VERSION 5.8 ;
BUSBITCHARS "[]" ;
DIVIDERCHAR "/" ;
UNITS
    DATABASE MICRONS 1000 ;
END UNITS

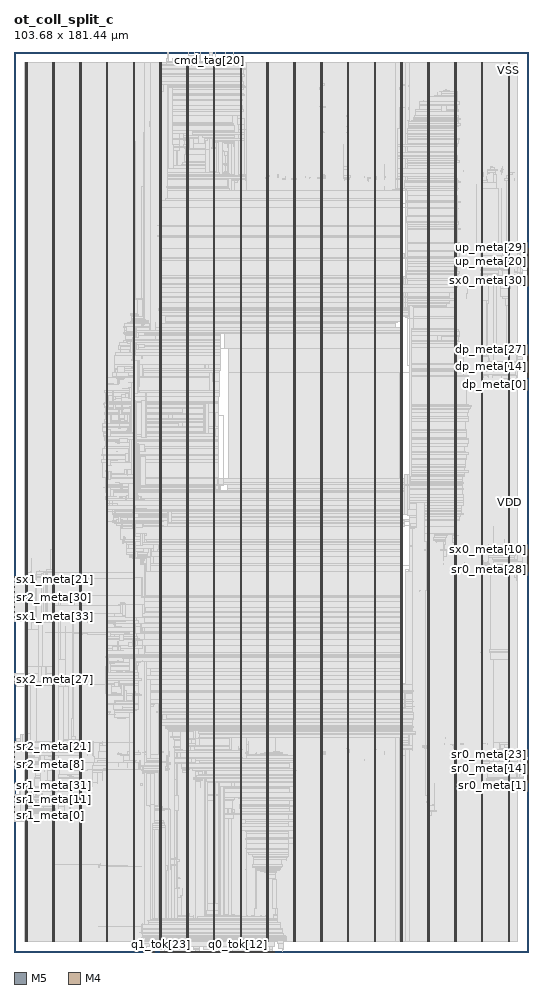
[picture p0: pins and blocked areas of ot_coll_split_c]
MACRO ot_coll_split_c
  FOREIGN ot_coll_split_c 0 0 ;
  CLASS BLOCK ;
  SIZE 103.68 BY 181.44 ;
  PIN clk
    DIRECTION INPUT ;
    USE SIGNAL ;
    PORT
      LAYER M5 ;
        RECT  36.144 181.356 36.168 181.44 ;
    END
  END clk
  PIN cmd_free
    DIRECTION OUTPUT ;
    USE SIGNAL ;
    PORT
      LAYER M5 ;
        RECT  36.288 181.356 36.312 181.44 ;
    END
  END cmd_free
  PIN cmd_mode
    DIRECTION INPUT ;
    USE SIGNAL ;
    PORT
      LAYER M5 ;
        RECT  36.432 181.356 36.456 181.44 ;
    END
  END cmd_mode
  PIN cmd_tag[0]
    DIRECTION INPUT ;
    USE SIGNAL ;
    PORT
      LAYER M5 ;
        RECT  36.576 181.356 36.6 181.44 ;
    END
  END cmd_tag[0]
  PIN cmd_tag[10]
    DIRECTION INPUT ;
    USE SIGNAL ;
    PORT
      LAYER M5 ;
        RECT  38.016 181.356 38.04 181.44 ;
    END
  END cmd_tag[10]
  PIN cmd_tag[11]
    DIRECTION INPUT ;
    USE SIGNAL ;
    PORT
      LAYER M5 ;
        RECT  38.16 181.356 38.184 181.44 ;
    END
  END cmd_tag[11]
  PIN cmd_tag[12]
    DIRECTION INPUT ;
    USE SIGNAL ;
    PORT
      LAYER M5 ;
        RECT  38.304 181.356 38.328 181.44 ;
    END
  END cmd_tag[12]
  PIN cmd_tag[13]
    DIRECTION INPUT ;
    USE SIGNAL ;
    PORT
      LAYER M5 ;
        RECT  38.448 181.356 38.472 181.44 ;
    END
  END cmd_tag[13]
  PIN cmd_tag[14]
    DIRECTION INPUT ;
    USE SIGNAL ;
    PORT
      LAYER M5 ;
        RECT  38.592 181.356 38.616 181.44 ;
    END
  END cmd_tag[14]
  PIN cmd_tag[15]
    DIRECTION INPUT ;
    USE SIGNAL ;
    PORT
      LAYER M5 ;
        RECT  38.736 181.356 38.76 181.44 ;
    END
  END cmd_tag[15]
  PIN cmd_tag[16]
    DIRECTION INPUT ;
    USE SIGNAL ;
    PORT
      LAYER M5 ;
        RECT  38.88 181.356 38.904 181.44 ;
    END
  END cmd_tag[16]
  PIN cmd_tag[17]
    DIRECTION INPUT ;
    USE SIGNAL ;
    PORT
      LAYER M5 ;
        RECT  39.024 181.356 39.048 181.44 ;
    END
  END cmd_tag[17]
  PIN cmd_tag[18]
    DIRECTION INPUT ;
    USE SIGNAL ;
    PORT
      LAYER M5 ;
        RECT  39.168 181.356 39.192 181.44 ;
    END
  END cmd_tag[18]
  PIN cmd_tag[19]
    DIRECTION INPUT ;
    USE SIGNAL ;
    PORT
      LAYER M5 ;
        RECT  39.312 181.356 39.336 181.44 ;
    END
  END cmd_tag[19]
  PIN cmd_tag[1]
    DIRECTION INPUT ;
    USE SIGNAL ;
    PORT
      LAYER M5 ;
        RECT  36.72 181.356 36.744 181.44 ;
    END
  END cmd_tag[1]
  PIN cmd_tag[20]
    DIRECTION INPUT ;
    USE SIGNAL ;
    PORT
      LAYER M5 ;
        RECT  39.456 181.356 39.48 181.44 ;
    END
  END cmd_tag[20]
  PIN cmd_tag[21]
    DIRECTION INPUT ;
    USE SIGNAL ;
    PORT
      LAYER M5 ;
        RECT  39.6 181.356 39.624 181.44 ;
    END
  END cmd_tag[21]
  PIN cmd_tag[22]
    DIRECTION INPUT ;
    USE SIGNAL ;
    PORT
      LAYER M5 ;
        RECT  39.744 181.356 39.768 181.44 ;
    END
  END cmd_tag[22]
  PIN cmd_tag[23]
    DIRECTION INPUT ;
    USE SIGNAL ;
    PORT
      LAYER M5 ;
        RECT  39.888 181.356 39.912 181.44 ;
    END
  END cmd_tag[23]
  PIN cmd_tag[24]
    DIRECTION INPUT ;
    USE SIGNAL ;
    PORT
      LAYER M5 ;
        RECT  40.032 181.356 40.056 181.44 ;
    END
  END cmd_tag[24]
  PIN cmd_tag[25]
    DIRECTION INPUT ;
    USE SIGNAL ;
    PORT
      LAYER M5 ;
        RECT  40.176 181.356 40.2 181.44 ;
    END
  END cmd_tag[25]
  PIN cmd_tag[26]
    DIRECTION INPUT ;
    USE SIGNAL ;
    PORT
      LAYER M5 ;
        RECT  40.32 181.356 40.344 181.44 ;
    END
  END cmd_tag[26]
  PIN cmd_tag[27]
    DIRECTION INPUT ;
    USE SIGNAL ;
    PORT
      LAYER M5 ;
        RECT  40.464 181.356 40.488 181.44 ;
    END
  END cmd_tag[27]
  PIN cmd_tag[28]
    DIRECTION INPUT ;
    USE SIGNAL ;
    PORT
      LAYER M5 ;
        RECT  40.608 181.356 40.632 181.44 ;
    END
  END cmd_tag[28]
  PIN cmd_tag[29]
    DIRECTION INPUT ;
    USE SIGNAL ;
    PORT
      LAYER M5 ;
        RECT  31.536 181.356 31.56 181.44 ;
    END
  END cmd_tag[29]
  PIN cmd_tag[2]
    DIRECTION INPUT ;
    USE SIGNAL ;
    PORT
      LAYER M5 ;
        RECT  36.864 181.356 36.888 181.44 ;
    END
  END cmd_tag[2]
  PIN cmd_tag[30]
    DIRECTION INPUT ;
    USE SIGNAL ;
    PORT
      LAYER M5 ;
        RECT  31.68 181.356 31.704 181.44 ;
    END
  END cmd_tag[30]
  PIN cmd_tag[31]
    DIRECTION INPUT ;
    USE SIGNAL ;
    PORT
      LAYER M5 ;
        RECT  31.824 181.356 31.848 181.44 ;
    END
  END cmd_tag[31]
  PIN cmd_tag[3]
    DIRECTION INPUT ;
    USE SIGNAL ;
    PORT
      LAYER M5 ;
        RECT  37.008 181.356 37.032 181.44 ;
    END
  END cmd_tag[3]
  PIN cmd_tag[4]
    DIRECTION INPUT ;
    USE SIGNAL ;
    PORT
      LAYER M5 ;
        RECT  37.152 181.356 37.176 181.44 ;
    END
  END cmd_tag[4]
  PIN cmd_tag[5]
    DIRECTION INPUT ;
    USE SIGNAL ;
    PORT
      LAYER M5 ;
        RECT  37.296 181.356 37.32 181.44 ;
    END
  END cmd_tag[5]
  PIN cmd_tag[6]
    DIRECTION INPUT ;
    USE SIGNAL ;
    PORT
      LAYER M5 ;
        RECT  37.44 181.356 37.464 181.44 ;
    END
  END cmd_tag[6]
  PIN cmd_tag[7]
    DIRECTION INPUT ;
    USE SIGNAL ;
    PORT
      LAYER M5 ;
        RECT  37.584 181.356 37.608 181.44 ;
    END
  END cmd_tag[7]
  PIN cmd_tag[8]
    DIRECTION INPUT ;
    USE SIGNAL ;
    PORT
      LAYER M5 ;
        RECT  37.728 181.356 37.752 181.44 ;
    END
  END cmd_tag[8]
  PIN cmd_tag[9]
    DIRECTION INPUT ;
    USE SIGNAL ;
    PORT
      LAYER M5 ;
        RECT  37.872 181.356 37.896 181.44 ;
    END
  END cmd_tag[9]
  PIN cmd_v
    DIRECTION INPUT ;
    USE SIGNAL ;
    PORT
      LAYER M5 ;
        RECT  31.968 181.356 31.992 181.44 ;
    END
  END cmd_v
  PIN cmd_words[0]
    DIRECTION INPUT ;
    USE SIGNAL ;
    PORT
      LAYER M5 ;
        RECT  32.112 181.356 32.136 181.44 ;
    END
  END cmd_words[0]
  PIN cmd_words[10]
    DIRECTION INPUT ;
    USE SIGNAL ;
    PORT
      LAYER M5 ;
        RECT  33.552 181.356 33.576 181.44 ;
    END
  END cmd_words[10]
  PIN cmd_words[11]
    DIRECTION INPUT ;
    USE SIGNAL ;
    PORT
      LAYER M5 ;
        RECT  33.696 181.356 33.72 181.44 ;
    END
  END cmd_words[11]
  PIN cmd_words[12]
    DIRECTION INPUT ;
    USE SIGNAL ;
    PORT
      LAYER M5 ;
        RECT  33.84 181.356 33.864 181.44 ;
    END
  END cmd_words[12]
  PIN cmd_words[13]
    DIRECTION INPUT ;
    USE SIGNAL ;
    PORT
      LAYER M5 ;
        RECT  33.984 181.356 34.008 181.44 ;
    END
  END cmd_words[13]
  PIN cmd_words[14]
    DIRECTION INPUT ;
    USE SIGNAL ;
    PORT
      LAYER M5 ;
        RECT  34.128 181.356 34.152 181.44 ;
    END
  END cmd_words[14]
  PIN cmd_words[15]
    DIRECTION INPUT ;
    USE SIGNAL ;
    PORT
      LAYER M5 ;
        RECT  34.272 181.356 34.296 181.44 ;
    END
  END cmd_words[15]
  PIN cmd_words[1]
    DIRECTION INPUT ;
    USE SIGNAL ;
    PORT
      LAYER M5 ;
        RECT  32.256 181.356 32.28 181.44 ;
    END
  END cmd_words[1]
  PIN cmd_words[2]
    DIRECTION INPUT ;
    USE SIGNAL ;
    PORT
      LAYER M5 ;
        RECT  32.4 181.356 32.424 181.44 ;
    END
  END cmd_words[2]
  PIN cmd_words[3]
    DIRECTION INPUT ;
    USE SIGNAL ;
    PORT
      LAYER M5 ;
        RECT  32.544 181.356 32.568 181.44 ;
    END
  END cmd_words[3]
  PIN cmd_words[4]
    DIRECTION INPUT ;
    USE SIGNAL ;
    PORT
      LAYER M5 ;
        RECT  32.688 181.356 32.712 181.44 ;
    END
  END cmd_words[4]
  PIN cmd_words[5]
    DIRECTION INPUT ;
    USE SIGNAL ;
    PORT
      LAYER M5 ;
        RECT  32.832 181.356 32.856 181.44 ;
    END
  END cmd_words[5]
  PIN cmd_words[6]
    DIRECTION INPUT ;
    USE SIGNAL ;
    PORT
      LAYER M5 ;
        RECT  32.976 181.356 33 181.44 ;
    END
  END cmd_words[6]
  PIN cmd_words[7]
    DIRECTION INPUT ;
    USE SIGNAL ;
    PORT
      LAYER M5 ;
        RECT  33.12 181.356 33.144 181.44 ;
    END
  END cmd_words[7]
  PIN cmd_words[8]
    DIRECTION INPUT ;
    USE SIGNAL ;
    PORT
      LAYER M5 ;
        RECT  33.264 181.356 33.288 181.44 ;
    END
  END cmd_words[8]
  PIN cmd_words[9]
    DIRECTION INPUT ;
    USE SIGNAL ;
    PORT
      LAYER M5 ;
        RECT  33.408 181.356 33.432 181.44 ;
    END
  END cmd_words[9]
  PIN die_ps
    DIRECTION INPUT ;
    USE SIGNAL ;
    PORT
      LAYER M5 ;
        RECT  34.416 181.356 34.44 181.44 ;
    END
  END die_ps
  PIN dp_meta[0]
    DIRECTION INPUT ;
    USE SIGNAL ;
    PORT
      LAYER M4 ;
        RECT  103.596 115.92 103.68 115.944 ;
    END
  END dp_meta[0]
  PIN dp_meta[10]
    DIRECTION INPUT ;
    USE SIGNAL ;
    PORT
      LAYER M4 ;
        RECT  103.596 117.36 103.68 117.384 ;
    END
  END dp_meta[10]
  PIN dp_meta[11]
    DIRECTION INPUT ;
    USE SIGNAL ;
    PORT
      LAYER M4 ;
        RECT  103.596 117.504 103.68 117.528 ;
    END
  END dp_meta[11]
  PIN dp_meta[12]
    DIRECTION INPUT ;
    USE SIGNAL ;
    PORT
      LAYER M4 ;
        RECT  103.596 117.648 103.68 117.672 ;
    END
  END dp_meta[12]
  PIN dp_meta[13]
    DIRECTION INPUT ;
    USE SIGNAL ;
    PORT
      LAYER M4 ;
        RECT  103.596 117.792 103.68 117.816 ;
    END
  END dp_meta[13]
  PIN dp_meta[14]
    DIRECTION INPUT ;
    USE SIGNAL ;
    PORT
      LAYER M4 ;
        RECT  103.596 117.936 103.68 117.96 ;
    END
  END dp_meta[14]
  PIN dp_meta[15]
    DIRECTION INPUT ;
    USE SIGNAL ;
    PORT
      LAYER M4 ;
        RECT  103.596 118.08 103.68 118.104 ;
    END
  END dp_meta[15]
  PIN dp_meta[16]
    DIRECTION INPUT ;
    USE SIGNAL ;
    PORT
      LAYER M4 ;
        RECT  103.596 118.224 103.68 118.248 ;
    END
  END dp_meta[16]
  PIN dp_meta[17]
    DIRECTION INPUT ;
    USE SIGNAL ;
    PORT
      LAYER M4 ;
        RECT  103.596 118.368 103.68 118.392 ;
    END
  END dp_meta[17]
  PIN dp_meta[18]
    DIRECTION INPUT ;
    USE SIGNAL ;
    PORT
      LAYER M4 ;
        RECT  103.596 118.512 103.68 118.536 ;
    END
  END dp_meta[18]
  PIN dp_meta[19]
    DIRECTION INPUT ;
    USE SIGNAL ;
    PORT
      LAYER M4 ;
        RECT  103.596 118.656 103.68 118.68 ;
    END
  END dp_meta[19]
  PIN dp_meta[1]
    DIRECTION INPUT ;
    USE SIGNAL ;
    PORT
      LAYER M4 ;
        RECT  103.596 116.064 103.68 116.088 ;
    END
  END dp_meta[1]
  PIN dp_meta[20]
    DIRECTION INPUT ;
    USE SIGNAL ;
    PORT
      LAYER M4 ;
        RECT  103.596 118.8 103.68 118.824 ;
    END
  END dp_meta[20]
  PIN dp_meta[21]
    DIRECTION INPUT ;
    USE SIGNAL ;
    PORT
      LAYER M4 ;
        RECT  103.596 118.944 103.68 118.968 ;
    END
  END dp_meta[21]
  PIN dp_meta[22]
    DIRECTION INPUT ;
    USE SIGNAL ;
    PORT
      LAYER M4 ;
        RECT  103.596 119.088 103.68 119.112 ;
    END
  END dp_meta[22]
  PIN dp_meta[23]
    DIRECTION INPUT ;
    USE SIGNAL ;
    PORT
      LAYER M4 ;
        RECT  103.596 119.232 103.68 119.256 ;
    END
  END dp_meta[23]
  PIN dp_meta[24]
    DIRECTION INPUT ;
    USE SIGNAL ;
    PORT
      LAYER M4 ;
        RECT  103.596 119.376 103.68 119.4 ;
    END
  END dp_meta[24]
  PIN dp_meta[25]
    DIRECTION INPUT ;
    USE SIGNAL ;
    PORT
      LAYER M4 ;
        RECT  103.596 119.52 103.68 119.544 ;
    END
  END dp_meta[25]
  PIN dp_meta[26]
    DIRECTION INPUT ;
    USE SIGNAL ;
    PORT
      LAYER M4 ;
        RECT  103.596 119.664 103.68 119.688 ;
    END
  END dp_meta[26]
  PIN dp_meta[27]
    DIRECTION INPUT ;
    USE SIGNAL ;
    PORT
      LAYER M4 ;
        RECT  103.596 119.808 103.68 119.832 ;
    END
  END dp_meta[27]
  PIN dp_meta[28]
    DIRECTION INPUT ;
    USE SIGNAL ;
    PORT
      LAYER M4 ;
        RECT  103.596 119.952 103.68 119.976 ;
    END
  END dp_meta[28]
  PIN dp_meta[29]
    DIRECTION INPUT ;
    USE SIGNAL ;
    PORT
      LAYER M4 ;
        RECT  103.596 120.096 103.68 120.12 ;
    END
  END dp_meta[29]
  PIN dp_meta[2]
    DIRECTION INPUT ;
    USE SIGNAL ;
    PORT
      LAYER M4 ;
        RECT  103.596 116.208 103.68 116.232 ;
    END
  END dp_meta[2]
  PIN dp_meta[30]
    DIRECTION INPUT ;
    USE SIGNAL ;
    PORT
      LAYER M4 ;
        RECT  103.596 120.24 103.68 120.264 ;
    END
  END dp_meta[30]
  PIN dp_meta[31]
    DIRECTION INPUT ;
    USE SIGNAL ;
    PORT
      LAYER M4 ;
        RECT  103.596 120.384 103.68 120.408 ;
    END
  END dp_meta[31]
  PIN dp_meta[32]
    DIRECTION INPUT ;
    USE SIGNAL ;
    PORT
      LAYER M4 ;
        RECT  103.596 34.128 103.68 34.152 ;
    END
  END dp_meta[32]
  PIN dp_meta[33]
    DIRECTION INPUT ;
    USE SIGNAL ;
    PORT
      LAYER M4 ;
        RECT  103.596 34.272 103.68 34.296 ;
    END
  END dp_meta[33]
  PIN dp_meta[3]
    DIRECTION INPUT ;
    USE SIGNAL ;
    PORT
      LAYER M4 ;
        RECT  103.596 116.352 103.68 116.376 ;
    END
  END dp_meta[3]
  PIN dp_meta[4]
    DIRECTION INPUT ;
    USE SIGNAL ;
    PORT
      LAYER M4 ;
        RECT  103.596 116.496 103.68 116.52 ;
    END
  END dp_meta[4]
  PIN dp_meta[5]
    DIRECTION INPUT ;
    USE SIGNAL ;
    PORT
      LAYER M4 ;
        RECT  103.596 116.64 103.68 116.664 ;
    END
  END dp_meta[5]
  PIN dp_meta[6]
    DIRECTION INPUT ;
    USE SIGNAL ;
    PORT
      LAYER M4 ;
        RECT  103.596 116.784 103.68 116.808 ;
    END
  END dp_meta[6]
  PIN dp_meta[7]
    DIRECTION INPUT ;
    USE SIGNAL ;
    PORT
      LAYER M4 ;
        RECT  103.596 116.928 103.68 116.952 ;
    END
  END dp_meta[7]
  PIN dp_meta[8]
    DIRECTION INPUT ;
    USE SIGNAL ;
    PORT
      LAYER M4 ;
        RECT  103.596 117.072 103.68 117.096 ;
    END
  END dp_meta[8]
  PIN dp_meta[9]
    DIRECTION INPUT ;
    USE SIGNAL ;
    PORT
      LAYER M4 ;
        RECT  103.596 117.216 103.68 117.24 ;
    END
  END dp_meta[9]
  PIN dp_valid
    DIRECTION INPUT ;
    USE SIGNAL ;
    PORT
      LAYER M4 ;
        RECT  103.596 34.416 103.68 34.44 ;
    END
  END dp_valid
  PIN dr_meta[0]
    DIRECTION INPUT ;
    USE SIGNAL ;
    PORT
      LAYER M4 ;
        RECT  103.596 34.56 103.68 34.584 ;
    END
  END dr_meta[0]
  PIN dr_meta[1]
    DIRECTION INPUT ;
    USE SIGNAL ;
    PORT
      LAYER M4 ;
        RECT  103.596 34.704 103.68 34.728 ;
    END
  END dr_meta[1]
  PIN dr_valid
    DIRECTION INPUT ;
    USE SIGNAL ;
    PORT
      LAYER M4 ;
        RECT  103.596 34.848 103.68 34.872 ;
    END
  END dr_valid
  PIN fault
    DIRECTION OUTPUT ;
    USE SIGNAL ;
    PORT
      LAYER M5 ;
        RECT  34.56 181.356 34.584 181.44 ;
    END
  END fault
  PIN fault_code[0]
    DIRECTION OUTPUT ;
    USE SIGNAL ;
    PORT
      LAYER M5 ;
        RECT  34.704 181.356 34.728 181.44 ;
    END
  END fault_code[0]
  PIN fault_code[1]
    DIRECTION OUTPUT ;
    USE SIGNAL ;
    PORT
      LAYER M5 ;
        RECT  34.848 181.356 34.872 181.44 ;
    END
  END fault_code[1]
  PIN fault_code[2]
    DIRECTION OUTPUT ;
    USE SIGNAL ;
    PORT
      LAYER M5 ;
        RECT  34.992 181.356 35.016 181.44 ;
    END
  END fault_code[2]
  PIN fault_code[3]
    DIRECTION OUTPUT ;
    USE SIGNAL ;
    PORT
      LAYER M5 ;
        RECT  35.136 181.356 35.16 181.44 ;
    END
  END fault_code[3]
  PIN fault_code[4]
    DIRECTION OUTPUT ;
    USE SIGNAL ;
    PORT
      LAYER M5 ;
        RECT  35.28 181.356 35.304 181.44 ;
    END
  END fault_code[4]
  PIN in_last
    DIRECTION INPUT ;
    USE SIGNAL ;
    PORT
      LAYER M5 ;
        RECT  35.424 181.356 35.448 181.44 ;
    END
  END in_last
  PIN in_mode
    DIRECTION INPUT ;
    USE SIGNAL ;
    PORT
      LAYER M5 ;
        RECT  35.568 181.356 35.592 181.44 ;
    END
  END in_mode
  PIN in_tag[0]
    DIRECTION INPUT ;
    USE SIGNAL ;
    PORT
      LAYER M5 ;
        RECT  35.712 181.356 35.736 181.44 ;
    END
  END in_tag[0]
  PIN in_tag[10]
    DIRECTION INPUT ;
    USE SIGNAL ;
    PORT
      LAYER M5 ;
        RECT  41.76 181.356 41.784 181.44 ;
    END
  END in_tag[10]
  PIN in_tag[11]
    DIRECTION INPUT ;
    USE SIGNAL ;
    PORT
      LAYER M5 ;
        RECT  41.904 181.356 41.928 181.44 ;
    END
  END in_tag[11]
  PIN in_tag[12]
    DIRECTION INPUT ;
    USE SIGNAL ;
    PORT
      LAYER M5 ;
        RECT  42.048 181.356 42.072 181.44 ;
    END
  END in_tag[12]
  PIN in_tag[13]
    DIRECTION INPUT ;
    USE SIGNAL ;
    PORT
      LAYER M5 ;
        RECT  42.192 181.356 42.216 181.44 ;
    END
  END in_tag[13]
  PIN in_tag[14]
    DIRECTION INPUT ;
    USE SIGNAL ;
    PORT
      LAYER M5 ;
        RECT  42.336 181.356 42.36 181.44 ;
    END
  END in_tag[14]
  PIN in_tag[15]
    DIRECTION INPUT ;
    USE SIGNAL ;
    PORT
      LAYER M5 ;
        RECT  42.48 181.356 42.504 181.44 ;
    END
  END in_tag[15]
  PIN in_tag[16]
    DIRECTION INPUT ;
    USE SIGNAL ;
    PORT
      LAYER M5 ;
        RECT  42.624 181.356 42.648 181.44 ;
    END
  END in_tag[16]
  PIN in_tag[17]
    DIRECTION INPUT ;
    USE SIGNAL ;
    PORT
      LAYER M5 ;
        RECT  42.768 181.356 42.792 181.44 ;
    END
  END in_tag[17]
  PIN in_tag[18]
    DIRECTION INPUT ;
    USE SIGNAL ;
    PORT
      LAYER M5 ;
        RECT  42.912 181.356 42.936 181.44 ;
    END
  END in_tag[18]
  PIN in_tag[19]
    DIRECTION INPUT ;
    USE SIGNAL ;
    PORT
      LAYER M5 ;
        RECT  43.056 181.356 43.08 181.44 ;
    END
  END in_tag[19]
  PIN in_tag[1]
    DIRECTION INPUT ;
    USE SIGNAL ;
    PORT
      LAYER M5 ;
        RECT  35.856 181.356 35.88 181.44 ;
    END
  END in_tag[1]
  PIN in_tag[20]
    DIRECTION INPUT ;
    USE SIGNAL ;
    PORT
      LAYER M5 ;
        RECT  43.2 181.356 43.224 181.44 ;
    END
  END in_tag[20]
  PIN in_tag[21]
    DIRECTION INPUT ;
    USE SIGNAL ;
    PORT
      LAYER M5 ;
        RECT  43.344 181.356 43.368 181.44 ;
    END
  END in_tag[21]
  PIN in_tag[22]
    DIRECTION INPUT ;
    USE SIGNAL ;
    PORT
      LAYER M5 ;
        RECT  43.488 181.356 43.512 181.44 ;
    END
  END in_tag[22]
  PIN in_tag[23]
    DIRECTION INPUT ;
    USE SIGNAL ;
    PORT
      LAYER M5 ;
        RECT  43.632 181.356 43.656 181.44 ;
    END
  END in_tag[23]
  PIN in_tag[24]
    DIRECTION INPUT ;
    USE SIGNAL ;
    PORT
      LAYER M5 ;
        RECT  43.776 181.356 43.8 181.44 ;
    END
  END in_tag[24]
  PIN in_tag[25]
    DIRECTION INPUT ;
    USE SIGNAL ;
    PORT
      LAYER M5 ;
        RECT  43.92 181.356 43.944 181.44 ;
    END
  END in_tag[25]
  PIN in_tag[26]
    DIRECTION INPUT ;
    USE SIGNAL ;
    PORT
      LAYER M5 ;
        RECT  44.064 181.356 44.088 181.44 ;
    END
  END in_tag[26]
  PIN in_tag[27]
    DIRECTION INPUT ;
    USE SIGNAL ;
    PORT
      LAYER M5 ;
        RECT  44.208 181.356 44.232 181.44 ;
    END
  END in_tag[27]
  PIN in_tag[28]
    DIRECTION INPUT ;
    USE SIGNAL ;
    PORT
      LAYER M5 ;
        RECT  44.352 181.356 44.376 181.44 ;
    END
  END in_tag[28]
  PIN in_tag[29]
    DIRECTION INPUT ;
    USE SIGNAL ;
    PORT
      LAYER M5 ;
        RECT  44.496 181.356 44.52 181.44 ;
    END
  END in_tag[29]
  PIN in_tag[2]
    DIRECTION INPUT ;
    USE SIGNAL ;
    PORT
      LAYER M5 ;
        RECT  36 181.356 36.024 181.44 ;
    END
  END in_tag[2]
  PIN in_tag[30]
    DIRECTION INPUT ;
    USE SIGNAL ;
    PORT
      LAYER M5 ;
        RECT  44.64 181.356 44.664 181.44 ;
    END
  END in_tag[30]
  PIN in_tag[31]
    DIRECTION INPUT ;
    USE SIGNAL ;
    PORT
      LAYER M5 ;
        RECT  44.784 181.356 44.808 181.44 ;
    END
  END in_tag[31]
  PIN in_tag[3]
    DIRECTION INPUT ;
    USE SIGNAL ;
    PORT
      LAYER M5 ;
        RECT  40.752 181.356 40.776 181.44 ;
    END
  END in_tag[3]
  PIN in_tag[4]
    DIRECTION INPUT ;
    USE SIGNAL ;
    PORT
      LAYER M5 ;
        RECT  40.896 181.356 40.92 181.44 ;
    END
  END in_tag[4]
  PIN in_tag[5]
    DIRECTION INPUT ;
    USE SIGNAL ;
    PORT
      LAYER M5 ;
        RECT  41.04 181.356 41.064 181.44 ;
    END
  END in_tag[5]
  PIN in_tag[6]
    DIRECTION INPUT ;
    USE SIGNAL ;
    PORT
      LAYER M5 ;
        RECT  41.184 181.356 41.208 181.44 ;
    END
  END in_tag[6]
  PIN in_tag[7]
    DIRECTION INPUT ;
    USE SIGNAL ;
    PORT
      LAYER M5 ;
        RECT  41.328 181.356 41.352 181.44 ;
    END
  END in_tag[7]
  PIN in_tag[8]
    DIRECTION INPUT ;
    USE SIGNAL ;
    PORT
      LAYER M5 ;
        RECT  41.472 181.356 41.496 181.44 ;
    END
  END in_tag[8]
  PIN in_tag[9]
    DIRECTION INPUT ;
    USE SIGNAL ;
    PORT
      LAYER M5 ;
        RECT  41.616 181.356 41.64 181.44 ;
    END
  END in_tag[9]
  PIN in_valid
    DIRECTION INPUT ;
    USE SIGNAL ;
    PORT
      LAYER M5 ;
        RECT  44.928 181.356 44.952 181.44 ;
    END
  END in_valid
  PIN out_err
    DIRECTION OUTPUT ;
    USE SIGNAL ;
    PORT
      LAYER M5 ;
        RECT  45.072 181.356 45.096 181.44 ;
    END
  END out_err
  PIN out_last
    DIRECTION OUTPUT ;
    USE SIGNAL ;
    PORT
      LAYER M5 ;
        RECT  45.216 181.356 45.24 181.44 ;
    END
  END out_last
  PIN out_rank[0]
    DIRECTION OUTPUT ;
    USE SIGNAL ;
    PORT
      LAYER M5 ;
        RECT  30.528 181.356 30.552 181.44 ;
    END
  END out_rank[0]
  PIN out_rank[1]
    DIRECTION OUTPUT ;
    USE SIGNAL ;
    PORT
      LAYER M5 ;
        RECT  30.672 181.356 30.696 181.44 ;
    END
  END out_rank[1]
  PIN out_rank[2]
    DIRECTION OUTPUT ;
    USE SIGNAL ;
    PORT
      LAYER M5 ;
        RECT  30.816 181.356 30.84 181.44 ;
    END
  END out_rank[2]
  PIN out_valid
    DIRECTION OUTPUT ;
    USE SIGNAL ;
    PORT
      LAYER M5 ;
        RECT  30.96 181.356 30.984 181.44 ;
    END
  END out_valid
  PIN pkg_s[0]
    DIRECTION INPUT ;
    USE SIGNAL ;
    PORT
      LAYER M5 ;
        RECT  31.104 181.356 31.128 181.44 ;
    END
  END pkg_s[0]
  PIN pkg_s[1]
    DIRECTION INPUT ;
    USE SIGNAL ;
    PORT
      LAYER M5 ;
        RECT  31.248 181.356 31.272 181.44 ;
    END
  END pkg_s[1]
  PIN q0_tok[0]
    DIRECTION OUTPUT ;
    USE SIGNAL ;
    PORT
      LAYER M5 ;
        RECT  43.344 0 43.368 0.084 ;
    END
  END q0_tok[0]
  PIN q0_tok[10]
    DIRECTION OUTPUT ;
    USE SIGNAL ;
    PORT
      LAYER M5 ;
        RECT  44.784 0 44.808 0.084 ;
    END
  END q0_tok[10]
  PIN q0_tok[11]
    DIRECTION OUTPUT ;
    USE SIGNAL ;
    PORT
      LAYER M5 ;
        RECT  44.928 0 44.952 0.084 ;
    END
  END q0_tok[11]
  PIN q0_tok[12]
    DIRECTION OUTPUT ;
    USE SIGNAL ;
    PORT
      LAYER M5 ;
        RECT  45.072 0 45.096 0.084 ;
    END
  END q0_tok[12]
  PIN q0_tok[13]
    DIRECTION OUTPUT ;
    USE SIGNAL ;
    PORT
      LAYER M5 ;
        RECT  45.216 0 45.24 0.084 ;
    END
  END q0_tok[13]
  PIN q0_tok[14]
    DIRECTION OUTPUT ;
    USE SIGNAL ;
    PORT
      LAYER M5 ;
        RECT  45.36 0 45.384 0.084 ;
    END
  END q0_tok[14]
  PIN q0_tok[15]
    DIRECTION OUTPUT ;
    USE SIGNAL ;
    PORT
      LAYER M5 ;
        RECT  45.504 0 45.528 0.084 ;
    END
  END q0_tok[15]
  PIN q0_tok[16]
    DIRECTION OUTPUT ;
    USE SIGNAL ;
    PORT
      LAYER M5 ;
        RECT  45.648 0 45.672 0.084 ;
    END
  END q0_tok[16]
  PIN q0_tok[17]
    DIRECTION OUTPUT ;
    USE SIGNAL ;
    PORT
      LAYER M5 ;
        RECT  45.792 0 45.816 0.084 ;
    END
  END q0_tok[17]
  PIN q0_tok[18]
    DIRECTION OUTPUT ;
    USE SIGNAL ;
    PORT
      LAYER M5 ;
        RECT  45.936 0 45.96 0.084 ;
    END
  END q0_tok[18]
  PIN q0_tok[19]
    DIRECTION OUTPUT ;
    USE SIGNAL ;
    PORT
      LAYER M5 ;
        RECT  46.08 0 46.104 0.084 ;
    END
  END q0_tok[19]
  PIN q0_tok[1]
    DIRECTION OUTPUT ;
    USE SIGNAL ;
    PORT
      LAYER M5 ;
        RECT  43.488 0 43.512 0.084 ;
    END
  END q0_tok[1]
  PIN q0_tok[20]
    DIRECTION OUTPUT ;
    USE SIGNAL ;
    PORT
      LAYER M5 ;
        RECT  46.224 0 46.248 0.084 ;
    END
  END q0_tok[20]
  PIN q0_tok[21]
    DIRECTION OUTPUT ;
    USE SIGNAL ;
    PORT
      LAYER M5 ;
        RECT  46.368 0 46.392 0.084 ;
    END
  END q0_tok[21]
  PIN q0_tok[22]
    DIRECTION OUTPUT ;
    USE SIGNAL ;
    PORT
      LAYER M5 ;
        RECT  46.512 0 46.536 0.084 ;
    END
  END q0_tok[22]
  PIN q0_tok[23]
    DIRECTION OUTPUT ;
    USE SIGNAL ;
    PORT
      LAYER M5 ;
        RECT  46.656 0 46.68 0.084 ;
    END
  END q0_tok[23]
  PIN q0_tok[24]
    DIRECTION OUTPUT ;
    USE SIGNAL ;
    PORT
      LAYER M5 ;
        RECT  46.8 0 46.824 0.084 ;
    END
  END q0_tok[24]
  PIN q0_tok[25]
    DIRECTION OUTPUT ;
    USE SIGNAL ;
    PORT
      LAYER M5 ;
        RECT  46.944 0 46.968 0.084 ;
    END
  END q0_tok[25]
  PIN q0_tok[26]
    DIRECTION OUTPUT ;
    USE SIGNAL ;
    PORT
      LAYER M5 ;
        RECT  47.088 0 47.112 0.084 ;
    END
  END q0_tok[26]
  PIN q0_tok[27]
    DIRECTION OUTPUT ;
    USE SIGNAL ;
    PORT
      LAYER M5 ;
        RECT  47.232 0 47.256 0.084 ;
    END
  END q0_tok[27]
  PIN q0_tok[28]
    DIRECTION OUTPUT ;
    USE SIGNAL ;
    PORT
      LAYER M5 ;
        RECT  47.376 0 47.4 0.084 ;
    END
  END q0_tok[28]
  PIN q0_tok[29]
    DIRECTION OUTPUT ;
    USE SIGNAL ;
    PORT
      LAYER M5 ;
        RECT  47.52 0 47.544 0.084 ;
    END
  END q0_tok[29]
  PIN q0_tok[2]
    DIRECTION OUTPUT ;
    USE SIGNAL ;
    PORT
      LAYER M5 ;
        RECT  43.632 0 43.656 0.084 ;
    END
  END q0_tok[2]
  PIN q0_tok[30]
    DIRECTION OUTPUT ;
    USE SIGNAL ;
    PORT
      LAYER M5 ;
        RECT  47.664 0 47.688 0.084 ;
    END
  END q0_tok[30]
  PIN q0_tok[31]
    DIRECTION OUTPUT ;
    USE SIGNAL ;
    PORT
      LAYER M5 ;
        RECT  47.808 0 47.832 0.084 ;
    END
  END q0_tok[31]
  PIN q0_tok[32]
    DIRECTION OUTPUT ;
    USE SIGNAL ;
    PORT
      LAYER M5 ;
        RECT  34.128 0 34.152 0.084 ;
    END
  END q0_tok[32]
  PIN q0_tok[33]
    DIRECTION OUTPUT ;
    USE SIGNAL ;
    PORT
      LAYER M5 ;
        RECT  34.272 0 34.296 0.084 ;
    END
  END q0_tok[33]
  PIN q0_tok[34]
    DIRECTION OUTPUT ;
    USE SIGNAL ;
    PORT
      LAYER M5 ;
        RECT  34.416 0 34.44 0.084 ;
    END
  END q0_tok[34]
  PIN q0_tok[35]
    DIRECTION OUTPUT ;
    USE SIGNAL ;
    PORT
      LAYER M5 ;
        RECT  34.56 0 34.584 0.084 ;
    END
  END q0_tok[35]
  PIN q0_tok[36]
    DIRECTION OUTPUT ;
    USE SIGNAL ;
    PORT
      LAYER M5 ;
        RECT  34.704 0 34.728 0.084 ;
    END
  END q0_tok[36]
  PIN q0_tok[37]
    DIRECTION OUTPUT ;
    USE SIGNAL ;
    PORT
      LAYER M5 ;
        RECT  34.848 0 34.872 0.084 ;
    END
  END q0_tok[37]
  PIN q0_tok[38]
    DIRECTION OUTPUT ;
    USE SIGNAL ;
    PORT
      LAYER M5 ;
        RECT  34.992 0 35.016 0.084 ;
    END
  END q0_tok[38]
  PIN q0_tok[39]
    DIRECTION OUTPUT ;
    USE SIGNAL ;
    PORT
      LAYER M5 ;
        RECT  35.136 0 35.16 0.084 ;
    END
  END q0_tok[39]
  PIN q0_tok[3]
    DIRECTION OUTPUT ;
    USE SIGNAL ;
    PORT
      LAYER M5 ;
        RECT  43.776 0 43.8 0.084 ;
    END
  END q0_tok[3]
  PIN q0_tok[40]
    DIRECTION OUTPUT ;
    USE SIGNAL ;
    PORT
      LAYER M5 ;
        RECT  35.28 0 35.304 0.084 ;
    END
  END q0_tok[40]
  PIN q0_tok[41]
    DIRECTION OUTPUT ;
    USE SIGNAL ;
    PORT
      LAYER M5 ;
        RECT  35.424 0 35.448 0.084 ;
    END
  END q0_tok[41]
  PIN q0_tok[4]
    DIRECTION OUTPUT ;
    USE SIGNAL ;
    PORT
      LAYER M5 ;
        RECT  43.92 0 43.944 0.084 ;
    END
  END q0_tok[4]
  PIN q0_tok[5]
    DIRECTION OUTPUT ;
    USE SIGNAL ;
    PORT
      LAYER M5 ;
        RECT  44.064 0 44.088 0.084 ;
    END
  END q0_tok[5]
  PIN q0_tok[6]
    DIRECTION OUTPUT ;
    USE SIGNAL ;
    PORT
      LAYER M5 ;
        RECT  44.208 0 44.232 0.084 ;
    END
  END q0_tok[6]
  PIN q0_tok[7]
    DIRECTION OUTPUT ;
    USE SIGNAL ;
    PORT
      LAYER M5 ;
        RECT  44.352 0 44.376 0.084 ;
    END
  END q0_tok[7]
  PIN q0_tok[8]
    DIRECTION OUTPUT ;
    USE SIGNAL ;
    PORT
      LAYER M5 ;
        RECT  44.496 0 44.52 0.084 ;
    END
  END q0_tok[8]
  PIN q0_tok[9]
    DIRECTION OUTPUT ;
    USE SIGNAL ;
    PORT
      LAYER M5 ;
        RECT  44.64 0 44.664 0.084 ;
    END
  END q0_tok[9]
  PIN q1_tok[0]
    DIRECTION OUTPUT ;
    USE SIGNAL ;
    PORT
      LAYER M5 ;
        RECT  35.568 0 35.592 0.084 ;
    END
  END q1_tok[0]
  PIN q1_tok[10]
    DIRECTION OUTPUT ;
    USE SIGNAL ;
    PORT
      LAYER M5 ;
        RECT  37.008 0 37.032 0.084 ;
    END
  END q1_tok[10]
  PIN q1_tok[11]
    DIRECTION OUTPUT ;
    USE SIGNAL ;
    PORT
      LAYER M5 ;
        RECT  37.152 0 37.176 0.084 ;
    END
  END q1_tok[11]
  PIN q1_tok[12]
    DIRECTION OUTPUT ;
    USE SIGNAL ;
    PORT
      LAYER M5 ;
        RECT  37.296 0 37.32 0.084 ;
    END
  END q1_tok[12]
  PIN q1_tok[13]
    DIRECTION OUTPUT ;
    USE SIGNAL ;
    PORT
      LAYER M5 ;
        RECT  37.44 0 37.464 0.084 ;
    END
  END q1_tok[13]
  PIN q1_tok[14]
    DIRECTION OUTPUT ;
    USE SIGNAL ;
    PORT
      LAYER M5 ;
        RECT  37.584 0 37.608 0.084 ;
    END
  END q1_tok[14]
  PIN q1_tok[15]
    DIRECTION OUTPUT ;
    USE SIGNAL ;
    PORT
      LAYER M5 ;
        RECT  37.728 0 37.752 0.084 ;
    END
  END q1_tok[15]
  PIN q1_tok[16]
    DIRECTION OUTPUT ;
    USE SIGNAL ;
    PORT
      LAYER M5 ;
        RECT  37.872 0 37.896 0.084 ;
    END
  END q1_tok[16]
  PIN q1_tok[17]
    DIRECTION OUTPUT ;
    USE SIGNAL ;
    PORT
      LAYER M5 ;
        RECT  38.016 0 38.04 0.084 ;
    END
  END q1_tok[17]
  PIN q1_tok[18]
    DIRECTION OUTPUT ;
    USE SIGNAL ;
    PORT
      LAYER M5 ;
        RECT  38.16 0 38.184 0.084 ;
    END
  END q1_tok[18]
  PIN q1_tok[19]
    DIRECTION OUTPUT ;
    USE SIGNAL ;
    PORT
      LAYER M5 ;
        RECT  38.304 0 38.328 0.084 ;
    END
  END q1_tok[19]
  PIN q1_tok[1]
    DIRECTION OUTPUT ;
    USE SIGNAL ;
    PORT
      LAYER M5 ;
        RECT  35.712 0 35.736 0.084 ;
    END
  END q1_tok[1]
  PIN q1_tok[20]
    DIRECTION OUTPUT ;
    USE SIGNAL ;
    PORT
      LAYER M5 ;
        RECT  38.448 0 38.472 0.084 ;
    END
  END q1_tok[20]
  PIN q1_tok[21]
    DIRECTION OUTPUT ;
    USE SIGNAL ;
    PORT
      LAYER M5 ;
        RECT  38.592 0 38.616 0.084 ;
    END
  END q1_tok[21]
  PIN q1_tok[22]
    DIRECTION OUTPUT ;
    USE SIGNAL ;
    PORT
      LAYER M5 ;
        RECT  29.52 0 29.544 0.084 ;
    END
  END q1_tok[22]
  PIN q1_tok[23]
    DIRECTION OUTPUT ;
    USE SIGNAL ;
    PORT
      LAYER M5 ;
        RECT  29.664 0 29.688 0.084 ;
    END
  END q1_tok[23]
  PIN q1_tok[24]
    DIRECTION OUTPUT ;
    USE SIGNAL ;
    PORT
      LAYER M5 ;
        RECT  29.808 0 29.832 0.084 ;
    END
  END q1_tok[24]
  PIN q1_tok[25]
    DIRECTION OUTPUT ;
    USE SIGNAL ;
    PORT
      LAYER M5 ;
        RECT  29.952 0 29.976 0.084 ;
    END
  END q1_tok[25]
  PIN q1_tok[26]
    DIRECTION OUTPUT ;
    USE SIGNAL ;
    PORT
      LAYER M5 ;
        RECT  30.096 0 30.12 0.084 ;
    END
  END q1_tok[26]
  PIN q1_tok[27]
    DIRECTION OUTPUT ;
    USE SIGNAL ;
    PORT
      LAYER M5 ;
        RECT  30.24 0 30.264 0.084 ;
    END
  END q1_tok[27]
  PIN q1_tok[28]
    DIRECTION OUTPUT ;
    USE SIGNAL ;
    PORT
      LAYER M5 ;
        RECT  30.384 0 30.408 0.084 ;
    END
  END q1_tok[28]
  PIN q1_tok[29]
    DIRECTION OUTPUT ;
    USE SIGNAL ;
    PORT
      LAYER M5 ;
        RECT  30.528 0 30.552 0.084 ;
    END
  END q1_tok[29]
  PIN q1_tok[2]
    DIRECTION OUTPUT ;
    USE SIGNAL ;
    PORT
      LAYER M5 ;
        RECT  35.856 0 35.88 0.084 ;
    END
  END q1_tok[2]
  PIN q1_tok[30]
    DIRECTION OUTPUT ;
    USE SIGNAL ;
    PORT
      LAYER M5 ;
        RECT  30.672 0 30.696 0.084 ;
    END
  END q1_tok[30]
  PIN q1_tok[31]
    DIRECTION OUTPUT ;
    USE SIGNAL ;
    PORT
      LAYER M5 ;
        RECT  30.816 0 30.84 0.084 ;
    END
  END q1_tok[31]
  PIN q1_tok[32]
    DIRECTION OUTPUT ;
    USE SIGNAL ;
    PORT
      LAYER M5 ;
        RECT  30.96 0 30.984 0.084 ;
    END
  END q1_tok[32]
  PIN q1_tok[33]
    DIRECTION OUTPUT ;
    USE SIGNAL ;
    PORT
      LAYER M5 ;
        RECT  31.104 0 31.128 0.084 ;
    END
  END q1_tok[33]
  PIN q1_tok[34]
    DIRECTION OUTPUT ;
    USE SIGNAL ;
    PORT
      LAYER M5 ;
        RECT  31.248 0 31.272 0.084 ;
    END
  END q1_tok[34]
  PIN q1_tok[35]
    DIRECTION OUTPUT ;
    USE SIGNAL ;
    PORT
      LAYER M5 ;
        RECT  31.392 0 31.416 0.084 ;
    END
  END q1_tok[35]
  PIN q1_tok[36]
    DIRECTION OUTPUT ;
    USE SIGNAL ;
    PORT
      LAYER M5 ;
        RECT  31.536 0 31.56 0.084 ;
    END
  END q1_tok[36]
  PIN q1_tok[37]
    DIRECTION OUTPUT ;
    USE SIGNAL ;
    PORT
      LAYER M5 ;
        RECT  31.68 0 31.704 0.084 ;
    END
  END q1_tok[37]
  PIN q1_tok[38]
    DIRECTION OUTPUT ;
    USE SIGNAL ;
    PORT
      LAYER M5 ;
        RECT  31.824 0 31.848 0.084 ;
    END
  END q1_tok[38]
  PIN q1_tok[39]
    DIRECTION OUTPUT ;
    USE SIGNAL ;
    PORT
      LAYER M5 ;
        RECT  31.968 0 31.992 0.084 ;
    END
  END q1_tok[39]
  PIN q1_tok[3]
    DIRECTION OUTPUT ;
    USE SIGNAL ;
    PORT
      LAYER M5 ;
        RECT  36 0 36.024 0.084 ;
    END
  END q1_tok[3]
  PIN q1_tok[40]
    DIRECTION OUTPUT ;
    USE SIGNAL ;
    PORT
      LAYER M5 ;
        RECT  32.112 0 32.136 0.084 ;
    END
  END q1_tok[40]
  PIN q1_tok[41]
    DIRECTION OUTPUT ;
    USE SIGNAL ;
    PORT
      LAYER M5 ;
        RECT  32.256 0 32.28 0.084 ;
    END
  END q1_tok[41]
  PIN q1_tok[4]
    DIRECTION OUTPUT ;
    USE SIGNAL ;
    PORT
      LAYER M5 ;
        RECT  36.144 0 36.168 0.084 ;
    END
  END q1_tok[4]
  PIN q1_tok[5]
    DIRECTION OUTPUT ;
    USE SIGNAL ;
    PORT
      LAYER M5 ;
        RECT  36.288 0 36.312 0.084 ;
    END
  END q1_tok[5]
  PIN q1_tok[6]
    DIRECTION OUTPUT ;
    USE SIGNAL ;
    PORT
      LAYER M5 ;
        RECT  36.432 0 36.456 0.084 ;
    END
  END q1_tok[6]
  PIN q1_tok[7]
    DIRECTION OUTPUT ;
    USE SIGNAL ;
    PORT
      LAYER M5 ;
        RECT  36.576 0 36.6 0.084 ;
    END
  END q1_tok[7]
  PIN q1_tok[8]
    DIRECTION OUTPUT ;
    USE SIGNAL ;
    PORT
      LAYER M5 ;
        RECT  36.72 0 36.744 0.084 ;
    END
  END q1_tok[8]
  PIN q1_tok[9]
    DIRECTION OUTPUT ;
    USE SIGNAL ;
    PORT
      LAYER M5 ;
        RECT  36.864 0 36.888 0.084 ;
    END
  END q1_tok[9]
  PIN q2_tok[0]
    DIRECTION OUTPUT ;
    USE SIGNAL ;
    PORT
      LAYER M5 ;
        RECT  32.4 0 32.424 0.084 ;
    END
  END q2_tok[0]
  PIN q2_tok[10]
    DIRECTION OUTPUT ;
    USE SIGNAL ;
    PORT
      LAYER M5 ;
        RECT  33.84 0 33.864 0.084 ;
    END
  END q2_tok[10]
  PIN q2_tok[11]
    DIRECTION OUTPUT ;
    USE SIGNAL ;
    PORT
      LAYER M5 ;
        RECT  33.984 0 34.008 0.084 ;
    END
  END q2_tok[11]
  PIN q2_tok[12]
    DIRECTION OUTPUT ;
    USE SIGNAL ;
    PORT
      LAYER M5 ;
        RECT  38.736 0 38.76 0.084 ;
    END
  END q2_tok[12]
  PIN q2_tok[13]
    DIRECTION OUTPUT ;
    USE SIGNAL ;
    PORT
      LAYER M5 ;
        RECT  38.88 0 38.904 0.084 ;
    END
  END q2_tok[13]
  PIN q2_tok[14]
    DIRECTION OUTPUT ;
    USE SIGNAL ;
    PORT
      LAYER M5 ;
        RECT  39.024 0 39.048 0.084 ;
    END
  END q2_tok[14]
  PIN q2_tok[15]
    DIRECTION OUTPUT ;
    USE SIGNAL ;
    PORT
      LAYER M5 ;
        RECT  39.168 0 39.192 0.084 ;
    END
  END q2_tok[15]
  PIN q2_tok[16]
    DIRECTION OUTPUT ;
    USE SIGNAL ;
    PORT
      LAYER M5 ;
        RECT  39.312 0 39.336 0.084 ;
    END
  END q2_tok[16]
  PIN q2_tok[17]
    DIRECTION OUTPUT ;
    USE SIGNAL ;
    PORT
      LAYER M5 ;
        RECT  39.456 0 39.48 0.084 ;
    END
  END q2_tok[17]
  PIN q2_tok[18]
    DIRECTION OUTPUT ;
    USE SIGNAL ;
    PORT
      LAYER M5 ;
        RECT  39.6 0 39.624 0.084 ;
    END
  END q2_tok[18]
  PIN q2_tok[19]
    DIRECTION OUTPUT ;
    USE SIGNAL ;
    PORT
      LAYER M5 ;
        RECT  39.744 0 39.768 0.084 ;
    END
  END q2_tok[19]
  PIN q2_tok[1]
    DIRECTION OUTPUT ;
    USE SIGNAL ;
    PORT
      LAYER M5 ;
        RECT  32.544 0 32.568 0.084 ;
    END
  END q2_tok[1]
  PIN q2_tok[20]
    DIRECTION OUTPUT ;
    USE SIGNAL ;
    PORT
      LAYER M5 ;
        RECT  39.888 0 39.912 0.084 ;
    END
  END q2_tok[20]
  PIN q2_tok[21]
    DIRECTION OUTPUT ;
    USE SIGNAL ;
    PORT
      LAYER M5 ;
        RECT  40.032 0 40.056 0.084 ;
    END
  END q2_tok[21]
  PIN q2_tok[22]
    DIRECTION OUTPUT ;
    USE SIGNAL ;
    PORT
      LAYER M5 ;
        RECT  40.176 0 40.2 0.084 ;
    END
  END q2_tok[22]
  PIN q2_tok[23]
    DIRECTION OUTPUT ;
    USE SIGNAL ;
    PORT
      LAYER M5 ;
        RECT  40.32 0 40.344 0.084 ;
    END
  END q2_tok[23]
  PIN q2_tok[24]
    DIRECTION OUTPUT ;
    USE SIGNAL ;
    PORT
      LAYER M5 ;
        RECT  40.464 0 40.488 0.084 ;
    END
  END q2_tok[24]
  PIN q2_tok[25]
    DIRECTION OUTPUT ;
    USE SIGNAL ;
    PORT
      LAYER M5 ;
        RECT  40.608 0 40.632 0.084 ;
    END
  END q2_tok[25]
  PIN q2_tok[26]
    DIRECTION OUTPUT ;
    USE SIGNAL ;
    PORT
      LAYER M5 ;
        RECT  40.752 0 40.776 0.084 ;
    END
  END q2_tok[26]
  PIN q2_tok[27]
    DIRECTION OUTPUT ;
    USE SIGNAL ;
    PORT
      LAYER M5 ;
        RECT  40.896 0 40.92 0.084 ;
    END
  END q2_tok[27]
  PIN q2_tok[28]
    DIRECTION OUTPUT ;
    USE SIGNAL ;
    PORT
      LAYER M5 ;
        RECT  41.04 0 41.064 0.084 ;
    END
  END q2_tok[28]
  PIN q2_tok[29]
    DIRECTION OUTPUT ;
    USE SIGNAL ;
    PORT
      LAYER M5 ;
        RECT  41.184 0 41.208 0.084 ;
    END
  END q2_tok[29]
  PIN q2_tok[2]
    DIRECTION OUTPUT ;
    USE SIGNAL ;
    PORT
      LAYER M5 ;
        RECT  32.688 0 32.712 0.084 ;
    END
  END q2_tok[2]
  PIN q2_tok[30]
    DIRECTION OUTPUT ;
    USE SIGNAL ;
    PORT
      LAYER M5 ;
        RECT  41.328 0 41.352 0.084 ;
    END
  END q2_tok[30]
  PIN q2_tok[31]
    DIRECTION OUTPUT ;
    USE SIGNAL ;
    PORT
      LAYER M5 ;
        RECT  41.472 0 41.496 0.084 ;
    END
  END q2_tok[31]
  PIN q2_tok[32]
    DIRECTION OUTPUT ;
    USE SIGNAL ;
    PORT
      LAYER M5 ;
        RECT  41.616 0 41.64 0.084 ;
    END
  END q2_tok[32]
  PIN q2_tok[33]
    DIRECTION OUTPUT ;
    USE SIGNAL ;
    PORT
      LAYER M5 ;
        RECT  41.76 0 41.784 0.084 ;
    END
  END q2_tok[33]
  PIN q2_tok[34]
    DIRECTION OUTPUT ;
    USE SIGNAL ;
    PORT
      LAYER M5 ;
        RECT  41.904 0 41.928 0.084 ;
    END
  END q2_tok[34]
  PIN q2_tok[35]
    DIRECTION OUTPUT ;
    USE SIGNAL ;
    PORT
      LAYER M5 ;
        RECT  42.048 0 42.072 0.084 ;
    END
  END q2_tok[35]
  PIN q2_tok[36]
    DIRECTION OUTPUT ;
    USE SIGNAL ;
    PORT
      LAYER M5 ;
        RECT  42.192 0 42.216 0.084 ;
    END
  END q2_tok[36]
  PIN q2_tok[37]
    DIRECTION OUTPUT ;
    USE SIGNAL ;
    PORT
      LAYER M5 ;
        RECT  42.336 0 42.36 0.084 ;
    END
  END q2_tok[37]
  PIN q2_tok[38]
    DIRECTION OUTPUT ;
    USE SIGNAL ;
    PORT
      LAYER M5 ;
        RECT  42.48 0 42.504 0.084 ;
    END
  END q2_tok[38]
  PIN q2_tok[39]
    DIRECTION OUTPUT ;
    USE SIGNAL ;
    PORT
      LAYER M5 ;
        RECT  42.624 0 42.648 0.084 ;
    END
  END q2_tok[39]
  PIN q2_tok[3]
    DIRECTION OUTPUT ;
    USE SIGNAL ;
    PORT
      LAYER M5 ;
        RECT  32.832 0 32.856 0.084 ;
    END
  END q2_tok[3]
  PIN q2_tok[40]
    DIRECTION OUTPUT ;
    USE SIGNAL ;
    PORT
      LAYER M5 ;
        RECT  42.768 0 42.792 0.084 ;
    END
  END q2_tok[40]
  PIN q2_tok[41]
    DIRECTION OUTPUT ;
    USE SIGNAL ;
    PORT
      LAYER M5 ;
        RECT  42.912 0 42.936 0.084 ;
    END
  END q2_tok[41]
  PIN q2_tok[4]
    DIRECTION OUTPUT ;
    USE SIGNAL ;
    PORT
      LAYER M5 ;
        RECT  32.976 0 33 0.084 ;
    END
  END q2_tok[4]
  PIN q2_tok[5]
    DIRECTION OUTPUT ;
    USE SIGNAL ;
    PORT
      LAYER M5 ;
        RECT  33.12 0 33.144 0.084 ;
    END
  END q2_tok[5]
  PIN q2_tok[6]
    DIRECTION OUTPUT ;
    USE SIGNAL ;
    PORT
      LAYER M5 ;
        RECT  33.264 0 33.288 0.084 ;
    END
  END q2_tok[6]
  PIN q2_tok[7]
    DIRECTION OUTPUT ;
    USE SIGNAL ;
    PORT
      LAYER M5 ;
        RECT  33.408 0 33.432 0.084 ;
    END
  END q2_tok[7]
  PIN q2_tok[8]
    DIRECTION OUTPUT ;
    USE SIGNAL ;
    PORT
      LAYER M5 ;
        RECT  33.552 0 33.576 0.084 ;
    END
  END q2_tok[8]
  PIN q2_tok[9]
    DIRECTION OUTPUT ;
    USE SIGNAL ;
    PORT
      LAYER M5 ;
        RECT  33.696 0 33.72 0.084 ;
    END
  END q2_tok[9]
  PIN q3_tok[0]
    DIRECTION OUTPUT ;
    USE SIGNAL ;
    PORT
      LAYER M5 ;
        RECT  43.056 0 43.08 0.084 ;
    END
  END q3_tok[0]
  PIN q3_tok[10]
    DIRECTION OUTPUT ;
    USE SIGNAL ;
    PORT
      LAYER M5 ;
        RECT  49.104 0 49.128 0.084 ;
    END
  END q3_tok[10]
  PIN q3_tok[11]
    DIRECTION OUTPUT ;
    USE SIGNAL ;
    PORT
      LAYER M5 ;
        RECT  49.248 0 49.272 0.084 ;
    END
  END q3_tok[11]
  PIN q3_tok[12]
    DIRECTION OUTPUT ;
    USE SIGNAL ;
    PORT
      LAYER M5 ;
        RECT  49.392 0 49.416 0.084 ;
    END
  END q3_tok[12]
  PIN q3_tok[13]
    DIRECTION OUTPUT ;
    USE SIGNAL ;
    PORT
      LAYER M5 ;
        RECT  49.536 0 49.56 0.084 ;
    END
  END q3_tok[13]
  PIN q3_tok[14]
    DIRECTION OUTPUT ;
    USE SIGNAL ;
    PORT
      LAYER M5 ;
        RECT  49.68 0 49.704 0.084 ;
    END
  END q3_tok[14]
  PIN q3_tok[15]
    DIRECTION OUTPUT ;
    USE SIGNAL ;
    PORT
      LAYER M5 ;
        RECT  49.824 0 49.848 0.084 ;
    END
  END q3_tok[15]
  PIN q3_tok[16]
    DIRECTION OUTPUT ;
    USE SIGNAL ;
    PORT
      LAYER M5 ;
        RECT  49.968 0 49.992 0.084 ;
    END
  END q3_tok[16]
  PIN q3_tok[17]
    DIRECTION OUTPUT ;
    USE SIGNAL ;
    PORT
      LAYER M5 ;
        RECT  50.112 0 50.136 0.084 ;
    END
  END q3_tok[17]
  PIN q3_tok[18]
    DIRECTION OUTPUT ;
    USE SIGNAL ;
    PORT
      LAYER M5 ;
        RECT  50.256 0 50.28 0.084 ;
    END
  END q3_tok[18]
  PIN q3_tok[19]
    DIRECTION OUTPUT ;
    USE SIGNAL ;
    PORT
      LAYER M5 ;
        RECT  50.4 0 50.424 0.084 ;
    END
  END q3_tok[19]
  PIN q3_tok[1]
    DIRECTION OUTPUT ;
    USE SIGNAL ;
    PORT
      LAYER M5 ;
        RECT  43.2 0 43.224 0.084 ;
    END
  END q3_tok[1]
  PIN q3_tok[20]
    DIRECTION OUTPUT ;
    USE SIGNAL ;
    PORT
      LAYER M5 ;
        RECT  50.544 0 50.568 0.084 ;
    END
  END q3_tok[20]
  PIN q3_tok[21]
    DIRECTION OUTPUT ;
    USE SIGNAL ;
    PORT
      LAYER M5 ;
        RECT  50.688 0 50.712 0.084 ;
    END
  END q3_tok[21]
  PIN q3_tok[22]
    DIRECTION OUTPUT ;
    USE SIGNAL ;
    PORT
      LAYER M5 ;
        RECT  50.832 0 50.856 0.084 ;
    END
  END q3_tok[22]
  PIN q3_tok[23]
    DIRECTION OUTPUT ;
    USE SIGNAL ;
    PORT
      LAYER M5 ;
        RECT  50.976 0 51 0.084 ;
    END
  END q3_tok[23]
  PIN q3_tok[24]
    DIRECTION OUTPUT ;
    USE SIGNAL ;
    PORT
      LAYER M5 ;
        RECT  51.12 0 51.144 0.084 ;
    END
  END q3_tok[24]
  PIN q3_tok[25]
    DIRECTION OUTPUT ;
    USE SIGNAL ;
    PORT
      LAYER M5 ;
        RECT  51.264 0 51.288 0.084 ;
    END
  END q3_tok[25]
  PIN q3_tok[26]
    DIRECTION OUTPUT ;
    USE SIGNAL ;
    PORT
      LAYER M5 ;
        RECT  51.408 0 51.432 0.084 ;
    END
  END q3_tok[26]
  PIN q3_tok[27]
    DIRECTION OUTPUT ;
    USE SIGNAL ;
    PORT
      LAYER M5 ;
        RECT  51.552 0 51.576 0.084 ;
    END
  END q3_tok[27]
  PIN q3_tok[28]
    DIRECTION OUTPUT ;
    USE SIGNAL ;
    PORT
      LAYER M5 ;
        RECT  51.696 0 51.72 0.084 ;
    END
  END q3_tok[28]
  PIN q3_tok[29]
    DIRECTION OUTPUT ;
    USE SIGNAL ;
    PORT
      LAYER M5 ;
        RECT  51.84 0 51.864 0.084 ;
    END
  END q3_tok[29]
  PIN q3_tok[2]
    DIRECTION OUTPUT ;
    USE SIGNAL ;
    PORT
      LAYER M5 ;
        RECT  47.952 0 47.976 0.084 ;
    END
  END q3_tok[2]
  PIN q3_tok[30]
    DIRECTION OUTPUT ;
    USE SIGNAL ;
    PORT
      LAYER M5 ;
        RECT  51.984 0 52.008 0.084 ;
    END
  END q3_tok[30]
  PIN q3_tok[31]
    DIRECTION OUTPUT ;
    USE SIGNAL ;
    PORT
      LAYER M5 ;
        RECT  52.128 0 52.152 0.084 ;
    END
  END q3_tok[31]
  PIN q3_tok[32]
    DIRECTION OUTPUT ;
    USE SIGNAL ;
    PORT
      LAYER M5 ;
        RECT  52.272 0 52.296 0.084 ;
    END
  END q3_tok[32]
  PIN q3_tok[33]
    DIRECTION OUTPUT ;
    USE SIGNAL ;
    PORT
      LAYER M5 ;
        RECT  52.416 0 52.44 0.084 ;
    END
  END q3_tok[33]
  PIN q3_tok[34]
    DIRECTION OUTPUT ;
    USE SIGNAL ;
    PORT
      LAYER M5 ;
        RECT  26.064 0 26.088 0.084 ;
    END
  END q3_tok[34]
  PIN q3_tok[35]
    DIRECTION OUTPUT ;
    USE SIGNAL ;
    PORT
      LAYER M5 ;
        RECT  26.208 0 26.232 0.084 ;
    END
  END q3_tok[35]
  PIN q3_tok[36]
    DIRECTION OUTPUT ;
    USE SIGNAL ;
    PORT
      LAYER M5 ;
        RECT  26.352 0 26.376 0.084 ;
    END
  END q3_tok[36]
  PIN q3_tok[37]
    DIRECTION OUTPUT ;
    USE SIGNAL ;
    PORT
      LAYER M5 ;
        RECT  26.496 0 26.52 0.084 ;
    END
  END q3_tok[37]
  PIN q3_tok[38]
    DIRECTION OUTPUT ;
    USE SIGNAL ;
    PORT
      LAYER M5 ;
        RECT  26.64 0 26.664 0.084 ;
    END
  END q3_tok[38]
  PIN q3_tok[39]
    DIRECTION OUTPUT ;
    USE SIGNAL ;
    PORT
      LAYER M5 ;
        RECT  26.784 0 26.808 0.084 ;
    END
  END q3_tok[39]
  PIN q3_tok[3]
    DIRECTION OUTPUT ;
    USE SIGNAL ;
    PORT
      LAYER M5 ;
        RECT  48.096 0 48.12 0.084 ;
    END
  END q3_tok[3]
  PIN q3_tok[40]
    DIRECTION OUTPUT ;
    USE SIGNAL ;
    PORT
      LAYER M5 ;
        RECT  26.928 0 26.952 0.084 ;
    END
  END q3_tok[40]
  PIN q3_tok[41]
    DIRECTION OUTPUT ;
    USE SIGNAL ;
    PORT
      LAYER M5 ;
        RECT  27.072 0 27.096 0.084 ;
    END
  END q3_tok[41]
  PIN q3_tok[4]
    DIRECTION OUTPUT ;
    USE SIGNAL ;
    PORT
      LAYER M5 ;
        RECT  48.24 0 48.264 0.084 ;
    END
  END q3_tok[4]
  PIN q3_tok[5]
    DIRECTION OUTPUT ;
    USE SIGNAL ;
    PORT
      LAYER M5 ;
        RECT  48.384 0 48.408 0.084 ;
    END
  END q3_tok[5]
  PIN q3_tok[6]
    DIRECTION OUTPUT ;
    USE SIGNAL ;
    PORT
      LAYER M5 ;
        RECT  48.528 0 48.552 0.084 ;
    END
  END q3_tok[6]
  PIN q3_tok[7]
    DIRECTION OUTPUT ;
    USE SIGNAL ;
    PORT
      LAYER M5 ;
        RECT  48.672 0 48.696 0.084 ;
    END
  END q3_tok[7]
  PIN q3_tok[8]
    DIRECTION OUTPUT ;
    USE SIGNAL ;
    PORT
      LAYER M5 ;
        RECT  48.816 0 48.84 0.084 ;
    END
  END q3_tok[8]
  PIN q3_tok[9]
    DIRECTION OUTPUT ;
    USE SIGNAL ;
    PORT
      LAYER M5 ;
        RECT  48.96 0 48.984 0.084 ;
    END
  END q3_tok[9]
  PIN q_pe[0]
    DIRECTION INPUT ;
    USE SIGNAL ;
    PORT
      LAYER M5 ;
        RECT  27.216 0 27.24 0.084 ;
    END
  END q_pe[0]
  PIN q_pe[1]
    DIRECTION INPUT ;
    USE SIGNAL ;
    PORT
      LAYER M5 ;
        RECT  27.36 0 27.384 0.084 ;
    END
  END q_pe[1]
  PIN q_pe[2]
    DIRECTION INPUT ;
    USE SIGNAL ;
    PORT
      LAYER M5 ;
        RECT  27.504 0 27.528 0.084 ;
    END
  END q_pe[2]
  PIN q_pe[3]
    DIRECTION INPUT ;
    USE SIGNAL ;
    PORT
      LAYER M5 ;
        RECT  27.648 0 27.672 0.084 ;
    END
  END q_pe[3]
  PIN q_xe[0]
    DIRECTION INPUT ;
    USE SIGNAL ;
    PORT
      LAYER M5 ;
        RECT  27.792 0 27.816 0.084 ;
    END
  END q_xe[0]
  PIN q_xe[1]
    DIRECTION INPUT ;
    USE SIGNAL ;
    PORT
      LAYER M5 ;
        RECT  27.936 0 27.96 0.084 ;
    END
  END q_xe[1]
  PIN q_xe[2]
    DIRECTION INPUT ;
    USE SIGNAL ;
    PORT
      LAYER M5 ;
        RECT  28.08 0 28.104 0.084 ;
    END
  END q_xe[2]
  PIN q_xe[3]
    DIRECTION INPUT ;
    USE SIGNAL ;
    PORT
      LAYER M5 ;
        RECT  28.224 0 28.248 0.084 ;
    END
  END q_xe[3]
  PIN rst_n
    DIRECTION INPUT ;
    USE SIGNAL ;
    PORT
      LAYER M5 ;
        RECT  31.392 181.356 31.416 181.44 ;
    END
  END rst_n
  PIN sr0_meta[0]
    DIRECTION INPUT ;
    USE SIGNAL ;
    PORT
      LAYER M4 ;
        RECT  103.596 34.992 103.68 35.016 ;
    END
  END sr0_meta[0]
  PIN sr0_meta[10]
    DIRECTION INPUT ;
    USE SIGNAL ;
    PORT
      LAYER M4 ;
        RECT  103.596 36.432 103.68 36.456 ;
    END
  END sr0_meta[10]
  PIN sr0_meta[11]
    DIRECTION INPUT ;
    USE SIGNAL ;
    PORT
      LAYER M4 ;
        RECT  103.596 36.576 103.68 36.6 ;
    END
  END sr0_meta[11]
  PIN sr0_meta[12]
    DIRECTION INPUT ;
    USE SIGNAL ;
    PORT
      LAYER M4 ;
        RECT  103.596 36.72 103.68 36.744 ;
    END
  END sr0_meta[12]
  PIN sr0_meta[13]
    DIRECTION INPUT ;
    USE SIGNAL ;
    PORT
      LAYER M4 ;
        RECT  103.596 36.864 103.68 36.888 ;
    END
  END sr0_meta[13]
  PIN sr0_meta[14]
    DIRECTION INPUT ;
    USE SIGNAL ;
    PORT
      LAYER M4 ;
        RECT  103.596 37.008 103.68 37.032 ;
    END
  END sr0_meta[14]
  PIN sr0_meta[15]
    DIRECTION INPUT ;
    USE SIGNAL ;
    PORT
      LAYER M4 ;
        RECT  103.596 37.152 103.68 37.176 ;
    END
  END sr0_meta[15]
  PIN sr0_meta[16]
    DIRECTION INPUT ;
    USE SIGNAL ;
    PORT
      LAYER M4 ;
        RECT  103.596 37.296 103.68 37.32 ;
    END
  END sr0_meta[16]
  PIN sr0_meta[17]
    DIRECTION INPUT ;
    USE SIGNAL ;
    PORT
      LAYER M4 ;
        RECT  103.596 37.44 103.68 37.464 ;
    END
  END sr0_meta[17]
  PIN sr0_meta[18]
    DIRECTION INPUT ;
    USE SIGNAL ;
    PORT
      LAYER M4 ;
        RECT  103.596 37.584 103.68 37.608 ;
    END
  END sr0_meta[18]
  PIN sr0_meta[19]
    DIRECTION INPUT ;
    USE SIGNAL ;
    PORT
      LAYER M4 ;
        RECT  103.596 37.728 103.68 37.752 ;
    END
  END sr0_meta[19]
  PIN sr0_meta[1]
    DIRECTION INPUT ;
    USE SIGNAL ;
    PORT
      LAYER M4 ;
        RECT  103.596 35.136 103.68 35.16 ;
    END
  END sr0_meta[1]
  PIN sr0_meta[20]
    DIRECTION INPUT ;
    USE SIGNAL ;
    PORT
      LAYER M4 ;
        RECT  103.596 37.872 103.68 37.896 ;
    END
  END sr0_meta[20]
  PIN sr0_meta[21]
    DIRECTION INPUT ;
    USE SIGNAL ;
    PORT
      LAYER M4 ;
        RECT  103.596 38.016 103.68 38.04 ;
    END
  END sr0_meta[21]
  PIN sr0_meta[22]
    DIRECTION INPUT ;
    USE SIGNAL ;
    PORT
      LAYER M4 ;
        RECT  103.596 38.16 103.68 38.184 ;
    END
  END sr0_meta[22]
  PIN sr0_meta[23]
    DIRECTION INPUT ;
    USE SIGNAL ;
    PORT
      LAYER M4 ;
        RECT  103.596 38.304 103.68 38.328 ;
    END
  END sr0_meta[23]
  PIN sr0_meta[24]
    DIRECTION INPUT ;
    USE SIGNAL ;
    PORT
      LAYER M4 ;
        RECT  103.596 38.448 103.68 38.472 ;
    END
  END sr0_meta[24]
  PIN sr0_meta[25]
    DIRECTION INPUT ;
    USE SIGNAL ;
    PORT
      LAYER M4 ;
        RECT  103.596 38.592 103.68 38.616 ;
    END
  END sr0_meta[25]
  PIN sr0_meta[26]
    DIRECTION INPUT ;
    USE SIGNAL ;
    PORT
      LAYER M4 ;
        RECT  103.596 76.752 103.68 76.776 ;
    END
  END sr0_meta[26]
  PIN sr0_meta[27]
    DIRECTION INPUT ;
    USE SIGNAL ;
    PORT
      LAYER M4 ;
        RECT  103.596 76.896 103.68 76.92 ;
    END
  END sr0_meta[27]
  PIN sr0_meta[28]
    DIRECTION INPUT ;
    USE SIGNAL ;
    PORT
      LAYER M4 ;
        RECT  103.596 77.04 103.68 77.064 ;
    END
  END sr0_meta[28]
  PIN sr0_meta[29]
    DIRECTION INPUT ;
    USE SIGNAL ;
    PORT
      LAYER M4 ;
        RECT  103.596 77.184 103.68 77.208 ;
    END
  END sr0_meta[29]
  PIN sr0_meta[2]
    DIRECTION INPUT ;
    USE SIGNAL ;
    PORT
      LAYER M4 ;
        RECT  103.596 35.28 103.68 35.304 ;
    END
  END sr0_meta[2]
  PIN sr0_meta[30]
    DIRECTION INPUT ;
    USE SIGNAL ;
    PORT
      LAYER M4 ;
        RECT  103.596 77.328 103.68 77.352 ;
    END
  END sr0_meta[30]
  PIN sr0_meta[31]
    DIRECTION INPUT ;
    USE SIGNAL ;
    PORT
      LAYER M4 ;
        RECT  103.596 77.472 103.68 77.496 ;
    END
  END sr0_meta[31]
  PIN sr0_meta[32]
    DIRECTION INPUT ;
    USE SIGNAL ;
    PORT
      LAYER M4 ;
        RECT  103.596 77.616 103.68 77.64 ;
    END
  END sr0_meta[32]
  PIN sr0_meta[33]
    DIRECTION INPUT ;
    USE SIGNAL ;
    PORT
      LAYER M4 ;
        RECT  103.596 77.76 103.68 77.784 ;
    END
  END sr0_meta[33]
  PIN sr0_meta[3]
    DIRECTION INPUT ;
    USE SIGNAL ;
    PORT
      LAYER M4 ;
        RECT  103.596 35.424 103.68 35.448 ;
    END
  END sr0_meta[3]
  PIN sr0_meta[4]
    DIRECTION INPUT ;
    USE SIGNAL ;
    PORT
      LAYER M4 ;
        RECT  103.596 35.568 103.68 35.592 ;
    END
  END sr0_meta[4]
  PIN sr0_meta[5]
    DIRECTION INPUT ;
    USE SIGNAL ;
    PORT
      LAYER M4 ;
        RECT  103.596 35.712 103.68 35.736 ;
    END
  END sr0_meta[5]
  PIN sr0_meta[6]
    DIRECTION INPUT ;
    USE SIGNAL ;
    PORT
      LAYER M4 ;
        RECT  103.596 35.856 103.68 35.88 ;
    END
  END sr0_meta[6]
  PIN sr0_meta[7]
    DIRECTION INPUT ;
    USE SIGNAL ;
    PORT
      LAYER M4 ;
        RECT  103.596 36 103.68 36.024 ;
    END
  END sr0_meta[7]
  PIN sr0_meta[8]
    DIRECTION INPUT ;
    USE SIGNAL ;
    PORT
      LAYER M4 ;
        RECT  103.596 36.144 103.68 36.168 ;
    END
  END sr0_meta[8]
  PIN sr0_meta[9]
    DIRECTION INPUT ;
    USE SIGNAL ;
    PORT
      LAYER M4 ;
        RECT  103.596 36.288 103.68 36.312 ;
    END
  END sr0_meta[9]
  PIN sr0_valid
    DIRECTION INPUT ;
    USE SIGNAL ;
    PORT
      LAYER M4 ;
        RECT  103.596 77.904 103.68 77.928 ;
    END
  END sr0_valid
  PIN sr1_meta[0]
    DIRECTION INPUT ;
    USE SIGNAL ;
    PORT
      LAYER M4 ;
        RECT  0 27.504 0.084 27.528 ;
    END
  END sr1_meta[0]
  PIN sr1_meta[10]
    DIRECTION INPUT ;
    USE SIGNAL ;
    PORT
      LAYER M4 ;
        RECT  0 28.944 0.084 28.968 ;
    END
  END sr1_meta[10]
  PIN sr1_meta[11]
    DIRECTION INPUT ;
    USE SIGNAL ;
    PORT
      LAYER M4 ;
        RECT  0 29.088 0.084 29.112 ;
    END
  END sr1_meta[11]
  PIN sr1_meta[12]
    DIRECTION INPUT ;
    USE SIGNAL ;
    PORT
      LAYER M4 ;
        RECT  0 29.232 0.084 29.256 ;
    END
  END sr1_meta[12]
  PIN sr1_meta[13]
    DIRECTION INPUT ;
    USE SIGNAL ;
    PORT
      LAYER M4 ;
        RECT  0 29.376 0.084 29.4 ;
    END
  END sr1_meta[13]
  PIN sr1_meta[14]
    DIRECTION INPUT ;
    USE SIGNAL ;
    PORT
      LAYER M4 ;
        RECT  0 29.52 0.084 29.544 ;
    END
  END sr1_meta[14]
  PIN sr1_meta[15]
    DIRECTION INPUT ;
    USE SIGNAL ;
    PORT
      LAYER M4 ;
        RECT  0 29.664 0.084 29.688 ;
    END
  END sr1_meta[15]
  PIN sr1_meta[16]
    DIRECTION INPUT ;
    USE SIGNAL ;
    PORT
      LAYER M4 ;
        RECT  0 29.808 0.084 29.832 ;
    END
  END sr1_meta[16]
  PIN sr1_meta[17]
    DIRECTION INPUT ;
    USE SIGNAL ;
    PORT
      LAYER M4 ;
        RECT  0 29.952 0.084 29.976 ;
    END
  END sr1_meta[17]
  PIN sr1_meta[18]
    DIRECTION INPUT ;
    USE SIGNAL ;
    PORT
      LAYER M4 ;
        RECT  0 30.096 0.084 30.12 ;
    END
  END sr1_meta[18]
  PIN sr1_meta[19]
    DIRECTION INPUT ;
    USE SIGNAL ;
    PORT
      LAYER M4 ;
        RECT  0 30.24 0.084 30.264 ;
    END
  END sr1_meta[19]
  PIN sr1_meta[1]
    DIRECTION INPUT ;
    USE SIGNAL ;
    PORT
      LAYER M4 ;
        RECT  0 27.648 0.084 27.672 ;
    END
  END sr1_meta[1]
  PIN sr1_meta[20]
    DIRECTION INPUT ;
    USE SIGNAL ;
    PORT
      LAYER M4 ;
        RECT  0 30.384 0.084 30.408 ;
    END
  END sr1_meta[20]
  PIN sr1_meta[21]
    DIRECTION INPUT ;
    USE SIGNAL ;
    PORT
      LAYER M4 ;
        RECT  0 30.528 0.084 30.552 ;
    END
  END sr1_meta[21]
  PIN sr1_meta[22]
    DIRECTION INPUT ;
    USE SIGNAL ;
    PORT
      LAYER M4 ;
        RECT  0 30.672 0.084 30.696 ;
    END
  END sr1_meta[22]
  PIN sr1_meta[23]
    DIRECTION INPUT ;
    USE SIGNAL ;
    PORT
      LAYER M4 ;
        RECT  0 30.816 0.084 30.84 ;
    END
  END sr1_meta[23]
  PIN sr1_meta[24]
    DIRECTION INPUT ;
    USE SIGNAL ;
    PORT
      LAYER M4 ;
        RECT  0 30.96 0.084 30.984 ;
    END
  END sr1_meta[24]
  PIN sr1_meta[25]
    DIRECTION INPUT ;
    USE SIGNAL ;
    PORT
      LAYER M4 ;
        RECT  0 31.104 0.084 31.128 ;
    END
  END sr1_meta[25]
  PIN sr1_meta[26]
    DIRECTION INPUT ;
    USE SIGNAL ;
    PORT
      LAYER M4 ;
        RECT  0 31.248 0.084 31.272 ;
    END
  END sr1_meta[26]
  PIN sr1_meta[27]
    DIRECTION INPUT ;
    USE SIGNAL ;
    PORT
      LAYER M4 ;
        RECT  0 31.392 0.084 31.416 ;
    END
  END sr1_meta[27]
  PIN sr1_meta[28]
    DIRECTION INPUT ;
    USE SIGNAL ;
    PORT
      LAYER M4 ;
        RECT  0 31.536 0.084 31.56 ;
    END
  END sr1_meta[28]
  PIN sr1_meta[29]
    DIRECTION INPUT ;
    USE SIGNAL ;
    PORT
      LAYER M4 ;
        RECT  0 31.68 0.084 31.704 ;
    END
  END sr1_meta[29]
  PIN sr1_meta[2]
    DIRECTION INPUT ;
    USE SIGNAL ;
    PORT
      LAYER M4 ;
        RECT  0 27.792 0.084 27.816 ;
    END
  END sr1_meta[2]
  PIN sr1_meta[30]
    DIRECTION INPUT ;
    USE SIGNAL ;
    PORT
      LAYER M4 ;
        RECT  0 31.824 0.084 31.848 ;
    END
  END sr1_meta[30]
  PIN sr1_meta[31]
    DIRECTION INPUT ;
    USE SIGNAL ;
    PORT
      LAYER M4 ;
        RECT  0 31.968 0.084 31.992 ;
    END
  END sr1_meta[31]
  PIN sr1_meta[32]
    DIRECTION INPUT ;
    USE SIGNAL ;
    PORT
      LAYER M4 ;
        RECT  0 37.872 0.084 37.896 ;
    END
  END sr1_meta[32]
  PIN sr1_meta[33]
    DIRECTION INPUT ;
    USE SIGNAL ;
    PORT
      LAYER M4 ;
        RECT  0 38.016 0.084 38.04 ;
    END
  END sr1_meta[33]
  PIN sr1_meta[3]
    DIRECTION INPUT ;
    USE SIGNAL ;
    PORT
      LAYER M4 ;
        RECT  0 27.936 0.084 27.96 ;
    END
  END sr1_meta[3]
  PIN sr1_meta[4]
    DIRECTION INPUT ;
    USE SIGNAL ;
    PORT
      LAYER M4 ;
        RECT  0 28.08 0.084 28.104 ;
    END
  END sr1_meta[4]
  PIN sr1_meta[5]
    DIRECTION INPUT ;
    USE SIGNAL ;
    PORT
      LAYER M4 ;
        RECT  0 28.224 0.084 28.248 ;
    END
  END sr1_meta[5]
  PIN sr1_meta[6]
    DIRECTION INPUT ;
    USE SIGNAL ;
    PORT
      LAYER M4 ;
        RECT  0 28.368 0.084 28.392 ;
    END
  END sr1_meta[6]
  PIN sr1_meta[7]
    DIRECTION INPUT ;
    USE SIGNAL ;
    PORT
      LAYER M4 ;
        RECT  0 28.512 0.084 28.536 ;
    END
  END sr1_meta[7]
  PIN sr1_meta[8]
    DIRECTION INPUT ;
    USE SIGNAL ;
    PORT
      LAYER M4 ;
        RECT  0 28.656 0.084 28.68 ;
    END
  END sr1_meta[8]
  PIN sr1_meta[9]
    DIRECTION INPUT ;
    USE SIGNAL ;
    PORT
      LAYER M4 ;
        RECT  0 28.8 0.084 28.824 ;
    END
  END sr1_meta[9]
  PIN sr1_valid
    DIRECTION INPUT ;
    USE SIGNAL ;
    PORT
      LAYER M4 ;
        RECT  0 38.16 0.084 38.184 ;
    END
  END sr1_valid
  PIN sr2_meta[0]
    DIRECTION INPUT ;
    USE SIGNAL ;
    PORT
      LAYER M4 ;
        RECT  0 38.304 0.084 38.328 ;
    END
  END sr2_meta[0]
  PIN sr2_meta[10]
    DIRECTION INPUT ;
    USE SIGNAL ;
    PORT
      LAYER M4 ;
        RECT  0 39.744 0.084 39.768 ;
    END
  END sr2_meta[10]
  PIN sr2_meta[11]
    DIRECTION INPUT ;
    USE SIGNAL ;
    PORT
      LAYER M4 ;
        RECT  0 39.888 0.084 39.912 ;
    END
  END sr2_meta[11]
  PIN sr2_meta[12]
    DIRECTION INPUT ;
    USE SIGNAL ;
    PORT
      LAYER M4 ;
        RECT  0 40.032 0.084 40.056 ;
    END
  END sr2_meta[12]
  PIN sr2_meta[13]
    DIRECTION INPUT ;
    USE SIGNAL ;
    PORT
      LAYER M4 ;
        RECT  0 40.176 0.084 40.2 ;
    END
  END sr2_meta[13]
  PIN sr2_meta[14]
    DIRECTION INPUT ;
    USE SIGNAL ;
    PORT
      LAYER M4 ;
        RECT  0 40.32 0.084 40.344 ;
    END
  END sr2_meta[14]
  PIN sr2_meta[15]
    DIRECTION INPUT ;
    USE SIGNAL ;
    PORT
      LAYER M4 ;
        RECT  0 40.464 0.084 40.488 ;
    END
  END sr2_meta[15]
  PIN sr2_meta[16]
    DIRECTION INPUT ;
    USE SIGNAL ;
    PORT
      LAYER M4 ;
        RECT  0 40.608 0.084 40.632 ;
    END
  END sr2_meta[16]
  PIN sr2_meta[17]
    DIRECTION INPUT ;
    USE SIGNAL ;
    PORT
      LAYER M4 ;
        RECT  0 40.752 0.084 40.776 ;
    END
  END sr2_meta[17]
  PIN sr2_meta[18]
    DIRECTION INPUT ;
    USE SIGNAL ;
    PORT
      LAYER M4 ;
        RECT  0 40.896 0.084 40.92 ;
    END
  END sr2_meta[18]
  PIN sr2_meta[19]
    DIRECTION INPUT ;
    USE SIGNAL ;
    PORT
      LAYER M4 ;
        RECT  0 41.04 0.084 41.064 ;
    END
  END sr2_meta[19]
  PIN sr2_meta[1]
    DIRECTION INPUT ;
    USE SIGNAL ;
    PORT
      LAYER M4 ;
        RECT  0 38.448 0.084 38.472 ;
    END
  END sr2_meta[1]
  PIN sr2_meta[20]
    DIRECTION INPUT ;
    USE SIGNAL ;
    PORT
      LAYER M4 ;
        RECT  0 41.184 0.084 41.208 ;
    END
  END sr2_meta[20]
  PIN sr2_meta[21]
    DIRECTION INPUT ;
    USE SIGNAL ;
    PORT
      LAYER M4 ;
        RECT  0 41.328 0.084 41.352 ;
    END
  END sr2_meta[21]
  PIN sr2_meta[22]
    DIRECTION INPUT ;
    USE SIGNAL ;
    PORT
      LAYER M4 ;
        RECT  0 41.472 0.084 41.496 ;
    END
  END sr2_meta[22]
  PIN sr2_meta[23]
    DIRECTION INPUT ;
    USE SIGNAL ;
    PORT
      LAYER M4 ;
        RECT  0 41.616 0.084 41.64 ;
    END
  END sr2_meta[23]
  PIN sr2_meta[24]
    DIRECTION INPUT ;
    USE SIGNAL ;
    PORT
      LAYER M4 ;
        RECT  0 41.76 0.084 41.784 ;
    END
  END sr2_meta[24]
  PIN sr2_meta[25]
    DIRECTION INPUT ;
    USE SIGNAL ;
    PORT
      LAYER M4 ;
        RECT  0 41.904 0.084 41.928 ;
    END
  END sr2_meta[25]
  PIN sr2_meta[26]
    DIRECTION INPUT ;
    USE SIGNAL ;
    PORT
      LAYER M4 ;
        RECT  0 42.048 0.084 42.072 ;
    END
  END sr2_meta[26]
  PIN sr2_meta[27]
    DIRECTION INPUT ;
    USE SIGNAL ;
    PORT
      LAYER M4 ;
        RECT  0 42.192 0.084 42.216 ;
    END
  END sr2_meta[27]
  PIN sr2_meta[28]
    DIRECTION INPUT ;
    USE SIGNAL ;
    PORT
      LAYER M4 ;
        RECT  0 42.336 0.084 42.36 ;
    END
  END sr2_meta[28]
  PIN sr2_meta[29]
    DIRECTION INPUT ;
    USE SIGNAL ;
    PORT
      LAYER M4 ;
        RECT  0 71.28 0.084 71.304 ;
    END
  END sr2_meta[29]
  PIN sr2_meta[2]
    DIRECTION INPUT ;
    USE SIGNAL ;
    PORT
      LAYER M4 ;
        RECT  0 38.592 0.084 38.616 ;
    END
  END sr2_meta[2]
  PIN sr2_meta[30]
    DIRECTION INPUT ;
    USE SIGNAL ;
    PORT
      LAYER M4 ;
        RECT  0 71.424 0.084 71.448 ;
    END
  END sr2_meta[30]
  PIN sr2_meta[31]
    DIRECTION INPUT ;
    USE SIGNAL ;
    PORT
      LAYER M4 ;
        RECT  0 71.568 0.084 71.592 ;
    END
  END sr2_meta[31]
  PIN sr2_meta[32]
    DIRECTION INPUT ;
    USE SIGNAL ;
    PORT
      LAYER M4 ;
        RECT  0 71.712 0.084 71.736 ;
    END
  END sr2_meta[32]
  PIN sr2_meta[33]
    DIRECTION INPUT ;
    USE SIGNAL ;
    PORT
      LAYER M4 ;
        RECT  0 71.856 0.084 71.88 ;
    END
  END sr2_meta[33]
  PIN sr2_meta[3]
    DIRECTION INPUT ;
    USE SIGNAL ;
    PORT
      LAYER M4 ;
        RECT  0 38.736 0.084 38.76 ;
    END
  END sr2_meta[3]
  PIN sr2_meta[4]
    DIRECTION INPUT ;
    USE SIGNAL ;
    PORT
      LAYER M4 ;
        RECT  0 38.88 0.084 38.904 ;
    END
  END sr2_meta[4]
  PIN sr2_meta[5]
    DIRECTION INPUT ;
    USE SIGNAL ;
    PORT
      LAYER M4 ;
        RECT  0 39.024 0.084 39.048 ;
    END
  END sr2_meta[5]
  PIN sr2_meta[6]
    DIRECTION INPUT ;
    USE SIGNAL ;
    PORT
      LAYER M4 ;
        RECT  0 39.168 0.084 39.192 ;
    END
  END sr2_meta[6]
  PIN sr2_meta[7]
    DIRECTION INPUT ;
    USE SIGNAL ;
    PORT
      LAYER M4 ;
        RECT  0 39.312 0.084 39.336 ;
    END
  END sr2_meta[7]
  PIN sr2_meta[8]
    DIRECTION INPUT ;
    USE SIGNAL ;
    PORT
      LAYER M4 ;
        RECT  0 39.456 0.084 39.48 ;
    END
  END sr2_meta[8]
  PIN sr2_meta[9]
    DIRECTION INPUT ;
    USE SIGNAL ;
    PORT
      LAYER M4 ;
        RECT  0 39.6 0.084 39.624 ;
    END
  END sr2_meta[9]
  PIN sr2_valid
    DIRECTION INPUT ;
    USE SIGNAL ;
    PORT
      LAYER M4 ;
        RECT  0 72 0.084 72.024 ;
    END
  END sr2_valid
  PIN sx0_meta[0]
    DIRECTION OUTPUT ;
    USE SIGNAL ;
    PORT
      LAYER M4 ;
        RECT  103.596 78.048 103.68 78.072 ;
    END
  END sx0_meta[0]
  PIN sx0_meta[10]
    DIRECTION OUTPUT ;
    USE SIGNAL ;
    PORT
      LAYER M4 ;
        RECT  103.596 79.488 103.68 79.512 ;
    END
  END sx0_meta[10]
  PIN sx0_meta[11]
    DIRECTION OUTPUT ;
    USE SIGNAL ;
    PORT
      LAYER M4 ;
        RECT  103.596 79.632 103.68 79.656 ;
    END
  END sx0_meta[11]
  PIN sx0_meta[12]
    DIRECTION OUTPUT ;
    USE SIGNAL ;
    PORT
      LAYER M4 ;
        RECT  103.596 79.776 103.68 79.8 ;
    END
  END sx0_meta[12]
  PIN sx0_meta[13]
    DIRECTION OUTPUT ;
    USE SIGNAL ;
    PORT
      LAYER M4 ;
        RECT  103.596 79.92 103.68 79.944 ;
    END
  END sx0_meta[13]
  PIN sx0_meta[14]
    DIRECTION OUTPUT ;
    USE SIGNAL ;
    PORT
      LAYER M4 ;
        RECT  103.596 80.064 103.68 80.088 ;
    END
  END sx0_meta[14]
  PIN sx0_meta[15]
    DIRECTION OUTPUT ;
    USE SIGNAL ;
    PORT
      LAYER M4 ;
        RECT  103.596 80.208 103.68 80.232 ;
    END
  END sx0_meta[15]
  PIN sx0_meta[16]
    DIRECTION OUTPUT ;
    USE SIGNAL ;
    PORT
      LAYER M4 ;
        RECT  103.596 80.352 103.68 80.376 ;
    END
  END sx0_meta[16]
  PIN sx0_meta[17]
    DIRECTION OUTPUT ;
    USE SIGNAL ;
    PORT
      LAYER M4 ;
        RECT  103.596 80.496 103.68 80.52 ;
    END
  END sx0_meta[17]
  PIN sx0_meta[18]
    DIRECTION OUTPUT ;
    USE SIGNAL ;
    PORT
      LAYER M4 ;
        RECT  103.596 80.64 103.68 80.664 ;
    END
  END sx0_meta[18]
  PIN sx0_meta[19]
    DIRECTION OUTPUT ;
    USE SIGNAL ;
    PORT
      LAYER M4 ;
        RECT  103.596 80.784 103.68 80.808 ;
    END
  END sx0_meta[19]
  PIN sx0_meta[1]
    DIRECTION OUTPUT ;
    USE SIGNAL ;
    PORT
      LAYER M4 ;
        RECT  103.596 78.192 103.68 78.216 ;
    END
  END sx0_meta[1]
  PIN sx0_meta[20]
    DIRECTION OUTPUT ;
    USE SIGNAL ;
    PORT
      LAYER M4 ;
        RECT  103.596 80.928 103.68 80.952 ;
    END
  END sx0_meta[20]
  PIN sx0_meta[21]
    DIRECTION OUTPUT ;
    USE SIGNAL ;
    PORT
      LAYER M4 ;
        RECT  103.596 81.072 103.68 81.096 ;
    END
  END sx0_meta[21]
  PIN sx0_meta[22]
    DIRECTION OUTPUT ;
    USE SIGNAL ;
    PORT
      LAYER M4 ;
        RECT  103.596 81.216 103.68 81.24 ;
    END
  END sx0_meta[22]
  PIN sx0_meta[23]
    DIRECTION OUTPUT ;
    USE SIGNAL ;
    PORT
      LAYER M4 ;
        RECT  103.596 134.352 103.68 134.376 ;
    END
  END sx0_meta[23]
  PIN sx0_meta[24]
    DIRECTION OUTPUT ;
    USE SIGNAL ;
    PORT
      LAYER M4 ;
        RECT  103.596 134.496 103.68 134.52 ;
    END
  END sx0_meta[24]
  PIN sx0_meta[25]
    DIRECTION OUTPUT ;
    USE SIGNAL ;
    PORT
      LAYER M4 ;
        RECT  103.596 134.64 103.68 134.664 ;
    END
  END sx0_meta[25]
  PIN sx0_meta[26]
    DIRECTION OUTPUT ;
    USE SIGNAL ;
    PORT
      LAYER M4 ;
        RECT  103.596 134.784 103.68 134.808 ;
    END
  END sx0_meta[26]
  PIN sx0_meta[27]
    DIRECTION OUTPUT ;
    USE SIGNAL ;
    PORT
      LAYER M4 ;
        RECT  103.596 134.928 103.68 134.952 ;
    END
  END sx0_meta[27]
  PIN sx0_meta[28]
    DIRECTION OUTPUT ;
    USE SIGNAL ;
    PORT
      LAYER M4 ;
        RECT  103.596 135.072 103.68 135.096 ;
    END
  END sx0_meta[28]
  PIN sx0_meta[29]
    DIRECTION OUTPUT ;
    USE SIGNAL ;
    PORT
      LAYER M4 ;
        RECT  103.596 135.216 103.68 135.24 ;
    END
  END sx0_meta[29]
  PIN sx0_meta[2]
    DIRECTION OUTPUT ;
    USE SIGNAL ;
    PORT
      LAYER M4 ;
        RECT  103.596 78.336 103.68 78.36 ;
    END
  END sx0_meta[2]
  PIN sx0_meta[30]
    DIRECTION OUTPUT ;
    USE SIGNAL ;
    PORT
      LAYER M4 ;
        RECT  103.596 135.36 103.68 135.384 ;
    END
  END sx0_meta[30]
  PIN sx0_meta[31]
    DIRECTION OUTPUT ;
    USE SIGNAL ;
    PORT
      LAYER M4 ;
        RECT  103.596 135.504 103.68 135.528 ;
    END
  END sx0_meta[31]
  PIN sx0_meta[32]
    DIRECTION OUTPUT ;
    USE SIGNAL ;
    PORT
      LAYER M4 ;
        RECT  103.596 135.648 103.68 135.672 ;
    END
  END sx0_meta[32]
  PIN sx0_meta[33]
    DIRECTION OUTPUT ;
    USE SIGNAL ;
    PORT
      LAYER M4 ;
        RECT  103.596 135.792 103.68 135.816 ;
    END
  END sx0_meta[33]
  PIN sx0_meta[3]
    DIRECTION OUTPUT ;
    USE SIGNAL ;
    PORT
      LAYER M4 ;
        RECT  103.596 78.48 103.68 78.504 ;
    END
  END sx0_meta[3]
  PIN sx0_meta[4]
    DIRECTION OUTPUT ;
    USE SIGNAL ;
    PORT
      LAYER M4 ;
        RECT  103.596 78.624 103.68 78.648 ;
    END
  END sx0_meta[4]
  PIN sx0_meta[5]
    DIRECTION OUTPUT ;
    USE SIGNAL ;
    PORT
      LAYER M4 ;
        RECT  103.596 78.768 103.68 78.792 ;
    END
  END sx0_meta[5]
  PIN sx0_meta[6]
    DIRECTION OUTPUT ;
    USE SIGNAL ;
    PORT
      LAYER M4 ;
        RECT  103.596 78.912 103.68 78.936 ;
    END
  END sx0_meta[6]
  PIN sx0_meta[7]
    DIRECTION OUTPUT ;
    USE SIGNAL ;
    PORT
      LAYER M4 ;
        RECT  103.596 79.056 103.68 79.08 ;
    END
  END sx0_meta[7]
  PIN sx0_meta[8]
    DIRECTION OUTPUT ;
    USE SIGNAL ;
    PORT
      LAYER M4 ;
        RECT  103.596 79.2 103.68 79.224 ;
    END
  END sx0_meta[8]
  PIN sx0_meta[9]
    DIRECTION OUTPUT ;
    USE SIGNAL ;
    PORT
      LAYER M4 ;
        RECT  103.596 79.344 103.68 79.368 ;
    END
  END sx0_meta[9]
  PIN sx0_peer_slot
    DIRECTION OUTPUT ;
    USE SIGNAL ;
    PORT
      LAYER M4 ;
        RECT  103.596 135.936 103.68 135.96 ;
    END
  END sx0_peer_slot
  PIN sx0_valid
    DIRECTION OUTPUT ;
    USE SIGNAL ;
    PORT
      LAYER M4 ;
        RECT  103.596 136.08 103.68 136.104 ;
    END
  END sx0_valid
  PIN sx1_meta[0]
    DIRECTION OUTPUT ;
    USE SIGNAL ;
    PORT
      LAYER M4 ;
        RECT  0 72.144 0.084 72.168 ;
    END
  END sx1_meta[0]
  PIN sx1_meta[10]
    DIRECTION OUTPUT ;
    USE SIGNAL ;
    PORT
      LAYER M4 ;
        RECT  0 73.584 0.084 73.608 ;
    END
  END sx1_meta[10]
  PIN sx1_meta[11]
    DIRECTION OUTPUT ;
    USE SIGNAL ;
    PORT
      LAYER M4 ;
        RECT  0 73.728 0.084 73.752 ;
    END
  END sx1_meta[11]
  PIN sx1_meta[12]
    DIRECTION OUTPUT ;
    USE SIGNAL ;
    PORT
      LAYER M4 ;
        RECT  0 73.872 0.084 73.896 ;
    END
  END sx1_meta[12]
  PIN sx1_meta[13]
    DIRECTION OUTPUT ;
    USE SIGNAL ;
    PORT
      LAYER M4 ;
        RECT  0 74.016 0.084 74.04 ;
    END
  END sx1_meta[13]
  PIN sx1_meta[14]
    DIRECTION OUTPUT ;
    USE SIGNAL ;
    PORT
      LAYER M4 ;
        RECT  0 74.16 0.084 74.184 ;
    END
  END sx1_meta[14]
  PIN sx1_meta[15]
    DIRECTION OUTPUT ;
    USE SIGNAL ;
    PORT
      LAYER M4 ;
        RECT  0 74.304 0.084 74.328 ;
    END
  END sx1_meta[15]
  PIN sx1_meta[16]
    DIRECTION OUTPUT ;
    USE SIGNAL ;
    PORT
      LAYER M4 ;
        RECT  0 74.448 0.084 74.472 ;
    END
  END sx1_meta[16]
  PIN sx1_meta[17]
    DIRECTION OUTPUT ;
    USE SIGNAL ;
    PORT
      LAYER M4 ;
        RECT  0 74.592 0.084 74.616 ;
    END
  END sx1_meta[17]
  PIN sx1_meta[18]
    DIRECTION OUTPUT ;
    USE SIGNAL ;
    PORT
      LAYER M4 ;
        RECT  0 74.736 0.084 74.76 ;
    END
  END sx1_meta[18]
  PIN sx1_meta[19]
    DIRECTION OUTPUT ;
    USE SIGNAL ;
    PORT
      LAYER M4 ;
        RECT  0 74.88 0.084 74.904 ;
    END
  END sx1_meta[19]
  PIN sx1_meta[1]
    DIRECTION OUTPUT ;
    USE SIGNAL ;
    PORT
      LAYER M4 ;
        RECT  0 72.288 0.084 72.312 ;
    END
  END sx1_meta[1]
  PIN sx1_meta[20]
    DIRECTION OUTPUT ;
    USE SIGNAL ;
    PORT
      LAYER M4 ;
        RECT  0 75.024 0.084 75.048 ;
    END
  END sx1_meta[20]
  PIN sx1_meta[21]
    DIRECTION OUTPUT ;
    USE SIGNAL ;
    PORT
      LAYER M4 ;
        RECT  0 75.168 0.084 75.192 ;
    END
  END sx1_meta[21]
  PIN sx1_meta[22]
    DIRECTION OUTPUT ;
    USE SIGNAL ;
    PORT
      LAYER M4 ;
        RECT  0 75.312 0.084 75.336 ;
    END
  END sx1_meta[22]
  PIN sx1_meta[23]
    DIRECTION OUTPUT ;
    USE SIGNAL ;
    PORT
      LAYER M4 ;
        RECT  0 75.456 0.084 75.48 ;
    END
  END sx1_meta[23]
  PIN sx1_meta[24]
    DIRECTION OUTPUT ;
    USE SIGNAL ;
    PORT
      LAYER M4 ;
        RECT  0 75.6 0.084 75.624 ;
    END
  END sx1_meta[24]
  PIN sx1_meta[25]
    DIRECTION OUTPUT ;
    USE SIGNAL ;
    PORT
      LAYER M4 ;
        RECT  0 75.744 0.084 75.768 ;
    END
  END sx1_meta[25]
  PIN sx1_meta[26]
    DIRECTION OUTPUT ;
    USE SIGNAL ;
    PORT
      LAYER M4 ;
        RECT  0 66.672 0.084 66.696 ;
    END
  END sx1_meta[26]
  PIN sx1_meta[27]
    DIRECTION OUTPUT ;
    USE SIGNAL ;
    PORT
      LAYER M4 ;
        RECT  0 66.816 0.084 66.84 ;
    END
  END sx1_meta[27]
  PIN sx1_meta[28]
    DIRECTION OUTPUT ;
    USE SIGNAL ;
    PORT
      LAYER M4 ;
        RECT  0 66.96 0.084 66.984 ;
    END
  END sx1_meta[28]
  PIN sx1_meta[29]
    DIRECTION OUTPUT ;
    USE SIGNAL ;
    PORT
      LAYER M4 ;
        RECT  0 67.104 0.084 67.128 ;
    END
  END sx1_meta[29]
  PIN sx1_meta[2]
    DIRECTION OUTPUT ;
    USE SIGNAL ;
    PORT
      LAYER M4 ;
        RECT  0 72.432 0.084 72.456 ;
    END
  END sx1_meta[2]
  PIN sx1_meta[30]
    DIRECTION OUTPUT ;
    USE SIGNAL ;
    PORT
      LAYER M4 ;
        RECT  0 67.248 0.084 67.272 ;
    END
  END sx1_meta[30]
  PIN sx1_meta[31]
    DIRECTION OUTPUT ;
    USE SIGNAL ;
    PORT
      LAYER M4 ;
        RECT  0 67.392 0.084 67.416 ;
    END
  END sx1_meta[31]
  PIN sx1_meta[32]
    DIRECTION OUTPUT ;
    USE SIGNAL ;
    PORT
      LAYER M4 ;
        RECT  0 67.536 0.084 67.56 ;
    END
  END sx1_meta[32]
  PIN sx1_meta[33]
    DIRECTION OUTPUT ;
    USE SIGNAL ;
    PORT
      LAYER M4 ;
        RECT  0 67.68 0.084 67.704 ;
    END
  END sx1_meta[33]
  PIN sx1_meta[3]
    DIRECTION OUTPUT ;
    USE SIGNAL ;
    PORT
      LAYER M4 ;
        RECT  0 72.576 0.084 72.6 ;
    END
  END sx1_meta[3]
  PIN sx1_meta[4]
    DIRECTION OUTPUT ;
    USE SIGNAL ;
    PORT
      LAYER M4 ;
        RECT  0 72.72 0.084 72.744 ;
    END
  END sx1_meta[4]
  PIN sx1_meta[5]
    DIRECTION OUTPUT ;
    USE SIGNAL ;
    PORT
      LAYER M4 ;
        RECT  0 72.864 0.084 72.888 ;
    END
  END sx1_meta[5]
  PIN sx1_meta[6]
    DIRECTION OUTPUT ;
    USE SIGNAL ;
    PORT
      LAYER M4 ;
        RECT  0 73.008 0.084 73.032 ;
    END
  END sx1_meta[6]
  PIN sx1_meta[7]
    DIRECTION OUTPUT ;
    USE SIGNAL ;
    PORT
      LAYER M4 ;
        RECT  0 73.152 0.084 73.176 ;
    END
  END sx1_meta[7]
  PIN sx1_meta[8]
    DIRECTION OUTPUT ;
    USE SIGNAL ;
    PORT
      LAYER M4 ;
        RECT  0 73.296 0.084 73.32 ;
    END
  END sx1_meta[8]
  PIN sx1_meta[9]
    DIRECTION OUTPUT ;
    USE SIGNAL ;
    PORT
      LAYER M4 ;
        RECT  0 73.44 0.084 73.464 ;
    END
  END sx1_meta[9]
  PIN sx1_peer_slot
    DIRECTION OUTPUT ;
    USE SIGNAL ;
    PORT
      LAYER M4 ;
        RECT  0 67.824 0.084 67.848 ;
    END
  END sx1_peer_slot
  PIN sx1_valid
    DIRECTION OUTPUT ;
    USE SIGNAL ;
    PORT
      LAYER M4 ;
        RECT  0 67.968 0.084 67.992 ;
    END
  END sx1_valid
  PIN sx2_meta[0]
    DIRECTION OUTPUT ;
    USE SIGNAL ;
    PORT
      LAYER M4 ;
        RECT  0 68.112 0.084 68.136 ;
    END
  END sx2_meta[0]
  PIN sx2_meta[10]
    DIRECTION OUTPUT ;
    USE SIGNAL ;
    PORT
      LAYER M4 ;
        RECT  0 69.552 0.084 69.576 ;
    END
  END sx2_meta[10]
  PIN sx2_meta[11]
    DIRECTION OUTPUT ;
    USE SIGNAL ;
    PORT
      LAYER M4 ;
        RECT  0 69.696 0.084 69.72 ;
    END
  END sx2_meta[11]
  PIN sx2_meta[12]
    DIRECTION OUTPUT ;
    USE SIGNAL ;
    PORT
      LAYER M4 ;
        RECT  0 69.84 0.084 69.864 ;
    END
  END sx2_meta[12]
  PIN sx2_meta[13]
    DIRECTION OUTPUT ;
    USE SIGNAL ;
    PORT
      LAYER M4 ;
        RECT  0 69.984 0.084 70.008 ;
    END
  END sx2_meta[13]
  PIN sx2_meta[14]
    DIRECTION OUTPUT ;
    USE SIGNAL ;
    PORT
      LAYER M4 ;
        RECT  0 70.128 0.084 70.152 ;
    END
  END sx2_meta[14]
  PIN sx2_meta[15]
    DIRECTION OUTPUT ;
    USE SIGNAL ;
    PORT
      LAYER M4 ;
        RECT  0 70.272 0.084 70.296 ;
    END
  END sx2_meta[15]
  PIN sx2_meta[16]
    DIRECTION OUTPUT ;
    USE SIGNAL ;
    PORT
      LAYER M4 ;
        RECT  0 70.416 0.084 70.44 ;
    END
  END sx2_meta[16]
  PIN sx2_meta[17]
    DIRECTION OUTPUT ;
    USE SIGNAL ;
    PORT
      LAYER M4 ;
        RECT  0 70.56 0.084 70.584 ;
    END
  END sx2_meta[17]
  PIN sx2_meta[18]
    DIRECTION OUTPUT ;
    USE SIGNAL ;
    PORT
      LAYER M4 ;
        RECT  0 70.704 0.084 70.728 ;
    END
  END sx2_meta[18]
  PIN sx2_meta[19]
    DIRECTION OUTPUT ;
    USE SIGNAL ;
    PORT
      LAYER M4 ;
        RECT  0 70.848 0.084 70.872 ;
    END
  END sx2_meta[19]
  PIN sx2_meta[1]
    DIRECTION OUTPUT ;
    USE SIGNAL ;
    PORT
      LAYER M4 ;
        RECT  0 68.256 0.084 68.28 ;
    END
  END sx2_meta[1]
  PIN sx2_meta[20]
    DIRECTION OUTPUT ;
    USE SIGNAL ;
    PORT
      LAYER M4 ;
        RECT  0 70.992 0.084 71.016 ;
    END
  END sx2_meta[20]
  PIN sx2_meta[21]
    DIRECTION OUTPUT ;
    USE SIGNAL ;
    PORT
      LAYER M4 ;
        RECT  0 71.136 0.084 71.16 ;
    END
  END sx2_meta[21]
  PIN sx2_meta[22]
    DIRECTION OUTPUT ;
    USE SIGNAL ;
    PORT
      LAYER M4 ;
        RECT  0 54.288 0.084 54.312 ;
    END
  END sx2_meta[22]
  PIN sx2_meta[23]
    DIRECTION OUTPUT ;
    USE SIGNAL ;
    PORT
      LAYER M4 ;
        RECT  0 54.432 0.084 54.456 ;
    END
  END sx2_meta[23]
  PIN sx2_meta[24]
    DIRECTION OUTPUT ;
    USE SIGNAL ;
    PORT
      LAYER M4 ;
        RECT  0 54.576 0.084 54.6 ;
    END
  END sx2_meta[24]
  PIN sx2_meta[25]
    DIRECTION OUTPUT ;
    USE SIGNAL ;
    PORT
      LAYER M4 ;
        RECT  0 54.72 0.084 54.744 ;
    END
  END sx2_meta[25]
  PIN sx2_meta[26]
    DIRECTION OUTPUT ;
    USE SIGNAL ;
    PORT
      LAYER M4 ;
        RECT  0 54.864 0.084 54.888 ;
    END
  END sx2_meta[26]
  PIN sx2_meta[27]
    DIRECTION OUTPUT ;
    USE SIGNAL ;
    PORT
      LAYER M4 ;
        RECT  0 55.008 0.084 55.032 ;
    END
  END sx2_meta[27]
  PIN sx2_meta[28]
    DIRECTION OUTPUT ;
    USE SIGNAL ;
    PORT
      LAYER M4 ;
        RECT  0 55.152 0.084 55.176 ;
    END
  END sx2_meta[28]
  PIN sx2_meta[29]
    DIRECTION OUTPUT ;
    USE SIGNAL ;
    PORT
      LAYER M4 ;
        RECT  0 55.296 0.084 55.32 ;
    END
  END sx2_meta[29]
  PIN sx2_meta[2]
    DIRECTION OUTPUT ;
    USE SIGNAL ;
    PORT
      LAYER M4 ;
        RECT  0 68.4 0.084 68.424 ;
    END
  END sx2_meta[2]
  PIN sx2_meta[30]
    DIRECTION OUTPUT ;
    USE SIGNAL ;
    PORT
      LAYER M4 ;
        RECT  0 55.44 0.084 55.464 ;
    END
  END sx2_meta[30]
  PIN sx2_meta[31]
    DIRECTION OUTPUT ;
    USE SIGNAL ;
    PORT
      LAYER M4 ;
        RECT  0 55.584 0.084 55.608 ;
    END
  END sx2_meta[31]
  PIN sx2_meta[32]
    DIRECTION OUTPUT ;
    USE SIGNAL ;
    PORT
      LAYER M4 ;
        RECT  0 55.728 0.084 55.752 ;
    END
  END sx2_meta[32]
  PIN sx2_meta[33]
    DIRECTION OUTPUT ;
    USE SIGNAL ;
    PORT
      LAYER M4 ;
        RECT  0 55.872 0.084 55.896 ;
    END
  END sx2_meta[33]
  PIN sx2_meta[3]
    DIRECTION OUTPUT ;
    USE SIGNAL ;
    PORT
      LAYER M4 ;
        RECT  0 68.544 0.084 68.568 ;
    END
  END sx2_meta[3]
  PIN sx2_meta[4]
    DIRECTION OUTPUT ;
    USE SIGNAL ;
    PORT
      LAYER M4 ;
        RECT  0 68.688 0.084 68.712 ;
    END
  END sx2_meta[4]
  PIN sx2_meta[5]
    DIRECTION OUTPUT ;
    USE SIGNAL ;
    PORT
      LAYER M4 ;
        RECT  0 68.832 0.084 68.856 ;
    END
  END sx2_meta[5]
  PIN sx2_meta[6]
    DIRECTION OUTPUT ;
    USE SIGNAL ;
    PORT
      LAYER M4 ;
        RECT  0 68.976 0.084 69 ;
    END
  END sx2_meta[6]
  PIN sx2_meta[7]
    DIRECTION OUTPUT ;
    USE SIGNAL ;
    PORT
      LAYER M4 ;
        RECT  0 69.12 0.084 69.144 ;
    END
  END sx2_meta[7]
  PIN sx2_meta[8]
    DIRECTION OUTPUT ;
    USE SIGNAL ;
    PORT
      LAYER M4 ;
        RECT  0 69.264 0.084 69.288 ;
    END
  END sx2_meta[8]
  PIN sx2_meta[9]
    DIRECTION OUTPUT ;
    USE SIGNAL ;
    PORT
      LAYER M4 ;
        RECT  0 69.408 0.084 69.432 ;
    END
  END sx2_meta[9]
  PIN sx2_peer_slot
    DIRECTION OUTPUT ;
    USE SIGNAL ;
    PORT
      LAYER M4 ;
        RECT  0 56.016 0.084 56.04 ;
    END
  END sx2_peer_slot
  PIN sx2_valid
    DIRECTION OUTPUT ;
    USE SIGNAL ;
    PORT
      LAYER M4 ;
        RECT  0 56.16 0.084 56.184 ;
    END
  END sx2_valid
  PIN up_meta[0]
    DIRECTION OUTPUT ;
    USE SIGNAL ;
    PORT
      LAYER M4 ;
        RECT  103.596 136.224 103.68 136.248 ;
    END
  END up_meta[0]
  PIN up_meta[10]
    DIRECTION OUTPUT ;
    USE SIGNAL ;
    PORT
      LAYER M4 ;
        RECT  103.596 137.664 103.68 137.688 ;
    END
  END up_meta[10]
  PIN up_meta[11]
    DIRECTION OUTPUT ;
    USE SIGNAL ;
    PORT
      LAYER M4 ;
        RECT  103.596 137.808 103.68 137.832 ;
    END
  END up_meta[11]
  PIN up_meta[12]
    DIRECTION OUTPUT ;
    USE SIGNAL ;
    PORT
      LAYER M4 ;
        RECT  103.596 137.952 103.68 137.976 ;
    END
  END up_meta[12]
  PIN up_meta[13]
    DIRECTION OUTPUT ;
    USE SIGNAL ;
    PORT
      LAYER M4 ;
        RECT  103.596 138.096 103.68 138.12 ;
    END
  END up_meta[13]
  PIN up_meta[14]
    DIRECTION OUTPUT ;
    USE SIGNAL ;
    PORT
      LAYER M4 ;
        RECT  103.596 138.24 103.68 138.264 ;
    END
  END up_meta[14]
  PIN up_meta[15]
    DIRECTION OUTPUT ;
    USE SIGNAL ;
    PORT
      LAYER M4 ;
        RECT  103.596 138.384 103.68 138.408 ;
    END
  END up_meta[15]
  PIN up_meta[16]
    DIRECTION OUTPUT ;
    USE SIGNAL ;
    PORT
      LAYER M4 ;
        RECT  103.596 138.528 103.68 138.552 ;
    END
  END up_meta[16]
  PIN up_meta[17]
    DIRECTION OUTPUT ;
    USE SIGNAL ;
    PORT
      LAYER M4 ;
        RECT  103.596 138.672 103.68 138.696 ;
    END
  END up_meta[17]
  PIN up_meta[18]
    DIRECTION OUTPUT ;
    USE SIGNAL ;
    PORT
      LAYER M4 ;
        RECT  103.596 138.816 103.68 138.84 ;
    END
  END up_meta[18]
  PIN up_meta[19]
    DIRECTION OUTPUT ;
    USE SIGNAL ;
    PORT
      LAYER M4 ;
        RECT  103.596 138.96 103.68 138.984 ;
    END
  END up_meta[19]
  PIN up_meta[1]
    DIRECTION OUTPUT ;
    USE SIGNAL ;
    PORT
      LAYER M4 ;
        RECT  103.596 136.368 103.68 136.392 ;
    END
  END up_meta[1]
  PIN up_meta[20]
    DIRECTION OUTPUT ;
    USE SIGNAL ;
    PORT
      LAYER M4 ;
        RECT  103.596 139.104 103.68 139.128 ;
    END
  END up_meta[20]
  PIN up_meta[21]
    DIRECTION OUTPUT ;
    USE SIGNAL ;
    PORT
      LAYER M4 ;
        RECT  103.596 139.248 103.68 139.272 ;
    END
  END up_meta[21]
  PIN up_meta[22]
    DIRECTION OUTPUT ;
    USE SIGNAL ;
    PORT
      LAYER M4 ;
        RECT  103.596 139.392 103.68 139.416 ;
    END
  END up_meta[22]
  PIN up_meta[23]
    DIRECTION OUTPUT ;
    USE SIGNAL ;
    PORT
      LAYER M4 ;
        RECT  103.596 139.536 103.68 139.56 ;
    END
  END up_meta[23]
  PIN up_meta[24]
    DIRECTION OUTPUT ;
    USE SIGNAL ;
    PORT
      LAYER M4 ;
        RECT  103.596 139.68 103.68 139.704 ;
    END
  END up_meta[24]
  PIN up_meta[25]
    DIRECTION OUTPUT ;
    USE SIGNAL ;
    PORT
      LAYER M4 ;
        RECT  103.596 139.824 103.68 139.848 ;
    END
  END up_meta[25]
  PIN up_meta[26]
    DIRECTION OUTPUT ;
    USE SIGNAL ;
    PORT
      LAYER M4 ;
        RECT  103.596 139.968 103.68 139.992 ;
    END
  END up_meta[26]
  PIN up_meta[27]
    DIRECTION OUTPUT ;
    USE SIGNAL ;
    PORT
      LAYER M4 ;
        RECT  103.596 140.112 103.68 140.136 ;
    END
  END up_meta[27]
  PIN up_meta[28]
    DIRECTION OUTPUT ;
    USE SIGNAL ;
    PORT
      LAYER M4 ;
        RECT  103.596 140.256 103.68 140.28 ;
    END
  END up_meta[28]
  PIN up_meta[29]
    DIRECTION OUTPUT ;
    USE SIGNAL ;
    PORT
      LAYER M4 ;
        RECT  103.596 140.4 103.68 140.424 ;
    END
  END up_meta[29]
  PIN up_meta[2]
    DIRECTION OUTPUT ;
    USE SIGNAL ;
    PORT
      LAYER M4 ;
        RECT  103.596 136.512 103.68 136.536 ;
    END
  END up_meta[2]
  PIN up_meta[30]
    DIRECTION OUTPUT ;
    USE SIGNAL ;
    PORT
      LAYER M4 ;
        RECT  103.596 140.544 103.68 140.568 ;
    END
  END up_meta[30]
  PIN up_meta[31]
    DIRECTION OUTPUT ;
    USE SIGNAL ;
    PORT
      LAYER M4 ;
        RECT  103.596 140.688 103.68 140.712 ;
    END
  END up_meta[31]
  PIN up_meta[32]
    DIRECTION OUTPUT ;
    USE SIGNAL ;
    PORT
      LAYER M4 ;
        RECT  103.596 140.832 103.68 140.856 ;
    END
  END up_meta[32]
  PIN up_meta[33]
    DIRECTION OUTPUT ;
    USE SIGNAL ;
    PORT
      LAYER M4 ;
        RECT  103.596 140.976 103.68 141 ;
    END
  END up_meta[33]
  PIN up_meta[3]
    DIRECTION OUTPUT ;
    USE SIGNAL ;
    PORT
      LAYER M4 ;
        RECT  103.596 136.656 103.68 136.68 ;
    END
  END up_meta[3]
  PIN up_meta[4]
    DIRECTION OUTPUT ;
    USE SIGNAL ;
    PORT
      LAYER M4 ;
        RECT  103.596 136.8 103.68 136.824 ;
    END
  END up_meta[4]
  PIN up_meta[5]
    DIRECTION OUTPUT ;
    USE SIGNAL ;
    PORT
      LAYER M4 ;
        RECT  103.596 136.944 103.68 136.968 ;
    END
  END up_meta[5]
  PIN up_meta[6]
    DIRECTION OUTPUT ;
    USE SIGNAL ;
    PORT
      LAYER M4 ;
        RECT  103.596 137.088 103.68 137.112 ;
    END
  END up_meta[6]
  PIN up_meta[7]
    DIRECTION OUTPUT ;
    USE SIGNAL ;
    PORT
      LAYER M4 ;
        RECT  103.596 137.232 103.68 137.256 ;
    END
  END up_meta[7]
  PIN up_meta[8]
    DIRECTION OUTPUT ;
    USE SIGNAL ;
    PORT
      LAYER M4 ;
        RECT  103.596 137.376 103.68 137.4 ;
    END
  END up_meta[8]
  PIN up_meta[9]
    DIRECTION OUTPUT ;
    USE SIGNAL ;
    PORT
      LAYER M4 ;
        RECT  103.596 137.52 103.68 137.544 ;
    END
  END up_meta[9]
  PIN up_slot
    DIRECTION OUTPUT ;
    USE SIGNAL ;
    PORT
      LAYER M4 ;
        RECT  103.596 141.12 103.68 141.144 ;
    END
  END up_slot
  PIN up_valid
    DIRECTION OUTPUT ;
    USE SIGNAL ;
    PORT
      LAYER M4 ;
        RECT  103.596 141.264 103.68 141.288 ;
    END
  END up_valid
  PIN ur_meta[0]
    DIRECTION OUTPUT ;
    USE SIGNAL ;
    PORT
      LAYER M4 ;
        RECT  103.596 141.408 103.68 141.432 ;
    END
  END ur_meta[0]
  PIN ur_meta[1]
    DIRECTION OUTPUT ;
    USE SIGNAL ;
    PORT
      LAYER M4 ;
        RECT  103.596 141.552 103.68 141.576 ;
    END
  END ur_meta[1]
  PIN ur_peer_slot
    DIRECTION OUTPUT ;
    USE SIGNAL ;
    PORT
      LAYER M4 ;
        RECT  103.596 141.696 103.68 141.72 ;
    END
  END ur_peer_slot
  PIN ur_valid
    DIRECTION OUTPUT ;
    USE SIGNAL ;
    PORT
      LAYER M4 ;
        RECT  103.596 141.84 103.68 141.864 ;
    END
  END ur_valid
  PIN VDD
    DIRECTION INOUT ;
    USE POWER ;
    PORT
      LAYER M5 ;
        RECT  99.792 2.151 99.912 179.289 ;
        RECT  94.392 2.151 94.512 179.289 ;
        RECT  88.992 2.151 89.112 179.289 ;
        RECT  83.592 2.151 83.712 179.289 ;
        RECT  78.192 2.151 78.312 179.289 ;
        RECT  72.792 2.151 72.912 179.289 ;
        RECT  67.392 2.151 67.512 179.289 ;
        RECT  61.992 2.151 62.112 179.289 ;
        RECT  56.592 2.151 56.712 179.289 ;
        RECT  51.192 2.151 51.312 179.289 ;
        RECT  45.792 2.151 45.912 179.289 ;
        RECT  40.392 2.151 40.512 179.289 ;
        RECT  34.992 2.151 35.112 179.289 ;
        RECT  29.592 2.151 29.712 179.289 ;
        RECT  24.192 2.151 24.312 179.289 ;
        RECT  18.792 2.151 18.912 179.289 ;
        RECT  13.392 2.151 13.512 179.289 ;
        RECT  7.992 2.151 8.112 179.289 ;
        RECT  2.592 2.151 2.712 179.289 ;
    END
  END VDD
  PIN VSS
    DIRECTION INOUT ;
    USE GROUND ;
    PORT
      LAYER M5 ;
        RECT  99.6 2.137 99.72 179.303 ;
        RECT  94.2 2.137 94.32 179.303 ;
        RECT  88.8 2.137 88.92 179.303 ;
        RECT  83.4 2.137 83.52 179.303 ;
        RECT  78 2.137 78.12 179.303 ;
        RECT  72.6 2.137 72.72 179.303 ;
        RECT  67.2 2.137 67.32 179.303 ;
        RECT  61.8 2.137 61.92 179.303 ;
        RECT  56.4 2.137 56.52 179.303 ;
        RECT  51 2.137 51.12 179.303 ;
        RECT  45.6 2.137 45.72 179.303 ;
        RECT  40.2 2.137 40.32 179.303 ;
        RECT  34.8 2.137 34.92 179.303 ;
        RECT  29.4 2.137 29.52 179.303 ;
        RECT  24 2.137 24.12 179.303 ;
        RECT  18.6 2.137 18.72 179.303 ;
        RECT  13.2 2.137 13.32 179.303 ;
        RECT  7.8 2.137 7.92 179.303 ;
        RECT  2.4 2.137 2.52 179.303 ;
    END
  END VSS
  OBS
    LAYER RVTN ;
     RECT  2.16 2.16 101.52 2.295 ;
     RECT  2.16 2.565 101.52 2.835 ;
     RECT  2.16 3.105 101.52 3.375 ;
     RECT  2.16 3.645 101.52 3.915 ;
     RECT  2.16 4.185 101.52 4.455 ;
     RECT  2.16 4.725 101.52 4.995 ;
     RECT  2.16 5.265 101.52 5.535 ;
     RECT  2.16 5.805 101.52 6.075 ;
     RECT  2.16 6.345 101.52 6.615 ;
     RECT  2.16 6.885 101.52 7.155 ;
     RECT  2.16 7.425 101.52 7.695 ;
     RECT  2.16 7.965 101.52 8.235 ;
     RECT  2.16 8.505 101.52 8.775 ;
     RECT  2.16 9.045 101.52 9.315 ;
     RECT  2.16 9.585 101.52 9.855 ;
     RECT  2.16 10.125 101.52 10.395 ;
     RECT  2.16 10.665 101.52 10.935 ;
     RECT  2.16 11.205 101.52 11.475 ;
     RECT  2.16 11.745 101.52 12.015 ;
     RECT  2.16 12.285 101.52 12.555 ;
     RECT  2.16 12.825 101.52 13.095 ;
     RECT  2.16 13.365 101.52 13.635 ;
     RECT  2.16 13.905 101.52 14.175 ;
     RECT  2.16 14.445 101.52 14.715 ;
     RECT  2.16 14.985 101.52 15.255 ;
     RECT  2.16 15.525 101.52 15.795 ;
     RECT  2.16 16.065 101.52 16.335 ;
     RECT  2.16 16.605 101.52 16.875 ;
     RECT  2.16 17.145 101.52 17.415 ;
     RECT  2.16 17.685 101.52 17.955 ;
     RECT  2.16 18.225 101.52 18.495 ;
     RECT  2.16 18.765 101.52 19.035 ;
     RECT  2.16 19.305 101.52 19.575 ;
     RECT  2.16 19.845 101.52 20.115 ;
     RECT  2.16 20.385 101.52 20.655 ;
     RECT  2.16 20.925 101.52 21.195 ;
     RECT  2.16 21.465 101.52 21.735 ;
     RECT  2.16 22.005 101.52 22.275 ;
     RECT  2.16 22.545 101.52 22.815 ;
     RECT  2.16 23.085 101.52 23.355 ;
     RECT  2.16 23.625 101.52 23.895 ;
     RECT  2.16 24.165 101.52 24.435 ;
     RECT  2.16 24.705 101.52 24.975 ;
     RECT  2.16 25.245 101.52 25.515 ;
     RECT  2.16 25.785 101.52 26.055 ;
     RECT  2.16 26.325 101.52 26.595 ;
     RECT  2.16 26.865 101.52 27.135 ;
     RECT  2.16 27.405 101.52 27.675 ;
     RECT  2.16 27.945 101.52 28.215 ;
     RECT  2.16 28.485 101.52 28.755 ;
     RECT  2.16 29.025 101.52 29.295 ;
     RECT  2.16 29.565 101.52 29.835 ;
     RECT  2.16 30.105 101.52 30.375 ;
     RECT  2.16 30.645 101.52 30.915 ;
     RECT  2.16 31.185 101.52 31.455 ;
     RECT  2.16 31.725 101.52 31.995 ;
     RECT  2.16 32.265 101.52 32.535 ;
     RECT  2.16 32.805 101.52 33.075 ;
     RECT  2.16 33.345 101.52 33.615 ;
     RECT  2.16 33.885 101.52 34.155 ;
     RECT  2.16 34.425 101.52 34.695 ;
     RECT  2.16 34.965 101.52 35.235 ;
     RECT  2.16 35.505 101.52 35.775 ;
     RECT  2.16 36.045 101.52 36.315 ;
     RECT  2.16 36.585 101.52 36.855 ;
     RECT  2.16 37.125 101.52 37.395 ;
     RECT  2.16 37.665 101.52 37.935 ;
     RECT  2.16 38.205 101.52 38.475 ;
     RECT  2.16 38.745 101.52 39.015 ;
     RECT  2.16 39.285 101.52 39.555 ;
     RECT  2.16 39.825 101.52 40.095 ;
     RECT  2.16 40.365 101.52 40.635 ;
     RECT  2.16 40.905 101.52 41.04 ;
     RECT  2.16 41.04 41.148 41.175 ;
     RECT  79.812 41.04 101.52 41.175 ;
     RECT  2.16 41.445 41.148 41.715 ;
     RECT  79.812 41.445 101.52 41.715 ;
     RECT  2.16 41.985 41.148 42.255 ;
     RECT  79.812 41.985 101.52 42.255 ;
     RECT  2.16 42.525 41.148 42.795 ;
     RECT  79.812 42.525 101.52 42.795 ;
     RECT  2.16 43.065 41.148 43.335 ;
     RECT  79.812 43.065 101.52 43.335 ;
     RECT  2.16 43.605 41.148 43.875 ;
     RECT  79.812 43.605 101.52 43.875 ;
     RECT  2.16 44.145 41.148 44.415 ;
     RECT  79.812 44.145 101.52 44.415 ;
     RECT  2.16 44.685 41.148 44.955 ;
     RECT  79.812 44.685 101.52 44.955 ;
     RECT  2.16 45.225 41.148 45.495 ;
     RECT  79.812 45.225 101.52 45.495 ;
     RECT  2.16 45.765 41.148 46.035 ;
     RECT  79.812 45.765 101.52 46.035 ;
     RECT  2.16 46.305 41.148 46.575 ;
     RECT  79.812 46.305 101.52 46.575 ;
     RECT  2.16 46.845 41.148 47.115 ;
     RECT  79.812 46.845 101.52 47.115 ;
     RECT  2.16 47.385 41.148 47.655 ;
     RECT  79.812 47.385 101.52 47.655 ;
     RECT  2.16 47.925 41.148 48.195 ;
     RECT  79.812 47.925 101.52 48.195 ;
     RECT  2.16 48.465 41.148 48.735 ;
     RECT  79.812 48.465 101.52 48.735 ;
     RECT  2.16 49.005 41.148 49.275 ;
     RECT  79.812 49.005 101.52 49.275 ;
     RECT  2.16 49.545 41.148 49.815 ;
     RECT  79.812 49.545 101.52 49.815 ;
     RECT  2.16 50.085 41.148 50.355 ;
     RECT  79.812 50.085 101.52 50.355 ;
     RECT  2.16 50.625 41.148 50.895 ;
     RECT  79.812 50.625 101.52 50.895 ;
     RECT  2.16 51.165 41.148 51.435 ;
     RECT  79.812 51.165 101.52 51.435 ;
     RECT  2.16 51.705 41.148 51.975 ;
     RECT  79.812 51.705 101.52 51.975 ;
     RECT  2.16 52.245 41.148 52.515 ;
     RECT  79.812 52.245 101.52 52.515 ;
     RECT  2.16 52.785 41.148 53.055 ;
     RECT  79.812 52.785 101.52 53.055 ;
     RECT  2.16 53.325 41.148 53.595 ;
     RECT  79.812 53.325 101.52 53.595 ;
     RECT  2.16 53.865 41.148 54.135 ;
     RECT  79.812 53.865 101.52 54.135 ;
     RECT  2.16 54.405 41.148 54.675 ;
     RECT  79.812 54.405 101.52 54.675 ;
     RECT  2.16 54.945 41.148 55.215 ;
     RECT  79.812 54.945 101.52 55.215 ;
     RECT  2.16 55.485 41.148 55.755 ;
     RECT  79.812 55.485 101.52 55.755 ;
     RECT  2.16 56.025 41.148 56.295 ;
     RECT  79.812 56.025 101.52 56.295 ;
     RECT  2.16 56.565 41.148 56.835 ;
     RECT  79.812 56.565 101.52 56.835 ;
     RECT  2.16 57.105 41.148 57.375 ;
     RECT  79.812 57.105 101.52 57.375 ;
     RECT  2.16 57.645 41.148 57.915 ;
     RECT  79.812 57.645 101.52 57.915 ;
     RECT  2.16 58.185 41.148 58.455 ;
     RECT  79.812 58.185 101.52 58.455 ;
     RECT  2.16 58.725 41.148 58.995 ;
     RECT  79.812 58.725 101.52 58.995 ;
     RECT  2.16 59.265 41.148 59.535 ;
     RECT  79.812 59.265 101.52 59.535 ;
     RECT  2.16 59.805 41.148 60.075 ;
     RECT  79.812 59.805 101.52 60.075 ;
     RECT  2.16 60.345 41.148 60.615 ;
     RECT  79.812 60.345 101.52 60.615 ;
     RECT  2.16 60.885 41.148 61.155 ;
     RECT  79.812 60.885 101.52 61.155 ;
     RECT  2.16 61.425 41.148 61.695 ;
     RECT  79.812 61.425 101.52 61.695 ;
     RECT  2.16 61.965 41.148 62.235 ;
     RECT  79.812 61.965 101.52 62.235 ;
     RECT  2.16 62.505 41.148 62.775 ;
     RECT  79.812 62.505 101.52 62.775 ;
     RECT  2.16 63.045 41.148 63.315 ;
     RECT  79.812 63.045 101.52 63.315 ;
     RECT  2.16 63.585 41.148 63.855 ;
     RECT  79.812 63.585 101.52 63.855 ;
     RECT  2.16 64.125 41.148 64.395 ;
     RECT  79.812 64.125 101.52 64.395 ;
     RECT  2.16 64.665 41.148 64.935 ;
     RECT  79.812 64.665 101.52 64.935 ;
     RECT  2.16 65.205 41.148 65.475 ;
     RECT  79.812 65.205 101.52 65.475 ;
     RECT  2.16 65.745 41.148 66.015 ;
     RECT  79.812 65.745 101.52 66.015 ;
     RECT  2.16 66.285 41.148 66.555 ;
     RECT  79.812 66.285 101.52 66.555 ;
     RECT  2.16 66.825 41.148 67.095 ;
     RECT  79.812 66.825 101.52 67.095 ;
     RECT  2.16 67.365 41.148 67.635 ;
     RECT  79.812 67.365 101.52 67.635 ;
     RECT  2.16 67.905 41.148 68.175 ;
     RECT  79.812 67.905 101.52 68.175 ;
     RECT  2.16 68.445 41.148 68.715 ;
     RECT  79.812 68.445 101.52 68.715 ;
     RECT  2.16 68.985 41.148 69.255 ;
     RECT  79.812 68.985 101.52 69.255 ;
     RECT  2.16 69.525 41.148 69.795 ;
     RECT  79.812 69.525 101.52 69.795 ;
     RECT  2.16 70.065 41.148 70.335 ;
     RECT  79.812 70.065 101.52 70.335 ;
     RECT  2.16 70.605 41.148 70.875 ;
     RECT  79.812 70.605 101.52 70.875 ;
     RECT  2.16 71.145 41.148 71.415 ;
     RECT  79.812 71.145 101.52 71.415 ;
     RECT  2.16 71.685 41.148 71.955 ;
     RECT  79.812 71.685 101.52 71.955 ;
     RECT  2.16 72.225 41.148 72.495 ;
     RECT  79.812 72.225 101.52 72.495 ;
     RECT  2.16 72.765 41.148 73.035 ;
     RECT  79.812 72.765 101.52 73.035 ;
     RECT  2.16 73.305 41.148 73.575 ;
     RECT  79.812 73.305 101.52 73.575 ;
     RECT  2.16 73.845 41.148 74.115 ;
     RECT  79.812 73.845 101.52 74.115 ;
     RECT  2.16 74.385 41.148 74.655 ;
     RECT  79.812 74.385 101.52 74.655 ;
     RECT  2.16 74.925 41.148 75.195 ;
     RECT  79.812 74.925 101.52 75.195 ;
     RECT  2.16 75.465 41.148 75.735 ;
     RECT  79.812 75.465 101.52 75.735 ;
     RECT  2.16 76.005 41.148 76.275 ;
     RECT  79.812 76.005 101.52 76.275 ;
     RECT  2.16 76.545 41.148 76.815 ;
     RECT  79.812 76.545 101.52 76.815 ;
     RECT  2.16 77.085 41.148 77.355 ;
     RECT  79.812 77.085 101.52 77.355 ;
     RECT  2.16 77.625 41.148 77.895 ;
     RECT  79.812 77.625 101.52 77.895 ;
     RECT  2.16 78.165 41.148 78.435 ;
     RECT  79.812 78.165 101.52 78.435 ;
     RECT  2.16 78.705 41.148 78.975 ;
     RECT  79.812 78.705 101.52 78.975 ;
     RECT  2.16 79.245 41.148 79.515 ;
     RECT  79.812 79.245 101.52 79.515 ;
     RECT  2.16 79.785 41.148 80.055 ;
     RECT  79.812 79.785 101.52 80.055 ;
     RECT  2.16 80.325 41.148 80.595 ;
     RECT  79.812 80.325 101.52 80.595 ;
     RECT  2.16 80.865 41.148 81.135 ;
     RECT  79.812 80.865 101.52 81.135 ;
     RECT  2.16 81.405 41.148 81.675 ;
     RECT  79.812 81.405 101.52 81.675 ;
     RECT  2.16 81.945 41.148 82.215 ;
     RECT  79.812 81.945 101.52 82.215 ;
     RECT  2.16 82.485 41.148 82.755 ;
     RECT  79.812 82.485 101.52 82.755 ;
     RECT  2.16 83.025 41.148 83.295 ;
     RECT  79.812 83.025 101.52 83.295 ;
     RECT  2.16 83.565 41.148 83.835 ;
     RECT  79.812 83.565 101.52 83.835 ;
     RECT  2.16 84.105 41.148 84.375 ;
     RECT  79.812 84.105 101.52 84.375 ;
     RECT  2.16 84.645 41.148 84.915 ;
     RECT  79.812 84.645 101.52 84.915 ;
     RECT  2.16 85.185 41.148 85.455 ;
     RECT  79.812 85.185 101.52 85.455 ;
     RECT  2.16 85.725 41.148 85.995 ;
     RECT  79.812 85.725 101.52 85.995 ;
     RECT  2.16 86.265 41.148 86.535 ;
     RECT  79.812 86.265 101.52 86.535 ;
     RECT  2.16 86.805 41.148 87.075 ;
     RECT  79.812 86.805 101.52 87.075 ;
     RECT  2.16 87.345 41.148 87.615 ;
     RECT  79.812 87.345 101.52 87.615 ;
     RECT  2.16 87.885 41.148 88.155 ;
     RECT  79.812 87.885 101.52 88.155 ;
     RECT  2.16 88.425 41.148 88.695 ;
     RECT  79.812 88.425 101.52 88.695 ;
     RECT  2.16 88.965 41.148 89.235 ;
     RECT  79.812 88.965 101.52 89.235 ;
     RECT  2.16 89.505 41.148 89.775 ;
     RECT  79.812 89.505 101.52 89.775 ;
     RECT  2.16 90.045 41.148 90.315 ;
     RECT  79.812 90.045 101.52 90.315 ;
     RECT  2.16 90.585 41.148 90.855 ;
     RECT  79.812 90.585 101.52 90.855 ;
     RECT  2.16 91.125 41.148 91.395 ;
     RECT  79.812 91.125 101.52 91.395 ;
     RECT  2.16 91.665 41.148 91.935 ;
     RECT  79.812 91.665 101.52 91.935 ;
     RECT  2.16 92.205 41.148 92.475 ;
     RECT  79.812 92.205 101.52 92.475 ;
     RECT  2.16 92.745 41.148 93.015 ;
     RECT  79.812 92.745 101.52 93.015 ;
     RECT  2.16 93.285 41.148 93.555 ;
     RECT  79.812 93.285 101.52 93.555 ;
     RECT  2.16 93.825 41.148 94.095 ;
     RECT  79.812 93.825 101.52 94.095 ;
     RECT  2.16 94.365 41.148 94.635 ;
     RECT  79.812 94.365 101.52 94.635 ;
     RECT  2.16 94.905 41.148 95.175 ;
     RECT  79.812 94.905 101.52 95.175 ;
     RECT  2.16 95.445 41.148 95.715 ;
     RECT  79.812 95.445 101.52 95.715 ;
     RECT  2.16 95.985 41.148 96.255 ;
     RECT  79.812 95.985 101.52 96.255 ;
     RECT  2.16 96.525 41.148 96.795 ;
     RECT  79.812 96.525 101.52 96.795 ;
     RECT  2.16 97.065 41.148 97.335 ;
     RECT  79.812 97.065 101.52 97.335 ;
     RECT  2.16 97.605 41.148 97.875 ;
     RECT  79.812 97.605 101.52 97.875 ;
     RECT  2.16 98.145 41.148 98.415 ;
     RECT  79.812 98.145 101.52 98.415 ;
     RECT  2.16 98.685 41.148 98.955 ;
     RECT  79.812 98.685 101.52 98.955 ;
     RECT  2.16 99.225 41.148 99.495 ;
     RECT  79.812 99.225 101.52 99.495 ;
     RECT  2.16 99.765 41.148 100.035 ;
     RECT  79.812 99.765 101.52 100.035 ;
     RECT  2.16 100.305 41.148 100.575 ;
     RECT  79.812 100.305 101.52 100.575 ;
     RECT  2.16 100.845 41.148 101.115 ;
     RECT  79.812 100.845 101.52 101.115 ;
     RECT  2.16 101.385 41.148 101.655 ;
     RECT  79.812 101.385 101.52 101.655 ;
     RECT  2.16 101.925 41.148 102.195 ;
     RECT  79.812 101.925 101.52 102.195 ;
     RECT  2.16 102.465 41.148 102.735 ;
     RECT  79.812 102.465 101.52 102.735 ;
     RECT  2.16 103.005 41.148 103.275 ;
     RECT  79.812 103.005 101.52 103.275 ;
     RECT  2.16 103.545 41.148 103.815 ;
     RECT  79.812 103.545 101.52 103.815 ;
     RECT  2.16 104.085 41.148 104.355 ;
     RECT  79.812 104.085 101.52 104.355 ;
     RECT  2.16 104.625 41.148 104.895 ;
     RECT  79.812 104.625 101.52 104.895 ;
     RECT  2.16 105.165 41.148 105.435 ;
     RECT  79.812 105.165 101.52 105.435 ;
     RECT  2.16 105.705 41.148 105.975 ;
     RECT  79.812 105.705 101.52 105.975 ;
     RECT  2.16 106.245 41.148 106.515 ;
     RECT  79.812 106.245 101.52 106.515 ;
     RECT  2.16 106.785 41.148 107.055 ;
     RECT  79.812 106.785 101.52 107.055 ;
     RECT  2.16 107.325 41.148 107.595 ;
     RECT  79.812 107.325 101.52 107.595 ;
     RECT  2.16 107.865 41.148 108.135 ;
     RECT  79.812 107.865 101.52 108.135 ;
     RECT  2.16 108.405 41.148 108.675 ;
     RECT  79.812 108.405 101.52 108.675 ;
     RECT  2.16 108.945 41.148 109.215 ;
     RECT  79.812 108.945 101.52 109.215 ;
     RECT  2.16 109.485 41.148 109.755 ;
     RECT  79.812 109.485 101.52 109.755 ;
     RECT  2.16 110.025 41.148 110.295 ;
     RECT  79.812 110.025 101.52 110.295 ;
     RECT  2.16 110.565 41.148 110.835 ;
     RECT  79.812 110.565 101.52 110.835 ;
     RECT  2.16 111.105 41.148 111.375 ;
     RECT  79.812 111.105 101.52 111.375 ;
     RECT  2.16 111.645 41.148 111.915 ;
     RECT  79.812 111.645 101.52 111.915 ;
     RECT  2.16 112.185 41.148 112.455 ;
     RECT  79.812 112.185 101.52 112.455 ;
     RECT  2.16 112.725 41.148 112.995 ;
     RECT  79.812 112.725 101.52 112.995 ;
     RECT  2.16 113.265 41.148 113.535 ;
     RECT  79.812 113.265 101.52 113.535 ;
     RECT  2.16 113.805 41.148 114.075 ;
     RECT  79.812 113.805 101.52 114.075 ;
     RECT  2.16 114.345 41.148 114.615 ;
     RECT  79.812 114.345 101.52 114.615 ;
     RECT  2.16 114.885 41.148 115.155 ;
     RECT  79.812 114.885 101.52 115.155 ;
     RECT  2.16 115.425 41.148 115.695 ;
     RECT  79.812 115.425 101.52 115.695 ;
     RECT  2.16 115.965 41.148 116.235 ;
     RECT  79.812 115.965 101.52 116.235 ;
     RECT  2.16 116.505 41.148 116.775 ;
     RECT  79.812 116.505 101.52 116.775 ;
     RECT  2.16 117.045 41.148 117.315 ;
     RECT  79.812 117.045 101.52 117.315 ;
     RECT  2.16 117.585 41.148 117.855 ;
     RECT  79.812 117.585 101.52 117.855 ;
     RECT  2.16 118.125 41.148 118.395 ;
     RECT  79.812 118.125 101.52 118.395 ;
     RECT  2.16 118.665 41.148 118.935 ;
     RECT  79.812 118.665 101.52 118.935 ;
     RECT  2.16 119.205 41.148 119.475 ;
     RECT  79.812 119.205 101.52 119.475 ;
     RECT  2.16 119.745 41.148 120.015 ;
     RECT  79.812 119.745 101.52 120.015 ;
     RECT  2.16 120.285 41.148 120.555 ;
     RECT  79.812 120.285 101.52 120.555 ;
     RECT  2.16 120.825 41.148 121.095 ;
     RECT  79.812 120.825 101.52 121.095 ;
     RECT  2.16 121.365 41.148 121.635 ;
     RECT  79.812 121.365 101.52 121.635 ;
     RECT  2.16 121.905 41.148 122.175 ;
     RECT  79.812 121.905 101.52 122.175 ;
     RECT  2.16 122.445 41.148 122.715 ;
     RECT  79.812 122.445 101.52 122.715 ;
     RECT  2.16 122.985 41.148 123.255 ;
     RECT  79.812 122.985 101.52 123.255 ;
     RECT  2.16 123.525 41.148 123.795 ;
     RECT  79.812 123.525 101.52 123.795 ;
     RECT  2.16 124.065 41.148 124.335 ;
     RECT  79.812 124.065 101.52 124.335 ;
     RECT  2.16 124.605 41.148 124.875 ;
     RECT  79.812 124.605 101.52 124.875 ;
     RECT  2.16 125.145 41.148 125.415 ;
     RECT  79.812 125.145 101.52 125.415 ;
     RECT  2.16 125.685 41.148 125.955 ;
     RECT  79.812 125.685 101.52 125.955 ;
     RECT  2.16 126.225 41.148 126.495 ;
     RECT  79.812 126.225 101.52 126.495 ;
     RECT  2.16 126.765 41.148 127.035 ;
     RECT  79.812 126.765 101.52 127.035 ;
     RECT  2.16 127.305 41.148 127.575 ;
     RECT  79.812 127.305 101.52 127.575 ;
     RECT  79.812 127.845 101.52 127.98 ;
     RECT  2.16 127.845 41.148 128.115 ;
     RECT  78.948 127.98 101.52 128.115 ;
     RECT  2.16 128.385 41.148 128.655 ;
     RECT  78.948 128.385 101.52 128.655 ;
     RECT  2.16 128.925 41.148 129.195 ;
     RECT  78.948 128.925 101.52 129.195 ;
     RECT  2.16 129.465 41.148 129.735 ;
     RECT  78.948 129.465 101.52 129.735 ;
     RECT  2.16 130.005 41.148 130.275 ;
     RECT  78.948 130.005 101.52 130.275 ;
     RECT  2.16 130.545 41.148 130.815 ;
     RECT  78.948 130.545 101.52 130.815 ;
     RECT  2.16 131.085 41.148 131.355 ;
     RECT  78.948 131.085 101.52 131.355 ;
     RECT  2.16 131.625 41.148 131.895 ;
     RECT  78.948 131.625 101.52 131.895 ;
     RECT  2.16 132.165 41.148 132.435 ;
     RECT  78.948 132.165 101.52 132.435 ;
     RECT  2.16 132.705 41.148 132.975 ;
     RECT  78.948 132.705 101.52 132.975 ;
     RECT  2.16 133.245 41.148 133.515 ;
     RECT  78.948 133.245 101.52 133.515 ;
     RECT  2.16 133.785 41.148 134.055 ;
     RECT  78.948 133.785 101.52 134.055 ;
     RECT  2.16 134.325 41.148 134.595 ;
     RECT  78.948 134.325 101.52 134.595 ;
     RECT  2.16 134.865 41.148 135.135 ;
     RECT  78.948 134.865 101.52 135.135 ;
     RECT  2.16 135.405 41.148 135.675 ;
     RECT  78.948 135.405 101.52 135.675 ;
     RECT  2.16 135.945 41.148 136.215 ;
     RECT  78.948 135.945 101.52 136.215 ;
     RECT  2.16 136.485 41.148 136.755 ;
     RECT  78.948 136.485 101.52 136.755 ;
     RECT  2.16 137.025 41.148 137.295 ;
     RECT  78.948 137.025 101.52 137.295 ;
     RECT  2.16 137.565 41.148 137.835 ;
     RECT  78.948 137.565 101.52 137.835 ;
     RECT  2.16 138.105 41.148 138.375 ;
     RECT  78.948 138.105 101.52 138.375 ;
     RECT  2.16 138.645 41.148 138.915 ;
     RECT  78.948 138.645 101.52 138.915 ;
     RECT  2.16 139.185 41.148 139.455 ;
     RECT  78.948 139.185 101.52 139.455 ;
     RECT  2.16 139.725 41.148 139.995 ;
     RECT  78.948 139.725 101.52 139.995 ;
     RECT  2.16 140.265 41.148 140.535 ;
     RECT  78.948 140.265 101.52 140.535 ;
     RECT  2.16 140.805 41.148 141.075 ;
     RECT  78.948 140.805 101.52 141.075 ;
     RECT  2.16 141.345 41.148 141.615 ;
     RECT  78.948 141.345 101.52 141.615 ;
     RECT  2.16 141.885 41.148 142.155 ;
     RECT  78.948 141.885 101.52 142.155 ;
     RECT  2.16 142.425 41.148 142.695 ;
     RECT  78.948 142.425 101.52 142.695 ;
     RECT  2.16 142.965 41.148 143.235 ;
     RECT  78.948 142.965 101.52 143.235 ;
     RECT  2.16 143.505 41.148 143.775 ;
     RECT  78.948 143.505 101.52 143.775 ;
     RECT  2.16 144.045 41.148 144.315 ;
     RECT  78.948 144.045 101.52 144.315 ;
     RECT  2.16 144.585 41.148 144.855 ;
     RECT  78.948 144.585 101.52 144.855 ;
     RECT  2.16 145.125 41.148 145.395 ;
     RECT  78.948 145.125 101.52 145.395 ;
     RECT  2.16 145.665 41.148 145.935 ;
     RECT  78.948 145.665 101.52 145.935 ;
     RECT  2.16 146.205 41.148 146.475 ;
     RECT  78.948 146.205 101.52 146.475 ;
     RECT  2.16 146.745 41.148 147.015 ;
     RECT  78.948 146.745 101.52 147.015 ;
     RECT  2.16 147.285 41.148 147.555 ;
     RECT  78.948 147.285 101.52 147.555 ;
     RECT  2.16 147.825 41.148 148.095 ;
     RECT  78.948 147.825 101.52 148.095 ;
     RECT  2.16 148.365 41.148 148.635 ;
     RECT  78.948 148.365 101.52 148.635 ;
     RECT  2.16 148.905 41.148 149.175 ;
     RECT  78.948 148.905 101.52 149.175 ;
     RECT  2.16 149.445 41.148 149.715 ;
     RECT  78.948 149.445 101.52 149.715 ;
     RECT  2.16 149.985 41.148 150.255 ;
     RECT  78.948 149.985 101.52 150.255 ;
     RECT  2.16 150.525 41.148 150.795 ;
     RECT  78.948 150.525 101.52 150.795 ;
     RECT  2.16 151.065 41.148 151.335 ;
     RECT  78.948 151.065 101.52 151.335 ;
     RECT  2.16 151.605 41.148 151.875 ;
     RECT  78.948 151.605 101.52 151.875 ;
     RECT  2.16 152.145 41.148 152.415 ;
     RECT  78.948 152.145 101.52 152.415 ;
     RECT  2.16 152.685 41.148 152.955 ;
     RECT  78.948 152.685 101.52 152.955 ;
     RECT  2.16 153.225 41.148 153.495 ;
     RECT  78.948 153.225 101.52 153.495 ;
     RECT  2.16 153.765 41.148 154.035 ;
     RECT  78.948 153.765 101.52 154.035 ;
     RECT  2.16 154.305 41.148 154.575 ;
     RECT  78.948 154.305 101.52 154.575 ;
     RECT  2.16 154.845 41.148 155.115 ;
     RECT  78.948 154.845 101.52 155.115 ;
     RECT  2.16 155.385 41.148 155.655 ;
     RECT  78.948 155.385 101.52 155.655 ;
     RECT  2.16 155.925 101.52 156.195 ;
     RECT  2.16 156.465 101.52 156.735 ;
     RECT  2.16 157.005 101.52 157.275 ;
     RECT  2.16 157.545 101.52 157.815 ;
     RECT  2.16 158.085 101.52 158.355 ;
     RECT  2.16 158.625 101.52 158.895 ;
     RECT  2.16 159.165 101.52 159.435 ;
     RECT  2.16 159.705 101.52 159.975 ;
     RECT  2.16 160.245 101.52 160.515 ;
     RECT  2.16 160.785 101.52 161.055 ;
     RECT  2.16 161.325 101.52 161.595 ;
     RECT  2.16 161.865 101.52 162.135 ;
     RECT  2.16 162.405 101.52 162.675 ;
     RECT  2.16 162.945 101.52 163.215 ;
     RECT  2.16 163.485 101.52 163.755 ;
     RECT  2.16 164.025 101.52 164.295 ;
     RECT  2.16 164.565 101.52 164.835 ;
     RECT  2.16 165.105 101.52 165.375 ;
     RECT  2.16 165.645 101.52 165.915 ;
     RECT  2.16 166.185 101.52 166.455 ;
     RECT  2.16 166.725 101.52 166.995 ;
     RECT  2.16 167.265 101.52 167.535 ;
     RECT  2.16 167.805 101.52 168.075 ;
     RECT  2.16 168.345 101.52 168.615 ;
     RECT  2.16 168.885 101.52 169.155 ;
     RECT  2.16 169.425 101.52 169.695 ;
     RECT  2.16 169.965 101.52 170.235 ;
     RECT  2.16 170.505 101.52 170.775 ;
     RECT  2.16 171.045 101.52 171.315 ;
     RECT  2.16 171.585 101.52 171.855 ;
     RECT  2.16 172.125 101.52 172.395 ;
     RECT  2.16 172.665 101.52 172.935 ;
     RECT  2.16 173.205 101.52 173.475 ;
     RECT  2.16 173.745 101.52 174.015 ;
     RECT  2.16 174.285 101.52 174.555 ;
     RECT  2.16 174.825 101.52 175.095 ;
     RECT  2.16 175.365 101.52 175.635 ;
     RECT  2.16 175.905 101.52 176.175 ;
     RECT  2.16 176.445 101.52 176.715 ;
     RECT  2.16 176.985 101.52 177.255 ;
     RECT  2.16 177.525 101.52 177.795 ;
     RECT  2.16 178.065 101.52 178.335 ;
     RECT  2.16 178.605 101.52 178.875 ;
     RECT  2.16 179.145 101.52 179.28 ;
    LAYER RVTP ;
     RECT  2.16 2.295 101.52 2.565 ;
     RECT  2.16 2.835 101.52 3.105 ;
     RECT  2.16 3.375 101.52 3.645 ;
     RECT  2.16 3.915 101.52 4.185 ;
     RECT  2.16 4.455 101.52 4.725 ;
     RECT  2.16 4.995 101.52 5.265 ;
     RECT  2.16 5.535 101.52 5.805 ;
     RECT  2.16 6.075 101.52 6.345 ;
     RECT  2.16 6.615 101.52 6.885 ;
     RECT  2.16 7.155 101.52 7.425 ;
     RECT  2.16 7.695 101.52 7.965 ;
     RECT  2.16 8.235 101.52 8.505 ;
     RECT  2.16 8.775 101.52 9.045 ;
     RECT  2.16 9.315 101.52 9.585 ;
     RECT  2.16 9.855 101.52 10.125 ;
     RECT  2.16 10.395 101.52 10.665 ;
     RECT  2.16 10.935 101.52 11.205 ;
     RECT  2.16 11.475 101.52 11.745 ;
     RECT  2.16 12.015 101.52 12.285 ;
     RECT  2.16 12.555 101.52 12.825 ;
     RECT  2.16 13.095 101.52 13.365 ;
     RECT  2.16 13.635 101.52 13.905 ;
     RECT  2.16 14.175 101.52 14.445 ;
     RECT  2.16 14.715 101.52 14.985 ;
     RECT  2.16 15.255 101.52 15.525 ;
     RECT  2.16 15.795 101.52 16.065 ;
     RECT  2.16 16.335 101.52 16.605 ;
     RECT  2.16 16.875 101.52 17.145 ;
     RECT  2.16 17.415 101.52 17.685 ;
     RECT  2.16 17.955 101.52 18.225 ;
     RECT  2.16 18.495 101.52 18.765 ;
     RECT  2.16 19.035 101.52 19.305 ;
     RECT  2.16 19.575 101.52 19.845 ;
     RECT  2.16 20.115 101.52 20.385 ;
     RECT  2.16 20.655 101.52 20.925 ;
     RECT  2.16 21.195 101.52 21.465 ;
     RECT  2.16 21.735 101.52 22.005 ;
     RECT  2.16 22.275 101.52 22.545 ;
     RECT  2.16 22.815 101.52 23.085 ;
     RECT  2.16 23.355 101.52 23.625 ;
     RECT  2.16 23.895 101.52 24.165 ;
     RECT  2.16 24.435 101.52 24.705 ;
     RECT  2.16 24.975 101.52 25.245 ;
     RECT  2.16 25.515 101.52 25.785 ;
     RECT  2.16 26.055 101.52 26.325 ;
     RECT  2.16 26.595 101.52 26.865 ;
     RECT  2.16 27.135 101.52 27.405 ;
     RECT  2.16 27.675 101.52 27.945 ;
     RECT  2.16 28.215 101.52 28.485 ;
     RECT  2.16 28.755 101.52 29.025 ;
     RECT  2.16 29.295 101.52 29.565 ;
     RECT  2.16 29.835 101.52 30.105 ;
     RECT  2.16 30.375 101.52 30.645 ;
     RECT  2.16 30.915 101.52 31.185 ;
     RECT  2.16 31.455 101.52 31.725 ;
     RECT  2.16 31.995 101.52 32.265 ;
     RECT  2.16 32.535 101.52 32.805 ;
     RECT  2.16 33.075 101.52 33.345 ;
     RECT  2.16 33.615 101.52 33.885 ;
     RECT  2.16 34.155 101.52 34.425 ;
     RECT  2.16 34.695 101.52 34.965 ;
     RECT  2.16 35.235 101.52 35.505 ;
     RECT  2.16 35.775 101.52 36.045 ;
     RECT  2.16 36.315 101.52 36.585 ;
     RECT  2.16 36.855 101.52 37.125 ;
     RECT  2.16 37.395 101.52 37.665 ;
     RECT  2.16 37.935 101.52 38.205 ;
     RECT  2.16 38.475 101.52 38.745 ;
     RECT  2.16 39.015 101.52 39.285 ;
     RECT  2.16 39.555 101.52 39.825 ;
     RECT  2.16 40.095 101.52 40.365 ;
     RECT  2.16 40.635 101.52 40.905 ;
     RECT  2.16 41.175 41.148 41.445 ;
     RECT  79.812 41.175 101.52 41.445 ;
     RECT  2.16 41.715 41.148 41.985 ;
     RECT  79.812 41.715 101.52 41.985 ;
     RECT  2.16 42.255 41.148 42.525 ;
     RECT  79.812 42.255 101.52 42.525 ;
     RECT  2.16 42.795 41.148 43.065 ;
     RECT  79.812 42.795 101.52 43.065 ;
     RECT  2.16 43.335 41.148 43.605 ;
     RECT  79.812 43.335 101.52 43.605 ;
     RECT  2.16 43.875 41.148 44.145 ;
     RECT  79.812 43.875 101.52 44.145 ;
     RECT  2.16 44.415 41.148 44.685 ;
     RECT  79.812 44.415 101.52 44.685 ;
     RECT  2.16 44.955 41.148 45.225 ;
     RECT  79.812 44.955 101.52 45.225 ;
     RECT  2.16 45.495 41.148 45.765 ;
     RECT  79.812 45.495 101.52 45.765 ;
     RECT  2.16 46.035 41.148 46.305 ;
     RECT  79.812 46.035 101.52 46.305 ;
     RECT  2.16 46.575 41.148 46.845 ;
     RECT  79.812 46.575 101.52 46.845 ;
     RECT  2.16 47.115 41.148 47.385 ;
     RECT  79.812 47.115 101.52 47.385 ;
     RECT  2.16 47.655 41.148 47.925 ;
     RECT  79.812 47.655 101.52 47.925 ;
     RECT  2.16 48.195 41.148 48.465 ;
     RECT  79.812 48.195 101.52 48.465 ;
     RECT  2.16 48.735 41.148 49.005 ;
     RECT  79.812 48.735 101.52 49.005 ;
     RECT  2.16 49.275 41.148 49.545 ;
     RECT  79.812 49.275 101.52 49.545 ;
     RECT  2.16 49.815 41.148 50.085 ;
     RECT  79.812 49.815 101.52 50.085 ;
     RECT  2.16 50.355 41.148 50.625 ;
     RECT  79.812 50.355 101.52 50.625 ;
     RECT  2.16 50.895 41.148 51.165 ;
     RECT  79.812 50.895 101.52 51.165 ;
     RECT  2.16 51.435 41.148 51.705 ;
     RECT  79.812 51.435 101.52 51.705 ;
     RECT  2.16 51.975 41.148 52.245 ;
     RECT  79.812 51.975 101.52 52.245 ;
     RECT  2.16 52.515 41.148 52.785 ;
     RECT  79.812 52.515 101.52 52.785 ;
     RECT  2.16 53.055 41.148 53.325 ;
     RECT  79.812 53.055 101.52 53.325 ;
     RECT  2.16 53.595 41.148 53.865 ;
     RECT  79.812 53.595 101.52 53.865 ;
     RECT  2.16 54.135 41.148 54.405 ;
     RECT  79.812 54.135 101.52 54.405 ;
     RECT  2.16 54.675 41.148 54.945 ;
     RECT  79.812 54.675 101.52 54.945 ;
     RECT  2.16 55.215 41.148 55.485 ;
     RECT  79.812 55.215 101.52 55.485 ;
     RECT  2.16 55.755 41.148 56.025 ;
     RECT  79.812 55.755 101.52 56.025 ;
     RECT  2.16 56.295 41.148 56.565 ;
     RECT  79.812 56.295 101.52 56.565 ;
     RECT  2.16 56.835 41.148 57.105 ;
     RECT  79.812 56.835 101.52 57.105 ;
     RECT  2.16 57.375 41.148 57.645 ;
     RECT  79.812 57.375 101.52 57.645 ;
     RECT  2.16 57.915 41.148 58.185 ;
     RECT  79.812 57.915 101.52 58.185 ;
     RECT  2.16 58.455 41.148 58.725 ;
     RECT  79.812 58.455 101.52 58.725 ;
     RECT  2.16 58.995 41.148 59.265 ;
     RECT  79.812 58.995 101.52 59.265 ;
     RECT  2.16 59.535 41.148 59.805 ;
     RECT  79.812 59.535 101.52 59.805 ;
     RECT  2.16 60.075 41.148 60.345 ;
     RECT  79.812 60.075 101.52 60.345 ;
     RECT  2.16 60.615 41.148 60.885 ;
     RECT  79.812 60.615 101.52 60.885 ;
     RECT  2.16 61.155 41.148 61.425 ;
     RECT  79.812 61.155 101.52 61.425 ;
     RECT  2.16 61.695 41.148 61.965 ;
     RECT  79.812 61.695 101.52 61.965 ;
     RECT  2.16 62.235 41.148 62.505 ;
     RECT  79.812 62.235 101.52 62.505 ;
     RECT  2.16 62.775 41.148 63.045 ;
     RECT  79.812 62.775 101.52 63.045 ;
     RECT  2.16 63.315 41.148 63.585 ;
     RECT  79.812 63.315 101.52 63.585 ;
     RECT  2.16 63.855 41.148 64.125 ;
     RECT  79.812 63.855 101.52 64.125 ;
     RECT  2.16 64.395 41.148 64.665 ;
     RECT  79.812 64.395 101.52 64.665 ;
     RECT  2.16 64.935 41.148 65.205 ;
     RECT  79.812 64.935 101.52 65.205 ;
     RECT  2.16 65.475 41.148 65.745 ;
     RECT  79.812 65.475 101.52 65.745 ;
     RECT  2.16 66.015 41.148 66.285 ;
     RECT  79.812 66.015 101.52 66.285 ;
     RECT  2.16 66.555 41.148 66.825 ;
     RECT  79.812 66.555 101.52 66.825 ;
     RECT  2.16 67.095 41.148 67.365 ;
     RECT  79.812 67.095 101.52 67.365 ;
     RECT  2.16 67.635 41.148 67.905 ;
     RECT  79.812 67.635 101.52 67.905 ;
     RECT  2.16 68.175 41.148 68.445 ;
     RECT  79.812 68.175 101.52 68.445 ;
     RECT  2.16 68.715 41.148 68.985 ;
     RECT  79.812 68.715 101.52 68.985 ;
     RECT  2.16 69.255 41.148 69.525 ;
     RECT  79.812 69.255 101.52 69.525 ;
     RECT  2.16 69.795 41.148 70.065 ;
     RECT  79.812 69.795 101.52 70.065 ;
     RECT  2.16 70.335 41.148 70.605 ;
     RECT  79.812 70.335 101.52 70.605 ;
     RECT  2.16 70.875 41.148 71.145 ;
     RECT  79.812 70.875 101.52 71.145 ;
     RECT  2.16 71.415 41.148 71.685 ;
     RECT  79.812 71.415 101.52 71.685 ;
     RECT  2.16 71.955 41.148 72.225 ;
     RECT  79.812 71.955 101.52 72.225 ;
     RECT  2.16 72.495 41.148 72.765 ;
     RECT  79.812 72.495 101.52 72.765 ;
     RECT  2.16 73.035 41.148 73.305 ;
     RECT  79.812 73.035 101.52 73.305 ;
     RECT  2.16 73.575 41.148 73.845 ;
     RECT  79.812 73.575 101.52 73.845 ;
     RECT  2.16 74.115 41.148 74.385 ;
     RECT  79.812 74.115 101.52 74.385 ;
     RECT  2.16 74.655 41.148 74.925 ;
     RECT  79.812 74.655 101.52 74.925 ;
     RECT  2.16 75.195 41.148 75.465 ;
     RECT  79.812 75.195 101.52 75.465 ;
     RECT  2.16 75.735 41.148 76.005 ;
     RECT  79.812 75.735 101.52 76.005 ;
     RECT  2.16 76.275 41.148 76.545 ;
     RECT  79.812 76.275 101.52 76.545 ;
     RECT  2.16 76.815 41.148 77.085 ;
     RECT  79.812 76.815 101.52 77.085 ;
     RECT  2.16 77.355 41.148 77.625 ;
     RECT  79.812 77.355 101.52 77.625 ;
     RECT  2.16 77.895 41.148 78.165 ;
     RECT  79.812 77.895 101.52 78.165 ;
     RECT  2.16 78.435 41.148 78.705 ;
     RECT  79.812 78.435 101.52 78.705 ;
     RECT  2.16 78.975 41.148 79.245 ;
     RECT  79.812 78.975 101.52 79.245 ;
     RECT  2.16 79.515 41.148 79.785 ;
     RECT  79.812 79.515 101.52 79.785 ;
     RECT  2.16 80.055 41.148 80.325 ;
     RECT  79.812 80.055 101.52 80.325 ;
     RECT  2.16 80.595 41.148 80.865 ;
     RECT  79.812 80.595 101.52 80.865 ;
     RECT  2.16 81.135 41.148 81.405 ;
     RECT  79.812 81.135 101.52 81.405 ;
     RECT  2.16 81.675 41.148 81.945 ;
     RECT  79.812 81.675 101.52 81.945 ;
     RECT  2.16 82.215 41.148 82.485 ;
     RECT  79.812 82.215 101.52 82.485 ;
     RECT  2.16 82.755 41.148 83.025 ;
     RECT  79.812 82.755 101.52 83.025 ;
     RECT  2.16 83.295 41.148 83.565 ;
     RECT  79.812 83.295 101.52 83.565 ;
     RECT  2.16 83.835 41.148 84.105 ;
     RECT  79.812 83.835 101.52 84.105 ;
     RECT  2.16 84.375 41.148 84.645 ;
     RECT  79.812 84.375 101.52 84.645 ;
     RECT  2.16 84.915 41.148 85.185 ;
     RECT  79.812 84.915 101.52 85.185 ;
     RECT  2.16 85.455 41.148 85.725 ;
     RECT  79.812 85.455 101.52 85.725 ;
     RECT  2.16 85.995 41.148 86.265 ;
     RECT  79.812 85.995 101.52 86.265 ;
     RECT  2.16 86.535 41.148 86.805 ;
     RECT  79.812 86.535 101.52 86.805 ;
     RECT  2.16 87.075 41.148 87.345 ;
     RECT  79.812 87.075 101.52 87.345 ;
     RECT  2.16 87.615 41.148 87.885 ;
     RECT  79.812 87.615 101.52 87.885 ;
     RECT  2.16 88.155 41.148 88.425 ;
     RECT  79.812 88.155 101.52 88.425 ;
     RECT  2.16 88.695 41.148 88.965 ;
     RECT  79.812 88.695 101.52 88.965 ;
     RECT  2.16 89.235 41.148 89.505 ;
     RECT  79.812 89.235 101.52 89.505 ;
     RECT  2.16 89.775 41.148 90.045 ;
     RECT  79.812 89.775 101.52 90.045 ;
     RECT  2.16 90.315 41.148 90.585 ;
     RECT  79.812 90.315 101.52 90.585 ;
     RECT  2.16 90.855 41.148 91.125 ;
     RECT  79.812 90.855 101.52 91.125 ;
     RECT  2.16 91.395 41.148 91.665 ;
     RECT  79.812 91.395 101.52 91.665 ;
     RECT  2.16 91.935 41.148 92.205 ;
     RECT  79.812 91.935 101.52 92.205 ;
     RECT  2.16 92.475 41.148 92.745 ;
     RECT  79.812 92.475 101.52 92.745 ;
     RECT  2.16 93.015 41.148 93.285 ;
     RECT  79.812 93.015 101.52 93.285 ;
     RECT  2.16 93.555 41.148 93.825 ;
     RECT  79.812 93.555 101.52 93.825 ;
     RECT  2.16 94.095 41.148 94.365 ;
     RECT  79.812 94.095 101.52 94.365 ;
     RECT  2.16 94.635 41.148 94.905 ;
     RECT  79.812 94.635 101.52 94.905 ;
     RECT  2.16 95.175 41.148 95.445 ;
     RECT  79.812 95.175 101.52 95.445 ;
     RECT  2.16 95.715 41.148 95.985 ;
     RECT  79.812 95.715 101.52 95.985 ;
     RECT  2.16 96.255 41.148 96.525 ;
     RECT  79.812 96.255 101.52 96.525 ;
     RECT  2.16 96.795 41.148 97.065 ;
     RECT  79.812 96.795 101.52 97.065 ;
     RECT  2.16 97.335 41.148 97.605 ;
     RECT  79.812 97.335 101.52 97.605 ;
     RECT  2.16 97.875 41.148 98.145 ;
     RECT  79.812 97.875 101.52 98.145 ;
     RECT  2.16 98.415 41.148 98.685 ;
     RECT  79.812 98.415 101.52 98.685 ;
     RECT  2.16 98.955 41.148 99.225 ;
     RECT  79.812 98.955 101.52 99.225 ;
     RECT  2.16 99.495 41.148 99.765 ;
     RECT  79.812 99.495 101.52 99.765 ;
     RECT  2.16 100.035 41.148 100.305 ;
     RECT  79.812 100.035 101.52 100.305 ;
     RECT  2.16 100.575 41.148 100.845 ;
     RECT  79.812 100.575 101.52 100.845 ;
     RECT  2.16 101.115 41.148 101.385 ;
     RECT  79.812 101.115 101.52 101.385 ;
     RECT  2.16 101.655 41.148 101.925 ;
     RECT  79.812 101.655 101.52 101.925 ;
     RECT  2.16 102.195 41.148 102.465 ;
     RECT  79.812 102.195 101.52 102.465 ;
     RECT  2.16 102.735 41.148 103.005 ;
     RECT  79.812 102.735 101.52 103.005 ;
     RECT  2.16 103.275 41.148 103.545 ;
     RECT  79.812 103.275 101.52 103.545 ;
     RECT  2.16 103.815 41.148 104.085 ;
     RECT  79.812 103.815 101.52 104.085 ;
     RECT  2.16 104.355 41.148 104.625 ;
     RECT  79.812 104.355 101.52 104.625 ;
     RECT  2.16 104.895 41.148 105.165 ;
     RECT  79.812 104.895 101.52 105.165 ;
     RECT  2.16 105.435 41.148 105.705 ;
     RECT  79.812 105.435 101.52 105.705 ;
     RECT  2.16 105.975 41.148 106.245 ;
     RECT  79.812 105.975 101.52 106.245 ;
     RECT  2.16 106.515 41.148 106.785 ;
     RECT  79.812 106.515 101.52 106.785 ;
     RECT  2.16 107.055 41.148 107.325 ;
     RECT  79.812 107.055 101.52 107.325 ;
     RECT  2.16 107.595 41.148 107.865 ;
     RECT  79.812 107.595 101.52 107.865 ;
     RECT  2.16 108.135 41.148 108.405 ;
     RECT  79.812 108.135 101.52 108.405 ;
     RECT  2.16 108.675 41.148 108.945 ;
     RECT  79.812 108.675 101.52 108.945 ;
     RECT  2.16 109.215 41.148 109.485 ;
     RECT  79.812 109.215 101.52 109.485 ;
     RECT  2.16 109.755 41.148 110.025 ;
     RECT  79.812 109.755 101.52 110.025 ;
     RECT  2.16 110.295 41.148 110.565 ;
     RECT  79.812 110.295 101.52 110.565 ;
     RECT  2.16 110.835 41.148 111.105 ;
     RECT  79.812 110.835 101.52 111.105 ;
     RECT  2.16 111.375 41.148 111.645 ;
     RECT  79.812 111.375 101.52 111.645 ;
     RECT  2.16 111.915 41.148 112.185 ;
     RECT  79.812 111.915 101.52 112.185 ;
     RECT  2.16 112.455 41.148 112.725 ;
     RECT  79.812 112.455 101.52 112.725 ;
     RECT  2.16 112.995 41.148 113.265 ;
     RECT  79.812 112.995 101.52 113.265 ;
     RECT  2.16 113.535 41.148 113.805 ;
     RECT  79.812 113.535 101.52 113.805 ;
     RECT  2.16 114.075 41.148 114.345 ;
     RECT  79.812 114.075 101.52 114.345 ;
     RECT  2.16 114.615 41.148 114.885 ;
     RECT  79.812 114.615 101.52 114.885 ;
     RECT  2.16 115.155 41.148 115.425 ;
     RECT  79.812 115.155 101.52 115.425 ;
     RECT  2.16 115.695 41.148 115.965 ;
     RECT  79.812 115.695 101.52 115.965 ;
     RECT  2.16 116.235 41.148 116.505 ;
     RECT  79.812 116.235 101.52 116.505 ;
     RECT  2.16 116.775 41.148 117.045 ;
     RECT  79.812 116.775 101.52 117.045 ;
     RECT  2.16 117.315 41.148 117.585 ;
     RECT  79.812 117.315 101.52 117.585 ;
     RECT  2.16 117.855 41.148 118.125 ;
     RECT  79.812 117.855 101.52 118.125 ;
     RECT  2.16 118.395 41.148 118.665 ;
     RECT  79.812 118.395 101.52 118.665 ;
     RECT  2.16 118.935 41.148 119.205 ;
     RECT  79.812 118.935 101.52 119.205 ;
     RECT  2.16 119.475 41.148 119.745 ;
     RECT  79.812 119.475 101.52 119.745 ;
     RECT  2.16 120.015 41.148 120.285 ;
     RECT  79.812 120.015 101.52 120.285 ;
     RECT  2.16 120.555 41.148 120.825 ;
     RECT  79.812 120.555 101.52 120.825 ;
     RECT  2.16 121.095 41.148 121.365 ;
     RECT  79.812 121.095 101.52 121.365 ;
     RECT  2.16 121.635 41.148 121.905 ;
     RECT  79.812 121.635 101.52 121.905 ;
     RECT  2.16 122.175 41.148 122.445 ;
     RECT  79.812 122.175 101.52 122.445 ;
     RECT  2.16 122.715 41.148 122.985 ;
     RECT  79.812 122.715 101.52 122.985 ;
     RECT  2.16 123.255 41.148 123.525 ;
     RECT  79.812 123.255 101.52 123.525 ;
     RECT  2.16 123.795 41.148 124.065 ;
     RECT  79.812 123.795 101.52 124.065 ;
     RECT  2.16 124.335 41.148 124.605 ;
     RECT  79.812 124.335 101.52 124.605 ;
     RECT  2.16 124.875 41.148 125.145 ;
     RECT  79.812 124.875 101.52 125.145 ;
     RECT  2.16 125.415 41.148 125.685 ;
     RECT  79.812 125.415 101.52 125.685 ;
     RECT  2.16 125.955 41.148 126.225 ;
     RECT  79.812 125.955 101.52 126.225 ;
     RECT  2.16 126.495 41.148 126.765 ;
     RECT  79.812 126.495 101.52 126.765 ;
     RECT  2.16 127.035 41.148 127.305 ;
     RECT  79.812 127.035 101.52 127.305 ;
     RECT  2.16 127.575 41.148 127.845 ;
     RECT  79.812 127.575 101.52 127.845 ;
     RECT  2.16 128.115 41.148 128.385 ;
     RECT  78.948 128.115 101.52 128.385 ;
     RECT  2.16 128.655 41.148 128.925 ;
     RECT  78.948 128.655 101.52 128.925 ;
     RECT  2.16 129.195 41.148 129.465 ;
     RECT  78.948 129.195 101.52 129.465 ;
     RECT  2.16 129.735 41.148 130.005 ;
     RECT  78.948 129.735 101.52 130.005 ;
     RECT  2.16 130.275 41.148 130.545 ;
     RECT  78.948 130.275 101.52 130.545 ;
     RECT  2.16 130.815 41.148 131.085 ;
     RECT  78.948 130.815 101.52 131.085 ;
     RECT  2.16 131.355 41.148 131.625 ;
     RECT  78.948 131.355 101.52 131.625 ;
     RECT  2.16 131.895 41.148 132.165 ;
     RECT  78.948 131.895 101.52 132.165 ;
     RECT  2.16 132.435 41.148 132.705 ;
     RECT  78.948 132.435 101.52 132.705 ;
     RECT  2.16 132.975 41.148 133.245 ;
     RECT  78.948 132.975 101.52 133.245 ;
     RECT  2.16 133.515 41.148 133.785 ;
     RECT  78.948 133.515 101.52 133.785 ;
     RECT  2.16 134.055 41.148 134.325 ;
     RECT  78.948 134.055 101.52 134.325 ;
     RECT  2.16 134.595 41.148 134.865 ;
     RECT  78.948 134.595 101.52 134.865 ;
     RECT  2.16 135.135 41.148 135.405 ;
     RECT  78.948 135.135 101.52 135.405 ;
     RECT  2.16 135.675 41.148 135.945 ;
     RECT  78.948 135.675 101.52 135.945 ;
     RECT  2.16 136.215 41.148 136.485 ;
     RECT  78.948 136.215 101.52 136.485 ;
     RECT  2.16 136.755 41.148 137.025 ;
     RECT  78.948 136.755 101.52 137.025 ;
     RECT  2.16 137.295 41.148 137.565 ;
     RECT  78.948 137.295 101.52 137.565 ;
     RECT  2.16 137.835 41.148 138.105 ;
     RECT  78.948 137.835 101.52 138.105 ;
     RECT  2.16 138.375 41.148 138.645 ;
     RECT  78.948 138.375 101.52 138.645 ;
     RECT  2.16 138.915 41.148 139.185 ;
     RECT  78.948 138.915 101.52 139.185 ;
     RECT  2.16 139.455 41.148 139.725 ;
     RECT  78.948 139.455 101.52 139.725 ;
     RECT  2.16 139.995 41.148 140.265 ;
     RECT  78.948 139.995 101.52 140.265 ;
     RECT  2.16 140.535 41.148 140.805 ;
     RECT  78.948 140.535 101.52 140.805 ;
     RECT  2.16 141.075 41.148 141.345 ;
     RECT  78.948 141.075 101.52 141.345 ;
     RECT  2.16 141.615 41.148 141.885 ;
     RECT  78.948 141.615 101.52 141.885 ;
     RECT  2.16 142.155 41.148 142.425 ;
     RECT  78.948 142.155 101.52 142.425 ;
     RECT  2.16 142.695 41.148 142.965 ;
     RECT  78.948 142.695 101.52 142.965 ;
     RECT  2.16 143.235 41.148 143.505 ;
     RECT  78.948 143.235 101.52 143.505 ;
     RECT  2.16 143.775 41.148 144.045 ;
     RECT  78.948 143.775 101.52 144.045 ;
     RECT  2.16 144.315 41.148 144.585 ;
     RECT  78.948 144.315 101.52 144.585 ;
     RECT  2.16 144.855 41.148 145.125 ;
     RECT  78.948 144.855 101.52 145.125 ;
     RECT  2.16 145.395 41.148 145.665 ;
     RECT  78.948 145.395 101.52 145.665 ;
     RECT  2.16 145.935 41.148 146.205 ;
     RECT  78.948 145.935 101.52 146.205 ;
     RECT  2.16 146.475 41.148 146.745 ;
     RECT  78.948 146.475 101.52 146.745 ;
     RECT  2.16 147.015 41.148 147.285 ;
     RECT  78.948 147.015 101.52 147.285 ;
     RECT  2.16 147.555 41.148 147.825 ;
     RECT  78.948 147.555 101.52 147.825 ;
     RECT  2.16 148.095 41.148 148.365 ;
     RECT  78.948 148.095 101.52 148.365 ;
     RECT  2.16 148.635 41.148 148.905 ;
     RECT  78.948 148.635 101.52 148.905 ;
     RECT  2.16 149.175 41.148 149.445 ;
     RECT  78.948 149.175 101.52 149.445 ;
     RECT  2.16 149.715 41.148 149.985 ;
     RECT  78.948 149.715 101.52 149.985 ;
     RECT  2.16 150.255 41.148 150.525 ;
     RECT  78.948 150.255 101.52 150.525 ;
     RECT  2.16 150.795 41.148 151.065 ;
     RECT  78.948 150.795 101.52 151.065 ;
     RECT  2.16 151.335 41.148 151.605 ;
     RECT  78.948 151.335 101.52 151.605 ;
     RECT  2.16 151.875 41.148 152.145 ;
     RECT  78.948 151.875 101.52 152.145 ;
     RECT  2.16 152.415 41.148 152.685 ;
     RECT  78.948 152.415 101.52 152.685 ;
     RECT  2.16 152.955 41.148 153.225 ;
     RECT  78.948 152.955 101.52 153.225 ;
     RECT  2.16 153.495 41.148 153.765 ;
     RECT  78.948 153.495 101.52 153.765 ;
     RECT  2.16 154.035 41.148 154.305 ;
     RECT  78.948 154.035 101.52 154.305 ;
     RECT  2.16 154.575 41.148 154.845 ;
     RECT  78.948 154.575 101.52 154.845 ;
     RECT  2.16 155.115 41.148 155.385 ;
     RECT  78.948 155.115 101.52 155.385 ;
     RECT  2.16 155.655 41.148 155.79 ;
     RECT  78.948 155.655 101.52 155.79 ;
     RECT  2.16 155.79 101.52 155.925 ;
     RECT  2.16 156.195 101.52 156.465 ;
     RECT  2.16 156.735 101.52 157.005 ;
     RECT  2.16 157.275 101.52 157.545 ;
     RECT  2.16 157.815 101.52 158.085 ;
     RECT  2.16 158.355 101.52 158.625 ;
     RECT  2.16 158.895 101.52 159.165 ;
     RECT  2.16 159.435 101.52 159.705 ;
     RECT  2.16 159.975 101.52 160.245 ;
     RECT  2.16 160.515 101.52 160.785 ;
     RECT  2.16 161.055 101.52 161.325 ;
     RECT  2.16 161.595 101.52 161.865 ;
     RECT  2.16 162.135 101.52 162.405 ;
     RECT  2.16 162.675 101.52 162.945 ;
     RECT  2.16 163.215 101.52 163.485 ;
     RECT  2.16 163.755 101.52 164.025 ;
     RECT  2.16 164.295 101.52 164.565 ;
     RECT  2.16 164.835 101.52 165.105 ;
     RECT  2.16 165.375 101.52 165.645 ;
     RECT  2.16 165.915 101.52 166.185 ;
     RECT  2.16 166.455 101.52 166.725 ;
     RECT  2.16 166.995 101.52 167.265 ;
     RECT  2.16 167.535 101.52 167.805 ;
     RECT  2.16 168.075 101.52 168.345 ;
     RECT  2.16 168.615 101.52 168.885 ;
     RECT  2.16 169.155 101.52 169.425 ;
     RECT  2.16 169.695 101.52 169.965 ;
     RECT  2.16 170.235 101.52 170.505 ;
     RECT  2.16 170.775 101.52 171.045 ;
     RECT  2.16 171.315 101.52 171.585 ;
     RECT  2.16 171.855 101.52 172.125 ;
     RECT  2.16 172.395 101.52 172.665 ;
     RECT  2.16 172.935 101.52 173.205 ;
     RECT  2.16 173.475 101.52 173.745 ;
     RECT  2.16 174.015 101.52 174.285 ;
     RECT  2.16 174.555 101.52 174.825 ;
     RECT  2.16 175.095 101.52 175.365 ;
     RECT  2.16 175.635 101.52 175.905 ;
     RECT  2.16 176.175 101.52 176.445 ;
     RECT  2.16 176.715 101.52 176.985 ;
     RECT  2.16 177.255 101.52 177.525 ;
     RECT  2.16 177.795 101.52 178.065 ;
     RECT  2.16 178.335 101.52 178.605 ;
     RECT  2.16 178.875 101.52 179.145 ;
    LAYER M1 ;
     RECT  2.16 2.151 101.52 41.049 ;
     RECT  43.2 43.2 77.784 125.928 ;
     RECT  79.812 41.049 101.52 127.971 ;
     RECT  43.2 125.928 76.92 153.528 ;
     RECT  2.16 41.049 41.148 155.781 ;
     RECT  78.948 127.971 101.52 155.781 ;
     RECT  2.16 155.781 101.52 179.289 ;
    LAYER M2 ;
     RECT  0.103 29.502 0.139 29.52 ;
     RECT  0.103 38.412 0.139 40.662 ;
     RECT  0.103 42.462 0.139 42.48 ;
     RECT  0.139 26.298 0.175 26.316 ;
     RECT  0.139 37.602 0.175 37.62 ;
     RECT  0.139 38.412 0.175 42.48 ;
     RECT  0.175 26.298 0.211 26.928 ;
     RECT  0.103 27.756 0.211 28.44 ;
     RECT  0.103 74.016 0.211 74.754 ;
     RECT  0.103 71.424 0.499 72.18 ;
     RECT  0.211 73.314 0.499 74.754 ;
     RECT  0.175 37.602 0.535 42.48 ;
     RECT  0.499 70.776 0.535 74.754 ;
     RECT  0.103 30.582 1.147 31.68 ;
     RECT  0.103 33.552 1.183 33.57 ;
     RECT  0.535 37.602 1.219 43.092 ;
     RECT  1.147 30.582 1.255 32.22 ;
     RECT  1.183 33.048 1.255 33.57 ;
     RECT  1.219 37.602 1.291 43.29 ;
     RECT  1.291 37.602 1.327 43.56 ;
     RECT  0.211 26.298 1.723 28.44 ;
     RECT  0.139 29.34 1.723 29.52 ;
     RECT  1.327 37.602 1.723 43.83 ;
     RECT  0.103 54.306 1.723 54.324 ;
     RECT  1.723 37.332 1.759 43.83 ;
     RECT  1.723 26.298 2.16 29.52 ;
     RECT  1.255 30.582 2.16 33.57 ;
     RECT  1.759 37.062 2.16 43.83 ;
     RECT  0.535 53.532 2.16 53.55 ;
     RECT  1.723 54.306 2.16 54.666 ;
     RECT  0.103 55.656 2.16 55.674 ;
     RECT  0.535 66.906 2.16 66.924 ;
     RECT  0.535 68.076 2.16 69.786 ;
     RECT  0.535 70.65 2.16 74.754 ;
     RECT  0.103 75.636 2.16 75.654 ;
     RECT  2.16 2.151 26.311 179.289 ;
     RECT  26.311 2.106 27.527 179.289 ;
     RECT  27.527 2.151 31.135 179.289 ;
     RECT  31.135 2.106 32.323 179.289 ;
     RECT  32.323 2.034 33.035 179.289 ;
     RECT  33.035 2.151 36.499 179.289 ;
     RECT  36.499 2.151 36.635 179.334 ;
     RECT  36.635 2.151 38.443 179.289 ;
     RECT  38.443 2.106 38.615 179.289 ;
     RECT  38.615 2.151 39.343 179.289 ;
     RECT  39.343 2.106 40.135 179.289 ;
     RECT  40.135 2.034 40.703 179.289 ;
     RECT  40.703 2.106 41.148 179.289 ;
     RECT  41.148 70.92 41.207 71.784 ;
     RECT  41.148 66.096 41.243 66.114 ;
     RECT  41.207 71.226 41.279 71.784 ;
     RECT  41.148 84.924 41.279 86.256 ;
     RECT  41.148 126.846 41.315 127.368 ;
     RECT  41.148 2.106 41.351 46.764 ;
     RECT  41.148 111.924 41.351 111.942 ;
     RECT  41.148 129.402 41.351 131.31 ;
     RECT  41.351 45.432 41.387 46.764 ;
     RECT  41.148 117.288 41.387 117.918 ;
     RECT  41.148 65.286 41.423 65.304 ;
     RECT  41.148 138.276 41.423 138.294 ;
     RECT  41.148 67.338 41.459 67.356 ;
     RECT  41.148 68.958 41.459 69.354 ;
     RECT  41.148 120.366 41.459 120.384 ;
     RECT  41.351 2.106 41.495 44.208 ;
     RECT  41.148 59.238 41.495 59.256 ;
     RECT  41.148 63.936 41.495 64.458 ;
     RECT  41.495 2.151 41.567 44.208 ;
     RECT  41.495 63.936 41.567 64.386 ;
     RECT  41.279 71.766 41.603 71.784 ;
     RECT  41.148 80.136 41.603 80.154 ;
     RECT  41.567 2.151 41.639 43.938 ;
     RECT  41.148 55.836 41.639 55.854 ;
     RECT  41.279 84.924 41.639 84.942 ;
     RECT  41.387 117.288 41.639 117.306 ;
     RECT  41.315 126.846 41.639 126.954 ;
     RECT  41.351 129.402 41.639 131.076 ;
     RECT  41.148 48.006 41.675 53.586 ;
     RECT  41.675 48.006 41.711 53.01 ;
     RECT  41.279 86.076 41.819 86.256 ;
     RECT  41.387 45.666 41.891 46.764 ;
     RECT  41.148 124.686 41.891 124.938 ;
     RECT  41.639 130.716 41.891 131.076 ;
     RECT  41.711 49.014 41.927 53.01 ;
     RECT  41.148 140.778 41.927 140.796 ;
     RECT  41.459 68.958 41.963 69.174 ;
     RECT  41.819 86.166 41.963 86.256 ;
     RECT  41.891 124.92 41.963 124.938 ;
     RECT  41.148 136.656 41.963 137.358 ;
     RECT  41.148 141.696 41.963 141.714 ;
     RECT  41.148 133.83 42.035 135.864 ;
     RECT  41.148 153.576 42.079 153.594 ;
     RECT  41.148 154.386 42.079 179.289 ;
     RECT  41.639 2.151 42.143 43.362 ;
     RECT  41.891 45.666 42.143 46.494 ;
     RECT  42.035 133.83 42.179 135.594 ;
     RECT  41.927 49.014 42.215 51.309 ;
     RECT  41.963 68.958 42.215 68.976 ;
     RECT  41.963 86.238 42.215 86.256 ;
     RECT  41.148 94.068 42.215 95.436 ;
     RECT  41.148 108.108 42.215 108.126 ;
     RECT  41.148 128.124 42.215 128.646 ;
     RECT  42.143 45.666 42.251 45.684 ;
     RECT  42.215 50.634 42.287 50.652 ;
     RECT  41.711 48.006 42.323 48.024 ;
     RECT  42.215 49.014 42.431 49.608 ;
     RECT  42.431 49.59 42.467 49.608 ;
     RECT  42.143 2.151 42.475 43.326 ;
     RECT  42.475 2.106 43.2 43.326 ;
     RECT  42.143 46.476 43.2 46.494 ;
     RECT  41.927 52.452 43.2 52.47 ;
     RECT  41.148 54.45 43.2 54.936 ;
     RECT  41.567 63.936 43.2 63.954 ;
     RECT  41.148 88.398 43.2 88.416 ;
     RECT  42.215 94.338 43.2 95.436 ;
     RECT  41.148 121.644 43.2 121.662 ;
     RECT  41.639 126.846 43.2 126.864 ;
     RECT  42.215 128.124 43.2 128.142 ;
     RECT  41.639 129.402 43.2 129.834 ;
     RECT  41.891 130.716 43.2 130.734 ;
     RECT  41.148 132.786 43.2 132.804 ;
     RECT  42.179 133.83 43.2 134.784 ;
     RECT  42.179 135.576 43.2 135.594 ;
     RECT  41.963 137.34 43.2 137.358 ;
     RECT  42.079 153.576 43.2 179.289 ;
     RECT  43.2 2.106 43.879 179.289 ;
     RECT  44.455 0.576 45.031 0.594 ;
     RECT  45.031 0.576 45.275 1.17 ;
     RECT  45.275 1.152 46.183 1.17 ;
     RECT  43.879 2.034 46.967 179.289 ;
     RECT  46.183 1.152 47.003 1.278 ;
     RECT  47.003 1.26 47.543 1.278 ;
     RECT  48.055 1.152 48.191 1.17 ;
     RECT  49.063 1.224 49.307 1.242 ;
     RECT  49.315 1.152 49.415 1.17 ;
     RECT  51.367 1.152 51.683 1.17 ;
     RECT  46.967 2.151 76.92 179.289 ;
     RECT  76.92 146.484 77.063 146.502 ;
     RECT  76.92 2.151 77.784 125.928 ;
     RECT  76.92 139.896 77.791 140.634 ;
     RECT  77.784 2.151 77.963 42.894 ;
     RECT  77.784 77.904 77.999 78.768 ;
     RECT  77.971 129.636 78.007 129.654 ;
     RECT  76.92 130.482 78.007 130.536 ;
     RECT  78.007 129.636 78.043 129.726 ;
     RECT  78.007 130.482 78.043 132.156 ;
     RECT  77.963 2.151 78.071 42.75 ;
     RECT  77.999 77.976 78.071 78.696 ;
     RECT  78.043 128.628 78.079 133.308 ;
     RECT  78.043 134.946 78.079 136.17 ;
     RECT  77.784 43.776 78.619 44.64 ;
     RECT  77.784 46.854 78.619 47.178 ;
     RECT  77.784 48.204 78.619 48.456 ;
     RECT  78.079 128.466 78.619 133.308 ;
     RECT  78.079 134.136 78.619 136.17 ;
     RECT  77.784 46.08 78.655 46.098 ;
     RECT  77.791 139.896 78.655 140.904 ;
     RECT  78.619 46.854 78.691 48.456 ;
     RECT  77.784 49.212 78.691 54.09 ;
     RECT  77.784 88.236 78.691 95.364 ;
     RECT  78.655 96.192 78.691 96.21 ;
     RECT  78.071 2.151 78.935 42.516 ;
     RECT  78.619 128.16 78.948 136.17 ;
     RECT  78.655 139.806 78.948 140.904 ;
     RECT  76.92 150.876 78.948 150.894 ;
     RECT  76.92 153.576 78.948 179.289 ;
     RECT  78.619 43.776 79.231 44.946 ;
     RECT  78.655 45.702 79.231 46.098 ;
     RECT  78.691 88.236 79.231 96.21 ;
     RECT  78.907 77.166 79.483 77.184 ;
     RECT  77.784 86.742 79.699 87.102 ;
     RECT  79.231 87.966 79.699 96.21 ;
     RECT  78.619 85.896 79.735 85.914 ;
     RECT  79.699 86.742 79.735 96.21 ;
     RECT  79.735 85.896 79.807 96.21 ;
     RECT  78.935 2.151 79.812 42.48 ;
     RECT  79.231 43.776 79.812 46.098 ;
     RECT  78.691 46.854 79.812 54.09 ;
     RECT  78.943 58.968 79.812 58.986 ;
     RECT  79.807 67.95 79.812 67.968 ;
     RECT  79.483 76.626 79.812 77.184 ;
     RECT  78.071 77.976 79.812 77.994 ;
     RECT  79.807 85.158 79.812 96.21 ;
     RECT  77.784 116.856 79.812 116.874 ;
     RECT  79.267 118.206 79.812 118.224 ;
     RECT  78.948 127.971 79.812 179.289 ;
     RECT  79.812 2.151 101.52 179.289 ;
     RECT  101.52 134.406 102.011 141.876 ;
     RECT  101.52 34.902 102.083 39.24 ;
     RECT  101.52 117.09 102.515 118.656 ;
     RECT  101.52 119.448 102.515 120.006 ;
     RECT  102.083 34.902 102.587 35.46 ;
     RECT  102.083 36.252 102.587 39.24 ;
     RECT  101.52 77.292 102.587 81.504 ;
     RECT  102.515 117.09 102.587 118.386 ;
     RECT  102.515 119.988 102.587 120.006 ;
     RECT  102.011 134.496 102.587 141.876 ;
     RECT  102.587 34.902 102.623 34.92 ;
     RECT  102.587 134.874 102.623 136.512 ;
     RECT  102.587 138.348 102.623 138.672 ;
     RECT  102.587 139.626 102.623 141.876 ;
     RECT  102.587 38.79 103.523 39.24 ;
     RECT  102.623 138.348 103.523 138.564 ;
     RECT  102.587 36.666 103.559 37.422 ;
     RECT  103.523 38.826 103.559 39.24 ;
     RECT  103.559 36.666 103.595 36.684 ;
     RECT  103.559 38.826 103.595 38.844 ;
     RECT  102.587 78.138 103.595 80.892 ;
     RECT  102.623 134.874 103.595 134.892 ;
     RECT  102.623 135.882 103.595 135.9 ;
     RECT  102.587 137.376 103.595 137.394 ;
     RECT  103.523 138.348 103.595 138.366 ;
     RECT  102.623 139.806 103.595 141.876 ;
    LAYER M3 ;
     RECT  32.472 0.091 34.722 0.139 ;
     RECT  37.476 0.091 37.494 0.139 ;
     RECT  44.028 0.091 46.89 0.139 ;
     RECT  47.628 0.091 49.086 0.139 ;
     RECT  50.04 0.091 50.706 0.139 ;
     RECT  52.164 0.091 52.182 0.139 ;
     RECT  26.748 0.091 26.766 0.187 ;
     RECT  26.748 0.187 26.802 0.523 ;
     RECT  30.24 0.091 30.258 0.523 ;
     RECT  31.392 0.091 31.41 0.523 ;
     RECT  32.148 0.139 34.722 0.523 ;
     RECT  39.96 0.091 39.978 0.523 ;
     RECT  51.552 0.139 52.182 0.523 ;
     RECT  26.352 0.523 26.802 0.571 ;
     RECT  29.304 0.523 29.322 0.571 ;
     RECT  30.24 0.523 34.722 0.571 ;
     RECT  36.612 0.139 37.494 0.571 ;
     RECT  38.268 0.523 38.286 0.571 ;
     RECT  39.528 0.523 39.978 0.571 ;
     RECT  41.256 0.091 41.598 0.571 ;
     RECT  42.696 0.091 43.11 0.571 ;
     RECT  44.028 0.139 50.706 0.571 ;
     RECT  54.036 0.091 54.054 0.571 ;
     RECT  36.216 0.571 37.494 0.619 ;
     RECT  54.036 0.571 54.306 0.619 ;
     RECT  26.064 0.571 26.802 1.099 ;
     RECT  36.144 0.619 37.494 1.147 ;
     RECT  43.992 0.571 50.706 1.147 ;
     RECT  51.444 0.523 52.182 1.147 ;
     RECT  35.604 1.147 37.494 1.195 ;
     RECT  38.268 0.571 39.978 1.195 ;
     RECT  40.788 0.571 43.146 1.195 ;
     RECT  43.992 1.147 52.182 1.195 ;
     RECT  26.064 1.099 27.378 1.723 ;
     RECT  29.304 0.571 34.722 1.723 ;
     RECT  53.352 0.619 54.306 1.723 ;
     RECT  26.064 1.723 27.954 1.771 ;
     RECT  35.496 1.195 39.978 2.029 ;
     RECT  40.788 1.195 52.47 2.029 ;
     RECT  29.124 1.723 34.722 2.143 ;
     RECT  35.496 2.029 52.47 2.143 ;
     RECT  26.064 1.771 28.242 2.191 ;
     RECT  29.124 2.143 52.47 2.191 ;
     RECT  26.064 2.191 52.47 2.299 ;
     RECT  53.208 1.723 54.306 2.299 ;
     RECT  26.064 2.299 54.306 2.347 ;
     RECT  2.415 2.143 2.505 2.413 ;
     RECT  7.815 2.143 7.905 2.413 ;
     RECT  13.215 2.143 13.305 2.413 ;
     RECT  18.615 2.143 18.705 2.413 ;
     RECT  24.015 2.143 24.105 2.413 ;
     RECT  56.415 2.143 56.505 2.413 ;
     RECT  61.815 2.143 61.905 2.413 ;
     RECT  67.215 2.143 67.305 2.413 ;
     RECT  72.615 2.143 72.705 2.413 ;
     RECT  78.015 2.143 78.105 2.413 ;
     RECT  83.415 2.143 83.505 2.413 ;
     RECT  88.815 2.143 88.905 2.413 ;
     RECT  94.215 2.143 94.305 2.413 ;
     RECT  99.615 2.143 99.705 2.413 ;
     RECT  26.064 2.347 54.954 2.497 ;
     RECT  25.848 2.497 54.954 2.759 ;
     RECT  25.848 2.759 54.882 2.861 ;
     RECT  25.956 2.861 54.882 3.029 ;
     RECT  25.956 3.029 54.81 3.299 ;
     RECT  25.956 3.299 54.342 3.641 ;
     RECT  25.956 3.641 54.09 3.649 ;
     RECT  25.668 3.649 54.09 3.931 ;
     RECT  25.308 3.931 54.09 3.983 ;
     RECT  25.776 3.983 54.09 4.459 ;
     RECT  25.776 4.459 54.162 4.541 ;
     RECT  25.884 4.541 54.162 4.649 ;
     RECT  25.884 4.649 54.054 4.685 ;
     RECT  25.884 4.685 53.802 5.603 ;
     RECT  25.812 5.605 25.83 5.645 ;
     RECT  27.036 5.603 53.802 5.909 ;
     RECT  27.036 5.909 53.082 6.331 ;
     RECT  26.964 6.331 53.082 6.377 ;
     RECT  27.432 6.377 53.082 6.539 ;
     RECT  27.828 6.539 53.082 6.683 ;
     RECT  27.828 6.683 29.697 6.719 ;
     RECT  32.832 6.683 53.082 6.719 ;
     RECT  31.536 6.683 31.806 6.809 ;
     RECT  32.904 6.719 53.082 6.809 ;
     RECT  27.828 6.719 28.278 6.845 ;
     RECT  36.936 6.809 51.606 6.845 ;
     RECT  30.492 6.683 30.762 6.881 ;
     RECT  32.904 6.809 36.198 7.079 ;
     RECT  36.936 6.845 51.297 7.079 ;
     RECT  38.16 7.079 46.134 7.151 ;
     RECT  46.98 7.079 48.654 7.151 ;
     RECT  49.716 7.079 51.297 7.151 ;
     RECT  38.34 7.151 46.134 7.187 ;
     RECT  46.98 7.151 48.474 7.187 ;
     RECT  38.34 7.187 45.897 7.223 ;
     RECT  38.772 7.223 45.897 7.259 ;
     RECT  49.716 7.151 49.806 7.259 ;
     RECT  32.904 7.079 35.334 7.349 ;
     RECT  38.772 7.259 44.838 7.349 ;
     RECT  46.98 7.187 46.998 7.349 ;
     RECT  47.808 7.187 48.474 7.349 ;
     RECT  50.724 7.151 51.297 7.349 ;
     RECT  49.716 7.259 49.734 7.373 ;
     RECT  52.344 6.809 53.082 7.373 ;
     RECT  34.776 7.349 35.334 7.421 ;
     RECT  36.18 7.079 36.198 7.421 ;
     RECT  50.868 7.349 51.297 7.421 ;
     RECT  52.38 7.373 53.082 7.565 ;
     RECT  38.772 7.349 41.166 7.619 ;
     RECT  42.444 7.349 43.038 7.619 ;
     RECT  44.064 7.349 44.442 7.619 ;
     RECT  42.444 7.619 42.462 7.727 ;
     RECT  34.815 7.421 35.334 7.799 ;
     RECT  38.808 7.619 41.166 8.429 ;
     RECT  52.704 7.565 53.082 8.671 ;
     RECT  52.2 8.671 53.082 8.699 ;
     RECT  48.456 7.349 48.474 8.815 ;
     RECT  48.456 8.815 48.798 8.843 ;
     RECT  38.952 8.429 41.166 9.779 ;
     RECT  32.904 7.349 33.822 11.069 ;
     RECT  33.66 11.069 33.822 11.407 ;
     RECT  33.66 11.407 33.93 11.435 ;
     RECT  33.912 11.435 33.93 12.091 ;
     RECT  33.912 12.091 33.966 12.479 ;
     RECT  33.876 12.595 33.894 12.749 ;
     RECT  32.904 11.069 32.922 12.757 ;
     RECT  32.904 12.757 33.462 12.829 ;
     RECT  32.58 12.829 33.462 12.893 ;
     RECT  32.724 12.893 33.462 13.055 ;
     RECT  52.2 8.699 53.01 14.639 ;
     RECT  51.015 7.421 51.297 14.731 ;
     RECT  52.2 14.639 52.722 14.731 ;
     RECT  32.724 13.055 32.85 14.827 ;
     RECT  32.724 14.827 33.534 14.909 ;
     RECT  32.724 14.909 33.426 15.101 ;
     RECT  51.015 14.731 52.722 15.691 ;
     RECT  50.976 15.691 52.722 15.979 ;
     RECT  50.4 15.979 52.722 16.069 ;
     RECT  50.4 16.069 52.974 16.231 ;
     RECT  49.716 16.231 52.974 16.375 ;
     RECT  48.78 8.843 48.798 16.405 ;
     RECT  49.716 16.375 53.226 16.405 ;
     RECT  48.78 16.405 53.226 16.411 ;
     RECT  30.564 6.881 30.762 16.501 ;
     RECT  31.788 6.809 31.806 16.529 ;
     RECT  48.78 16.411 53.586 16.609 ;
     RECT  46.764 16.609 46.782 16.709 ;
     RECT  48.78 16.609 53.802 16.807 ;
     RECT  48.708 16.807 53.802 17.077 ;
     RECT  48.708 17.077 53.874 17.083 ;
     RECT  48.06 17.083 53.874 17.311 ;
     RECT  30.564 16.501 30.87 17.339 ;
     RECT  22.824 17.179 22.842 17.357 ;
     RECT  17.1 17.083 17.118 17.467 ;
     RECT  31.608 16.609 31.77 17.491 ;
     RECT  32.724 15.101 32.85 17.491 ;
     RECT  30.564 17.339 30.834 17.501 ;
     RECT  17.1 17.467 17.406 17.609 ;
     RECT  48.06 17.311 54.126 17.609 ;
     RECT  31.608 17.491 32.85 17.645 ;
     RECT  48.312 17.609 54.126 17.681 ;
     RECT  17.388 17.609 17.406 17.879 ;
     RECT  32.724 17.645 32.85 18.235 ;
     RECT  32.724 18.235 33.39 18.571 ;
     RECT  48.312 17.681 53.874 18.571 ;
     RECT  54.936 18.499 54.954 18.571 ;
     RECT  31.608 17.645 31.626 18.667 ;
     RECT  32.652 18.571 33.39 18.667 ;
     RECT  31.608 18.667 33.39 18.689 ;
     RECT  31.608 18.689 32.922 18.797 ;
     RECT  32.436 18.797 32.922 18.995 ;
     RECT  48.312 18.571 54.954 19.111 ;
     RECT  48.204 19.111 55.062 19.309 ;
     RECT  48.024 19.309 55.278 19.579 ;
     RECT  47.592 19.579 55.278 19.615 ;
     RECT  47.232 19.615 55.278 20.083 ;
     RECT  46.872 20.083 55.278 20.695 ;
     RECT  46.872 20.695 55.35 20.779 ;
     RECT  46.656 20.779 55.35 20.849 ;
     RECT  41.544 21.163 41.562 21.2 ;
     RECT  46.872 20.849 55.35 21.811 ;
     RECT  56.415 2.413 56.697 21.811 ;
     RECT  46.872 21.811 56.697 21.929 ;
     RECT  46.872 21.929 55.35 22.747 ;
     RECT  46.62 22.747 55.35 22.811 ;
     RECT  46.8 22.811 55.35 22.855 ;
     RECT  56.415 21.929 56.697 22.855 ;
     RECT  46.8 22.855 56.697 23.009 ;
     RECT  46.872 23.009 55.35 23.971 ;
     RECT  46.836 23.971 55.35 24.241 ;
     RECT  46.764 24.241 55.35 24.331 ;
     RECT  45.615 7.259 45.897 24.469 ;
     RECT  46.692 24.331 55.35 24.469 ;
     RECT  45.615 24.469 55.35 24.511 ;
     RECT  56.415 23.009 56.697 24.511 ;
     RECT  27.9 6.845 28.278 24.781 ;
     RECT  29.052 6.719 29.697 24.781 ;
     RECT  27.9 24.781 29.697 25.015 ;
     RECT  30.564 17.501 30.582 25.015 ;
     RECT  45.615 24.511 56.697 25.241 ;
     RECT  27.9 25.015 30.582 25.439 ;
     RECT  27.9 25.439 30.366 25.889 ;
     RECT  45.615 25.241 55.278 25.949 ;
     RECT  28.26 25.889 30.366 26.015 ;
     RECT  28.26 26.015 30.078 26.123 ;
     RECT  2.415 2.413 2.697 26.221 ;
     RECT  2.34 26.221 2.697 26.365 ;
     RECT  2.304 26.365 2.697 26.401 ;
     RECT  46.62 25.949 55.278 26.401 ;
     RECT  56.415 25.241 56.697 26.401 ;
     RECT  28.26 26.123 30.042 26.519 ;
     RECT  2.304 26.401 2.754 26.635 ;
     RECT  45.615 25.949 45.897 26.671 ;
     RECT  46.62 26.401 56.697 26.671 ;
     RECT  2.304 26.635 2.826 26.761 ;
     RECT  45.615 26.671 56.697 26.789 ;
     RECT  43.308 26.761 43.326 26.833 ;
     RECT  42.516 26.833 42.534 26.869 ;
     RECT  43.308 26.833 43.974 26.869 ;
     RECT  0.144 26.293 0.162 26.905 ;
     RECT  42.516 26.869 43.974 26.941 ;
     RECT  0.144 26.905 0.198 27.067 ;
     RECT  0.144 27.067 0.234 27.103 ;
     RECT  83.415 2.413 83.697 27.445 ;
     RECT  0.144 27.103 0.27 27.499 ;
     RECT  2.304 26.761 3.474 27.679 ;
     RECT  2.304 27.679 3.618 27.715 ;
     RECT  42.516 26.941 44.226 27.751 ;
     RECT  45.615 26.789 55.278 27.751 ;
     RECT  56.415 26.789 56.697 27.751 ;
     RECT  42.516 27.751 56.697 27.869 ;
     RECT  6.984 27.751 7.002 27.913 ;
     RECT  7.815 2.413 8.097 27.913 ;
     RECT  42.516 27.869 44.55 27.928 ;
     RECT  2.304 27.715 3.942 27.985 ;
     RECT  2.304 27.985 4.374 28.021 ;
     RECT  5.112 27.751 5.85 28.021 ;
     RECT  6.984 27.913 8.097 28.021 ;
     RECT  2.304 28.021 5.85 28.147 ;
     RECT  43.956 27.928 44.55 28.175 ;
     RECT  2.268 28.147 5.85 28.291 ;
     RECT  6.588 28.021 8.097 28.291 ;
     RECT  0.108 27.499 0.27 28.397 ;
     RECT  31.608 18.797 31.626 28.409 ;
     RECT  45.615 27.869 56.697 28.409 ;
     RECT  83.415 27.445 84.078 28.417 ;
     RECT  0.108 28.397 0.126 28.445 ;
     RECT  83.415 28.417 85.194 28.493 ;
     RECT  2.268 28.291 8.097 28.525 ;
     RECT  28.26 26.519 29.697 28.561 ;
     RECT  32.436 18.995 32.742 28.561 ;
     RECT  31.5 28.525 31.518 28.679 ;
     RECT  43.956 28.175 44.442 28.751 ;
     RECT  2.268 28.525 8.298 28.759 ;
     RECT  28.26 28.561 30.294 28.795 ;
     RECT  42.516 27.928 43.074 28.831 ;
     RECT  43.956 28.751 43.974 28.831 ;
     RECT  45.615 28.409 55.638 28.831 ;
     RECT  28.26 28.795 31.266 28.949 ;
     RECT  2.232 28.759 8.298 28.985 ;
     RECT  30.996 28.949 31.014 28.985 ;
     RECT  2.232 28.985 8.097 28.993 ;
     RECT  11.088 28.831 11.106 29.029 ;
     RECT  1.728 28.993 8.097 29.261 ;
     RECT  28.26 28.949 29.898 29.327 ;
     RECT  0.144 29.335 0.162 29.371 ;
     RECT  9.036 28.381 9.054 29.371 ;
     RECT  10.08 28.291 10.098 29.371 ;
     RECT  45.504 28.831 55.638 29.371 ;
     RECT  56.415 28.409 56.697 29.371 ;
     RECT  27.324 29.335 27.342 29.461 ;
     RECT  26.676 29.461 27.342 29.489 ;
     RECT  28.26 29.327 29.754 29.489 ;
     RECT  83.415 28.493 84.87 29.525 ;
     RECT  11.088 29.029 11.358 29.569 ;
     RECT  45.504 29.371 56.697 29.633 ;
     RECT  28.26 29.489 28.278 29.641 ;
     RECT  45.504 29.633 55.494 29.645 ;
     RECT  84.42 29.525 84.87 29.645 ;
     RECT  2.268 29.261 8.097 30.181 ;
     RECT  9.036 29.371 10.098 30.181 ;
     RECT  83.415 29.525 83.697 30.235 ;
     RECT  83.232 30.235 83.697 30.299 ;
     RECT  0.108 29.371 0.162 30.413 ;
     RECT  2.268 30.181 8.154 30.451 ;
     RECT  8.928 30.181 10.098 30.451 ;
     RECT  42.516 28.831 43.974 30.451 ;
     RECT  1.152 29.803 1.17 30.523 ;
     RECT  38.952 9.779 40.497 30.613 ;
     RECT  45.615 29.645 55.494 30.613 ;
     RECT  56.415 29.633 56.697 30.613 ;
     RECT  2.268 30.451 10.098 30.721 ;
     RECT  11.088 29.569 11.502 30.721 ;
     RECT  42.516 30.451 44.154 30.721 ;
     RECT  45.615 30.613 56.697 30.859 ;
     RECT  1.152 30.523 1.206 30.955 ;
     RECT  42.516 30.721 44.442 31.117 ;
     RECT  45.288 30.859 56.697 31.117 ;
     RECT  2.268 30.721 11.502 31.145 ;
     RECT  34.815 7.799 35.097 31.387 ;
     RECT  2.34 31.145 11.502 31.423 ;
     RECT  34.815 31.387 35.154 31.424 ;
     RECT  38.952 30.613 40.554 31.459 ;
     RECT  32.436 28.561 33.066 31.487 ;
     RECT  38.952 31.459 40.95 31.495 ;
     RECT  38.952 31.495 41.238 31.531 ;
     RECT  83.34 30.299 83.697 31.531 ;
     RECT  2.34 31.423 12.078 31.559 ;
     RECT  1.152 30.955 1.242 31.675 ;
     RECT  38.952 31.531 41.67 31.829 ;
     RECT  41.364 31.829 41.67 31.919 ;
     RECT  1.152 31.675 1.278 32.225 ;
     RECT  42.516 31.117 56.697 32.225 ;
     RECT  2.415 31.559 12.078 32.305 ;
     RECT  2.376 32.305 12.078 32.459 ;
     RECT  2.376 32.459 3.402 32.495 ;
     RECT  2.376 32.495 3.33 32.701 ;
     RECT  2.304 32.701 3.33 32.729 ;
     RECT  4.176 32.459 12.078 32.729 ;
     RECT  1.188 32.225 1.278 32.873 ;
     RECT  99.615 2.413 99.897 32.881 ;
     RECT  100.98 32.845 101.178 32.881 ;
     RECT  2.304 32.729 3.258 32.909 ;
     RECT  94.215 2.413 94.497 32.923 ;
     RECT  96.012 32.701 96.03 32.999 ;
     RECT  42.516 32.225 55.494 33.043 ;
     RECT  1.188 32.873 1.206 33.071 ;
     RECT  4.212 32.729 12.078 33.071 ;
     RECT  42.264 33.043 55.494 33.079 ;
     RECT  94.215 32.923 94.698 33.101 ;
     RECT  8.928 33.071 12.078 33.115 ;
     RECT  2.304 32.909 2.898 33.269 ;
     RECT  42.264 33.079 55.566 33.269 ;
     RECT  8.928 33.115 12.15 33.313 ;
     RECT  13.215 2.413 13.497 33.313 ;
     RECT  44.496 33.269 55.566 33.313 ;
     RECT  56.415 32.225 56.697 33.313 ;
     RECT  99.615 32.881 101.178 33.313 ;
     RECT  41.364 31.919 41.382 33.349 ;
     RECT  42.264 33.269 43.758 33.349 ;
     RECT  4.212 33.071 8.097 33.377 ;
     RECT  99.615 33.313 101.322 33.421 ;
     RECT  25.452 33.499 25.794 33.539 ;
     RECT  0.108 30.413 0.126 33.575 ;
     RECT  84.852 29.645 84.87 33.619 ;
     RECT  84.708 33.619 84.87 33.647 ;
     RECT  2.304 33.269 2.697 33.845 ;
     RECT  84.708 33.647 84.726 33.917 ;
     RECT  25.488 33.539 25.506 33.923 ;
     RECT  99.432 33.421 101.322 33.925 ;
     RECT  99.432 33.925 101.466 33.961 ;
     RECT  41.364 33.349 43.758 34.075 ;
     RECT  44.496 33.313 56.697 34.075 ;
     RECT  15.768 33.421 15.786 34.231 ;
     RECT  16.776 33.961 16.794 34.231 ;
     RECT  38.952 31.829 40.497 34.231 ;
     RECT  41.364 34.075 56.697 34.231 ;
     RECT  95.832 33.889 95.85 34.231 ;
     RECT  98.784 33.961 101.466 34.231 ;
     RECT  38.952 34.231 56.697 34.321 ;
     RECT  95.544 34.231 95.85 34.357 ;
     RECT  36.792 34.393 36.81 34.465 ;
     RECT  37.584 33.079 37.602 34.465 ;
     RECT  6.372 33.377 8.097 34.493 ;
     RECT  95.292 34.357 96.066 34.501 ;
     RECT  6.768 34.493 8.097 34.529 ;
     RECT  36.792 34.465 37.602 34.591 ;
     RECT  92.916 34.501 92.934 34.727 ;
     RECT  36.792 34.591 37.962 34.735 ;
     RECT  95.292 34.501 96.786 34.735 ;
     RECT  34.815 31.424 35.097 34.771 ;
     RECT  95.256 34.735 96.786 34.771 ;
     RECT  98.136 34.231 101.466 34.771 ;
     RECT  36.648 34.735 37.962 34.795 ;
     RECT  32.436 31.487 32.742 34.861 ;
     RECT  36.252 34.795 37.962 34.897 ;
     RECT  38.772 34.321 56.697 34.897 ;
     RECT  102.492 34.699 102.51 34.897 ;
     RECT  8.928 33.313 13.497 34.925 ;
     RECT  95.256 34.771 101.466 34.925 ;
     RECT  34.776 34.771 35.097 34.961 ;
     RECT  95.292 34.925 101.466 34.987 ;
     RECT  102.492 34.897 102.618 34.987 ;
     RECT  4.212 33.377 5.418 35.033 ;
     RECT  8.964 34.925 13.497 35.033 ;
     RECT  95.292 34.987 102.618 35.033 ;
     RECT  4.212 35.033 5.382 35.195 ;
     RECT  9.036 35.033 13.497 35.203 ;
     RECT  36.252 34.897 56.697 35.231 ;
     RECT  95.4 35.033 102.618 35.267 ;
     RECT  17.856 34.501 17.874 35.311 ;
     RECT  36.864 35.231 56.697 35.537 ;
     RECT  4.32 35.195 5.382 35.573 ;
     RECT  92.916 35.509 92.934 35.609 ;
     RECT  37.188 35.537 56.697 35.735 ;
     RECT  101.988 35.267 102.618 35.741 ;
     RECT  101.988 35.741 102.582 35.771 ;
     RECT  9.036 35.203 13.554 35.807 ;
     RECT  38.772 35.735 56.697 35.843 ;
     RECT  26.676 29.489 26.694 35.941 ;
     RECT  95.4 35.267 101.214 35.969 ;
     RECT  26.676 35.941 26.802 35.977 ;
     RECT  27.54 29.641 28.278 35.977 ;
     RECT  34.815 34.961 35.097 36.049 ;
     RECT  94.215 33.101 94.497 36.085 ;
     RECT  4.32 35.573 5.346 36.113 ;
     RECT  90.72 36.049 90.738 36.121 ;
     RECT  90.648 36.121 90.738 36.149 ;
     RECT  15.768 34.231 16.794 36.211 ;
     RECT  17.748 35.311 17.874 36.211 ;
     RECT  4.32 36.113 4.95 36.239 ;
     RECT  26.676 35.977 28.278 36.247 ;
     RECT  29.052 29.489 29.754 36.247 ;
     RECT  26.676 36.247 29.754 36.283 ;
     RECT  34.776 36.049 35.097 36.283 ;
     RECT  103.536 35.851 103.554 36.283 ;
     RECT  37.188 35.735 38.034 36.319 ;
     RECT  90.648 36.149 90.666 36.419 ;
     RECT  95.4 35.969 101.106 36.419 ;
     RECT  94.215 36.085 94.59 36.461 ;
     RECT  26.532 36.283 29.754 36.475 ;
     RECT  37.116 36.319 38.034 36.475 ;
     RECT  25.992 36.475 29.754 36.517 ;
     RECT  38.808 35.843 56.697 36.523 ;
     RECT  4.32 36.239 4.878 36.545 ;
     RECT  102.528 35.771 102.582 36.545 ;
     RECT  36.54 36.475 38.034 36.553 ;
     RECT  6.84 34.529 8.097 36.581 ;
     RECT  25.812 36.517 29.754 36.589 ;
     RECT  34.056 36.283 35.097 36.625 ;
     RECT  38.808 36.523 57.006 36.653 ;
     RECT  15.768 36.211 17.874 36.661 ;
     RECT  18.615 2.413 18.897 36.661 ;
     RECT  31.176 36.589 31.194 36.661 ;
     RECT  36.072 36.553 38.034 36.661 ;
     RECT  38.808 36.653 56.697 36.661 ;
     RECT  24.015 2.413 24.297 36.751 ;
     RECT  14.796 36.619 14.814 36.797 ;
     RECT  23.904 36.751 24.297 36.797 ;
     RECT  4.32 36.545 4.338 36.815 ;
     RECT  30.492 36.661 31.194 36.823 ;
     RECT  61.815 2.413 62.097 36.823 ;
     RECT  33.912 36.625 35.097 36.859 ;
     RECT  96.624 36.419 101.106 36.859 ;
     RECT  2.415 33.845 2.697 36.895 ;
     RECT  3.492 36.859 3.51 36.931 ;
     RECT  33.912 36.859 35.298 36.931 ;
     RECT  36.072 36.661 56.697 36.931 ;
     RECT  30.492 36.823 31.41 36.959 ;
     RECT  96.624 36.859 101.178 37.003 ;
     RECT  25.668 36.589 29.754 37.021 ;
     RECT  33.912 36.931 56.697 37.037 ;
     RECT  56.376 37.037 56.697 37.049 ;
     RECT  2.376 36.895 2.697 37.057 ;
     RECT  1.764 37.057 2.697 37.093 ;
     RECT  33.912 37.037 55.494 37.093 ;
     RECT  95.4 36.419 95.814 37.093 ;
     RECT  1.764 37.093 2.718 37.129 ;
     RECT  3.492 36.931 3.654 37.129 ;
     RECT  9.108 35.807 13.554 37.129 ;
     RECT  33.84 37.093 55.494 37.129 ;
     RECT  9.108 37.129 13.662 37.165 ;
     RECT  9 37.165 13.662 37.319 ;
     RECT  1.764 37.129 3.654 37.327 ;
     RECT  30.492 36.959 30.87 37.355 ;
     RECT  61.815 36.823 62.154 37.355 ;
     RECT  95.292 37.093 95.814 37.355 ;
     RECT  6.048 36.391 6.066 37.363 ;
     RECT  6.84 36.581 6.858 37.363 ;
     RECT  24.015 36.797 24.297 37.429 ;
     RECT  25.308 37.021 29.754 37.429 ;
     RECT  24.015 37.429 29.754 37.435 ;
     RECT  102.564 36.545 102.582 37.435 ;
     RECT  24.015 37.435 29.79 37.469 ;
     RECT  1.728 37.327 3.654 37.561 ;
     RECT  7.815 36.581 8.097 37.561 ;
     RECT  9 37.319 13.497 37.561 ;
     RECT  96.624 37.003 101.466 37.561 ;
     RECT  15.768 36.661 18.897 37.589 ;
     RECT  95.544 37.355 95.814 37.589 ;
     RECT  15.84 37.589 18.897 37.625 ;
     RECT  25.308 37.469 29.79 37.625 ;
     RECT  22.86 37.201 22.878 37.669 ;
     RECT  1.728 37.561 4.014 37.705 ;
     RECT  5.148 37.201 5.166 37.705 ;
     RECT  22.86 37.669 22.95 37.741 ;
     RECT  92.916 37.669 92.934 37.769 ;
     RECT  30.78 37.355 30.87 37.831 ;
     RECT  0.144 37.597 0.162 37.867 ;
     RECT  1.728 37.705 5.166 37.901 ;
     RECT  33.768 37.129 55.494 37.903 ;
     RECT  33.66 37.903 55.494 37.931 ;
     RECT  6.048 37.363 6.858 37.939 ;
     RECT  32.436 34.861 32.814 37.939 ;
     RECT  33.66 37.931 36.63 37.939 ;
     RECT  6.048 37.939 6.93 37.975 ;
     RECT  7.815 37.561 13.497 37.975 ;
     RECT  1.764 37.901 5.166 38.005 ;
     RECT  1.764 38.005 5.202 38.011 ;
     RECT  6.048 37.975 13.497 38.011 ;
     RECT  1.764 38.011 13.497 38.045 ;
     RECT  30.78 37.831 31.554 38.101 ;
     RECT  94.215 36.461 94.497 38.101 ;
     RECT  95.544 37.589 95.778 38.101 ;
     RECT  21.096 37.363 21.114 38.129 ;
     RECT  30.744 38.101 31.554 38.129 ;
     RECT  32.436 37.939 36.63 38.129 ;
     RECT  0.144 37.867 0.198 38.137 ;
     RECT  22.824 37.741 22.95 38.137 ;
     RECT  103.536 36.283 103.59 38.155 ;
     RECT  26.28 37.625 29.79 38.165 ;
     RECT  37.368 37.931 55.494 38.173 ;
     RECT  56.415 37.049 56.697 38.173 ;
     RECT  1.8 38.045 13.497 38.189 ;
     RECT  22.14 38.137 22.95 38.203 ;
     RECT  24.015 37.469 24.534 38.203 ;
     RECT  26.676 38.165 29.79 38.209 ;
     RECT  30.744 38.129 31.23 38.209 ;
     RECT  15.984 37.625 18.897 38.237 ;
     RECT  0.144 38.137 0.234 38.299 ;
     RECT  25.308 37.625 25.47 38.309 ;
     RECT  94.215 38.101 95.778 38.371 ;
     RECT  96.588 37.561 101.466 38.371 ;
     RECT  2.304 38.189 13.497 38.381 ;
     RECT  26.676 38.209 31.23 38.399 ;
     RECT  94.215 38.371 101.466 38.399 ;
     RECT  26.676 38.399 29.898 38.477 ;
     RECT  22.14 38.203 24.534 38.543 ;
     RECT  92.988 38.281 93.006 38.543 ;
     RECT  24.015 38.543 24.534 38.551 ;
     RECT  6.048 38.381 13.497 38.669 ;
     RECT  22.14 38.543 23.238 38.669 ;
     RECT  25.38 38.309 25.47 38.669 ;
     RECT  94.215 38.399 95.922 38.669 ;
     RECT  36.576 38.129 36.63 38.677 ;
     RECT  37.368 38.173 56.697 38.677 ;
     RECT  23.184 38.669 23.238 38.705 ;
     RECT  24.015 38.551 24.642 38.705 ;
     RECT  26.676 38.477 29.79 38.705 ;
     RECT  30.744 38.399 31.23 38.705 ;
     RECT  95.76 38.669 95.778 38.705 ;
     RECT  102.564 37.435 102.618 38.705 ;
     RECT  6.048 38.669 8.19 38.717 ;
     RECT  70.704 38.539 70.722 38.717 ;
     RECT  24.015 38.705 24.354 38.777 ;
     RECT  103.5 38.155 103.59 38.813 ;
     RECT  103.536 38.813 103.59 38.849 ;
     RECT  36.576 38.677 56.697 38.939 ;
     RECT  94.215 38.669 94.842 38.939 ;
     RECT  98.604 38.399 101.466 38.975 ;
     RECT  98.604 38.975 101.394 39.011 ;
     RECT  32.436 38.129 35.802 39.019 ;
     RECT  36.576 38.939 46.134 39.019 ;
     RECT  16.2 38.237 18.897 39.047 ;
     RECT  26.676 38.705 29.754 39.047 ;
     RECT  102.6 38.705 102.618 39.083 ;
     RECT  98.604 39.011 98.766 39.119 ;
     RECT  2.304 38.381 5.274 39.209 ;
     RECT  32.436 39.019 46.134 39.209 ;
     RECT  33.552 39.209 46.134 39.245 ;
     RECT  103.536 38.849 103.554 39.245 ;
     RECT  2.304 39.209 4.158 39.289 ;
     RECT  16.2 39.047 16.218 39.325 ;
     RECT  5.112 39.209 5.274 39.361 ;
     RECT  16.02 39.325 16.218 39.479 ;
     RECT  1.728 39.289 4.158 39.485 ;
     RECT  30.744 38.705 30.906 39.487 ;
     RECT  2.304 39.485 4.158 39.515 ;
     RECT  30.744 39.487 31.338 39.587 ;
     RECT  46.908 38.939 56.697 39.587 ;
     RECT  5.112 39.361 5.31 39.595 ;
     RECT  6.048 38.717 8.097 39.595 ;
     RECT  16.02 39.479 16.11 39.595 ;
     RECT  5.112 39.595 8.097 39.631 ;
     RECT  8.928 38.669 13.497 39.631 ;
     RECT  22.14 38.669 22.158 39.631 ;
     RECT  23.184 38.705 23.202 39.631 ;
     RECT  78.015 2.413 78.297 39.631 ;
     RECT  0.108 38.299 0.234 39.721 ;
     RECT  14.832 39.631 14.85 39.749 ;
     RECT  15.912 39.595 16.11 39.749 ;
     RECT  21.42 39.631 23.202 39.749 ;
     RECT  46.908 39.587 55.098 39.749 ;
     RECT  21.42 39.749 21.762 39.757 ;
     RECT  27.432 39.047 29.754 39.785 ;
     RECT  48.6 39.749 54.954 39.785 ;
     RECT  22.788 39.749 23.202 39.821 ;
     RECT  27.54 39.785 27.99 39.821 ;
     RECT  28.764 39.785 29.754 39.821 ;
     RECT  98.748 39.119 98.766 39.821 ;
     RECT  48.672 39.785 54.234 39.857 ;
     RECT  24.015 38.777 24.297 39.883 ;
     RECT  25.524 39.721 25.542 39.883 ;
     RECT  61.815 37.355 62.097 39.883 ;
     RECT  49.752 39.857 54.234 39.893 ;
     RECT  26.676 39.047 26.694 39.901 ;
     RECT  20.88 39.757 21.762 39.917 ;
     RECT  56.304 39.587 56.697 39.929 ;
     RECT  61.815 39.883 62.802 39.931 ;
     RECT  49.752 39.893 54.054 40.019 ;
     RECT  99.615 39.011 101.394 40.019 ;
     RECT  67.215 2.413 67.497 40.027 ;
     RECT  74.772 39.883 74.79 40.027 ;
     RECT  21.024 39.917 21.762 40.055 ;
     RECT  48.672 39.857 48.942 40.055 ;
     RECT  74.664 40.027 74.79 40.061 ;
     RECT  49.752 40.019 49.77 40.091 ;
     RECT  99.615 40.019 101.322 40.091 ;
     RECT  46.908 39.749 47.358 40.099 ;
     RECT  67.215 40.027 67.518 40.123 ;
     RECT  24.015 39.883 25.542 40.127 ;
     RECT  26.28 39.901 26.694 40.135 ;
     RECT  61.815 39.931 62.874 40.157 ;
     RECT  99.615 40.091 100.422 40.157 ;
     RECT  24.015 40.127 25.146 40.163 ;
     RECT  50.58 40.019 54.054 40.163 ;
     RECT  29.052 39.821 29.754 40.171 ;
     RECT  48.924 40.055 48.942 40.199 ;
     RECT  2.415 39.515 4.158 40.261 ;
     RECT  5.112 39.631 13.497 40.289 ;
     RECT  21.024 40.055 21.042 40.289 ;
     RECT  25.884 40.135 26.694 40.289 ;
     RECT  46.764 40.099 47.358 40.289 ;
     RECT  51.015 40.163 54.054 40.289 ;
     RECT  101.16 40.091 101.322 40.289 ;
     RECT  32.436 39.209 32.742 40.297 ;
     RECT  33.624 39.245 45.897 40.297 ;
     RECT  81 40.261 81.018 40.301 ;
     RECT  17.028 39.047 18.897 40.325 ;
     RECT  26.244 40.289 26.694 40.325 ;
     RECT  29.052 40.171 30.114 40.325 ;
     RECT  52.272 40.289 53.55 40.325 ;
     RECT  46.8 40.289 47.358 40.349 ;
     RECT  61.815 40.157 62.73 40.349 ;
     RECT  67.215 40.123 67.626 40.349 ;
     RECT  74.664 40.061 74.682 40.349 ;
     RECT  52.704 40.325 53.514 40.361 ;
     RECT  5.112 40.289 8.154 40.397 ;
     RECT  22.824 39.821 23.202 40.397 ;
     RECT  26.316 40.325 26.694 40.397 ;
     RECT  31.32 39.587 31.338 40.397 ;
     RECT  8.928 40.289 13.497 40.405 ;
     RECT  0.108 39.721 0.558 40.433 ;
     RECT  2.415 40.261 4.374 40.441 ;
     RECT  5.112 40.397 8.097 40.441 ;
     RECT  52.704 40.361 53.334 40.469 ;
     RECT  80.712 40.411 80.73 40.469 ;
     RECT  25.128 40.163 25.146 40.559 ;
     RECT  101.16 40.289 101.25 40.559 ;
     RECT  32.436 40.297 45.897 40.595 ;
     RECT  101.16 40.559 101.178 40.595 ;
     RECT  8.928 40.405 13.698 40.631 ;
     RECT  36.468 40.595 45.897 40.631 ;
     RECT  96.66 38.399 97.866 40.699 ;
     RECT  30.78 40.603 30.798 40.703 ;
     RECT  32.436 40.595 35.622 40.703 ;
     RECT  36.468 40.631 44.406 40.703 ;
     RECT  2.415 40.441 8.097 40.711 ;
     RECT  32.436 40.703 33.966 40.739 ;
     RECT  96.66 40.699 98.586 40.739 ;
     RECT  45.288 40.631 45.897 40.795 ;
     RECT  56.415 39.929 56.697 40.795 ;
     RECT  72.615 2.413 72.897 40.795 ;
     RECT  80.316 40.555 80.334 40.801 ;
     RECT  36.468 40.703 43.938 40.829 ;
     RECT  45.288 40.795 45.99 40.835 ;
     RECT  51.015 40.289 51.39 40.835 ;
     RECT  56.415 40.795 56.79 40.835 ;
     RECT  61.815 40.349 62.19 40.835 ;
     RECT  67.215 40.349 67.59 40.835 ;
     RECT  72.615 40.795 72.99 40.835 ;
     RECT  78.015 39.631 78.966 40.891 ;
     RECT  79.992 40.801 80.334 40.891 ;
     RECT  2.34 40.711 8.097 40.973 ;
     RECT  88.815 2.413 89.097 40.981 ;
     RECT  2.34 40.973 6.93 41.009 ;
     RECT  97.812 40.739 98.586 41.021 ;
     RECT  51.015 40.835 51.105 41.057 ;
     RECT  61.815 40.835 61.905 41.057 ;
     RECT  72.615 40.835 72.705 41.057 ;
     RECT  56.415 40.835 56.61 41.071 ;
     RECT  67.215 40.835 67.41 41.071 ;
     RECT  78.015 40.891 80.334 41.071 ;
     RECT  82.908 31.531 83.697 41.071 ;
     RECT  45.288 40.835 45.81 41.117 ;
     RECT  56.304 41.071 56.61 41.117 ;
     RECT  67.104 41.071 67.41 41.117 ;
     RECT  77.904 41.071 80.334 41.117 ;
     RECT  99.615 40.157 99.897 41.179 ;
     RECT  2.34 41.009 6.858 41.215 ;
     RECT  32.436 40.739 33.642 41.251 ;
     RECT  82.692 41.071 83.697 41.251 ;
     RECT  2.304 41.215 6.858 41.279 ;
     RECT  34.815 40.703 35.622 41.341 ;
     RECT  36.468 40.829 43.47 41.341 ;
     RECT  27.54 39.821 27.594 41.369 ;
     RECT  8.928 40.631 13.497 41.405 ;
     RECT  32.22 41.251 33.642 41.405 ;
     RECT  45.288 41.117 45.306 41.405 ;
     RECT  0.108 40.433 0.162 41.467 ;
     RECT  1.152 41.323 1.17 41.467 ;
     RECT  76.968 41.377 76.986 41.477 ;
     RECT  86.652 41.377 86.67 41.477 ;
     RECT  82.368 41.251 83.697 41.521 ;
     RECT  17.208 40.325 18.897 41.549 ;
     RECT  78.156 41.117 80.334 41.597 ;
     RECT  82.26 41.521 83.697 41.597 ;
     RECT  0.108 41.467 1.17 41.611 ;
     RECT  88.632 40.981 89.097 41.611 ;
     RECT  34.815 41.341 43.47 41.675 ;
     RECT  6.552 41.279 6.858 41.755 ;
     RECT  7.74 40.973 8.097 41.755 ;
     RECT  97.812 41.021 98.046 41.755 ;
     RECT  98.856 41.179 99.897 41.755 ;
     RECT  88.416 41.611 89.097 41.791 ;
     RECT  46.908 40.349 47.358 41.819 ;
     RECT  88.092 41.791 89.097 41.837 ;
     RECT  78.156 41.597 79.506 41.851 ;
     RECT  0.108 41.611 1.206 41.899 ;
     RECT  90.108 41.881 90.126 41.917 ;
     RECT  95.436 41.881 95.454 41.933 ;
     RECT  17.208 41.549 17.838 41.945 ;
     RECT  34.815 41.675 36.63 41.981 ;
     RECT  96.66 40.739 96.678 41.989 ;
     RECT  86.688 41.917 86.706 42.017 ;
     RECT  90.108 41.917 90.702 42.017 ;
     RECT  0.108 41.899 1.242 42.043 ;
     RECT  94.215 38.939 94.497 42.061 ;
     RECT  89.928 42.061 89.946 42.125 ;
     RECT  94.215 42.061 95.13 42.125 ;
     RECT  96.624 41.989 96.678 42.151 ;
     RECT  97.812 41.755 99.897 42.151 ;
     RECT  8.928 41.405 10.89 42.179 ;
     RECT  17.64 41.945 17.838 42.179 ;
     RECT  0.108 42.043 1.278 42.187 ;
     RECT  2.304 41.279 5.742 42.187 ;
     RECT  6.552 41.755 8.097 42.187 ;
     RECT  78.084 41.851 79.506 42.223 ;
     RECT  2.304 42.187 8.097 42.323 ;
     RECT  0.108 42.187 1.314 42.331 ;
     RECT  47.34 41.819 47.358 42.359 ;
     RECT  4.428 42.323 8.097 42.449 ;
     RECT  0.108 42.331 1.35 42.485 ;
     RECT  17.82 42.179 17.838 42.485 ;
     RECT  15.912 39.749 15.93 42.521 ;
     RECT  2.304 42.323 3.402 42.557 ;
     RECT  77.904 42.223 79.506 42.565 ;
     RECT  9.972 42.179 10.89 42.601 ;
     RECT  11.628 41.405 13.497 42.601 ;
     RECT  32.436 41.405 33.642 42.691 ;
     RECT  9.972 42.601 13.497 42.755 ;
     RECT  32.292 42.691 33.642 42.763 ;
     RECT  34.815 41.981 35.802 42.763 ;
     RECT  36.612 41.981 36.63 42.763 ;
     RECT  87.264 42.961 87.282 43.037 ;
     RECT  0.54 42.485 1.35 43.097 ;
     RECT  34.815 42.763 36.63 43.099 ;
     RECT  37.44 41.675 43.47 43.099 ;
     RECT  34.815 43.099 43.47 43.139 ;
     RECT  37.224 43.139 43.47 43.2 ;
     RECT  52.704 40.469 52.722 43.2 ;
     RECT  77.832 42.565 79.506 43.2 ;
     RECT  32.22 42.763 33.642 43.291 ;
     RECT  1.224 43.097 1.35 43.295 ;
     RECT  37.224 43.2 79.506 43.325 ;
     RECT  86.976 43.141 86.994 43.325 ;
     RECT  11.628 42.755 12.366 43.439 ;
     RECT  31.644 43.291 33.642 43.529 ;
     RECT  1.296 43.295 1.35 43.565 ;
     RECT  37.44 43.325 79.506 43.771 ;
     RECT  80.316 41.597 80.334 43.771 ;
     RECT  1.332 43.565 1.35 43.835 ;
     RECT  37.44 43.771 80.334 43.843 ;
     RECT  2.304 42.557 3.33 44.105 ;
     RECT  37.44 43.843 80.874 44.149 ;
     RECT  31.932 43.529 33.642 44.443 ;
     RECT  31.284 44.443 33.642 44.455 ;
     RECT  37.26 44.149 80.874 44.477 ;
     RECT  31.284 44.455 33.678 44.485 ;
     RECT  34.815 43.139 36.234 44.485 ;
     RECT  31.284 44.485 36.234 44.731 ;
     RECT  37.26 44.477 80.334 44.731 ;
     RECT  31.284 44.731 80.334 44.761 ;
     RECT  30.96 44.761 80.334 44.995 ;
     RECT  30.852 44.995 80.334 45.031 ;
     RECT  26.676 40.397 26.694 45.157 ;
     RECT  26.676 45.157 26.766 45.301 ;
     RECT  30.492 45.031 80.334 45.301 ;
     RECT  30.492 45.301 80.55 45.533 ;
     RECT  29.052 40.325 29.754 45.571 ;
     RECT  30.492 45.533 80.334 45.571 ;
     RECT  26.676 45.301 26.802 45.725 ;
     RECT  26.676 45.725 26.766 45.731 ;
     RECT  29.052 45.571 80.334 46.309 ;
     RECT  29.052 46.309 80.406 46.913 ;
     RECT  30.672 46.913 80.406 46.921 ;
     RECT  11.628 43.439 11.97 47.039 ;
     RECT  30.672 46.921 80.442 47.039 ;
     RECT  22.068 47.011 22.086 47.119 ;
     RECT  22.068 47.119 22.194 47.131 ;
     RECT  21.636 47.131 22.194 47.155 ;
     RECT  21.636 47.155 22.446 47.191 ;
     RECT  23.184 40.397 23.202 47.191 ;
     RECT  21.636 47.191 23.202 47.317 ;
     RECT  29.052 46.913 29.862 47.695 ;
     RECT  18.615 41.549 18.897 47.851 ;
     RECT  29.052 47.695 29.898 47.857 ;
     RECT  30.708 47.039 80.442 47.857 ;
     RECT  20.34 47.317 23.202 48.235 ;
     RECT  18.615 47.851 19.35 48.271 ;
     RECT  20.268 48.235 23.202 48.271 ;
     RECT  24.015 40.163 24.297 48.271 ;
     RECT  29.052 47.857 80.442 48.271 ;
     RECT  28.872 48.271 80.442 48.317 ;
     RECT  28.872 48.317 80.334 48.361 ;
     RECT  28.728 48.361 80.334 48.413 ;
     RECT  18.615 48.271 19.494 48.461 ;
     RECT  20.268 48.271 24.297 48.775 ;
     RECT  20.268 48.775 24.606 48.811 ;
     RECT  20.268 48.811 25.038 48.973 ;
     RECT  29.052 48.413 80.334 49.085 ;
     RECT  78.912 49.085 80.334 49.432 ;
     RECT  78.912 49.432 80.658 49.469 ;
     RECT  78.912 49.469 80.37 49.577 ;
     RECT  27.54 41.369 27.558 49.585 ;
     RECT  18.615 48.461 18.897 49.819 ;
     RECT  20.016 48.973 25.038 49.819 ;
     RECT  27.54 49.585 28.17 49.981 ;
     RECT  27.54 49.981 28.242 50.017 ;
     RECT  29.052 49.085 78.102 50.017 ;
     RECT  27.54 50.017 78.102 50.107 ;
     RECT  78.912 49.577 80.334 50.107 ;
     RECT  18.615 49.819 25.038 50.125 ;
     RECT  27.54 50.107 80.334 50.153 ;
     RECT  78.912 50.153 80.334 50.431 ;
     RECT  78.912 50.431 80.586 50.525 ;
     RECT  27.54 50.153 78.102 50.899 ;
     RECT  78.912 50.525 80.334 50.899 ;
     RECT  27.54 50.899 80.334 50.999 ;
     RECT  18.615 50.125 25.074 51.745 ;
     RECT  18.615 51.745 25.65 51.899 ;
     RECT  18.615 51.899 25.326 51.943 ;
     RECT  78.912 50.999 80.334 52.051 ;
     RECT  18.612 51.943 25.326 52.177 ;
     RECT  18.54 52.177 25.326 52.205 ;
     RECT  27.54 50.999 78.102 52.285 ;
     RECT  78.912 52.051 80.37 52.285 ;
     RECT  27.54 52.285 80.37 52.591 ;
     RECT  27.54 52.591 80.442 52.637 ;
     RECT  8.928 42.179 8.946 53.563 ;
     RECT  9.972 42.755 10.89 53.563 ;
     RECT  8.928 53.563 10.89 53.591 ;
     RECT  4.5 42.449 8.097 53.671 ;
     RECT  18.54 52.205 25.11 53.671 ;
     RECT  2.415 44.105 3.33 53.761 ;
     RECT  27.54 52.637 80.334 53.933 ;
     RECT  27.54 53.933 78.102 53.941 ;
     RECT  18.504 53.671 25.11 54.095 ;
     RECT  2.415 53.761 3.402 54.211 ;
     RECT  4.176 53.671 8.097 54.211 ;
     RECT  0.54 53.527 0.558 54.283 ;
     RECT  0.108 54.283 0.558 54.329 ;
     RECT  2.415 54.211 8.097 54.571 ;
     RECT  2.304 54.571 8.097 54.643 ;
     RECT  18.54 54.095 25.11 54.715 ;
     RECT  18.54 54.715 25.29 54.751 ;
     RECT  1.728 54.643 8.097 54.893 ;
     RECT  26.676 45.731 26.694 54.949 ;
     RECT  27.468 53.941 78.102 54.949 ;
     RECT  2.304 54.893 8.097 55.021 ;
     RECT  8.928 53.591 10.422 55.021 ;
     RECT  2.304 55.021 10.422 55.049 ;
     RECT  0.54 54.329 0.558 55.181 ;
     RECT  18.54 54.751 25.722 55.211 ;
     RECT  2.415 55.049 10.422 55.553 ;
     RECT  0.144 55.291 0.162 55.579 ;
     RECT  0.108 55.579 0.162 55.679 ;
     RECT  18.54 55.211 25.146 55.679 ;
     RECT  26.676 54.949 78.102 55.715 ;
     RECT  0.144 55.679 0.162 56.093 ;
     RECT  2.415 55.553 8.097 56.155 ;
     RECT  2.304 56.155 8.097 56.219 ;
     RECT  18.54 55.679 25.038 56.327 ;
     RECT  27.54 55.715 78.102 56.605 ;
     RECT  26.676 55.715 26.694 57.109 ;
     RECT  27.504 56.605 78.102 57.109 ;
     RECT  18.54 56.327 24.966 57.569 ;
     RECT  2.415 56.219 8.097 57.581 ;
     RECT  18.576 57.569 24.966 57.685 ;
     RECT  18.576 57.685 25.11 58.351 ;
     RECT  18.576 58.351 25.434 58.531 ;
     RECT  26.676 57.109 78.102 58.531 ;
     RECT  96.624 42.151 99.897 58.963 ;
     RECT  8.928 55.553 10.422 58.991 ;
     RECT  18.576 58.531 78.102 59.467 ;
     RECT  18.54 59.467 78.102 59.531 ;
     RECT  18.576 59.531 78.102 59.801 ;
     RECT  18.615 59.801 78.102 60.071 ;
     RECT  26.244 60.071 78.102 60.305 ;
     RECT  88.815 41.837 89.097 60.421 ;
     RECT  94.215 42.125 94.497 60.421 ;
     RECT  96.012 58.963 99.897 60.427 ;
     RECT  88.704 60.421 89.097 60.461 ;
     RECT  94.104 60.421 94.497 60.461 ;
     RECT  95.76 60.427 99.897 60.539 ;
     RECT  95.796 60.539 99.897 60.995 ;
     RECT  18.615 60.071 25.11 61.159 ;
     RECT  18.615 61.159 25.83 61.867 ;
     RECT  26.604 60.305 78.102 61.867 ;
     RECT  18.615 61.867 78.102 63.005 ;
     RECT  18.615 63.005 25.254 63.275 ;
     RECT  18.615 63.275 24.858 63.509 ;
     RECT  13.215 42.755 13.497 64.021 ;
     RECT  11.88 47.039 11.97 64.12 ;
     RECT  14.832 64.027 14.85 64.157 ;
     RECT  26.208 63.005 78.102 64.165 ;
     RECT  13.215 64.021 13.734 64.349 ;
     RECT  11.88 64.12 12.186 64.355 ;
     RECT  18.615 63.509 24.714 64.471 ;
     RECT  26.1 64.165 78.102 64.471 ;
     RECT  18.615 64.471 78.102 64.625 ;
     RECT  2.415 57.581 4.914 65.003 ;
     RECT  18.615 64.625 25.398 65.515 ;
     RECT  26.208 64.625 78.102 65.515 ;
     RECT  10.404 58.991 10.422 65.543 ;
     RECT  18.615 65.515 78.102 66.209 ;
     RECT  25.74 66.209 78.102 66.245 ;
     RECT  26.316 66.245 78.102 66.389 ;
     RECT  3.564 65.003 4.914 66.451 ;
     RECT  5.724 57.581 8.097 66.451 ;
     RECT  14.832 66.361 14.85 66.587 ;
     RECT  2.415 65.003 2.697 66.619 ;
     RECT  2.415 66.619 2.79 66.721 ;
     RECT  3.564 66.451 8.097 66.721 ;
     RECT  18.615 66.209 25.002 66.893 ;
     RECT  0.54 66.901 0.558 66.989 ;
     RECT  2.415 66.721 8.097 67.099 ;
     RECT  26.388 66.389 78.102 67.339 ;
     RECT  25.776 67.339 78.102 67.441 ;
     RECT  25.668 67.441 78.102 67.559 ;
     RECT  18.615 66.893 24.714 67.595 ;
     RECT  0.144 67.243 0.162 67.661 ;
     RECT  19.764 67.595 24.714 67.703 ;
     RECT  2.304 67.099 8.097 67.711 ;
     RECT  8.928 58.991 9.414 67.711 ;
     RECT  2.304 67.711 9.414 68.009 ;
     RECT  20.16 67.703 24.714 68.369 ;
     RECT  25.776 67.559 78.102 68.405 ;
     RECT  0.54 68.071 0.558 68.539 ;
     RECT  26.28 68.405 78.102 68.675 ;
     RECT  20.448 68.369 24.714 68.881 ;
     RECT  11.88 64.355 12.042 69.223 ;
     RECT  11.88 69.223 12.114 69.259 ;
     RECT  20.448 68.881 24.858 69.331 ;
     RECT  20.232 69.331 24.858 69.403 ;
     RECT  0.144 68.539 0.558 69.437 ;
     RECT  11.88 69.259 12.258 69.449 ;
     RECT  11.88 69.449 12.186 69.493 ;
     RECT  26.46 68.675 78.102 69.493 ;
     RECT  2.415 68.009 9.414 69.521 ;
     RECT  26.1 69.493 78.102 69.533 ;
     RECT  20.088 69.403 24.858 69.601 ;
     RECT  2.415 69.521 8.154 69.691 ;
     RECT  20.088 69.601 25.074 69.719 ;
     RECT  20.088 69.719 20.106 69.791 ;
     RECT  20.988 69.719 24.858 69.863 ;
     RECT  0.54 69.437 0.558 69.869 ;
     RECT  20.988 69.863 24.498 69.989 ;
     RECT  21.492 69.989 24.498 70.025 ;
     RECT  21.492 70.025 22.626 70.061 ;
     RECT  23.544 70.025 24.498 70.061 ;
     RECT  2.304 69.691 8.154 70.169 ;
     RECT  21.492 70.061 22.518 70.259 ;
     RECT  21.492 70.259 22.266 70.367 ;
     RECT  21.492 70.367 21.51 70.403 ;
     RECT  22.248 70.367 22.266 70.403 ;
     RECT  2.415 70.169 8.154 70.565 ;
     RECT  0.144 70.315 0.162 70.645 ;
     RECT  26.316 69.533 78.102 70.681 ;
     RECT  8.928 69.521 9.414 71.069 ;
     RECT  2.415 70.565 8.097 71.185 ;
     RECT  2.34 71.185 8.097 71.221 ;
     RECT  0.144 70.645 0.558 71.275 ;
     RECT  8.928 71.069 9.054 71.339 ;
     RECT  2.304 71.221 8.097 71.383 ;
     RECT  0.108 71.275 0.558 71.453 ;
     RECT  2.304 71.383 8.154 71.491 ;
     RECT  26.28 70.681 78.102 71.491 ;
     RECT  25.812 71.491 78.102 71.645 ;
     RECT  11.844 69.493 12.186 71.761 ;
     RECT  13.215 64.349 13.497 71.761 ;
     RECT  26.244 71.645 78.102 71.879 ;
     RECT  11.844 71.761 13.497 72.149 ;
     RECT  9.036 71.339 9.054 72.157 ;
     RECT  0.108 71.453 0.126 72.184 ;
     RECT  0.108 72.184 0.162 72.185 ;
     RECT  12.384 72.149 12.402 72.185 ;
     RECT  2.304 71.491 8.19 72.301 ;
     RECT  8.928 72.157 9.054 72.301 ;
     RECT  2.304 72.301 9.054 72.329 ;
     RECT  2.304 72.329 8.946 72.455 ;
     RECT  0.144 72.185 0.162 72.571 ;
     RECT  1.152 71.851 1.17 72.571 ;
     RECT  82.908 41.597 83.697 72.797 ;
     RECT  81.72 72.769 81.738 72.841 ;
     RECT  0.144 72.571 1.17 72.893 ;
     RECT  81.72 72.841 81.954 72.959 ;
     RECT  2.304 72.455 8.298 72.995 ;
     RECT  1.152 72.893 1.17 73.265 ;
     RECT  2.415 72.995 8.298 73.301 ;
     RECT  0.144 72.893 0.234 73.337 ;
     RECT  22.824 72.715 22.842 73.661 ;
     RECT  0.144 73.337 0.162 73.757 ;
     RECT  2.415 73.301 8.154 74.155 ;
     RECT  2.415 74.155 8.406 74.309 ;
     RECT  0.108 73.867 0.126 74.768 ;
     RECT  2.415 74.309 8.154 74.965 ;
     RECT  101.232 74.965 101.25 75.001 ;
     RECT  0.144 75.019 0.342 75.197 ;
     RECT  101.232 75.001 101.358 75.199 ;
     RECT  24.015 70.061 24.297 75.355 ;
     RECT  25.668 75.355 25.686 75.395 ;
     RECT  101.232 75.199 101.394 75.505 ;
     RECT  0.144 75.197 0.162 75.533 ;
     RECT  0.108 75.595 0.126 75.659 ;
     RECT  24.015 75.355 24.39 75.659 ;
     RECT  2.376 74.965 8.154 75.739 ;
     RECT  2.304 75.739 8.154 76.199 ;
     RECT  100.908 75.505 101.394 76.307 ;
     RECT  100.908 76.307 101.322 76.351 ;
     RECT  2.415 76.199 3.582 76.469 ;
     RECT  96.012 60.995 99.897 76.477 ;
     RECT  100.728 76.351 101.322 76.477 ;
     RECT  26.46 71.879 78.102 76.613 ;
     RECT  4.608 76.199 8.097 76.649 ;
     RECT  78.912 53.933 80.334 76.649 ;
     RECT  3.42 76.469 3.582 76.739 ;
     RECT  5.112 76.649 5.67 76.739 ;
     RECT  6.444 76.649 8.097 76.739 ;
     RECT  5.112 76.739 5.13 76.811 ;
     RECT  96.012 76.477 101.322 77.125 ;
     RECT  95.616 77.125 101.322 77.153 ;
     RECT  6.624 76.739 8.097 77.189 ;
     RECT  78.912 76.649 78.93 77.189 ;
     RECT  94.215 60.461 94.497 77.275 ;
     RECT  95.616 77.153 101.178 77.275 ;
     RECT  26.46 76.613 26.694 77.827 ;
     RECT  102.564 76.891 102.582 77.899 ;
     RECT  27.54 76.613 78.102 77.999 ;
     RECT  94.215 77.275 101.178 77.999 ;
     RECT  26.208 77.827 26.694 78.043 ;
     RECT  96.552 77.999 101.178 78.043 ;
     RECT  102.024 77.899 102.582 78.043 ;
     RECT  25.488 78.043 26.694 78.089 ;
     RECT  94.215 77.999 95.814 78.089 ;
     RECT  96.552 78.043 102.582 78.089 ;
     RECT  25.56 78.089 26.694 78.241 ;
     RECT  88.815 60.461 89.097 78.331 ;
     RECT  27.54 77.999 78.066 78.359 ;
     RECT  94.215 78.089 95.778 78.359 ;
     RECT  86.616 78.187 86.634 78.365 ;
     RECT  88.704 78.331 89.097 78.368 ;
     RECT  90.72 78.331 90.738 78.461 ;
     RECT  94.215 78.359 95.742 78.461 ;
     RECT  3.456 76.739 3.582 78.629 ;
     RECT  95.472 78.461 95.742 78.665 ;
     RECT  96.696 78.089 102.582 78.665 ;
     RECT  96.696 78.665 101.502 78.797 ;
     RECT  94.215 78.461 94.662 78.935 ;
     RECT  95.616 78.665 95.742 78.971 ;
     RECT  96.696 78.797 101.322 79.003 ;
     RECT  96.624 79.003 101.322 79.051 ;
     RECT  24.015 75.659 24.297 79.141 ;
     RECT  96.516 79.051 101.322 79.169 ;
     RECT  24.015 79.141 24.354 79.177 ;
     RECT  24.015 79.177 24.39 79.285 ;
     RECT  25.56 78.241 26.802 79.285 ;
     RECT  3.456 78.629 3.474 79.349 ;
     RECT  24.015 79.285 26.802 79.411 ;
     RECT  102.528 78.665 102.582 79.439 ;
     RECT  23.94 79.411 26.802 79.531 ;
     RECT  23.364 79.531 26.802 79.555 ;
     RECT  95.652 78.971 95.742 79.591 ;
     RECT  96.516 79.169 100.89 79.591 ;
     RECT  23.364 79.555 27.45 79.681 ;
     RECT  28.188 78.359 78.066 79.681 ;
     RECT  86.508 78.907 86.526 79.681 ;
     RECT  23.364 79.681 78.066 79.709 ;
     RECT  95.652 79.591 100.89 79.853 ;
     RECT  96.624 79.853 100.89 79.915 ;
     RECT  88.815 78.368 89.097 79.951 ;
     RECT  96.624 79.915 101.106 79.979 ;
     RECT  95.652 79.853 95.886 79.997 ;
     RECT  23.364 79.709 26.982 80.023 ;
     RECT  97.884 79.979 101.106 80.095 ;
     RECT  23.22 80.023 26.982 80.221 ;
     RECT  94.215 78.935 94.497 80.221 ;
     RECT  97.884 80.095 101.322 80.285 ;
     RECT  98.028 80.285 101.322 80.347 ;
     RECT  102.564 79.439 102.582 80.347 ;
     RECT  98.028 80.347 102.582 80.357 ;
     RECT  88.704 79.951 89.097 80.395 ;
     RECT  98.064 80.357 102.582 80.519 ;
     RECT  22.608 80.221 26.982 80.555 ;
     RECT  98.064 80.519 101.178 80.555 ;
     RECT  98.064 80.555 101.106 80.591 ;
     RECT  22.644 80.555 26.982 80.599 ;
     RECT  88.56 80.395 89.097 80.635 ;
     RECT  27.792 79.709 78.066 80.699 ;
     RECT  95.652 79.997 95.85 80.761 ;
     RECT  96.624 79.979 96.966 80.761 ;
     RECT  98.064 80.591 100.566 80.789 ;
     RECT  94.215 80.221 94.59 80.813 ;
     RECT  103.572 77.179 103.59 80.897 ;
     RECT  83.124 72.797 83.697 80.923 ;
     RECT  86.508 79.681 87.21 81.031 ;
     RECT  101.988 80.519 102.582 81.059 ;
     RECT  95.652 80.761 96.966 81.095 ;
     RECT  98.064 80.789 100.422 81.095 ;
     RECT  29.016 80.699 78.066 81.131 ;
     RECT  82.656 80.923 83.697 81.149 ;
     RECT  85.896 81.031 87.21 81.149 ;
     RECT  86.508 81.149 87.21 81.203 ;
     RECT  7.272 77.189 8.097 81.239 ;
     RECT  22.644 80.599 27.018 81.337 ;
     RECT  27.792 80.699 28.206 81.337 ;
     RECT  98.784 81.095 100.422 81.365 ;
     RECT  22.644 81.337 28.206 81.389 ;
     RECT  96.696 81.095 96.966 81.481 ;
     RECT  97.776 81.211 97.902 81.481 ;
     RECT  88.56 80.635 89.154 81.499 ;
     RECT  102.564 81.059 102.582 81.509 ;
     RECT  99.615 81.365 100.422 81.599 ;
     RECT  96.696 81.481 97.902 81.779 ;
     RECT  79.812 76.649 80.334 81.832 ;
     RECT  79.812 81.832 80.406 81.869 ;
     RECT  88.236 81.499 89.154 81.869 ;
     RECT  97.488 81.779 97.902 81.869 ;
     RECT  97.488 81.869 97.794 81.905 ;
     RECT  86.508 81.203 86.742 82.111 ;
     RECT  86.508 82.111 86.85 82.147 ;
     RECT  22.752 81.389 28.206 82.171 ;
     RECT  29.052 81.131 78.066 82.171 ;
     RECT  95.652 81.095 95.67 82.175 ;
     RECT  86.508 82.147 86.922 82.219 ;
     RECT  21.96 82.417 21.978 82.561 ;
     RECT  21.96 82.561 22.014 82.651 ;
     RECT  22.752 82.171 78.066 82.651 ;
     RECT  88.815 81.869 89.154 82.651 ;
     RECT  85.14 82.651 85.158 82.759 ;
     RECT  85.14 82.759 85.518 82.795 ;
     RECT  86.508 82.219 86.958 82.795 ;
     RECT  21.96 82.651 78.066 82.831 ;
     RECT  83.124 81.149 83.697 82.831 ;
     RECT  85.14 82.795 86.958 82.831 ;
     RECT  84.888 82.831 86.958 82.939 ;
     RECT  84.564 82.939 86.958 83.029 ;
     RECT  21.816 82.831 78.066 83.065 ;
     RECT  21.672 83.065 78.066 83.101 ;
     RECT  84.564 83.029 86.994 83.101 ;
     RECT  21.6 83.101 78.066 83.227 ;
     RECT  98.784 81.365 98.802 83.255 ;
     RECT  88.452 82.651 89.154 83.299 ;
     RECT  84.564 83.101 87.066 83.489 ;
     RECT  84.708 83.489 87.066 83.533 ;
     RECT  88.308 83.299 89.154 83.875 ;
     RECT  88.308 83.875 89.19 83.911 ;
     RECT  88.308 83.911 89.658 84.029 ;
     RECT  84.708 83.533 87.282 84.037 ;
     RECT  84.708 84.037 87.354 84.109 ;
     RECT  88.308 84.029 89.19 84.109 ;
     RECT  84.708 84.109 89.19 84.271 ;
     RECT  82.692 82.831 83.697 84.331 ;
     RECT  84.492 84.271 89.19 84.331 ;
     RECT  82.692 84.331 89.19 84.335 ;
     RECT  79.812 81.869 80.334 85.339 ;
     RECT  79.812 85.339 80.802 85.469 ;
     RECT  79.848 85.469 80.802 85.627 ;
     RECT  82.692 84.335 89.154 85.693 ;
     RECT  96.696 81.779 96.714 85.793 ;
     RECT  21.456 83.227 78.066 85.829 ;
     RECT  30.996 85.829 78.066 85.867 ;
     RECT  79.848 85.627 81.162 85.867 ;
     RECT  21.456 85.829 30.222 85.891 ;
     RECT  21.276 85.891 30.222 86.027 ;
     RECT  21.276 86.027 29.754 86.035 ;
     RECT  20.772 86.035 29.754 86.071 ;
     RECT  30.996 85.867 78.678 86.333 ;
     RECT  79.848 85.867 81.234 86.341 ;
     RECT  20.592 86.071 29.754 86.467 ;
     RECT  20.196 86.467 29.754 86.539 ;
     RECT  20.124 86.539 29.754 86.611 ;
     RECT  30.996 86.333 78.642 86.611 ;
     RECT  30.924 86.611 78.642 86.639 ;
     RECT  18.615 67.595 18.897 86.731 ;
     RECT  19.944 86.611 29.754 86.731 ;
     RECT  18.615 86.731 29.754 86.771 ;
     RECT  19.944 86.771 29.754 86.845 ;
     RECT  19.944 86.845 30.186 86.909 ;
     RECT  82.692 85.693 89.19 86.971 ;
     RECT  31.68 86.639 78.642 87.005 ;
     RECT  20.088 86.909 30.186 87.079 ;
     RECT  30.924 86.639 30.942 87.079 ;
     RECT  82.692 86.971 89.802 87.115 ;
     RECT  79.74 86.341 81.234 87.511 ;
     RECT  31.68 87.005 78.066 87.539 ;
     RECT  31.788 87.539 78.066 87.581 ;
     RECT  31.788 87.581 78.03 87.677 ;
     RECT  20.088 87.079 30.942 87.691 ;
     RECT  31.788 87.677 77.994 87.773 ;
     RECT  20.088 87.691 31.014 87.781 ;
     RECT  82.692 87.115 89.874 87.853 ;
     RECT  20.052 87.781 31.014 87.917 ;
     RECT  79.704 87.511 81.234 87.961 ;
     RECT  20.052 87.917 30.942 88.231 ;
     RECT  82.692 87.853 90.054 88.231 ;
     RECT  19.908 88.231 30.942 88.321 ;
     RECT  82.692 88.231 90.522 88.349 ;
     RECT  31.788 87.773 77.886 88.501 ;
     RECT  82.692 88.349 90.126 88.735 ;
     RECT  19.8 88.321 30.942 88.897 ;
     RECT  31.788 88.501 78.066 88.897 ;
     RECT  19.8 88.897 78.066 88.925 ;
     RECT  82.656 88.735 90.126 88.925 ;
     RECT  79.236 87.961 81.234 89.117 ;
     RECT  18.615 86.771 18.897 89.269 ;
     RECT  19.8 88.925 77.886 89.269 ;
     RECT  82.692 88.925 90.126 89.473 ;
     RECT  18.615 89.269 77.886 89.969 ;
     RECT  78.66 89.131 78.678 90.005 ;
     RECT  82.692 89.473 90.234 90.085 ;
     RECT  79.704 89.117 81.234 90.391 ;
     RECT  79.668 90.391 81.234 90.661 ;
     RECT  82.692 90.085 90.594 90.661 ;
     RECT  18.615 89.969 19.17 90.931 ;
     RECT  19.908 89.969 77.886 90.931 ;
     RECT  79.668 90.661 90.594 91.021 ;
     RECT  79.668 91.021 90.63 91.037 ;
     RECT  18.615 90.931 77.886 91.471 ;
     RECT  18.615 91.471 78.066 91.517 ;
     RECT  79.704 91.037 90.63 91.613 ;
     RECT  79.74 91.613 90.63 92.273 ;
     RECT  18.615 91.517 77.886 92.677 ;
     RECT  18.36 92.677 77.886 92.731 ;
     RECT  18.36 92.731 77.922 92.821 ;
     RECT  78.66 92.137 78.678 92.821 ;
     RECT  18.36 92.821 78.678 92.957 ;
     RECT  42.48 92.957 78.678 93.053 ;
     RECT  79.74 92.273 90.414 93.149 ;
     RECT  18.36 92.957 41.598 93.209 ;
     RECT  79.776 93.149 90.414 93.325 ;
     RECT  43.092 93.053 78.678 93.437 ;
     RECT  79.776 93.325 90.666 93.479 ;
     RECT  18.36 93.209 40.698 93.589 ;
     RECT  78.66 93.437 78.678 93.622 ;
     RECT  17.964 93.589 40.698 93.629 ;
     RECT  18.36 93.629 40.698 93.749 ;
     RECT  78.66 93.622 78.714 94.027 ;
     RECT  79.776 93.479 90.342 94.027 ;
     RECT  41.436 93.209 41.598 94.063 ;
     RECT  18.396 93.749 40.698 94.075 ;
     RECT  41.436 94.063 42.21 94.075 ;
     RECT  18.396 94.075 42.21 94.205 ;
     RECT  78.66 94.027 90.342 94.301 ;
     RECT  42.192 94.205 42.21 94.333 ;
     RECT  43.092 93.437 77.886 94.333 ;
     RECT  78.66 94.301 78.678 94.333 ;
     RECT  79.776 94.301 90.342 94.405 ;
     RECT  79.776 94.405 90.702 94.559 ;
     RECT  42.192 94.333 78.678 94.589 ;
     RECT  79.776 94.559 90.342 94.781 ;
     RECT  78.66 94.589 78.678 95.251 ;
     RECT  79.92 94.781 90.342 95.279 ;
     RECT  42.192 94.589 77.886 95.369 ;
     RECT  78.66 95.251 78.786 95.369 ;
     RECT  18.396 94.205 41.022 95.413 ;
     RECT  42.192 95.369 77.784 95.453 ;
     RECT  78.66 95.369 78.714 95.675 ;
     RECT  18.396 95.413 41.238 95.755 ;
     RECT  80.028 95.279 90.342 95.909 ;
     RECT  80.064 95.909 90.342 95.917 ;
     RECT  80.064 95.917 90.594 95.953 ;
     RECT  80.064 95.953 90.774 96.061 ;
     RECT  78.66 95.675 78.678 96.215 ;
     RECT  80.064 96.061 90.81 96.295 ;
     RECT  80.064 96.295 90.882 96.601 ;
     RECT  80.064 96.601 91.566 96.989 ;
     RECT  80.064 96.989 91.062 97.025 ;
     RECT  80.064 97.025 90.774 97.771 ;
     RECT  80.064 97.771 90.99 97.915 ;
     RECT  80.064 97.915 91.098 98.339 ;
     RECT  17.784 95.755 41.238 98.635 ;
     RECT  17.604 98.635 41.238 99.197 ;
     RECT  80.064 98.339 91.062 99.301 ;
     RECT  80.064 99.301 91.206 99.563 ;
     RECT  17.964 99.197 41.238 100.171 ;
     RECT  17.712 100.171 41.238 100.229 ;
     RECT  80.064 99.563 91.17 100.381 ;
     RECT  80.064 100.381 91.602 100.643 ;
     RECT  80.064 100.643 91.17 100.769 ;
     RECT  80.064 100.769 90.954 100.85 ;
     RECT  17.856 100.229 41.238 101.453 ;
     RECT  18.108 101.453 41.238 101.579 ;
     RECT  80.064 100.85 90.918 101.929 ;
     RECT  18.288 101.579 41.238 101.993 ;
     RECT  80.064 101.929 91.386 102.505 ;
     RECT  18.432 101.993 41.238 102.901 ;
     RECT  18.36 102.901 41.238 103.081 ;
     RECT  18.252 103.081 41.238 103.279 ;
     RECT  18.216 103.279 41.238 103.351 ;
     RECT  80.064 102.505 91.53 103.351 ;
     RECT  80.064 103.351 91.71 103.469 ;
     RECT  80.064 103.469 91.278 103.757 ;
     RECT  18.18 103.351 41.238 103.891 ;
     RECT  18 103.891 41.238 104.009 ;
     RECT  18 104.009 40.497 104.585 ;
     RECT  18 104.585 38.394 104.621 ;
     RECT  80.064 103.757 91.206 104.791 ;
     RECT  18 104.621 38.322 104.819 ;
     RECT  18 104.819 38.178 104.935 ;
     RECT  80.064 104.791 91.314 105.161 ;
     RECT  80.064 105.161 91.206 105.359 ;
     RECT  80.064 105.359 91.098 105.395 ;
     RECT  39.204 104.585 40.497 105.451 ;
     RECT  41.22 104.009 41.238 105.451 ;
     RECT  39.132 105.451 41.238 105.503 ;
     RECT  17.892 104.935 38.178 105.745 ;
     RECT  17.892 105.745 38.214 105.899 ;
     RECT  39.204 105.503 41.238 105.899 ;
     RECT  17.892 105.899 38.142 106.013 ;
     RECT  17.892 106.013 33.174 106.511 ;
     RECT  18.288 106.511 33.174 106.825 ;
     RECT  33.912 106.013 38.142 106.825 ;
     RECT  80.064 105.395 90.99 106.861 ;
     RECT  18.288 106.825 38.142 106.889 ;
     RECT  80.064 106.861 91.026 106.987 ;
     RECT  18.324 106.889 38.142 107.321 ;
     RECT  18.432 107.321 38.142 107.519 ;
     RECT  80.064 106.987 91.638 107.519 ;
     RECT  80.064 107.519 91.53 107.969 ;
     RECT  42.192 95.453 42.21 108.131 ;
     RECT  18.432 107.519 31.23 108.331 ;
     RECT  18.216 108.331 31.23 108.445 ;
     RECT  31.968 107.519 38.142 108.445 ;
     RECT  18.216 108.445 38.142 108.599 ;
     RECT  18.216 108.599 34.038 108.671 ;
     RECT  80.064 107.969 91.458 108.715 ;
     RECT  80.064 108.715 91.53 108.841 ;
     RECT  39.204 105.899 40.497 108.859 ;
     RECT  41.22 105.899 41.238 108.859 ;
     RECT  80.064 108.841 91.71 109.435 ;
     RECT  80.064 109.435 91.854 109.561 ;
     RECT  18.432 108.671 34.038 109.651 ;
     RECT  34.776 108.599 38.142 109.651 ;
     RECT  18.432 109.651 38.142 109.795 ;
     RECT  18.36 109.795 38.142 109.831 ;
     RECT  80.064 109.561 92.106 110.065 ;
     RECT  80.064 110.065 92.25 110.219 ;
     RECT  18.18 109.831 38.142 110.335 ;
     RECT  80.064 110.219 91.71 110.363 ;
     RECT  17.964 110.335 38.142 110.488 ;
     RECT  17.964 110.488 38.43 110.573 ;
     RECT  18.288 110.573 38.43 110.635 ;
     RECT  39.204 108.859 41.238 110.635 ;
     RECT  18.288 110.635 41.238 110.831 ;
     RECT  18.504 110.831 41.238 111.065 ;
     RECT  18.54 111.065 41.238 111.919 ;
     RECT  18.54 111.919 41.346 112.801 ;
     RECT  18.324 112.801 41.346 112.843 ;
     RECT  18.18 112.843 41.346 113.189 ;
     RECT  18.18 113.189 39.33 113.225 ;
     RECT  101.268 114.277 101.286 114.385 ;
     RECT  101.16 114.385 101.286 114.421 ;
     RECT  100.98 114.421 101.322 114.523 ;
     RECT  40.215 113.189 41.346 115.051 ;
     RECT  99.615 81.599 99.897 115.051 ;
     RECT  100.62 114.523 101.322 115.051 ;
     RECT  99.615 115.051 101.322 115.123 ;
     RECT  99.576 115.123 101.322 115.591 ;
     RECT  99.504 115.591 101.322 115.619 ;
     RECT  99.504 115.619 101.286 115.621 ;
     RECT  98.316 115.621 98.334 115.663 ;
     RECT  99.432 115.621 101.286 115.663 ;
     RECT  94.215 80.813 94.497 115.771 ;
     RECT  18.615 113.225 39.33 115.889 ;
     RECT  80.064 110.363 91.206 115.933 ;
     RECT  19.836 115.889 39.33 115.961 ;
     RECT  95.724 115.861 95.742 115.969 ;
     RECT  80.064 115.933 91.602 116.159 ;
     RECT  98.316 115.663 101.286 116.159 ;
     RECT  96.48 115.861 96.498 116.203 ;
     RECT  97.308 116.131 97.47 116.203 ;
     RECT  94.215 115.771 94.662 116.239 ;
     RECT  95.544 115.969 95.742 116.239 ;
     RECT  96.48 116.203 97.47 116.251 ;
     RECT  98.316 116.159 101.214 116.285 ;
     RECT  80.064 116.159 91.134 116.303 ;
     RECT  96.48 116.251 97.578 116.311 ;
     RECT  98.316 116.285 101.178 116.311 ;
     RECT  94.215 116.239 95.742 116.347 ;
     RECT  96.48 116.311 101.178 116.347 ;
     RECT  19.836 115.961 19.854 116.815 ;
     RECT  20.628 115.961 39.33 116.815 ;
     RECT  19.836 116.815 39.33 116.843 ;
     RECT  20.232 116.843 39.33 116.851 ;
     RECT  40.068 115.051 41.346 116.851 ;
     RECT  43.2 95.453 77.784 116.851 ;
     RECT  94.215 116.347 101.178 116.969 ;
     RECT  102.492 116.779 102.51 117.067 ;
     RECT  80.064 116.303 90.666 117.121 ;
     RECT  95.328 116.969 101.178 117.149 ;
     RECT  80.064 117.121 90.702 117.211 ;
     RECT  102.492 117.067 102.582 117.211 ;
     RECT  20.232 116.851 41.346 117.283 ;
     RECT  80.064 117.211 90.738 117.355 ;
     RECT  80.064 117.355 91.134 117.391 ;
     RECT  95.508 117.149 101.178 117.403 ;
     RECT  95.508 117.403 101.322 117.509 ;
     RECT  102.348 117.211 102.582 117.581 ;
     RECT  20.232 117.283 41.634 117.653 ;
     RECT  80.064 117.391 91.458 117.653 ;
     RECT  94.215 116.969 94.497 118.021 ;
     RECT  95.508 117.509 101.106 118.021 ;
     RECT  95.436 118.021 101.106 118.109 ;
     RECT  95.616 118.109 101.106 118.363 ;
     RECT  102.564 117.581 102.582 118.391 ;
     RECT  20.232 117.653 38.394 118.435 ;
     RECT  39.132 117.653 41.634 118.435 ;
     RECT  80.064 117.653 91.134 118.471 ;
     RECT  80.064 118.471 91.206 118.661 ;
     RECT  94.215 118.021 94.662 118.733 ;
     RECT  95.616 118.363 101.178 118.939 ;
     RECT  95.616 118.939 101.322 119.011 ;
     RECT  95.508 119.011 101.322 119.117 ;
     RECT  95.508 119.117 95.778 119.129 ;
     RECT  102.492 118.507 102.51 119.471 ;
     RECT  95.616 119.129 95.778 119.669 ;
     RECT  103.5 119.563 103.518 119.693 ;
     RECT  102.564 119.803 102.582 120.011 ;
     RECT  94.215 118.733 94.497 120.091 ;
     RECT  95.616 119.669 95.634 120.091 ;
     RECT  94.215 120.091 95.634 120.209 ;
     RECT  20.232 118.435 41.634 120.245 ;
     RECT  96.588 119.117 101.322 120.451 ;
     RECT  20.52 120.245 41.634 120.785 ;
     RECT  96.516 120.451 101.322 120.793 ;
     RECT  21.06 120.785 41.634 120.821 ;
     RECT  95.328 120.209 95.634 120.859 ;
     RECT  96.516 120.793 101.394 120.859 ;
     RECT  95.328 120.859 101.394 121.181 ;
     RECT  94.215 120.209 94.554 121.291 ;
     RECT  95.328 121.181 97.83 121.291 ;
     RECT  94.215 121.291 97.83 121.325 ;
     RECT  98.856 121.181 101.394 121.325 ;
     RECT  96.588 121.325 97.83 121.397 ;
     RECT  21.456 120.821 41.634 121.421 ;
     RECT  94.215 121.325 95.382 121.421 ;
     RECT  99.288 121.325 101.394 121.595 ;
     RECT  43.2 116.851 78.354 121.639 ;
     RECT  99.288 121.595 101.322 121.865 ;
     RECT  80.064 118.661 90.522 121.937 ;
     RECT  100.872 121.865 101.322 122.012 ;
     RECT  100.908 122.012 101.322 122.135 ;
     RECT  21.492 121.421 41.634 122.143 ;
     RECT  21.42 122.143 41.634 122.179 ;
     RECT  100.98 122.135 101.322 122.207 ;
     RECT  21.348 122.179 41.634 122.251 ;
     RECT  21.204 122.251 41.634 122.299 ;
     RECT  21.06 122.299 41.634 122.369 ;
     RECT  90.504 121.937 90.522 122.369 ;
     RECT  101.088 122.207 101.322 122.369 ;
     RECT  101.16 122.369 101.322 122.405 ;
     RECT  101.232 122.405 101.322 122.639 ;
     RECT  101.232 122.639 101.25 122.675 ;
     RECT  80.064 121.937 89.73 122.755 ;
     RECT  21.348 122.369 41.634 122.819 ;
     RECT  22.068 122.819 41.634 122.957 ;
     RECT  80.064 122.755 89.91 123.089 ;
     RECT  22.14 122.957 41.634 123.179 ;
     RECT  80.064 123.089 89.55 123.215 ;
     RECT  22.392 123.179 41.634 123.449 ;
     RECT  29.304 123.449 41.634 123.485 ;
     RECT  86.184 123.215 89.55 124.069 ;
     RECT  86.184 124.069 89.658 124.105 ;
     RECT  98.316 124.219 98.334 124.259 ;
     RECT  22.392 123.449 28.53 124.303 ;
     RECT  29.415 123.485 41.634 124.303 ;
     RECT  80.064 123.215 85.374 124.339 ;
     RECT  86.184 124.105 89.838 124.339 ;
     RECT  22.392 124.303 41.634 124.411 ;
     RECT  22.284 124.411 41.634 124.609 ;
     RECT  22.104 124.609 41.634 124.681 ;
     RECT  42.48 121.639 78.354 124.681 ;
     RECT  22.104 124.681 78.354 124.877 ;
     RECT  80.064 124.339 89.838 125.141 ;
     RECT  22.32 124.877 78.354 125.249 ;
     RECT  80.064 125.141 89.658 125.411 ;
     RECT  80.064 125.411 89.226 125.789 ;
     RECT  28.512 125.249 78.354 125.928 ;
     RECT  28.512 125.928 76.92 125.981 ;
     RECT  22.32 125.249 27.342 125.989 ;
     RECT  22.068 125.989 27.342 126.029 ;
     RECT  22.212 126.029 27.342 126.689 ;
     RECT  29.415 125.981 76.92 126.689 ;
     RECT  22.824 126.689 27.342 126.725 ;
     RECT  22.824 126.725 27.126 126.869 ;
     RECT  30.636 126.689 76.92 126.907 ;
     RECT  28.512 125.981 28.53 126.959 ;
     RECT  23.472 126.869 27.126 127.139 ;
     RECT  30.636 126.907 77.31 127.195 ;
     RECT  78.336 125.928 78.354 127.195 ;
     RECT  23.616 127.139 27.126 127.229 ;
     RECT  23.616 127.229 26.73 127.265 ;
     RECT  23.616 127.265 26.622 127.301 ;
     RECT  23.616 127.301 26.586 127.337 ;
     RECT  23.688 127.337 26.586 127.499 ;
     RECT  23.688 127.499 26.262 127.607 ;
     RECT  79.272 118.201 79.29 127.615 ;
     RECT  80.568 125.789 89.154 127.615 ;
     RECT  23.688 127.607 26.154 127.769 ;
     RECT  79.272 127.615 89.154 127.805 ;
     RECT  23.688 127.769 26.01 128.039 ;
     RECT  79.272 127.805 79.794 128.039 ;
     RECT  80.568 127.805 89.154 128.111 ;
     RECT  30.636 127.195 78.354 128.149 ;
     RECT  79.272 128.039 79.578 128.149 ;
     RECT  30.636 128.149 79.578 128.191 ;
     RECT  23.688 128.039 25.074 128.251 ;
     RECT  29.415 126.689 29.826 128.317 ;
     RECT  30.6 128.191 79.578 128.317 ;
     RECT  23.4 128.251 25.074 128.453 ;
     RECT  23.4 128.453 24.966 128.651 ;
     RECT  29.415 128.317 79.578 128.875 ;
     RECT  29.304 128.875 79.578 129.001 ;
     RECT  29.304 129.001 79.614 129.235 ;
     RECT  29.052 129.235 79.614 129.496 ;
     RECT  29.052 129.496 79.686 129.533 ;
     RECT  29.052 129.533 79.506 129.731 ;
     RECT  29.415 129.731 79.506 129.917 ;
     RECT  80.568 128.111 89.097 129.929 ;
     RECT  80.568 129.929 88.002 129.965 ;
     RECT  80.568 129.965 87.534 130.001 ;
     RECT  80.568 130.001 87.246 130.207 ;
     RECT  99.288 121.865 99.897 130.243 ;
     RECT  79.272 129.917 79.506 130.315 ;
     RECT  80.388 130.207 87.246 130.315 ;
     RECT  95.328 121.421 95.382 130.783 ;
     RECT  79.272 130.315 87.246 130.819 ;
     RECT  29.415 129.917 78.354 130.891 ;
     RECT  79.272 130.819 87.714 130.891 ;
     RECT  29.415 130.891 87.714 130.973 ;
     RECT  79.236 130.973 87.714 131.251 ;
     RECT  88.815 129.929 89.097 131.251 ;
     RECT  94.215 121.421 94.497 131.431 ;
     RECT  95.328 130.783 95.634 131.431 ;
     RECT  24.015 128.651 24.966 131.521 ;
     RECT  25.992 128.039 26.01 131.521 ;
     RECT  24.015 131.521 26.01 131.629 ;
     RECT  24.015 131.629 26.154 131.657 ;
     RECT  79.236 131.251 89.097 131.657 ;
     RECT  99.072 130.243 99.897 131.665 ;
     RECT  29.415 130.973 78.354 131.971 ;
     RECT  79.236 131.657 87.822 131.971 ;
     RECT  29.415 131.971 87.822 132.097 ;
     RECT  29.34 132.097 87.822 132.125 ;
     RECT  98.424 131.665 99.897 132.241 ;
     RECT  91.188 131.701 91.206 132.665 ;
     RECT  79.236 132.125 87.822 132.871 ;
     RECT  88.815 131.657 89.097 132.871 ;
     RECT  29.34 132.125 78.354 132.907 ;
     RECT  79.236 132.871 89.097 132.907 ;
     RECT  29.34 132.907 89.097 133.051 ;
     RECT  98.1 132.241 99.897 133.861 ;
     RECT  29.34 133.051 89.298 134.023 ;
     RECT  96.588 121.397 97.254 134.365 ;
     RECT  98.1 133.861 100.17 134.365 ;
     RECT  102.564 134.347 102.582 134.401 ;
     RECT  91.368 132.781 91.386 134.429 ;
     RECT  101.988 134.401 102.582 134.491 ;
     RECT  96.588 134.365 100.17 134.525 ;
     RECT  29.34 134.023 89.37 134.621 ;
     RECT  98.28 134.525 100.17 134.671 ;
     RECT  101.304 134.491 102.582 134.671 ;
     RECT  29.34 134.621 78.354 134.699 ;
     RECT  29.376 134.699 78.354 134.813 ;
     RECT  103.572 134.779 103.59 134.897 ;
     RECT  98.28 134.671 102.582 135.059 ;
     RECT  94.215 131.431 95.634 135.067 ;
     RECT  100.656 135.059 102.582 135.101 ;
     RECT  101.988 135.101 102.582 135.211 ;
     RECT  101.988 135.211 102.618 135.329 ;
     RECT  102.528 135.329 102.618 135.389 ;
     RECT  79.272 134.621 89.37 135.445 ;
     RECT  94.215 135.067 95.706 135.481 ;
     RECT  94.215 135.481 95.85 135.599 ;
     RECT  96.588 134.525 97.254 135.607 ;
     RECT  98.28 135.059 99.897 135.607 ;
     RECT  29.415 134.813 78.354 135.691 ;
     RECT  79.272 135.445 89.478 135.691 ;
     RECT  100.656 135.101 100.674 135.707 ;
     RECT  102.528 135.389 102.582 135.773 ;
     RECT  103.5 135.643 103.518 135.773 ;
     RECT  29.415 135.691 89.478 135.869 ;
     RECT  94.215 135.599 95.382 135.877 ;
     RECT  103.572 135.787 103.59 135.905 ;
     RECT  29.415 135.869 78.354 135.949 ;
     RECT  29.232 135.949 78.354 136.283 ;
     RECT  96.588 135.607 99.897 136.409 ;
     RECT  79.164 135.869 89.478 136.489 ;
     RECT  102.564 135.773 102.582 136.489 ;
     RECT  102.564 136.489 102.618 136.541 ;
     RECT  94.104 135.877 95.382 136.555 ;
     RECT  96.588 136.409 97.578 136.555 ;
     RECT  100.872 136.363 100.89 136.589 ;
     RECT  79.164 136.489 89.514 136.699 ;
     RECT  94.104 136.555 97.578 136.715 ;
     RECT  79.128 136.699 89.514 136.759 ;
     RECT  102.564 136.541 102.582 136.795 ;
     RECT  101.988 136.795 102.582 136.939 ;
     RECT  100.908 136.939 102.582 136.949 ;
     RECT  100.908 136.949 101.286 137.129 ;
     RECT  79.128 136.759 89.73 137.219 ;
     RECT  79.128 137.219 89.406 137.255 ;
     RECT  103.572 137.083 103.59 137.399 ;
     RECT  98.424 136.409 99.897 137.461 ;
     RECT  94.176 136.715 97.578 137.467 ;
     RECT  79.164 137.255 89.406 137.489 ;
     RECT  100.908 137.129 100.926 137.549 ;
     RECT  94.14 137.467 97.578 137.641 ;
     RECT  98.316 137.461 99.897 137.641 ;
     RECT  94.14 137.641 99.897 137.669 ;
     RECT  102.024 136.949 102.582 137.693 ;
     RECT  94.176 137.669 99.897 137.795 ;
     RECT  94.176 137.795 97.902 137.831 ;
     RECT  102.528 137.693 102.582 137.837 ;
     RECT  102.528 137.837 102.546 138.029 ;
     RECT  101.664 137.947 101.682 138.091 ;
     RECT  101.448 138.091 101.682 138.173 ;
     RECT  79.272 137.489 89.406 138.181 ;
     RECT  103.572 138.235 103.59 138.371 ;
     RECT  101.448 138.173 101.502 138.523 ;
     RECT  94.176 137.831 97.83 138.541 ;
     RECT  103.5 138.379 103.518 138.569 ;
     RECT  94.104 138.541 97.83 138.712 ;
     RECT  94.068 138.712 97.83 138.721 ;
     RECT  98.748 137.795 99.897 138.721 ;
     RECT  94.068 138.721 99.897 138.749 ;
     RECT  79.272 138.181 89.766 138.839 ;
     RECT  101.088 138.523 101.502 138.839 ;
     RECT  102.6 138.649 102.618 138.845 ;
     RECT  94.104 138.749 99.897 138.991 ;
     RECT  101.448 138.839 101.502 139.081 ;
     RECT  102.564 138.955 102.582 139.081 ;
     RECT  79.272 138.839 89.514 139.253 ;
     RECT  101.448 139.081 102.582 139.277 ;
     RECT  94.104 138.991 100.35 139.469 ;
     RECT  29.415 136.283 78.354 139.495 ;
     RECT  99.036 139.469 100.35 139.495 ;
     RECT  101.484 139.277 102.582 139.565 ;
     RECT  101.988 139.565 102.582 139.621 ;
     RECT  101.988 139.621 102.618 139.709 ;
     RECT  29.232 139.495 78.354 139.801 ;
     RECT  79.272 139.253 89.478 139.801 ;
     RECT  29.232 139.801 89.478 139.919 ;
     RECT  101.988 139.709 102.582 139.919 ;
     RECT  99.036 139.495 100.494 140.071 ;
     RECT  79.272 139.919 89.478 140.161 ;
     RECT  99.036 140.071 100.674 140.189 ;
     RECT  102.024 139.919 102.582 140.189 ;
     RECT  102.024 140.189 102.042 140.285 ;
     RECT  94.104 139.469 98.262 140.341 ;
     RECT  99.036 140.189 100.206 140.341 ;
     RECT  94.104 140.341 100.206 140.459 ;
     RECT  103.572 139.387 103.59 140.539 ;
     RECT  103.536 140.539 103.59 140.639 ;
     RECT  101.988 140.683 102.006 140.827 ;
     RECT  101.448 140.827 102.006 140.999 ;
     RECT  94.104 140.459 98.442 141.241 ;
     RECT  99.18 140.459 99.897 141.241 ;
     RECT  101.592 140.999 102.006 141.259 ;
     RECT  79.272 140.161 89.874 141.269 ;
     RECT  101.592 141.259 102.582 141.269 ;
     RECT  79.272 141.269 89.55 141.341 ;
     RECT  102.564 141.269 102.582 141.349 ;
     RECT  94.104 141.241 99.897 141.421 ;
     RECT  102.564 141.349 102.618 141.581 ;
     RECT  101.592 141.269 101.61 141.611 ;
     RECT  93.204 141.241 93.222 141.691 ;
     RECT  94.104 141.421 99.954 141.691 ;
     RECT  102.564 141.581 102.582 141.869 ;
     RECT  103.572 140.639 103.59 141.881 ;
     RECT  29.232 139.919 78.354 141.923 ;
     RECT  94.104 141.691 100.458 141.965 ;
     RECT  94.104 141.965 97.578 142.079 ;
     RECT  98.316 141.965 100.458 142.079 ;
     RECT  98.316 142.079 99.954 142.151 ;
     RECT  99.18 142.151 99.954 142.223 ;
     RECT  99.18 142.223 99.897 142.259 ;
     RECT  79.272 141.341 89.478 142.771 ;
     RECT  79.272 142.771 89.874 143.033 ;
     RECT  29.415 141.923 78.354 143.977 ;
     RECT  29.304 143.977 78.354 144.187 ;
     RECT  28.944 144.187 78.354 144.509 ;
     RECT  79.272 143.033 89.478 145.705 ;
     RECT  79.272 145.705 89.946 145.859 ;
     RECT  29.415 144.509 78.354 146.209 ;
     RECT  79.272 145.859 89.478 146.347 ;
     RECT  29.232 146.209 78.354 146.437 ;
     RECT  29.016 146.437 78.354 146.477 ;
     RECT  79.236 146.347 89.478 146.713 ;
     RECT  79.236 146.713 89.514 147.055 ;
     RECT  79.164 147.055 89.514 147.209 ;
     RECT  79.164 147.209 89.37 148.205 ;
     RECT  79.272 148.205 89.37 148.441 ;
     RECT  79.272 148.441 89.442 149.791 ;
     RECT  79.272 149.791 89.622 149.981 ;
     RECT  29.415 146.477 78.354 149.995 ;
     RECT  79.272 149.981 89.478 149.995 ;
     RECT  29.415 149.995 89.478 150.125 ;
     RECT  79.272 150.125 89.478 151.141 ;
     RECT  79.272 151.141 89.946 151.195 ;
     RECT  79.164 151.195 89.946 151.259 ;
     RECT  79.164 151.259 89.478 151.403 ;
     RECT  79.164 151.403 89.442 151.529 ;
     RECT  29.415 150.125 78.354 151.601 ;
     RECT  30.636 151.601 78.354 151.835 ;
     RECT  79.236 151.529 89.442 152.609 ;
     RECT  79.236 152.609 89.298 153.451 ;
     RECT  30.924 151.835 78.354 153.528 ;
     RECT  79.2 153.451 89.298 153.535 ;
     RECT  79.2 153.535 89.37 153.571 ;
     RECT  76.392 153.528 78.354 153.644 ;
     RECT  76.788 153.644 78.354 153.677 ;
     RECT  79.2 153.571 89.442 153.841 ;
     RECT  76.968 153.677 78.354 153.869 ;
     RECT  94.176 142.079 97.578 153.869 ;
     RECT  77.22 153.869 78.354 153.883 ;
     RECT  79.2 153.841 89.586 153.883 ;
     RECT  30.924 153.528 43.362 153.959 ;
     RECT  77.22 153.883 89.586 153.959 ;
     RECT  98.316 142.151 98.334 154.013 ;
     RECT  30.924 153.959 43.002 154.075 ;
     RECT  30.672 154.075 43.002 154.139 ;
     RECT  74.664 153.528 74.682 154.253 ;
     RECT  78.66 153.959 89.478 154.253 ;
     RECT  30.816 154.139 43.002 154.301 ;
     RECT  25.632 131.657 26.154 154.409 ;
     RECT  93.168 141.691 93.222 154.409 ;
     RECT  93.168 154.409 93.186 154.637 ;
     RECT  44.352 153.528 44.37 155.083 ;
     RECT  78.768 154.253 89.478 155.083 ;
     RECT  78.768 155.083 89.946 155.179 ;
     RECT  94.176 153.869 97.254 155.213 ;
     RECT  94.215 155.213 97.254 155.219 ;
     RECT  78.66 155.179 89.946 155.309 ;
     RECT  44.352 155.083 45.054 155.467 ;
     RECT  94.215 155.219 95.382 155.489 ;
     RECT  78.66 155.309 89.622 155.501 ;
     RECT  78.66 155.501 89.406 155.549 ;
     RECT  71.388 155.419 71.406 155.563 ;
     RECT  44.352 155.467 45.234 155.611 ;
     RECT  99.288 142.259 99.897 155.611 ;
     RECT  77.22 153.959 77.886 155.659 ;
     RECT  30.924 154.301 43.002 155.707 ;
     RECT  46.62 155.611 46.638 155.707 ;
     RECT  44.1 155.611 45.234 155.755 ;
     RECT  46.62 155.707 46.746 155.755 ;
     RECT  66.6 155.623 66.618 155.755 ;
     RECT  95.328 155.489 95.382 155.759 ;
     RECT  56.772 155.755 56.79 155.773 ;
     RECT  54.756 155.755 54.774 155.803 ;
     RECT  56.607 155.773 56.79 155.803 ;
     RECT  71.208 155.563 71.406 155.803 ;
     RECT  55.872 155.803 56.79 155.821 ;
     RECT  100.836 155.611 100.854 155.821 ;
     RECT  54.216 155.803 54.774 155.849 ;
     RECT  55.872 155.821 57.042 155.849 ;
     RECT  98.892 155.611 99.897 155.849 ;
     RECT  100.836 155.821 100.926 155.849 ;
     RECT  76.896 155.659 78.297 155.885 ;
     RECT  100.908 155.849 100.926 155.885 ;
     RECT  30.924 155.707 43.326 155.899 ;
     RECT  44.1 155.755 46.746 155.899 ;
     RECT  61.92 155.755 62.19 155.929 ;
     RECT  54.72 155.849 54.774 155.933 ;
     RECT  51.12 155.755 51.39 155.947 ;
     RECT  52.668 155.899 52.686 155.957 ;
     RECT  56.304 155.849 57.042 155.981 ;
     RECT  79.236 155.549 89.406 155.981 ;
     RECT  61.272 155.929 62.73 156.001 ;
     RECT  66.6 155.755 67.59 156.001 ;
     RECT  71.208 155.803 71.55 156.001 ;
     RECT  59.652 156.001 59.67 156.043 ;
     RECT  72.72 155.755 72.99 156.043 ;
     RECT  59.652 156.043 59.778 156.077 ;
     RECT  50.724 155.947 51.39 156.119 ;
     RECT  50.832 156.119 51.39 156.125 ;
     RECT  53.208 156.091 53.334 156.128 ;
     RECT  71.208 156.001 71.802 156.155 ;
     RECT  59.76 156.077 59.778 156.173 ;
     RECT  61.2 156.001 62.73 156.173 ;
     RECT  66.384 156.001 67.59 156.187 ;
     RECT  72.615 156.043 72.99 156.187 ;
     RECT  74.664 155.659 74.682 156.187 ;
     RECT  71.784 156.155 71.802 156.227 ;
     RECT  72.615 156.187 73.098 156.227 ;
     RECT  30.924 155.899 46.746 156.283 ;
     RECT  61.815 156.173 62.73 156.283 ;
     RECT  77.22 155.885 78.297 156.283 ;
     RECT  79.236 155.981 89.226 156.283 ;
     RECT  94.215 155.489 94.497 156.283 ;
     RECT  95.328 155.759 95.346 156.299 ;
     RECT  54.72 155.933 54.738 156.317 ;
     RECT  56.304 155.981 56.79 156.317 ;
     RECT  58.716 156.187 58.734 156.317 ;
     RECT  70.704 156.187 70.722 156.317 ;
     RECT  72.615 156.227 72.99 156.317 ;
     RECT  30.924 156.283 46.782 156.331 ;
     RECT  50.904 156.125 51.39 156.361 ;
     RECT  74.664 156.187 74.826 156.389 ;
     RECT  74.664 156.389 74.79 156.413 ;
     RECT  90.648 156.283 90.666 156.413 ;
     RECT  61.815 156.283 62.802 156.475 ;
     RECT  50.904 156.361 51.606 156.509 ;
     RECT  66.384 156.187 67.806 156.509 ;
     RECT  99.288 155.849 99.897 156.557 ;
     RECT  56.304 156.317 56.697 156.569 ;
     RECT  66.384 156.509 67.497 156.569 ;
     RECT  30.924 156.331 46.854 156.605 ;
     RECT  61.815 156.475 62.838 156.605 ;
     RECT  30.924 156.605 44.37 156.653 ;
     RECT  45.216 156.605 46.854 156.653 ;
     RECT  30.924 156.653 43.614 156.659 ;
     RECT  50.904 156.509 51.297 156.659 ;
     RECT  53.208 156.128 53.226 156.659 ;
     RECT  61.815 156.605 62.586 156.701 ;
     RECT  64.116 156.667 64.134 156.704 ;
     RECT  96.588 155.219 97.254 156.749 ;
     RECT  99.615 156.557 99.897 156.763 ;
     RECT  30.924 156.659 43.434 156.803 ;
     RECT  74.664 156.413 74.754 156.839 ;
     RECT  42.156 156.803 43.434 157.001 ;
     RECT  77.22 156.283 89.226 157.001 ;
     RECT  95.508 156.763 95.526 157.003 ;
     RECT  98.352 156.763 98.37 157.051 ;
     RECT  94.215 156.283 94.59 157.099 ;
     RECT  42.156 157.001 43.074 157.133 ;
     RECT  99.615 156.763 100.422 157.171 ;
     RECT  95.508 157.003 95.778 157.195 ;
     RECT  96.588 156.749 97.11 157.195 ;
     RECT  30.924 156.803 41.346 157.199 ;
     RECT  42.156 157.133 43.002 157.199 ;
     RECT  99.615 157.171 100.926 157.199 ;
     RECT  94.215 157.099 94.662 157.229 ;
     RECT  100.908 157.199 100.926 157.229 ;
     RECT  39.42 157.199 40.914 157.271 ;
     RECT  42.516 157.199 43.002 157.277 ;
     RECT  39.42 157.271 39.438 157.325 ;
     RECT  98.352 157.051 98.55 157.339 ;
     RECT  98.136 157.339 98.55 157.469 ;
     RECT  90.648 157.339 90.666 157.517 ;
     RECT  74.664 156.839 74.682 157.579 ;
     RECT  95.508 157.195 97.11 157.579 ;
     RECT  56.415 156.569 56.697 157.711 ;
     RECT  66.384 156.569 66.402 157.711 ;
     RECT  67.215 156.569 67.497 157.711 ;
     RECT  98.352 157.469 98.55 157.711 ;
     RECT  95.508 157.579 97.542 157.739 ;
     RECT  98.352 157.711 98.694 157.757 ;
     RECT  95.76 157.739 96.966 157.805 ;
     RECT  77.22 157.001 89.19 157.883 ;
     RECT  30.924 157.199 38.682 158.009 ;
     RECT  98.352 157.757 98.55 158.009 ;
     RECT  30.924 158.009 31.266 158.045 ;
     RECT  96.084 157.805 96.966 158.093 ;
     RECT  96.084 158.093 96.426 158.279 ;
     RECT  74.664 157.579 74.79 158.285 ;
     RECT  56.304 157.711 56.697 158.288 ;
     RECT  66.384 157.711 67.497 158.288 ;
     RECT  98.532 158.009 98.55 158.429 ;
     RECT  32.076 158.009 38.682 158.549 ;
     RECT  42.552 157.277 43.002 158.587 ;
     RECT  79.272 157.883 89.19 158.629 ;
     RECT  33.768 158.549 38.682 158.669 ;
     RECT  74.664 158.285 74.682 158.693 ;
     RECT  42.372 158.587 43.002 158.821 ;
     RECT  42.264 158.821 43.002 158.861 ;
     RECT  79.236 158.629 89.19 158.935 ;
     RECT  79.2 158.935 89.19 159.005 ;
     RECT  79.236 159.005 89.19 159.097 ;
     RECT  33.948 158.669 38.682 159.149 ;
     RECT  79.236 159.097 89.262 159.241 ;
     RECT  34.344 159.149 38.682 159.269 ;
     RECT  79.236 159.241 89.73 159.467 ;
     RECT  77.22 157.883 78.297 160.027 ;
     RECT  79.236 159.467 89.478 160.027 ;
     RECT  77.22 160.027 89.478 160.439 ;
     RECT  77.22 160.439 89.442 160.583 ;
     RECT  42.552 158.861 43.002 160.591 ;
     RECT  34.38 159.269 38.682 160.745 ;
     RECT  77.22 160.583 89.097 161.123 ;
     RECT  79.128 161.123 89.097 161.249 ;
     RECT  42.48 160.591 43.002 161.321 ;
     RECT  79.236 161.249 89.097 161.401 ;
     RECT  42.192 161.323 42.21 161.515 ;
     RECT  41.976 161.515 42.21 161.519 ;
     RECT  41.976 161.519 41.994 161.555 ;
     RECT  32.076 158.549 32.742 161.635 ;
     RECT  34.668 160.745 38.682 161.755 ;
     RECT  34.668 161.755 39.114 161.795 ;
     RECT  34.668 161.795 38.682 161.899 ;
     RECT  40.215 157.271 40.914 161.899 ;
     RECT  44.352 156.653 44.37 161.899 ;
     RECT  34.308 161.899 38.682 162.059 ;
     RECT  43.2 161.899 43.218 162.059 ;
     RECT  39.78 161.899 40.914 162.095 ;
     RECT  32.076 161.635 33.354 162.175 ;
     RECT  34.308 162.059 35.442 162.175 ;
     RECT  79.236 161.401 89.19 162.301 ;
     RECT  44.352 161.899 44.406 162.329 ;
     RECT  44.352 162.329 44.37 162.337 ;
     RECT  32.076 162.175 35.442 162.365 ;
     RECT  77.22 161.123 78.297 162.475 ;
     RECT  79.236 162.301 89.442 162.475 ;
     RECT  77.22 162.475 89.442 162.481 ;
     RECT  32.076 162.365 33.354 162.715 ;
     RECT  66.384 158.288 66.402 162.743 ;
     RECT  77.22 162.481 89.478 162.743 ;
     RECT  29.415 151.601 29.826 162.779 ;
     RECT  43.056 162.175 43.182 162.859 ;
     RECT  34.2 162.365 35.442 162.869 ;
     RECT  79.38 162.743 89.478 162.949 ;
     RECT  43.02 162.859 43.182 162.985 ;
     RECT  42.516 162.985 43.182 163.003 ;
     RECT  44.208 162.337 44.37 163.003 ;
     RECT  36.252 162.059 38.682 163.013 ;
     RECT  40.032 162.095 40.914 163.111 ;
     RECT  42.516 163.003 44.37 163.111 ;
     RECT  41.976 163.111 44.37 163.291 ;
     RECT  24.015 131.657 24.57 163.319 ;
     RECT  40.032 163.111 41.166 163.417 ;
     RECT  41.94 163.291 44.37 163.417 ;
     RECT  38.448 163.013 38.682 163.579 ;
     RECT  40.032 163.417 44.37 163.579 ;
     RECT  45.216 156.653 46.422 163.579 ;
     RECT  34.308 162.869 35.442 163.651 ;
     RECT  31.932 162.715 33.354 163.831 ;
     RECT  34.2 163.651 35.442 163.831 ;
     RECT  79.38 162.949 89.586 163.831 ;
     RECT  40.032 163.579 46.422 163.949 ;
     RECT  31.932 163.831 35.442 163.985 ;
     RECT  34.2 163.985 35.442 164.065 ;
     RECT  36.252 163.013 37.17 164.065 ;
     RECT  38.448 163.579 39.078 164.065 ;
     RECT  40.032 163.949 44.442 164.065 ;
     RECT  79.38 163.831 89.838 164.093 ;
     RECT  38.448 164.065 44.442 164.227 ;
     RECT  34.2 164.065 37.17 164.299 ;
     RECT  79.38 164.093 89.298 164.335 ;
     RECT  34.2 164.299 37.278 164.569 ;
     RECT  38.088 164.227 44.442 164.569 ;
     RECT  34.2 164.569 44.442 164.621 ;
     RECT  36.072 164.621 44.442 164.731 ;
     RECT  45.216 163.949 46.422 164.731 ;
     RECT  79.308 164.335 89.298 164.831 ;
     RECT  79.308 164.831 89.226 164.867 ;
     RECT  79.308 164.867 89.118 164.903 ;
     RECT  31.932 163.985 33.39 164.911 ;
     RECT  34.2 164.621 35.097 164.911 ;
     RECT  79.308 164.903 89.097 164.911 ;
     RECT  79.164 164.911 89.097 164.957 ;
     RECT  61.815 156.701 62.097 165.163 ;
     RECT  67.215 158.288 67.497 165.163 ;
     RECT  67.104 165.163 67.497 165.209 ;
     RECT  26.136 154.409 26.154 165.299 ;
     RECT  36.072 164.731 46.422 165.299 ;
     RECT  61.815 165.163 62.622 165.299 ;
     RECT  61.815 165.299 62.406 165.344 ;
     RECT  36.072 165.299 44.37 165.451 ;
     RECT  79.308 164.957 89.097 165.569 ;
     RECT  31.932 164.911 35.097 165.649 ;
     RECT  35.964 165.451 44.37 165.649 ;
     RECT  45.216 165.299 46.422 165.835 ;
     RECT  45.216 165.835 46.962 165.875 ;
     RECT  79.416 165.569 89.097 166.013 ;
     RECT  77.22 162.743 78.297 166.109 ;
     RECT  79.452 166.013 89.097 166.217 ;
     RECT  56.415 158.288 56.697 166.351 ;
     RECT  67.215 165.209 67.497 166.351 ;
     RECT  26.244 165.415 26.262 166.379 ;
     RECT  56.304 166.351 56.697 166.397 ;
     RECT  67.104 166.351 67.497 166.397 ;
     RECT  79.56 166.217 89.097 166.459 ;
     RECT  31.932 165.649 44.37 166.531 ;
     RECT  79.56 166.459 89.55 166.531 ;
     RECT  31.932 166.531 44.406 166.649 ;
     RECT  45.216 165.875 46.422 166.801 ;
     RECT  31.932 166.649 44.334 166.919 ;
     RECT  79.56 166.531 89.982 166.991 ;
     RECT  31.932 166.919 44.226 167.021 ;
     RECT  31.932 167.021 44.082 167.189 ;
     RECT  27.324 166.423 27.342 167.369 ;
     RECT  79.56 166.991 89.55 167.459 ;
     RECT  80.208 167.459 89.55 167.603 ;
     RECT  79.416 167.575 79.434 167.645 ;
     RECT  80.352 167.603 89.55 167.729 ;
     RECT  80.496 167.729 89.55 167.773 ;
     RECT  45.108 166.801 46.422 167.999 ;
     RECT  80.496 167.773 89.946 167.999 ;
     RECT  45.108 167.999 46.314 168.125 ;
     RECT  80.496 167.999 89.55 168.305 ;
     RECT  56.415 166.397 56.697 168.511 ;
     RECT  67.215 166.397 67.497 168.511 ;
     RECT  80.64 168.305 89.55 168.539 ;
     RECT  56.304 168.511 56.697 168.557 ;
     RECT  67.104 168.511 67.497 168.557 ;
     RECT  80.964 168.539 89.55 168.611 ;
     RECT  80.964 168.611 89.37 168.647 ;
     RECT  45.108 168.125 45.897 168.655 ;
     RECT  31.932 167.189 44.046 168.691 ;
     RECT  45 168.655 45.897 168.691 ;
     RECT  80.964 168.647 89.262 169.385 ;
     RECT  87.12 169.385 89.262 169.393 ;
     RECT  31.932 168.691 45.897 169.501 ;
     RECT  87.12 169.393 89.334 169.501 ;
     RECT  87.12 169.501 89.658 169.655 ;
     RECT  80.964 169.385 86.202 169.763 ;
     RECT  87.156 169.655 89.658 169.763 ;
     RECT  31.932 169.501 46.278 169.853 ;
     RECT  81.468 169.763 86.202 169.853 ;
     RECT  77.796 166.109 78.297 169.867 ;
     RECT  77.724 169.867 78.297 170.159 ;
     RECT  79.452 169.867 79.47 170.159 ;
     RECT  78.015 170.159 78.297 170.239 ;
     RECT  78.015 170.239 78.678 170.285 ;
     RECT  61.815 165.344 62.097 170.299 ;
     RECT  62.82 170.251 62.838 170.299 ;
     RECT  76.968 170.299 76.986 170.339 ;
     RECT  61.815 170.299 62.838 170.429 ;
     RECT  61.815 170.429 62.622 170.477 ;
     RECT  61.815 170.477 62.097 170.491 ;
     RECT  61.632 170.491 62.097 170.537 ;
     RECT  81.72 169.853 86.202 170.581 ;
     RECT  87.264 169.763 89.442 170.581 ;
     RECT  31.932 169.853 46.134 170.699 ;
     RECT  81.72 170.581 89.442 170.735 ;
     RECT  81.756 170.735 89.442 170.851 ;
     RECT  81.756 170.851 89.766 171.391 ;
     RECT  81.756 171.391 89.838 171.509 ;
     RECT  82.584 171.509 89.478 171.545 ;
     RECT  82.584 171.545 82.602 171.581 ;
     RECT  31.932 170.699 45.897 171.595 ;
     RECT  31.932 171.595 46.134 171.779 ;
     RECT  31.932 171.779 45.954 171.821 ;
     RECT  83.415 171.545 89.478 172.463 ;
     RECT  84.816 172.463 89.406 172.625 ;
     RECT  84.816 172.625 85.374 172.685 ;
     RECT  31.932 171.821 45.897 172.699 ;
     RECT  31.932 172.699 46.206 172.747 ;
     RECT  31.932 172.747 46.494 172.859 ;
     RECT  31.932 172.859 46.386 172.895 ;
     RECT  86.148 172.625 89.406 173.039 ;
     RECT  31.932 172.895 46.206 173.129 ;
     RECT  31.932 173.129 45.99 173.171 ;
     RECT  85.356 172.685 85.374 173.309 ;
     RECT  86.148 173.039 89.37 173.399 ;
     RECT  86.148 173.399 87.93 173.467 ;
     RECT  85.788 173.467 87.93 173.507 ;
     RECT  85.788 173.507 85.878 173.543 ;
     RECT  86.616 173.507 87.93 173.543 ;
     RECT  88.815 173.399 89.37 173.543 ;
     RECT  29.415 162.779 29.697 173.551 ;
     RECT  85.86 173.543 85.878 173.552 ;
     RECT  86.616 173.543 87.786 173.669 ;
     RECT  87.084 173.669 87.462 173.741 ;
     RECT  87.084 173.741 87.102 173.849 ;
     RECT  31.932 173.171 45.918 173.911 ;
     RECT  61.815 170.537 62.097 173.947 ;
     RECT  78.015 170.285 78.297 173.947 ;
     RECT  61.524 173.947 62.097 174.181 ;
     RECT  30.924 158.045 31.158 174.187 ;
     RECT  31.932 173.911 46.17 174.187 ;
     RECT  46.944 173.851 46.962 174.209 ;
     RECT  77.724 173.947 78.297 174.209 ;
     RECT  76.968 174.181 76.986 174.221 ;
     RECT  61.524 174.181 62.19 174.245 ;
     RECT  30.924 174.187 46.17 174.289 ;
     RECT  30.924 174.289 46.602 174.479 ;
     RECT  30.924 174.479 46.494 174.515 ;
     RECT  30.924 174.515 46.458 174.749 ;
     RECT  79.452 174.427 79.47 174.749 ;
     RECT  78.015 174.209 78.297 174.757 ;
     RECT  61.815 174.245 62.19 174.763 ;
     RECT  78.015 174.757 78.678 174.797 ;
     RECT  29.415 173.551 30.078 174.865 ;
     RECT  30.924 174.749 46.35 174.865 ;
     RECT  61.815 174.763 62.55 175.019 ;
     RECT  61.815 175.019 62.37 175.085 ;
     RECT  29.415 174.865 46.35 175.559 ;
     RECT  29.415 175.559 46.026 176.485 ;
     RECT  29.415 176.485 46.422 176.909 ;
     RECT  29.415 176.909 46.35 177.179 ;
     RECT  29.415 177.179 46.242 177.979 ;
     RECT  29.415 177.979 46.962 178.025 ;
     RECT  29.415 178.025 46.566 178.799 ;
     RECT  29.415 178.799 46.206 178.907 ;
     RECT  30.42 178.907 46.206 178.973 ;
     RECT  2.415 76.469 2.697 179.027 ;
     RECT  7.815 81.239 8.097 179.027 ;
     RECT  13.215 72.149 13.497 179.027 ;
     RECT  18.615 115.889 18.897 179.027 ;
     RECT  24.015 163.319 24.297 179.027 ;
     RECT  29.415 178.907 29.697 179.027 ;
     RECT  51.015 156.659 51.297 179.027 ;
     RECT  56.415 168.557 56.697 179.027 ;
     RECT  61.815 175.085 62.097 179.027 ;
     RECT  67.215 168.557 67.497 179.027 ;
     RECT  72.615 156.317 72.897 179.027 ;
     RECT  78.015 174.797 78.297 179.027 ;
     RECT  83.415 172.463 83.697 179.027 ;
     RECT  88.815 173.543 89.097 179.027 ;
     RECT  94.215 157.229 94.497 179.027 ;
     RECT  99.615 157.199 99.897 179.027 ;
     RECT  30.744 178.973 46.206 179.261 ;
     RECT  2.415 179.027 2.505 179.297 ;
     RECT  7.815 179.027 7.905 179.297 ;
     RECT  13.215 179.027 13.305 179.297 ;
     RECT  18.615 179.027 18.705 179.297 ;
     RECT  24.015 179.027 24.105 179.297 ;
     RECT  29.415 179.027 29.505 179.297 ;
     RECT  34.776 179.261 46.206 179.297 ;
     RECT  51.015 179.027 51.105 179.297 ;
     RECT  56.415 179.027 56.505 179.297 ;
     RECT  61.815 179.027 61.905 179.297 ;
     RECT  67.215 179.027 67.305 179.297 ;
     RECT  72.615 179.027 72.705 179.297 ;
     RECT  78.015 179.027 78.105 179.297 ;
     RECT  83.415 179.027 83.505 179.297 ;
     RECT  88.815 179.027 88.905 179.297 ;
     RECT  94.215 179.027 94.305 179.297 ;
     RECT  99.615 179.027 99.705 179.297 ;
     RECT  34.776 179.297 45.09 179.453 ;
     RECT  30.744 179.261 32.886 179.549 ;
     RECT  34.776 179.453 39.942 179.549 ;
     RECT  40.68 179.453 45.09 179.549 ;
     RECT  46.188 179.297 46.206 179.549 ;
     RECT  34.776 179.549 37.782 179.597 ;
     RECT  32.004 179.549 32.022 180.125 ;
     RECT  35.172 179.597 37.602 180.125 ;
     RECT  40.68 179.549 42.714 180.125 ;
     RECT  43.92 179.549 44.262 180.125 ;
     RECT  45.072 179.549 45.09 180.125 ;
     RECT  30.744 179.549 31.05 180.173 ;
     RECT  41.544 180.125 42.714 180.173 ;
     RECT  35.172 180.125 36.342 180.701 ;
     RECT  37.44 180.125 37.602 180.701 ;
     RECT  35.172 180.701 35.226 180.749 ;
     RECT  42.12 180.173 42.714 180.749 ;
     RECT  40.68 180.125 40.698 181.277 ;
     RECT  31.032 180.173 31.05 181.325 ;
     RECT  35.208 180.749 35.226 181.325 ;
     RECT  36.324 180.701 36.342 181.325 ;
     RECT  37.584 180.701 37.602 181.325 ;
     RECT  39.42 179.549 39.942 181.325 ;
     RECT  42.696 180.749 42.714 181.325 ;
     RECT  44.244 180.125 44.262 181.325 ;
    LAYER M4 ;
     RECT  0.06 27.504 0.137 31.992 ;
     RECT  0.06 54.288 0.137 56.184 ;
     RECT  0.06 37.872 0.173 42.36 ;
     RECT  0.137 27.648 0.179 31.992 ;
     RECT  0.173 41.328 1.181 42.36 ;
     RECT  1.181 41.616 1.217 42.36 ;
     RECT  1.217 41.904 1.253 42.36 ;
     RECT  0.179 27.648 1.289 31.704 ;
     RECT  1.253 42.048 1.289 42.36 ;
     RECT  1.289 42.192 1.325 42.36 ;
     RECT  1.325 42.336 1.361 42.36 ;
     RECT  1.289 27.648 2.408 30.84 ;
     RECT  0.133 33.648 2.408 33.672 ;
     RECT  0.173 37.872 2.408 40.344 ;
     RECT  0.137 54.432 2.408 56.184 ;
     RECT  0.06 66.672 2.408 75.768 ;
     RECT  2.408 2.148 2.512 179.292 ;
     RECT  2.512 2.418 2.704 179.022 ;
     RECT  2.704 30.192 2.819 32.568 ;
     RECT  2.704 28.512 2.909 29.016 ;
     RECT  2.704 42.672 2.945 42.696 ;
     RECT  2.909 28.8 3.053 29.016 ;
     RECT  2.704 40.32 3.305 40.344 ;
     RECT  2.704 37.728 3.395 38.136 ;
     RECT  2.819 30.24 3.443 32.568 ;
     RECT  3.443 30.24 3.845 31.944 ;
     RECT  2.704 54.432 3.989 56.232 ;
     RECT  2.704 66.624 4.345 75.528 ;
     RECT  4.345 66.624 4.349 75.864 ;
     RECT  3.395 37.728 4.385 37.752 ;
     RECT  3.845 31.344 4.421 31.944 ;
     RECT  4.349 66.816 4.451 75.864 ;
     RECT  3.053 28.992 4.499 29.016 ;
     RECT  3.845 30.24 4.499 30.264 ;
     RECT  4.421 31.344 4.499 31.896 ;
     RECT  4.525 38.016 4.813 38.04 ;
     RECT  3.989 54.48 4.849 56.232 ;
     RECT  4.813 38.016 4.885 38.184 ;
     RECT  3.949 39.216 4.885 39.24 ;
     RECT  4.849 54.48 4.993 57.048 ;
     RECT  4.885 38.016 5.141 39.24 ;
     RECT  5.141 38.016 5.573 38.376 ;
     RECT  4.451 66.816 5.597 75.528 ;
     RECT  5.564 30.768 5.605 30.792 ;
     RECT  4.499 31.872 5.605 31.896 ;
     RECT  4.993 54.48 5.605 57.576 ;
     RECT  5.605 30.768 5.825 31.896 ;
     RECT  5.641 28.416 5.857 28.44 ;
     RECT  5.857 28.416 5.941 29.064 ;
     RECT  5.597 66.816 5.989 76.392 ;
     RECT  5.353 42 6.073 42.024 ;
     RECT  5.989 66.816 6.325 76.44 ;
     RECT  5.605 53.856 6.365 57.576 ;
     RECT  6.073 42 6.421 42.216 ;
     RECT  5.573 38.016 6.473 38.184 ;
     RECT  6.365 55.008 6.473 57.576 ;
     RECT  6.325 66.816 6.473 76.584 ;
     RECT  6.421 41.232 6.508 42.216 ;
     RECT  6.473 56.064 6.611 57.576 ;
     RECT  6.473 67.968 6.797 76.584 ;
     RECT  5.825 30.768 7.045 30.792 ;
     RECT  6.508 41.76 7.261 42.216 ;
     RECT  6.473 38.16 7.541 38.184 ;
     RECT  6.929 39.36 7.541 39.384 ;
     RECT  5.941 28.416 7.808 28.536 ;
     RECT  7.045 30.576 7.808 30.792 ;
     RECT  7.541 38.16 7.808 39.384 ;
     RECT  6.829 40.704 7.808 40.728 ;
     RECT  7.261 41.76 7.808 42.264 ;
     RECT  6.365 53.856 7.808 53.928 ;
     RECT  6.473 55.008 7.808 55.032 ;
     RECT  6.611 56.064 7.808 56.088 ;
     RECT  6.611 57.552 7.808 57.576 ;
     RECT  6.325 64.32 7.808 64.344 ;
     RECT  6.473 66.816 7.808 66.84 ;
     RECT  6.797 68.208 7.808 76.584 ;
     RECT  7.808 2.148 7.912 179.292 ;
     RECT  7.912 2.418 8.104 179.022 ;
     RECT  8.104 38.16 8.201 38.712 ;
     RECT  8.104 30.192 8.243 31.128 ;
     RECT  8.104 32.16 8.281 32.184 ;
     RECT  8.243 31.104 8.489 31.128 ;
     RECT  8.201 38.16 9.205 38.28 ;
     RECT  9.205 38.16 10.429 38.472 ;
     RECT  10.429 38.16 11.149 38.568 ;
     RECT  10.717 35.616 11.185 35.64 ;
     RECT  11.185 35.52 11.221 35.64 ;
     RECT  11.221 35.424 11.441 35.64 ;
     RECT  11.441 35.424 11.621 35.544 ;
     RECT  10.861 40.272 11.837 40.296 ;
     RECT  11.149 38.112 11.873 38.568 ;
     RECT  11.621 35.424 11.909 35.448 ;
     RECT  11.873 38.16 11.941 38.568 ;
     RECT  11.941 38.16 12.089 38.856 ;
     RECT  8.104 64.32 12.157 64.344 ;
     RECT  8.104 17.664 13.208 17.688 ;
     RECT  10.933 36.624 13.208 36.648 ;
     RECT  12.089 38.16 13.208 38.184 ;
     RECT  8.104 42.24 13.208 42.264 ;
     RECT  8.104 53.856 13.208 53.928 ;
     RECT  12.157 64.128 13.208 64.344 ;
     RECT  8.104 68.208 13.208 69.768 ;
     RECT  8.104 71.904 13.208 75.288 ;
     RECT  8.104 76.56 13.208 76.584 ;
     RECT  13.208 2.148 13.312 179.292 ;
     RECT  13.312 2.418 13.504 179.022 ;
     RECT  13.504 36.624 14.785 36.648 ;
     RECT  13.504 64.128 14.821 64.344 ;
     RECT  14.785 36.624 14.825 36.792 ;
     RECT  13.504 38.16 16.261 38.184 ;
     RECT  16.261 38.112 16.553 38.184 ;
     RECT  16.553 38.16 16.873 38.184 ;
     RECT  13.504 17.664 17.089 17.688 ;
     RECT  17.089 17.088 17.173 17.688 ;
     RECT  17.173 17.472 17.417 17.688 ;
     RECT  14.825 36.768 17.989 36.792 ;
     RECT  17.953 110.544 18.277 110.568 ;
     RECT  17.989 104.016 18.469 104.04 ;
     RECT  18.169 112.848 18.469 112.872 ;
     RECT  13.504 53.856 18.529 53.928 ;
     RECT  18.469 96.816 18.529 96.84 ;
     RECT  17.125 5.184 18.608 5.208 ;
     RECT  17.417 17.472 18.608 17.496 ;
     RECT  17.989 36.768 18.608 37.08 ;
     RECT  16.873 38.16 18.608 38.568 ;
     RECT  13.504 42.24 18.608 42.264 ;
     RECT  18.529 53.088 18.608 53.928 ;
     RECT  18.529 59.472 18.608 59.496 ;
     RECT  14.821 64.032 18.608 64.344 ;
     RECT  13.504 68.208 18.608 69.768 ;
     RECT  13.504 71.904 18.608 75.288 ;
     RECT  13.504 76.56 18.608 76.584 ;
     RECT  18.469 91.152 18.608 91.896 ;
     RECT  17.953 93.6 18.608 93.624 ;
     RECT  18.529 96.816 18.608 97.032 ;
     RECT  17.593 98.64 18.608 99.192 ;
     RECT  17.653 100.176 18.608 100.2 ;
     RECT  17.845 101.424 18.608 101.448 ;
     RECT  18.469 103.248 18.608 104.04 ;
     RECT  18.313 107.28 18.608 107.304 ;
     RECT  18.205 108.336 18.608 108.36 ;
     RECT  18.277 110.016 18.608 110.568 ;
     RECT  18.469 112.128 18.608 112.872 ;
     RECT  18.608 2.148 18.712 179.292 ;
     RECT  18.712 2.418 18.904 179.022 ;
     RECT  18.904 101.424 18.965 101.448 ;
     RECT  18.904 109.44 18.965 112.152 ;
     RECT  18.904 56.304 19.037 59.784 ;
     RECT  19.037 56.304 19.043 59.496 ;
     RECT  19.043 59.472 19.065 59.496 ;
     RECT  18.904 95.184 19.109 96.84 ;
     RECT  18.904 63.6 19.379 64.344 ;
     RECT  18.904 91.776 19.427 93.624 ;
     RECT  19.109 95.184 19.427 96.792 ;
     RECT  18.904 104.016 19.433 105.432 ;
     RECT  19.043 56.304 19.469 58.152 ;
     RECT  19.469 56.304 19.505 56.664 ;
     RECT  18.904 106.56 19.516 108.36 ;
     RECT  18.904 98.064 19.541 99.192 ;
     RECT  19.433 104.88 19.541 105.432 ;
     RECT  19.516 106.656 19.649 108.36 ;
     RECT  19.427 95.712 19.667 96.792 ;
     RECT  19.541 98.064 19.667 98.088 ;
     RECT  18.904 51.84 19.685 53.928 ;
     RECT  19.667 96.24 19.693 96.792 ;
     RECT  19.685 51.84 19.829 52.248 ;
     RECT  18.904 88.896 19.859 89.304 ;
     RECT  18.965 110.976 19.916 112.152 ;
     RECT  18.904 60.816 19.933 60.84 ;
     RECT  18.904 66.48 19.969 66.696 ;
     RECT  19.427 91.776 20.001 93.288 ;
     RECT  19.916 110.976 20.003 113.064 ;
     RECT  18.904 114.384 20.003 114.6 ;
     RECT  20.001 91.776 20.009 93.24 ;
     RECT  18.965 109.44 20.101 109.464 ;
     RECT  20.003 110.976 20.101 112.632 ;
     RECT  18.904 86.736 20.113 86.76 ;
     RECT  20.101 109.44 20.147 112.632 ;
     RECT  19.969 66.096 20.257 66.744 ;
     RECT  19.469 58.128 20.261 58.152 ;
     RECT  19.685 53.568 20.293 53.928 ;
     RECT  19.859 88.896 20.293 89.256 ;
     RECT  19.379 63.6 20.297 64.056 ;
     RECT  18.904 49.824 20.329 49.848 ;
     RECT  18.904 47.856 20.369 47.88 ;
     RECT  20.329 49.824 20.369 50.712 ;
     RECT  20.147 111.408 20.387 111.912 ;
     RECT  20.221 117.408 20.473 117.432 ;
     RECT  20.369 50.592 20.477 50.712 ;
     RECT  20.147 109.44 20.513 110.376 ;
     RECT  20.257 65.52 20.549 66.744 ;
     RECT  20.293 88.416 20.549 89.256 ;
     RECT  19.541 104.88 20.549 104.904 ;
     RECT  19.829 52.224 20.579 52.248 ;
     RECT  19.505 56.4 20.585 56.664 ;
     RECT  18.904 115.728 20.617 115.752 ;
     RECT  20.113 86.592 20.725 86.76 ;
     RECT  20.009 91.776 20.729 91.8 ;
     RECT  20.401 94.608 20.797 94.632 ;
     RECT  20.473 116.832 20.869 117.432 ;
     RECT  19.933 60.816 20.876 61.656 ;
     RECT  18.904 90.384 20.905 90.408 ;
     RECT  20.617 115.68 20.905 115.752 ;
     RECT  20.617 100.896 20.915 100.92 ;
     RECT  20.876 60.816 20.917 62.472 ;
     RECT  20.401 102.816 20.941 102.84 ;
     RECT  20.905 90.048 20.945 90.408 ;
     RECT  20.905 115.392 20.945 115.752 ;
     RECT  20.869 39.888 20.953 39.912 ;
     RECT  19.541 99.168 20.956 99.192 ;
     RECT  20.003 114.384 20.965 114.408 ;
     RECT  20.945 115.392 20.965 115.704 ;
     RECT  20.293 53.568 20.977 54.312 ;
     RECT  20.941 102.576 20.977 102.84 ;
     RECT  20.965 114.384 21.011 115.704 ;
     RECT  20.941 58.656 21.025 58.68 ;
     RECT  20.549 66.672 21.049 66.744 ;
     RECT  19.693 96.24 21.049 96.456 ;
     RECT  19.649 107.136 21.049 108.36 ;
     RECT  20.513 109.44 21.049 109.464 ;
     RECT  21.02 122.304 21.061 122.328 ;
     RECT  20.797 94.56 21.089 94.632 ;
     RECT  21.061 121.392 21.107 122.328 ;
     RECT  20.917 60.816 21.148 62.568 ;
     RECT  20.725 86.592 21.157 87.192 ;
     RECT  21.049 66.672 21.161 66.792 ;
     RECT  21.089 94.56 21.229 94.584 ;
     RECT  21.121 105.456 21.229 105.768 ;
     RECT  21.049 107.136 21.229 109.464 ;
     RECT  21.049 96.192 21.233 96.456 ;
     RECT  21.049 98.736 21.233 98.76 ;
     RECT  20.977 102.432 21.233 102.84 ;
     RECT  21.233 102.624 21.26 102.84 ;
     RECT  20.977 53.568 21.269 54.504 ;
     RECT  21.229 94.224 21.269 94.584 ;
     RECT  21.229 105.456 21.299 109.464 ;
     RECT  20.297 63.648 21.301 64.056 ;
     RECT  21.233 96.24 21.305 96.456 ;
     RECT  21.011 114.576 21.341 115.704 ;
     RECT  21.26 102.624 21.347 103.512 ;
     RECT  21.299 105.456 21.385 105.48 ;
     RECT  21.269 53.568 21.409 53.928 ;
     RECT  21.157 86.592 21.443 87.72 ;
     RECT  21.299 106.512 21.449 107.112 ;
     RECT  18.904 68.208 21.481 69.768 ;
     RECT  20.549 88.896 21.484 88.92 ;
     RECT  21.107 121.392 21.485 121.416 ;
     RECT  21.449 107.088 21.521 107.112 ;
     RECT  20.009 93.072 21.553 93.24 ;
     RECT  21.269 94.224 21.553 94.44 ;
     RECT  21.148 60.816 21.557 61.656 ;
     RECT  20.549 65.52 21.593 65.544 ;
     RECT  20.585 56.64 21.625 56.664 ;
     RECT  21.299 108.288 21.637 109.464 ;
     RECT  20.387 111.6 21.637 111.912 ;
     RECT  21.553 93.072 21.661 94.44 ;
     RECT  21.637 108.288 21.683 112.344 ;
     RECT  21.553 85.44 21.697 85.464 ;
     RECT  21.697 85.392 21.733 85.512 ;
     RECT  21.443 86.592 21.733 87.192 ;
     RECT  21.337 51.648 21.769 51.672 ;
     RECT  21.409 53.088 21.769 53.928 ;
     RECT  21.661 92.88 21.773 94.44 ;
     RECT  21.625 56.4 21.805 56.664 ;
     RECT  21.733 85.392 21.809 87.192 ;
     RECT  20.945 90.048 21.809 90.072 ;
     RECT  21.229 91.728 21.841 91.752 ;
     RECT  20.869 47.136 21.875 47.16 ;
     RECT  21.788 58.032 21.875 58.056 ;
     RECT  21.481 68.208 21.877 70.056 ;
     RECT  21.683 108.288 21.881 110.904 ;
     RECT  21.829 48.96 21.916 49.464 ;
     RECT  21.809 85.392 21.953 86.472 ;
     RECT  21.557 60.816 21.989 60.84 ;
     RECT  21.829 59.232 22.021 59.256 ;
     RECT  21.881 109.44 22.025 109.464 ;
     RECT  20.477 50.592 22.057 50.616 ;
     RECT  21.769 51.648 22.057 53.928 ;
     RECT  21.301 62.832 22.133 64.056 ;
     RECT  21.341 115.392 22.133 115.704 ;
     RECT  21.949 82.608 22.165 82.632 ;
     RECT  21.985 83.808 22.165 83.832 ;
     RECT  22.133 63.984 22.201 64.056 ;
     RECT  22.165 82.608 22.211 83.832 ;
     RECT  21.881 108.288 22.273 108.36 ;
     RECT  20.869 116.832 22.277 118.008 ;
     RECT  21.305 96.336 22.309 96.456 ;
     RECT  22.057 50.592 22.313 53.928 ;
     RECT  22.133 115.68 22.349 115.704 ;
     RECT  21.683 111.888 22.381 112.344 ;
     RECT  21.161 66.672 22.385 66.696 ;
     RECT  22.211 83.232 22.421 83.496 ;
     RECT  21.881 110.88 22.421 110.904 ;
     RECT  22.277 116.832 22.457 116.856 ;
     RECT  21.805 56.4 22.46 56.808 ;
     RECT  22.237 104.832 22.46 104.856 ;
     RECT  21.877 67.824 22.489 70.056 ;
     RECT  22.46 104.544 22.501 104.856 ;
     RECT  22.489 98.88 22.525 98.904 ;
     RECT  22.453 99.936 22.525 100.104 ;
     RECT  22.417 54.96 22.547 54.984 ;
     RECT  22.46 56.352 22.547 56.808 ;
     RECT  22.501 104.544 22.547 104.904 ;
     RECT  21.841 91.344 22.556 91.752 ;
     RECT  22.309 96.336 22.597 97.32 ;
     RECT  22.093 124.848 22.597 124.872 ;
     RECT  22.057 126 22.597 126.024 ;
     RECT  22.547 104.64 22.633 104.904 ;
     RECT  22.057 122.928 22.633 122.952 ;
     RECT  22.597 124.848 22.637 126.024 ;
     RECT  22.556 91.104 22.643 91.752 ;
     RECT  22.633 104.64 22.705 104.952 ;
     RECT  22.643 91.344 22.741 91.752 ;
     RECT  22.313 50.592 22.745 52.776 ;
     RECT  22.705 104.64 22.785 105.144 ;
     RECT  21.953 86.448 22.805 86.472 ;
     RECT  18.904 17.328 22.813 17.352 ;
     RECT  22.805 86.448 22.813 86.616 ;
     RECT  22.741 87.792 22.813 88.344 ;
     RECT  22.597 96.336 22.837 97.368 ;
     RECT  22.273 107.136 22.837 108.36 ;
     RECT  22.633 122.928 22.849 123.096 ;
     RECT  22.813 17.184 22.853 17.352 ;
     RECT  21.347 102.624 22.853 103.464 ;
     RECT  22.813 86.448 22.883 88.344 ;
     RECT  22.883 86.448 22.897 87.288 ;
     RECT  22.837 96 22.924 97.368 ;
     RECT  22.633 81.36 22.988 81.384 ;
     RECT  22.525 98.88 22.988 100.536 ;
     RECT  22.988 98.88 22.993 100.968 ;
     RECT  21.877 113.52 22.993 113.544 ;
     RECT  22.883 88.32 22.997 88.344 ;
     RECT  21.773 93.792 23.065 94.44 ;
     RECT  22.741 91.344 23.077 91.944 ;
     RECT  23.065 92.928 23.077 94.44 ;
     RECT  23.077 62.352 23.101 62.376 ;
     RECT  22.993 98.88 23.101 101.064 ;
     RECT  22.785 104.64 23.101 105.48 ;
     RECT  22.381 111.888 23.132 112.536 ;
     RECT  23.101 98.88 23.137 101.16 ;
     RECT  23.137 98.88 23.173 101.256 ;
     RECT  22.921 120.768 23.209 120.792 ;
     RECT  23.132 111.6 23.276 112.536 ;
     RECT  22.993 113.52 23.276 113.784 ;
     RECT  22.201 63.984 23.281 64.296 ;
     RECT  23.173 98.688 23.281 101.256 ;
     RECT  22.853 102.624 23.281 103.224 ;
     RECT  23.101 104.64 23.317 105.672 ;
     RECT  22.837 106.704 23.317 108.36 ;
     RECT  22.547 56.64 23.353 56.808 ;
     RECT  22.021 58.464 23.353 59.256 ;
     RECT  23.245 109.824 23.353 110.04 ;
     RECT  18.904 38.16 23.461 38.184 ;
     RECT  23.209 120.768 23.564 121.464 ;
     RECT  22.849 122.688 23.564 123.096 ;
     RECT  23.317 104.64 23.569 108.36 ;
     RECT  23.353 109.68 23.569 110.04 ;
     RECT  23.276 111.6 23.605 113.784 ;
     RECT  23.173 114.816 23.605 114.84 ;
     RECT  22.277 117.984 23.605 118.008 ;
     RECT  23.677 119.52 23.713 119.544 ;
     RECT  22.924 96.192 23.785 97.368 ;
     RECT  23.281 98.688 23.785 103.224 ;
     RECT  23.569 104.64 23.785 110.04 ;
     RECT  23.605 111.6 23.785 114.84 ;
     RECT  23.564 120.768 23.793 123.096 ;
     RECT  21.953 85.392 23.893 85.464 ;
     RECT  22.897 86.448 23.893 86.472 ;
     RECT  23.713 119.184 23.893 119.544 ;
     RECT  23.793 120.768 23.893 123.864 ;
     RECT  22.745 50.592 23.965 50.616 ;
     RECT  22.745 51.648 23.965 52.2 ;
     RECT  23.101 61.632 23.965 62.376 ;
     RECT  23.533 88.416 23.965 88.44 ;
     RECT  22.313 53.856 24.001 53.928 ;
     RECT  22.421 83.232 24.001 83.256 ;
     RECT  18.904 5.184 24.008 5.208 ;
     RECT  22.853 17.184 24.008 17.208 ;
     RECT  18.904 36.768 24.008 36.792 ;
     RECT  23.461 38.16 24.008 38.232 ;
     RECT  18.904 42.24 24.008 42.264 ;
     RECT  21.916 48.96 24.008 49.32 ;
     RECT  23.965 50.592 24.008 52.2 ;
     RECT  24.001 53.856 24.008 54.168 ;
     RECT  23.353 56.64 24.008 59.256 ;
     RECT  23.965 61.632 24.008 62.76 ;
     RECT  23.281 63.984 24.008 64.68 ;
     RECT  22.489 67.344 24.008 70.056 ;
     RECT  18.904 71.904 24.008 75.288 ;
     RECT  18.904 76.56 24.008 76.584 ;
     RECT  23.289 79.536 24.008 79.56 ;
     RECT  22.988 81.36 24.008 82.248 ;
     RECT  24.001 83.232 24.008 83.88 ;
     RECT  23.893 85.392 24.008 86.472 ;
     RECT  23.965 88.368 24.008 88.968 ;
     RECT  23.077 91.344 24.008 94.44 ;
     RECT  23.785 96.192 24.008 103.224 ;
     RECT  23.785 104.64 24.008 114.84 ;
     RECT  23.132 116.16 24.008 116.76 ;
     RECT  23.605 117.792 24.008 118.008 ;
     RECT  23.893 119.184 24.008 123.864 ;
     RECT  22.637 125.088 24.008 126.024 ;
     RECT  23.389 128.256 24.008 128.28 ;
     RECT  24.008 2.148 24.112 179.292 ;
     RECT  24.112 2.418 24.304 179.022 ;
     RECT  24.304 79.536 24.419 82.728 ;
     RECT  24.304 120.24 24.419 122.712 ;
     RECT  24.304 123.84 24.419 126.024 ;
     RECT  24.304 52.176 24.437 52.44 ;
     RECT  24.304 127.2 24.445 127.224 ;
     RECT  24.304 89.424 24.473 89.832 ;
     RECT  24.304 91.2 24.515 111.144 ;
     RECT  24.304 56.88 24.545 59.736 ;
     RECT  24.304 64.128 24.545 66.216 ;
     RECT  24.545 59.712 24.563 59.736 ;
     RECT  24.304 83.856 24.563 86.424 ;
     RECT  24.304 61.584 24.589 62.76 ;
     RECT  24.419 121.392 24.617 122.712 ;
     RECT  24.545 56.88 24.689 58.44 ;
     RECT  24.515 91.2 24.725 110.856 ;
     RECT  24.419 123.84 24.725 125.928 ;
     RECT  24.725 91.2 24.755 102.792 ;
     RECT  24.689 56.88 24.803 56.904 ;
     RECT  24.589 61.728 24.803 62.76 ;
     RECT  24.689 58.416 24.833 58.44 ;
     RECT  24.419 79.536 24.851 80.808 ;
     RECT  24.725 125.808 24.892 125.928 ;
     RECT  24.304 112.512 24.941 119.208 ;
     RECT  24.755 91.2 24.995 102.504 ;
     RECT  24.941 112.896 25.013 119.208 ;
     RECT  24.304 36.768 25.043 38.232 ;
     RECT  24.304 87.552 25.049 88.392 ;
     RECT  24.617 121.392 25.049 122.52 ;
     RECT  24.304 39.888 25.057 39.912 ;
     RECT  25.049 121.92 25.091 122.52 ;
     RECT  25.049 87.648 25.121 88.392 ;
     RECT  24.725 123.84 25.121 124.824 ;
     RECT  24.995 91.2 25.157 91.992 ;
     RECT  25.121 123.936 25.18 124.824 ;
     RECT  24.995 93.456 25.187 102.504 ;
     RECT  25.013 113.952 25.229 119.208 ;
     RECT  25.013 112.896 25.235 112.92 ;
     RECT  25.187 93.456 25.331 102.216 ;
     RECT  25.121 88.368 25.337 88.392 ;
     RECT  25.043 36.768 25.379 38.184 ;
     RECT  24.437 52.176 25.379 52.2 ;
     RECT  25.229 113.952 25.379 118.536 ;
     RECT  25.157 91.2 25.405 91.848 ;
     RECT  24.419 82.032 25.436 82.728 ;
     RECT  24.563 83.856 25.436 84.408 ;
     RECT  25.331 93.456 25.475 99.864 ;
     RECT  25.436 33.504 25.477 33.528 ;
     RECT  25.436 78.048 25.477 78.072 ;
     RECT  25.379 36.768 25.523 37.656 ;
     RECT  25.477 78.048 25.523 78.408 ;
     RECT  24.545 64.128 25.549 65.592 ;
     RECT  24.419 120.24 25.621 120.264 ;
     RECT  25.523 78.384 25.657 78.408 ;
     RECT  24.851 79.536 25.657 79.56 ;
     RECT  25.549 64.128 25.669 65.976 ;
     RECT  25.621 119.664 25.669 120.264 ;
     RECT  25.405 91.104 25.697 91.848 ;
     RECT  25.669 64.128 25.715 66.216 ;
     RECT  25.297 3.936 25.717 3.96 ;
     RECT  24.304 5.184 25.717 5.208 ;
     RECT  24.725 104.256 25.724 110.856 ;
     RECT  25.724 104.256 25.729 111.048 ;
     RECT  24.304 17.184 25.763 17.208 ;
     RECT  25.717 3.936 25.765 5.208 ;
     RECT  24.304 71.904 25.765 75.432 ;
     RECT  25.729 103.68 25.765 111.048 ;
     RECT  25.715 66.192 25.769 66.216 ;
     RECT  24.892 125.904 25.801 125.928 ;
     RECT  25.765 3.936 25.805 5.64 ;
     RECT  25.715 64.128 25.805 65.16 ;
     RECT  24.304 67.344 25.805 70.056 ;
     RECT  25.657 78.384 25.805 79.56 ;
     RECT  25.436 82.032 25.805 84.408 ;
     RECT  25.669 119.664 25.805 120.312 ;
     RECT  25.477 33.504 25.811 33.912 ;
     RECT  25.805 5.184 25.852 5.64 ;
     RECT  25.765 71.52 25.852 75.432 ;
     RECT  25.523 36.768 25.909 37.464 ;
     RECT  24.803 61.728 25.909 61.752 ;
     RECT  24.803 62.736 25.909 62.76 ;
     RECT  25.801 125.904 25.916 126.6 ;
     RECT  24.563 85.488 25.949 86.424 ;
     RECT  25.811 33.888 25.955 33.912 ;
     RECT  25.909 61.728 25.955 62.76 ;
     RECT  25.916 125.904 25.957 126.984 ;
     RECT  25.379 116.112 25.985 118.536 ;
     RECT  25.805 119.664 25.985 120.264 ;
     RECT  25.909 58.656 25.993 58.68 ;
     RECT  25.985 116.112 26.021 117.672 ;
     RECT  25.805 78.576 26.029 79.56 ;
     RECT  25.805 64.128 26.051 64.152 ;
     RECT  26.029 78.672 26.057 79.56 ;
     RECT  25.957 125.904 26.099 127.512 ;
     RECT  25.949 85.92 26.117 86.424 ;
     RECT  25.909 35.952 26.129 37.464 ;
     RECT  26.053 0.576 26.137 0.6 ;
     RECT  26.057 79.008 26.149 79.56 ;
     RECT  24.851 80.784 26.149 80.808 ;
     RECT  25.669 2.832 26.156 2.856 ;
     RECT  26.129 35.952 26.165 37.272 ;
     RECT  26.149 80.784 26.195 81.336 ;
     RECT  26.117 85.92 26.201 86.664 ;
     RECT  26.149 79.008 26.236 79.752 ;
     RECT  25.331 100.848 26.237 102.216 ;
     RECT  25.549 60 26.273 60.024 ;
     RECT  26.149 92.832 26.305 92.856 ;
     RECT  25.091 121.92 26.309 122.376 ;
     RECT  25.697 91.104 26.341 91.224 ;
     RECT  25.18 124.272 26.341 124.824 ;
     RECT  25.805 68.208 26.345 70.056 ;
     RECT  25.805 82.56 26.345 84.408 ;
     RECT  26.3 0.528 26.387 0.552 ;
     RECT  26.099 126.576 26.389 127.512 ;
     RECT  25.475 93.984 26.453 99.864 ;
     RECT  26.156 2.256 26.485 2.856 ;
     RECT  26.453 96.336 26.521 99.864 ;
     RECT  26.237 100.848 26.521 101.448 ;
     RECT  26.305 92.784 26.525 92.856 ;
     RECT  25.765 103.68 26.581 111.144 ;
     RECT  26.557 112.752 26.581 112.776 ;
     RECT  26.581 103.68 26.629 112.776 ;
     RECT  26.345 82.56 26.633 83.064 ;
     RECT  26.345 84.048 26.633 84.408 ;
     RECT  24.473 89.424 26.633 89.448 ;
     RECT  26.521 96.336 26.633 101.448 ;
     RECT  26.341 90.72 26.665 91.224 ;
     RECT  26.201 85.92 26.669 86.184 ;
     RECT  26.633 96.336 26.675 99.624 ;
     RECT  26.453 93.984 26.705 95.208 ;
     RECT  26.629 102.624 26.705 112.776 ;
     RECT  25.333 45.696 26.737 45.72 ;
     RECT  26.675 96.336 26.741 99.48 ;
     RECT  26.705 102.624 26.741 109.512 ;
     RECT  26.629 119.424 26.741 119.448 ;
     RECT  26.629 0.096 26.777 0.216 ;
     RECT  26.737 45.168 26.777 45.72 ;
     RECT  26.665 90.72 26.809 91.992 ;
     RECT  26.165 35.952 26.813 37.128 ;
     RECT  26.236 79.008 26.813 79.176 ;
     RECT  26.669 86.16 26.813 86.184 ;
     RECT  26.705 93.984 26.813 94.872 ;
     RECT  26.341 124.176 26.813 124.824 ;
     RECT  26.195 81.312 26.849 81.336 ;
     RECT  26.777 0.192 26.857 0.216 ;
     RECT  26.809 90.576 26.885 91.992 ;
     RECT  25.955 61.728 26.917 62.568 ;
     RECT  25.379 113.952 26.917 114.936 ;
     RECT  26.021 116.112 26.917 116.136 ;
     RECT  26.917 6.288 26.953 6.312 ;
     RECT  26.876 64.032 26.963 64.056 ;
     RECT  26.813 36.48 27.029 37.128 ;
     RECT  24.304 53.856 27.097 54.6 ;
     RECT  26.845 57.312 27.097 57.336 ;
     RECT  27.068 87.792 27.109 87.816 ;
     RECT  26.917 113.952 27.133 116.136 ;
     RECT  26.741 102.624 27.137 107.256 ;
     RECT  26.917 61.728 27.209 63 ;
     RECT  26.485 1.728 27.245 2.856 ;
     RECT  25.852 5.184 27.249 5.208 ;
     RECT  26.953 6.288 27.251 6.36 ;
     RECT  26.521 59.04 27.277 59.064 ;
     RECT  27.133 113.952 27.277 116.52 ;
     RECT  26.021 117.504 27.277 117.672 ;
     RECT  26.633 82.944 27.281 83.064 ;
     RECT  26.633 100.752 27.299 101.448 ;
     RECT  27.209 62.976 27.313 63 ;
     RECT  26.633 84.048 27.313 84.072 ;
     RECT  26.705 110.832 27.313 112.776 ;
     RECT  27.277 113.952 27.313 118.584 ;
     RECT  27.299 100.848 27.317 101.448 ;
     RECT  27.245 1.728 27.349 1.752 ;
     RECT  27.277 59.04 27.353 59.88 ;
     RECT  27.109 87.168 27.353 87.816 ;
     RECT  26.813 124.8 27.385 124.824 ;
     RECT  27.301 3.936 27.388 3.96 ;
     RECT  27.313 110.832 27.395 118.584 ;
     RECT  27.245 2.832 27.421 2.856 ;
     RECT  26.005 66.768 27.421 66.792 ;
     RECT  26.345 68.208 27.421 69.768 ;
     RECT  27.395 110.832 27.425 117.528 ;
     RECT  27.385 124.8 27.425 124.92 ;
     RECT  27.317 100.896 27.445 101.448 ;
     RECT  27.137 102.624 27.445 106.008 ;
     RECT  27.251 6.288 27.461 6.312 ;
     RECT  27.137 107.136 27.461 107.256 ;
     RECT  27.249 5.088 27.493 5.208 ;
     RECT  27.313 83.184 27.497 84.072 ;
     RECT  27.445 100.896 27.533 106.008 ;
     RECT  27.349 1.104 27.539 1.752 ;
     RECT  27.313 62.976 27.565 63.048 ;
     RECT  25.805 65.136 27.565 65.16 ;
     RECT  27.565 62.976 27.605 63.24 ;
     RECT  27.425 110.832 27.605 116.52 ;
     RECT  27.497 83.856 27.644 84.072 ;
     RECT  27.565 65.088 27.673 65.16 ;
     RECT  26.309 122.352 27.673 122.376 ;
     RECT  27.605 113.424 27.683 116.52 ;
     RECT  27.353 87.792 27.685 87.816 ;
     RECT  27.685 87.792 27.731 88.68 ;
     RECT  27.731 88.176 27.772 88.68 ;
     RECT  25.852 71.76 27.781 75.432 ;
     RECT  26.885 90.576 27.817 91.176 ;
     RECT  27.395 118.56 27.817 118.584 ;
     RECT  27.637 119.664 27.817 119.688 ;
     RECT  27.673 122.352 27.817 123.096 ;
     RECT  27.421 2.832 27.827 3 ;
     RECT  26.953 93.312 27.877 93.48 ;
     RECT  26.813 94.512 27.877 94.872 ;
     RECT  26.741 96.336 27.877 99.192 ;
     RECT  27.673 64.608 27.925 65.16 ;
     RECT  27.925 50.16 27.961 50.184 ;
     RECT  27.533 102.624 27.965 106.008 ;
     RECT  27.461 107.136 27.965 107.16 ;
     RECT  27.683 113.424 27.965 114.936 ;
     RECT  27.817 121.392 27.971 123.096 ;
     RECT  27.817 118.56 28.037 119.688 ;
     RECT  27.421 66.768 28.069 69.768 ;
     RECT  27.029 36.48 28.117 36.792 ;
     RECT  27.817 90.24 28.117 91.176 ;
     RECT  28.037 118.608 28.145 119.688 ;
     RECT  27.781 70.896 28.172 75.432 ;
     RECT  24.304 76.56 28.172 76.584 ;
     RECT  28.172 70.896 28.177 76.584 ;
     RECT  27.605 110.832 28.181 112.392 ;
     RECT  27.965 113.712 28.181 114.936 ;
     RECT  27.971 121.92 28.181 123.096 ;
     RECT  28.177 70.848 28.204 76.584 ;
     RECT  27.539 1.728 28.213 1.752 ;
     RECT  28.204 71.904 28.213 76.584 ;
     RECT  27.644 83.856 28.22 84.408 ;
     RECT  27.925 64.56 28.253 65.688 ;
     RECT  27.601 86.496 28.253 86.52 ;
     RECT  27.605 63.024 28.285 63.24 ;
     RECT  27.877 92.928 28.285 99.192 ;
     RECT  26.741 108.384 28.285 109.512 ;
     RECT  28.181 110.832 28.285 112.344 ;
     RECT  28.145 118.752 28.289 119.688 ;
     RECT  28.213 1.728 28.297 1.8 ;
     RECT  28.22 83.856 28.307 84.84 ;
     RECT  27.961 50.16 28.321 51.096 ;
     RECT  27.353 59.136 28.321 59.88 ;
     RECT  28.069 66.672 28.321 69.768 ;
     RECT  28.204 70.848 28.321 70.92 ;
     RECT  26.813 79.008 28.321 79.032 ;
     RECT  28.117 36.48 28.357 37.368 ;
     RECT  28.141 38.448 28.357 38.472 ;
     RECT  28.285 92.928 28.357 99.672 ;
     RECT  28.357 92.928 28.361 99.72 ;
     RECT  28.361 92.928 28.429 94.728 ;
     RECT  27.493 5.088 28.501 6.024 ;
     RECT  28.501 5.088 28.537 6.648 ;
     RECT  27.965 105.984 28.537 106.008 ;
     RECT  27.425 124.896 28.652 124.92 ;
     RECT  28.321 79.008 28.861 79.224 ;
     RECT  28.393 77.952 28.897 77.976 ;
     RECT  28.861 79.008 28.897 80.136 ;
     RECT  27.097 53.856 28.933 55.416 ;
     RECT  28.289 119.088 28.969 119.688 ;
     RECT  28.897 77.952 28.981 80.136 ;
     RECT  28.789 82.176 28.981 82.2 ;
     RECT  27.209 61.728 28.988 61.752 ;
     RECT  28.321 66.672 29.005 70.92 ;
     RECT  28.307 83.856 29.005 84.072 ;
     RECT  27.533 100.896 29.005 101.4 ;
     RECT  28.652 124.896 29.005 125.592 ;
     RECT  28.988 61.728 29.029 61.848 ;
     RECT  29.005 100.896 29.029 101.496 ;
     RECT  27.965 102.624 29.029 104.952 ;
     RECT  27.772 88.176 29.077 88.2 ;
     RECT  28.181 114.192 29.077 114.936 ;
     RECT  27.683 116.304 29.077 116.52 ;
     RECT  27.425 117.504 29.077 117.528 ;
     RECT  28.537 105.984 29.132 106.68 ;
     RECT  29.132 105.984 29.141 107.016 ;
     RECT  29.029 100.896 29.149 104.952 ;
     RECT  28.297 1.728 29.153 1.752 ;
     RECT  26.777 45.168 29.185 45.192 ;
     RECT  29.141 105.984 29.221 107.4 ;
     RECT  28.285 108.384 29.221 112.344 ;
     RECT  25.477 30.048 29.269 30.072 ;
     RECT  29.149 100.896 29.269 105 ;
     RECT  29.221 105.984 29.269 112.344 ;
     RECT  28.429 92.304 29.293 94.728 ;
     RECT  28.933 144.192 29.293 144.216 ;
     RECT  28.693 134.016 29.365 134.04 ;
     RECT  29.005 66.576 29.401 70.92 ;
     RECT  28.213 71.904 29.401 76.92 ;
     RECT  27.827 2.832 29.408 2.856 ;
     RECT  28.537 4.512 29.408 6.648 ;
     RECT  29.049 25.008 29.408 25.032 ;
     RECT  28.753 26.592 29.408 26.616 ;
     RECT  29.269 28.752 29.408 28.776 ;
     RECT  29.269 29.856 29.408 30.072 ;
     RECT  28.357 36.48 29.408 38.472 ;
     RECT  24.304 42.24 29.408 42.264 ;
     RECT  29.185 45.168 29.408 46.104 ;
     RECT  28.717 48.384 29.408 48.408 ;
     RECT  28.321 50.16 29.408 52.056 ;
     RECT  28.933 53.856 29.408 55.8 ;
     RECT  27.097 57.312 29.408 57.576 ;
     RECT  28.321 58.656 29.408 59.88 ;
     RECT  29.029 61.152 29.408 61.848 ;
     RECT  28.285 63.024 29.408 63.288 ;
     RECT  28.253 64.56 29.408 65.16 ;
     RECT  29.401 66.576 29.408 76.92 ;
     RECT  28.981 77.952 29.408 82.2 ;
     RECT  29.005 83.568 29.408 84.072 ;
     RECT  29.077 87.12 29.408 88.2 ;
     RECT  28.117 89.472 29.408 91.176 ;
     RECT  29.293 92.208 29.408 94.728 ;
     RECT  28.361 95.76 29.408 99.72 ;
     RECT  29.269 100.896 29.408 112.344 ;
     RECT  29.077 114.192 29.408 117.528 ;
     RECT  28.969 119.088 29.408 119.736 ;
     RECT  28.645 120.864 29.408 120.888 ;
     RECT  28.181 122.208 29.408 123.096 ;
     RECT  29.005 124.896 29.408 125.976 ;
     RECT  26.389 127.488 29.408 127.512 ;
     RECT  29.293 128.88 29.408 128.904 ;
     RECT  29.365 134.016 29.408 134.808 ;
     RECT  29.221 141.888 29.408 141.912 ;
     RECT  29.293 144 29.408 144.216 ;
     RECT  29.005 146.448 29.408 146.472 ;
     RECT  29.408 2.148 29.512 179.292 ;
     RECT  29.293 0.528 29.653 0.552 ;
     RECT  29.512 2.418 29.704 179.022 ;
     RECT  29.704 28.752 29.765 28.776 ;
     RECT  29.704 92.208 29.765 92.904 ;
     RECT  29.704 109.776 29.765 110.856 ;
     RECT  29.704 120.864 29.765 121.608 ;
     RECT  29.704 150.48 29.765 151.032 ;
     RECT  29.653 0.528 29.789 0.6 ;
     RECT  29.704 37.44 29.801 37.464 ;
     RECT  29.704 47.856 29.801 50.424 ;
     RECT  29.704 94.368 29.801 99.72 ;
     RECT  29.704 104.88 29.801 106.008 ;
     RECT  29.765 150.48 29.801 150.504 ;
     RECT  29.801 47.856 29.843 48.216 ;
     RECT  29.704 87.456 29.843 89.832 ;
     RECT  29.704 125.952 29.843 127.512 ;
     RECT  29.704 128.88 29.843 129.432 ;
     RECT  29.704 143.952 29.843 146.856 ;
     RECT  29.704 147.84 29.843 147.864 ;
     RECT  29.704 81.36 29.873 81.624 ;
     RECT  29.704 141.312 29.891 142.776 ;
     RECT  29.704 38.448 29.909 38.52 ;
     RECT  29.704 76.464 29.932 79.128 ;
     RECT  29.704 102.096 29.945 103.896 ;
     RECT  29.801 94.368 29.987 99.576 ;
     RECT  29.945 103.776 29.987 103.896 ;
     RECT  29.801 105.36 29.987 106.008 ;
     RECT  29.704 130.512 29.987 130.536 ;
     RECT  29.873 81.456 30.025 81.624 ;
     RECT  29.945 102.096 30.025 102.648 ;
     RECT  29.987 105.36 30.028 105.384 ;
     RECT  29.704 113.76 30.125 115.752 ;
     RECT  30.025 81.6 30.131 81.624 ;
     RECT  29.843 87.456 30.131 88.92 ;
     RECT  29.704 80.112 30.197 80.28 ;
     RECT  29.789 0.528 30.229 1.176 ;
     RECT  29.704 107.136 30.269 108.792 ;
     RECT  29.704 53.136 30.275 57.336 ;
     RECT  29.704 6.624 30.305 6.648 ;
     RECT  30.131 88.368 30.305 88.92 ;
     RECT  30.275 53.136 30.316 56.568 ;
     RECT  29.704 85.392 30.371 85.416 ;
     RECT  29.987 103.776 30.377 103.8 ;
     RECT  29.987 96.96 30.413 99.576 ;
     RECT  29.765 121.584 30.467 121.608 ;
     RECT  29.704 119.664 30.493 119.688 ;
     RECT  29.704 2.418 30.517 5.208 ;
     RECT  29.801 49.2 30.563 50.424 ;
     RECT  29.704 58.656 30.629 61.464 ;
     RECT  30.517 2.304 30.665 5.208 ;
     RECT  30.269 107.136 30.665 107.448 ;
     RECT  29.704 138.48 30.665 138.504 ;
     RECT  29.704 62.688 30.733 63 ;
     RECT  29.704 175.584 30.733 175.608 ;
     RECT  29.843 125.952 30.737 126.504 ;
     RECT  29.704 134.016 30.737 135.096 ;
     RECT  29.704 116.976 30.757 117.528 ;
     RECT  30.733 118.704 30.757 119.16 ;
     RECT  30.737 125.952 30.769 126.12 ;
     RECT  29.704 176.688 30.769 176.76 ;
     RECT  30.737 134.112 30.773 135.096 ;
     RECT  29.704 45.168 30.803 46.2 ;
     RECT  30.229 0.096 30.805 1.176 ;
     RECT  30.629 58.992 30.805 61.464 ;
     RECT  30.697 122.736 30.805 122.76 ;
     RECT  29.843 129.408 30.805 129.432 ;
     RECT  29.765 92.88 30.809 92.904 ;
     RECT  29.843 143.952 30.809 145.656 ;
     RECT  30.805 122.64 30.841 122.76 ;
     RECT  29.704 123.744 30.841 124.056 ;
     RECT  30.733 180.144 30.851 180.168 ;
     RECT  30.757 116.976 30.853 119.16 ;
     RECT  30.769 125.088 30.853 126.12 ;
     RECT  30.733 62.688 30.877 63.144 ;
     RECT  30.316 53.568 30.881 56.568 ;
     RECT  29.987 94.368 30.881 95.784 ;
     RECT  29.932 76.464 30.901 77.976 ;
     RECT  29.932 79.008 30.901 79.128 ;
     RECT  30.197 80.256 30.901 80.28 ;
     RECT  30.805 58.992 30.913 61.656 ;
     RECT  30.877 62.64 30.913 63.144 ;
     RECT  29.704 82.944 30.913 84.36 ;
     RECT  30.413 96.96 30.94 98.616 ;
     RECT  30.853 116.448 30.94 119.16 ;
     RECT  29.843 47.856 30.949 47.88 ;
     RECT  30.769 176.688 30.985 176.808 ;
     RECT  29.704 178.368 30.985 178.968 ;
     RECT  30.881 94.368 30.989 95.64 ;
     RECT  30.665 107.136 31.021 107.256 ;
     RECT  30.805 0.096 31.025 1.752 ;
     RECT  30.985 176.688 31.025 176.856 ;
     RECT  29.704 64.32 31.057 75.48 ;
     RECT  30.901 76.464 31.057 79.128 ;
     RECT  29.704 136.272 31.057 136.824 ;
     RECT  29.891 141.312 31.057 141.336 ;
     RECT  30.949 181.296 31.061 181.32 ;
     RECT  30.805 129.312 31.093 129.432 ;
     RECT  30.733 175.008 31.093 175.608 ;
     RECT  29.909 38.496 31.097 38.52 ;
     RECT  29.765 109.968 31.097 110.856 ;
     RECT  31.057 136.272 31.097 137.352 ;
     RECT  31.093 128.928 31.165 129.432 ;
     RECT  29.704 139.68 31.165 140.184 ;
     RECT  30.877 150.576 31.165 150.6 ;
     RECT  30.125 113.76 31.205 115.128 ;
     RECT  31.205 113.76 31.235 114.696 ;
     RECT  31.165 128.928 31.237 129.528 ;
     RECT  31.201 130.512 31.237 130.536 ;
     RECT  30.803 45.168 31.273 46.104 ;
     RECT  30.949 47.472 31.277 47.88 ;
     RECT  30.269 108.768 31.309 108.792 ;
     RECT  31.237 128.928 31.309 130.536 ;
     RECT  30.809 145.632 31.309 145.656 ;
     RECT  30.94 97.68 31.313 98.616 ;
     RECT  31.057 64.32 31.333 79.128 ;
     RECT  30.901 80.256 31.333 80.424 ;
     RECT  30.913 82.752 31.333 84.36 ;
     RECT  30.841 122.64 31.333 124.056 ;
     RECT  31.165 150.576 31.333 151.08 ;
     RECT  30.563 50.4 31.345 50.424 ;
     RECT  31.021 51.504 31.345 51.528 ;
     RECT  31.309 128.736 31.345 130.536 ;
     RECT  30.949 156.192 31.345 156.216 ;
     RECT  30.769 100.704 31.379 100.728 ;
     RECT  31.021 106.704 31.379 107.256 ;
     RECT  31.309 108.768 31.379 109.848 ;
     RECT  31.333 64.32 31.381 80.424 ;
     RECT  30.305 88.896 31.381 88.92 ;
     RECT  31.345 120.144 31.381 120.168 ;
     RECT  31.057 141.312 31.381 141.912 ;
     RECT  31.345 155.712 31.385 156.216 ;
     RECT  31.379 109.392 31.393 109.848 ;
     RECT  31.333 82.272 31.421 84.36 ;
     RECT  31.333 105.408 31.421 105.432 ;
     RECT  31.379 107.232 31.421 107.256 ;
     RECT  31.345 128.64 31.453 130.536 ;
     RECT  31.381 64.32 31.457 80.952 ;
     RECT  31.333 122.496 31.475 124.056 ;
     RECT  31.309 145.632 31.477 145.848 ;
     RECT  29.843 146.832 31.477 146.856 ;
     RECT  30.94 117.36 31.489 119.16 ;
     RECT  31.381 120.144 31.489 120.264 ;
     RECT  31.313 98.592 31.493 98.616 ;
     RECT  31.333 99.696 31.493 99.72 ;
     RECT  30.853 126 31.493 126.12 ;
     RECT  31.025 176.784 31.493 176.856 ;
     RECT  31.477 145.632 31.523 146.856 ;
     RECT  30.985 178.368 31.561 179.592 ;
     RECT  31.477 148.032 31.564 148.056 ;
     RECT  31.457 64.368 31.565 80.952 ;
     RECT  31.453 128.496 31.565 130.536 ;
     RECT  31.484 133.056 31.571 133.08 ;
     RECT  31.381 88.896 31.573 89.544 ;
     RECT  29.843 127.488 31.573 127.512 ;
     RECT  29.704 131.712 31.573 131.976 ;
     RECT  31.273 44.448 31.619 46.104 ;
     RECT  30.989 94.56 31.619 95.64 ;
     RECT  31.475 123.072 31.619 124.056 ;
     RECT  30.913 58.992 31.621 63.144 ;
     RECT  31.333 150.432 31.628 151.08 ;
     RECT  31.565 64.368 31.637 79.8 ;
     RECT  31.565 80.928 31.637 80.952 ;
     RECT  31.637 79.536 31.66 79.8 ;
     RECT  31.621 58.8 31.669 63.144 ;
     RECT  31.345 85.824 31.669 85.848 ;
     RECT  31.165 138.528 31.669 140.184 ;
     RECT  31.093 174.672 31.669 175.608 ;
     RECT  30.025 102.096 31.705 102.408 ;
     RECT  31.573 127.488 31.705 127.944 ;
     RECT  29.704 149.136 31.705 149.208 ;
     RECT  31.628 150.432 31.705 151.896 ;
     RECT  30.773 134.112 31.709 134.808 ;
     RECT  31.489 117.36 31.715 120.264 ;
     RECT  31.669 138.384 31.715 140.184 ;
     RECT  31.705 149.136 31.715 151.896 ;
     RECT  29.704 154.08 31.717 154.104 ;
     RECT  31.385 155.712 31.717 155.736 ;
     RECT  31.705 102 31.745 102.408 ;
     RECT  31.709 134.112 31.763 134.136 ;
     RECT  31.717 153.312 31.763 155.736 ;
     RECT  31.669 85.776 31.765 85.848 ;
     RECT  31.763 153.312 31.777 153.336 ;
     RECT  30.881 56.496 31.781 56.568 ;
     RECT  31.235 113.76 31.781 114.6 ;
     RECT  31.715 149.136 31.789 151.08 ;
     RECT  31.561 178.128 31.813 179.592 ;
     RECT  31.637 64.368 31.817 78.408 ;
     RECT  31.097 137.328 31.817 137.352 ;
     RECT  31.777 152.592 31.817 153.336 ;
     RECT  31.345 50.4 31.849 51.528 ;
     RECT  31.765 85.776 31.852 86.232 ;
     RECT  31.781 113.76 31.853 114.552 ;
     RECT  31.849 121.392 31.861 121.416 ;
     RECT  31.715 138.384 31.889 138.408 ;
     RECT  31.715 117.36 31.907 120.168 ;
     RECT  31.669 58.704 31.921 63.144 ;
     RECT  31.921 58.656 31.925 63.144 ;
     RECT  29.704 111.936 31.925 111.96 ;
     RECT  31.813 178.128 31.957 180.12 ;
     RECT  31.277 47.472 31.961 47.64 ;
     RECT  31.849 50.4 31.961 51.576 ;
     RECT  31.852 85.776 31.961 85.8 ;
     RECT  30.881 53.568 31.993 55.272 ;
     RECT  31.925 58.656 31.997 61.032 ;
     RECT  30.805 17.472 32.021 17.496 ;
     RECT  31.993 173.136 32.029 173.16 ;
     RECT  31.619 124.032 32.033 124.056 ;
     RECT  31.957 177.84 32.033 180.12 ;
     RECT  31.777 87.264 32.053 87.288 ;
     RECT  30.809 143.952 32.06 144.648 ;
     RECT  31.523 145.632 32.06 146.184 ;
     RECT  31.907 117.36 32.101 120.12 ;
     RECT  31.789 149.136 32.101 149.4 ;
     RECT  31.025 0.096 32.105 1.224 ;
     RECT  32.021 17.472 32.105 17.64 ;
     RECT  31.993 53.568 32.105 55.848 ;
     RECT  31.861 121.296 32.137 121.416 ;
     RECT  31.573 131.712 32.137 132.216 ;
     RECT  31.961 47.472 32.141 47.496 ;
     RECT  29.704 25.008 32.147 25.032 ;
     RECT  32.053 87.216 32.177 87.288 ;
     RECT  32.101 18.672 32.185 18.792 ;
     RECT  32.105 17.472 32.195 17.496 ;
     RECT  32.185 18.672 32.195 18.696 ;
     RECT  31.715 139.44 32.197 140.184 ;
     RECT  31.381 141.312 32.197 142.104 ;
     RECT  32.029 172.8 32.197 173.16 ;
     RECT  31.669 174.192 32.197 175.608 ;
     RECT  32.105 53.568 32.209 54.792 ;
     RECT  31.817 76.272 32.213 78.408 ;
     RECT  32.197 139.44 32.243 142.344 ;
     RECT  30.665 2.784 32.245 5.208 ;
     RECT  32.243 140.016 32.245 142.344 ;
     RECT  31.817 64.368 32.249 75.288 ;
     RECT  31.789 150.528 32.249 151.08 ;
     RECT  31.961 50.736 32.281 51.576 ;
     RECT  31.813 57.072 32.281 57.096 ;
     RECT  31.997 58.656 32.281 59.16 ;
     RECT  31.565 129.312 32.281 130.536 ;
     RECT  32.137 131.616 32.281 132.216 ;
     RECT  29.704 42.24 32.317 42.264 ;
     RECT  31.633 43.296 32.317 43.32 ;
     RECT  32.245 140.016 32.329 142.488 ;
     RECT  32.101 181.248 32.339 181.272 ;
     RECT  31.573 88.896 32.341 89.736 ;
     RECT  31.097 110.832 32.341 110.856 ;
     RECT  32.317 42.24 32.357 43.32 ;
     RECT  31.619 95.088 32.357 95.64 ;
     RECT  32.341 88.896 32.387 90.072 ;
     RECT  32.101 112.464 32.387 112.488 ;
     RECT  32.245 2.736 32.389 5.208 ;
     RECT  32.387 89.712 32.429 90.072 ;
     RECT  32.281 50.736 32.461 51.96 ;
     RECT  31.421 83.232 32.461 84.36 ;
     RECT  32.029 99.312 32.465 99.336 ;
     RECT  32.033 177.84 32.476 179.544 ;
     RECT  32.461 50.736 32.485 52.008 ;
     RECT  32.209 52.992 32.485 54.792 ;
     RECT  31.925 62.16 32.497 63.144 ;
     RECT  32.281 57.072 32.501 59.16 ;
     RECT  31.745 102 32.501 102.024 ;
     RECT  31.493 176.832 32.501 176.856 ;
     RECT  32.213 76.272 32.524 78.168 ;
     RECT  32.425 49.584 32.531 49.608 ;
     RECT  32.485 50.736 32.531 54.792 ;
     RECT  32.497 62.16 32.537 63.24 ;
     RECT  32.177 87.264 32.537 87.288 ;
     RECT  32.531 51.936 32.573 54.792 ;
     RECT  31.763 154.848 32.573 155.736 ;
     RECT  32.357 95.088 32.579 95.112 ;
     RECT  32.492 169.872 32.579 169.896 ;
     RECT  32.149 12.864 32.609 12.888 ;
     RECT  32.531 50.736 32.627 50.76 ;
     RECT  31.237 157.92 32.636 157.944 ;
     RECT  31.885 81.552 32.641 81.576 ;
     RECT  32.197 172.8 32.641 175.608 ;
     RECT  32.533 91.728 32.675 91.752 ;
     RECT  32.389 2.304 32.677 5.208 ;
     RECT  31.813 6.336 32.677 6.36 ;
     RECT  32.641 81.552 32.677 82.104 ;
     RECT  32.461 83.232 32.677 84.6 ;
     RECT  31.393 109.824 32.677 109.848 ;
     RECT  31.705 126.576 32.677 127.944 ;
     RECT  32.101 148.752 32.677 149.4 ;
     RECT  32.641 172.8 32.677 175.656 ;
     RECT  32.636 157.92 32.681 158.424 ;
     RECT  32.495 93.504 32.717 93.528 ;
     RECT  32.281 129.312 32.717 132.216 ;
     RECT  32.533 168.672 32.717 168.696 ;
     RECT  32.636 94.56 32.723 94.584 ;
     RECT  32.329 140.016 32.723 142.344 ;
     RECT  32.681 158.4 32.723 158.424 ;
     RECT  31.66 79.536 32.753 79.56 ;
     RECT  32.677 109.44 32.761 109.848 ;
     RECT  32.761 109.824 32.771 109.848 ;
     RECT  32.677 126.432 32.773 127.944 ;
     RECT  32.677 171.888 32.773 175.656 ;
     RECT  32.06 143.952 32.78 146.184 ;
     RECT  32.677 165.888 32.78 165.912 ;
     RECT  32.573 155.712 32.785 155.736 ;
     RECT  32.677 2.304 32.821 6.36 ;
     RECT  31.817 152.592 32.821 153.24 ;
     RECT  32.785 155.712 32.825 156.168 ;
     RECT  32.78 165.888 32.825 166.776 ;
     RECT  32.137 121.296 32.857 121.992 ;
     RECT  32.773 126.432 32.857 128.232 ;
     RECT  32.773 171.552 32.86 175.656 ;
     RECT  32.677 148.32 32.867 149.4 ;
     RECT  32.821 152.592 32.867 153.48 ;
     RECT  32.825 165.936 32.867 166.776 ;
     RECT  32.105 55.824 32.893 55.848 ;
     RECT  31.619 44.448 32.897 45.192 ;
     RECT  32.476 178.128 32.897 179.544 ;
     RECT  32.867 152.784 32.917 153.48 ;
     RECT  32.857 121.296 32.929 122.76 ;
     RECT  32.785 87.744 32.963 87.768 ;
     RECT  32.821 2.304 32.965 6.888 ;
     RECT  32.78 143.952 32.965 146.472 ;
     RECT  32.537 62.256 33.005 63.24 ;
     RECT  32.929 121.296 33.005 123.048 ;
     RECT  32.717 129.312 33.013 131.16 ;
     RECT  33.005 62.448 33.037 63.24 ;
     RECT  32.723 140.16 33.059 142.344 ;
     RECT  32.533 38.208 33.061 38.232 ;
     RECT  33.005 122.4 33.073 123.048 ;
     RECT  32.357 42.24 33.107 42.984 ;
     RECT  33.037 62.448 33.109 63.384 ;
     RECT  32.524 76.272 33.113 78.12 ;
     RECT  32.785 124.272 33.113 124.296 ;
     RECT  32.857 126.288 33.113 128.232 ;
     RECT  32.893 55.824 33.145 56.04 ;
     RECT  32.86 171.888 33.145 175.656 ;
     RECT  33.061 40.32 33.148 40.344 ;
     RECT  33.113 76.368 33.149 78.12 ;
     RECT  32.677 81.552 33.157 84.6 ;
     RECT  32.825 156.144 33.181 156.168 ;
     RECT  32.501 57.072 33.185 58.68 ;
     RECT  33.061 79.824 33.217 79.848 ;
     RECT  33.157 81.36 33.217 84.6 ;
     RECT  31.853 113.76 33.217 114.024 ;
     RECT  31.309 135.936 33.217 136.248 ;
     RECT  32.917 152.784 33.221 154.488 ;
     RECT  33.217 79.824 33.244 84.6 ;
     RECT  32.105 0.096 33.253 0.6 ;
     RECT  32.965 1.728 33.253 6.888 ;
     RECT  33.145 55.824 33.253 56.088 ;
     RECT  33.185 57.072 33.253 57.624 ;
     RECT  33.109 62.448 33.253 63.48 ;
     RECT  32.249 64.8 33.253 75.288 ;
     RECT  32.965 143.328 33.253 146.472 ;
     RECT  32.677 163.92 33.257 163.944 ;
     RECT  33.113 126.288 33.325 127.512 ;
     RECT  33.325 126 33.349 127.512 ;
     RECT  33.349 14.832 33.356 14.856 ;
     RECT  33.253 55.824 33.365 57.624 ;
     RECT  33.244 79.824 33.365 80.424 ;
     RECT  33.013 129.216 33.365 131.16 ;
     RECT  33.308 11.04 33.395 11.064 ;
     RECT  32.341 110.832 33.397 111.144 ;
     RECT  33.365 129.216 33.397 130.056 ;
     RECT  32.249 150.576 33.401 151.08 ;
     RECT  31.777 133.344 33.433 133.464 ;
     RECT  32.497 100.08 33.437 100.104 ;
     RECT  33.217 113.232 33.437 114.024 ;
     RECT  33.356 14.832 33.443 15.096 ;
     RECT  33.361 18.24 33.445 18.264 ;
     RECT  33.217 135.888 33.473 136.248 ;
     RECT  32.867 149.376 33.473 149.4 ;
     RECT  33.217 115.728 33.493 115.752 ;
     RECT  32.101 116.928 33.493 120.12 ;
     RECT  32.897 178.128 33.5 179.256 ;
     RECT  32.677 138.768 33.505 139.032 ;
     RECT  33.145 171.888 33.505 175.944 ;
     RECT  33.5 177.84 33.505 179.256 ;
     RECT  33.349 125.952 33.509 127.512 ;
     RECT  31.997 60.384 33.541 61.032 ;
     RECT  33.469 86.688 33.541 86.712 ;
     RECT  33.443 14.832 33.545 14.856 ;
     RECT  32.573 51.936 33.577 54.744 ;
     RECT  33.365 55.824 33.577 56.088 ;
     RECT  33.149 76.56 33.577 78.12 ;
     RECT  33.244 81.696 33.577 84.6 ;
     RECT  33.541 86.304 33.577 86.712 ;
     RECT  32.429 89.712 33.577 89.736 ;
     RECT  33.221 153.216 33.577 154.488 ;
     RECT  33.505 171.888 33.587 179.256 ;
     RECT  33.505 138.768 33.589 139.128 ;
     RECT  32.717 132.192 33.613 132.216 ;
     RECT  33.433 133.344 33.613 133.848 ;
     RECT  33.577 51.936 33.635 56.088 ;
     RECT  33.541 47.904 33.649 47.928 ;
     RECT  33.541 60.192 33.649 61.032 ;
     RECT  33.325 105.456 33.649 105.48 ;
     RECT  33.253 0.096 33.653 6.888 ;
     RECT  33.649 47.808 33.653 47.928 ;
     RECT  33.253 143.328 33.653 146.52 ;
     RECT  33.577 81.696 33.661 86.712 ;
     RECT  33.649 105.456 33.689 106.008 ;
     RECT  33.577 153.216 33.689 154.584 ;
     RECT  33.577 89.712 33.721 90.072 ;
     RECT  33.059 141.792 33.721 142.344 ;
     RECT  33.587 178.128 33.731 179.256 ;
     RECT  33.649 60.192 33.757 61.224 ;
     RECT  33.653 47.808 33.761 47.88 ;
     RECT  33.653 143.952 33.827 146.52 ;
     RECT  33.073 122.4 33.829 123.288 ;
     RECT  33.757 158.64 33.937 158.664 ;
     RECT  33.397 110.832 33.973 111.72 ;
     RECT  33.613 169.104 33.973 169.128 ;
     RECT  33.973 103.296 34.001 103.32 ;
     RECT  33.005 121.296 34.045 121.32 ;
     RECT  33.829 122.4 34.045 124.008 ;
     RECT  33.937 95.136 34.081 95.16 ;
     RECT  33.059 140.16 34.153 140.808 ;
     RECT  33.721 141.792 34.153 142.488 ;
     RECT  33.827 144.624 34.153 146.52 ;
     RECT  33.901 50.736 34.165 50.76 ;
     RECT  33.661 86.304 34.165 86.712 ;
     RECT  33.365 131.088 34.213 131.16 ;
     RECT  33.613 132.192 34.213 133.848 ;
     RECT  34.165 50.304 34.225 50.76 ;
     RECT  33.635 51.936 34.225 56.04 ;
     RECT  33.493 115.728 34.261 120.12 ;
     RECT  33.689 153.216 34.261 154.536 ;
     RECT  33.731 178.272 34.261 179.256 ;
     RECT  33.061 38.208 34.297 39.144 ;
     RECT  33.365 80.4 34.297 80.424 ;
     RECT  34.213 160.176 34.309 160.2 ;
     RECT  33.181 156.144 34.333 156.456 ;
     RECT  32.867 165.936 34.333 166.296 ;
     RECT  33.973 170.208 34.357 170.232 ;
     RECT  34.297 38.208 34.369 39.24 ;
     RECT  33.937 158.64 34.369 159.144 ;
     RECT  34.309 160.176 34.369 160.728 ;
     RECT  33.757 59.856 34.405 61.224 ;
     RECT  32.867 148.32 34.405 148.392 ;
     RECT  33.541 151.728 34.405 151.752 ;
     RECT  34.261 152.784 34.405 154.536 ;
     RECT  33.793 101.616 34.412 101.64 ;
     RECT  33.253 62.448 34.441 75.288 ;
     RECT  33.577 76.56 34.441 78.168 ;
     RECT  34.045 121.296 34.441 124.008 ;
     RECT  33.973 110.592 34.453 111.72 ;
     RECT  34.333 165.936 34.513 166.536 ;
     RECT  33.587 171.888 34.513 176.904 ;
     RECT  34.297 161.904 34.549 161.928 ;
     RECT  34.508 163.248 34.549 163.272 ;
     RECT  34.369 158.64 34.585 160.728 ;
     RECT  34.513 165.936 34.585 166.68 ;
     RECT  33.509 126 34.621 127.512 ;
     RECT  33.397 128.592 34.621 130.056 ;
     RECT  34.213 131.088 34.621 133.848 ;
     RECT  33.613 137.904 34.621 138.648 ;
     RECT  34.153 144.624 34.621 147.096 ;
     RECT  34.405 148.128 34.621 148.68 ;
     RECT  33.649 96.912 34.645 96.936 ;
     RECT  34.621 131.088 34.645 134.568 ;
     RECT  34.333 155.616 34.645 156.456 ;
     RECT  34.081 94.56 34.657 95.16 ;
     RECT  33.973 168.864 34.657 169.128 ;
     RECT  33.653 0.096 34.685 2.568 ;
     RECT  33.653 3.696 34.685 5.976 ;
     RECT  34.369 37.584 34.693 39.24 ;
     RECT  34.453 110.352 34.693 112.248 ;
     RECT  33.473 135.888 34.693 136.2 ;
     RECT  34.621 137.232 34.693 138.648 ;
     RECT  34.153 140.16 34.693 142.488 ;
     RECT  34.405 151.728 34.693 154.536 ;
     RECT  34.685 0.096 34.733 5.976 ;
     RECT  32.897 44.496 34.765 45.192 ;
     RECT  33.037 92.64 34.765 92.664 ;
     RECT  33.689 105.984 34.765 106.008 ;
     RECT  34.693 135.888 34.765 138.648 ;
     RECT  34.733 0.576 34.808 5.976 ;
     RECT  34.405 7.44 34.808 7.464 ;
     RECT  34.693 37.584 34.808 39.576 ;
     RECT  33.107 42.24 34.808 42.264 ;
     RECT  34.765 44.496 34.808 45.24 ;
     RECT  33.761 47.856 34.808 47.88 ;
     RECT  33.733 49.008 34.808 49.032 ;
     RECT  34.225 50.304 34.808 56.04 ;
     RECT  33.365 57.408 34.808 57.624 ;
     RECT  33.185 58.656 34.808 58.68 ;
     RECT  34.405 59.856 34.808 61.368 ;
     RECT  34.441 62.448 34.808 78.168 ;
     RECT  33.932 79.2 34.808 79.224 ;
     RECT  34.297 80.4 34.808 80.568 ;
     RECT  33.661 81.696 34.808 84.792 ;
     RECT  34.165 86.304 34.808 87.336 ;
     RECT  33.721 88.944 34.808 90.072 ;
     RECT  34.765 92.64 34.808 93 ;
     RECT  34.657 94.032 34.808 95.16 ;
     RECT  34.645 96.384 34.808 96.936 ;
     RECT  32.749 98.544 34.808 98.568 ;
     RECT  34.453 99.696 34.808 99.72 ;
     RECT  34.412 101.28 34.808 101.64 ;
     RECT  34.001 103.2 34.808 103.32 ;
     RECT  34.765 105.984 34.808 106.2 ;
     RECT  34.645 107.184 34.808 107.208 ;
     RECT  34.765 108.864 34.808 108.888 ;
     RECT  34.693 109.968 34.808 112.248 ;
     RECT  33.437 113.232 34.808 113.784 ;
     RECT  34.261 115.104 34.808 120.12 ;
     RECT  34.441 121.296 34.808 124.872 ;
     RECT  34.621 126 34.808 130.056 ;
     RECT  34.645 131.04 34.808 134.568 ;
     RECT  34.765 135.888 34.808 138.696 ;
     RECT  34.693 139.92 34.808 142.488 ;
     RECT  34.621 144.624 34.808 148.68 ;
     RECT  33.505 150.528 34.808 150.552 ;
     RECT  34.693 151.632 34.808 154.536 ;
     RECT  34.645 155.616 34.808 156.504 ;
     RECT  34.585 158.496 34.808 160.728 ;
     RECT  34.549 161.904 34.808 163.272 ;
     RECT  34.585 165.36 34.808 166.68 ;
     RECT  34.657 168.768 34.808 169.128 ;
     RECT  34.357 170.208 34.808 170.664 ;
     RECT  34.513 171.792 34.808 176.904 ;
     RECT  34.261 178.272 34.808 179.592 ;
     RECT  33.829 181.248 34.837 181.272 ;
     RECT  34.837 180.672 34.981 181.272 ;
     RECT  34.808 0.576 35.104 179.592 ;
     RECT  35.104 178.944 35.125 179.592 ;
     RECT  34.981 180.672 35.125 181.32 ;
     RECT  35.104 55.2 35.129 55.992 ;
     RECT  35.104 36.768 35.219 41.064 ;
     RECT  35.104 81.696 35.219 84.408 ;
     RECT  35.104 103.2 35.219 103.32 ;
     RECT  35.104 177.216 35.219 177.864 ;
     RECT  35.104 109.92 35.237 113.784 ;
     RECT  35.125 178.944 35.237 181.32 ;
     RECT  35.104 98.592 35.267 102.024 ;
     RECT  35.104 86.304 35.273 91.752 ;
     RECT  35.104 107.088 35.273 107.832 ;
     RECT  35.104 0.576 35.309 5.544 ;
     RECT  35.273 86.304 35.309 91.128 ;
     RECT  35.104 94.032 35.309 96.792 ;
     RECT  35.104 57.024 35.315 64.392 ;
     RECT  35.267 100.224 35.315 102.024 ;
     RECT  35.315 101.376 35.317 102.024 ;
     RECT  35.309 86.304 35.345 90.6 ;
     RECT  35.104 128.448 35.345 134.616 ;
     RECT  35.104 168.72 35.345 170.184 ;
     RECT  35.315 59.52 35.356 64.392 ;
     RECT  35.219 36.768 35.363 39.576 ;
     RECT  35.104 117.888 35.381 125.208 ;
     RECT  35.104 151.536 35.381 152.808 ;
     RECT  35.104 115.152 35.404 116.856 ;
     RECT  35.104 135.696 35.404 143.256 ;
     RECT  35.309 0.576 35.417 5.208 ;
     RECT  35.356 59.568 35.417 64.392 ;
     RECT  35.104 79.824 35.417 80.568 ;
     RECT  35.381 125.184 35.417 125.208 ;
     RECT  35.404 135.696 35.417 136.248 ;
     RECT  35.345 168.912 35.417 170.184 ;
     RECT  35.404 115.152 35.425 115.176 ;
     RECT  35.417 59.856 35.489 64.392 ;
     RECT  35.309 94.032 35.525 94.056 ;
     RECT  35.104 167.712 35.555 167.736 ;
     RECT  35.104 126.432 35.561 127.32 ;
     RECT  35.129 55.872 35.597 55.992 ;
     RECT  35.345 128.448 35.603 131.592 ;
     RECT  35.219 41.04 35.633 41.064 ;
     RECT  35.104 154.032 35.641 159.672 ;
     RECT  35.641 158.496 35.651 159.672 ;
     RECT  35.219 177.504 35.677 177.864 ;
     RECT  35.104 147.504 35.705 148.68 ;
     RECT  35.677 177.84 35.705 177.864 ;
     RECT  35.381 117.888 35.747 123.576 ;
     RECT  35.489 59.856 35.777 63.816 ;
     RECT  35.404 137.232 35.777 143.256 ;
     RECT  35.777 60.192 35.795 63.816 ;
     RECT  35.777 140.208 35.813 143.256 ;
     RECT  35.104 171.312 35.813 176.088 ;
     RECT  35.747 117.888 35.843 122.136 ;
     RECT  35.417 79.824 35.849 80.424 ;
     RECT  35.747 123.12 35.849 123.576 ;
     RECT  35.777 137.232 35.849 138.84 ;
     RECT  35.795 60.288 35.885 63.816 ;
     RECT  35.849 138 35.885 138.84 ;
     RECT  35.417 169.2 35.885 170.184 ;
     RECT  35.219 82.08 35.891 84.408 ;
     RECT  35.345 86.304 35.891 87.768 ;
     RECT  35.237 178.944 35.891 180.744 ;
     RECT  35.315 57.024 35.921 58.536 ;
     RECT  35.885 60.288 35.921 61.896 ;
     RECT  35.219 103.248 35.921 103.32 ;
     RECT  35.104 65.568 35.957 66.744 ;
     RECT  35.104 67.776 35.957 76.584 ;
     RECT  35.104 77.664 35.993 78.504 ;
     RECT  35.843 117.888 35.993 120.888 ;
     RECT  35.417 135.696 36.029 136.2 ;
     RECT  35.957 71.712 36.035 76.584 ;
     RECT  35.813 171.312 36.035 175.32 ;
     RECT  35.104 6.864 36.065 6.888 ;
     RECT  35.885 63.264 36.065 63.816 ;
     RECT  35.104 52.608 36.085 53.928 ;
     RECT  35.309 95.136 36.085 96.792 ;
     RECT  35.104 104.544 36.092 105.432 ;
     RECT  35.104 144.24 36.097 145.896 ;
     RECT  35.104 108.864 36.101 108.888 ;
     RECT  35.104 166.032 36.109 166.488 ;
     RECT  35.404 116.304 36.125 116.856 ;
     RECT  35.237 109.92 36.131 110.616 ;
     RECT  36.092 104.544 36.133 105.768 ;
     RECT  35.813 140.688 36.133 143.256 ;
     RECT  36.097 144.24 36.133 145.944 ;
     RECT  35.705 147.696 36.133 148.68 ;
     RECT  35.104 149.904 36.133 149.928 ;
     RECT  35.381 151.536 36.133 151.896 ;
     RECT  35.104 92.88 36.137 93 ;
     RECT  36.133 147.696 36.141 149.928 ;
     RECT  36.133 151.2 36.141 151.896 ;
     RECT  35.641 154.032 36.143 157.32 ;
     RECT  35.363 36.768 36.169 36.792 ;
     RECT  35.921 58.032 36.179 58.536 ;
     RECT  36.133 104.544 36.179 106.008 ;
     RECT  36.125 116.304 36.179 117.432 ;
     RECT  35.104 42.24 36.205 42.744 ;
     RECT  36.065 63.792 36.209 63.816 ;
     RECT  35.957 65.568 36.209 66.696 ;
     RECT  35.993 78.096 36.209 78.504 ;
     RECT  36.179 117.408 36.209 117.432 ;
     RECT  35.345 132.768 36.209 134.616 ;
     RECT  36.133 140.688 36.209 145.944 ;
     RECT  35.345 88.8 36.227 90.6 ;
     RECT  36.085 95.136 36.227 96.888 ;
     RECT  36.085 52.608 36.229 54.696 ;
     RECT  36.179 58.464 36.245 58.536 ;
     RECT  35.273 107.088 36.245 107.112 ;
     RECT  35.603 128.448 36.245 131.208 ;
     RECT  36.143 153.888 36.268 157.32 ;
     RECT  35.104 44.976 36.275 45.24 ;
     RECT  36.188 49.152 36.275 49.176 ;
     RECT  35.417 0.576 36.277 1.752 ;
     RECT  36.179 104.544 36.281 104.856 ;
     RECT  36.268 155.664 36.281 157.32 ;
     RECT  36.035 171.792 36.281 175.32 ;
     RECT  35.651 158.496 36.317 158.904 ;
     RECT  36.209 134.496 36.349 134.616 ;
     RECT  35.267 98.592 36.353 98.664 ;
     RECT  36.269 181.248 36.353 181.32 ;
     RECT  36.275 44.976 36.373 45.192 ;
     RECT  35.417 3.12 36.38 5.208 ;
     RECT  35.104 164.496 36.389 164.616 ;
     RECT  35.993 118.512 36.419 120.888 ;
     RECT  36.353 98.64 36.421 98.664 ;
     RECT  36.268 153.888 36.421 154.632 ;
     RECT  35.237 111.648 36.461 113.784 ;
     RECT  36.419 119.184 36.461 120.888 ;
     RECT  36.141 147.696 36.461 151.896 ;
     RECT  36.209 143.04 36.467 145.944 ;
     RECT  35.363 37.872 36.469 39.576 ;
     RECT  36.461 113.184 36.493 113.784 ;
     RECT  36.209 132.768 36.493 133.512 ;
     RECT  36.281 173.136 36.497 175.32 ;
     RECT  36.421 97.44 36.505 97.464 ;
     RECT  36.461 147.696 36.508 151.464 ;
     RECT  36.169 36.624 36.517 36.792 ;
     RECT  36.389 164.592 36.517 164.616 ;
     RECT  36.133 165.6 36.517 165.624 ;
     RECT  36.317 158.496 36.533 158.52 ;
     RECT  36.469 37.872 36.563 39.912 ;
     RECT  36.563 38.64 36.569 39.912 ;
     RECT  35.921 57.024 36.569 57.048 ;
     RECT  35.921 60.288 36.569 61.704 ;
     RECT  36.517 36.48 36.604 36.792 ;
     RECT  36.517 164.592 36.604 165.624 ;
     RECT  36.205 41.52 36.605 42.744 ;
     RECT  36.245 128.448 36.605 129.96 ;
     RECT  36.229 52.128 36.637 54.696 ;
     RECT  36.605 42.24 36.661 42.744 ;
     RECT  35.315 100.224 36.668 100.248 ;
     RECT  36.179 116.304 36.677 116.328 ;
     RECT  36.373 44.592 36.707 45.192 ;
     RECT  36.245 131.184 36.713 131.208 ;
     RECT  35.849 123.456 36.716 123.576 ;
     RECT  36.637 51.888 36.745 54.696 ;
     RECT  35.891 82.416 36.745 84.408 ;
     RECT  35.957 67.776 36.749 70.152 ;
     RECT  36.749 67.776 36.755 69.96 ;
     RECT  36.137 92.928 36.755 93 ;
     RECT  36.668 100.128 36.755 100.248 ;
     RECT  36.245 58.464 36.785 58.488 ;
     RECT  36.227 95.136 36.785 95.976 ;
     RECT  36.493 132.432 36.785 133.512 ;
     RECT  36.716 123.456 36.803 124.056 ;
     RECT  36.467 145.296 36.812 145.944 ;
     RECT  36.508 147.696 36.815 151.224 ;
     RECT  35.891 86.592 36.817 87.768 ;
     RECT  35.317 101.376 36.817 101.4 ;
     RECT  35.104 50.304 36.821 50.328 ;
     RECT  36.493 113.184 36.821 114.024 ;
     RECT  36.815 147.6 36.821 151.224 ;
     RECT  36.817 86.592 36.851 88.344 ;
     RECT  36.764 177.216 36.853 177.24 ;
     RECT  36.785 95.136 36.857 95.928 ;
     RECT  36.745 82.416 36.899 84.984 ;
     RECT  36.812 145.296 36.899 146.136 ;
     RECT  36.569 61.008 36.925 61.704 ;
     RECT  36.035 76.464 36.929 76.584 ;
     RECT  36.179 105.984 36.929 106.008 ;
     RECT  36.277 0.096 36.997 1.752 ;
     RECT  36.38 2.832 36.997 5.208 ;
     RECT  36.131 109.968 36.997 110.616 ;
     RECT  36.461 111.648 36.997 111.672 ;
     RECT  35.561 126.96 36.997 127.32 ;
     RECT  35.885 170.16 36.997 170.184 ;
     RECT  36.281 171.792 36.997 172.152 ;
     RECT  36.461 119.184 37.001 120.216 ;
     RECT  36.821 147.6 37.001 150.6 ;
     RECT  36.035 71.712 37.033 75.288 ;
     RECT  35.597 55.872 37.037 55.896 ;
     RECT  36.997 109.968 37.037 111.672 ;
     RECT  36.853 177.216 37.037 177.336 ;
     RECT  36.899 84.96 37.045 84.984 ;
     RECT  36.569 38.64 37.073 39.24 ;
     RECT  37.045 84.96 37.091 86.232 ;
     RECT  35.891 178.944 37.109 180.12 ;
     RECT  36.604 165.6 37.139 165.624 ;
     RECT  36.353 181.248 37.141 181.272 ;
     RECT  36.209 66 37.145 66.696 ;
     RECT  36.997 0.096 37.177 5.208 ;
     RECT  36.803 123.456 37.177 123.576 ;
     RECT  36.997 126.96 37.177 127.368 ;
     RECT  36.899 145.296 37.181 145.944 ;
     RECT  37.177 126.192 37.196 127.368 ;
     RECT  36.605 128.448 37.196 129.816 ;
     RECT  36.821 113.76 37.217 114.024 ;
     RECT  36.421 98.64 37.253 99.048 ;
     RECT  36.709 103.728 37.253 103.752 ;
     RECT  37.177 122.496 37.261 123.576 ;
     RECT  36.637 125.088 37.283 125.112 ;
     RECT  37.196 126.192 37.283 129.816 ;
     RECT  36.901 40.896 37.285 40.92 ;
     RECT  36.785 132.432 37.285 133.08 ;
     RECT  36.997 170.16 37.321 172.152 ;
     RECT  36.497 173.136 37.321 174.744 ;
     RECT  37.283 127.296 37.325 127.368 ;
     RECT  37.261 123.12 37.331 123.576 ;
     RECT  37.34 58.56 37.381 58.584 ;
     RECT  36.857 95.136 37.381 95.736 ;
     RECT  37.381 58.56 37.427 59.496 ;
     RECT  37.141 180.672 37.429 181.272 ;
     RECT  37.091 85.632 37.433 86.232 ;
     RECT  36.851 87.216 37.433 88.344 ;
     RECT  37.429 180.672 37.469 181.32 ;
     RECT  37.357 93.12 37.477 93.144 ;
     RECT  37.381 94.32 37.477 95.736 ;
     RECT  37.177 0.096 37.505 5.256 ;
     RECT  36.349 134.496 37.537 135.432 ;
     RECT  37.213 136.752 37.537 136.776 ;
     RECT  36.421 153.84 37.537 154.632 ;
     RECT  37.037 109.968 37.573 111.576 ;
     RECT  37.073 38.64 37.577 38.808 ;
     RECT  37.217 114 37.577 114.024 ;
     RECT  37.001 149.328 37.577 150.6 ;
     RECT  36.421 161.328 37.577 161.352 ;
     RECT  37.469 181.296 37.613 181.32 ;
     RECT  36.281 156.48 37.621 157.32 ;
     RECT  36.899 82.416 37.628 83.88 ;
     RECT  37.145 66.24 37.649 66.696 ;
     RECT  36.817 100.848 37.649 101.4 ;
     RECT  35.849 79.824 37.669 79.848 ;
     RECT  37.621 117.36 37.669 117.384 ;
     RECT  37.621 156.48 37.669 158.28 ;
     RECT  36.925 61.008 37.681 61.752 ;
     RECT  37.321 170.16 37.681 174.744 ;
     RECT  37.669 79.824 37.715 80.376 ;
     RECT  37.429 6.864 37.717 6.888 ;
     RECT  36.745 51.312 37.717 54.696 ;
     RECT  36.227 89.52 37.717 90.6 ;
     RECT  36.467 143.04 37.717 144.264 ;
     RECT  37.181 145.296 37.717 145.896 ;
     RECT  36.604 36.624 37.721 36.792 ;
     RECT  37.001 147.6 37.757 148.344 ;
     RECT  37.577 150.288 37.757 150.6 ;
     RECT  37.285 132.24 37.763 133.08 ;
     RECT  37.537 153.744 37.765 154.632 ;
     RECT  36.707 44.592 37.789 45 ;
     RECT  37.717 51.168 37.789 54.696 ;
     RECT  37.763 132.24 37.793 132.456 ;
     RECT  37.717 143.04 37.793 145.896 ;
     RECT  37.109 178.944 37.793 179.592 ;
     RECT  37.717 89.52 37.804 90.936 ;
     RECT  37.717 92.016 37.804 92.04 ;
     RECT  37.033 71.712 37.825 75.432 ;
     RECT  37.793 178.944 37.861 179.544 ;
     RECT  36.281 104.832 37.865 104.856 ;
     RECT  37.285 40.32 37.897 40.92 ;
     RECT  37.477 93.12 37.897 95.736 ;
     RECT  36.241 34.8 37.901 34.824 ;
     RECT  37.649 101.376 37.901 101.4 ;
     RECT  37.331 123.12 37.901 123.144 ;
     RECT  37.283 128.832 37.909 129.816 ;
     RECT  36.755 67.776 37.955 69.816 ;
     RECT  37.757 150.432 37.964 150.6 ;
     RECT  37.715 80.352 37.969 80.376 ;
     RECT  37.628 81.6 37.969 83.88 ;
     RECT  36.209 140.688 37.969 141.816 ;
     RECT  37.765 153.744 37.969 154.824 ;
     RECT  37.681 170.16 37.969 174.984 ;
     RECT  37.717 6.864 38.005 7.464 ;
     RECT  36.661 42.24 38.005 43.32 ;
     RECT  36.604 164.592 38.005 164.616 ;
     RECT  38.005 6.288 38.009 7.464 ;
     RECT  37.897 40.32 38.012 41.208 ;
     RECT  37.721 36.768 38.041 36.792 ;
     RECT  38.012 40.32 38.041 41.256 ;
     RECT  38.005 42.24 38.041 43.416 ;
     RECT  37.789 50.736 38.041 54.696 ;
     RECT  37.897 93.024 38.041 95.736 ;
     RECT  37.253 98.64 38.041 98.664 ;
     RECT  37.789 44.448 38.051 45 ;
     RECT  37.325 127.296 38.051 127.32 ;
     RECT  38.041 40.32 38.053 43.416 ;
     RECT  37.577 38.784 38.077 38.808 ;
     RECT  38.053 39.888 38.077 43.416 ;
     RECT  37.969 169.776 38.077 174.984 ;
     RECT  37.969 139.92 38.081 141.816 ;
     RECT  38.077 38.784 38.092 43.416 ;
     RECT  38.092 38.784 38.125 43.32 ;
     RECT  36.997 159.6 38.147 159.624 ;
     RECT  37.321 49.584 38.149 49.608 ;
     RECT  38.041 50.736 38.149 54.744 ;
     RECT  36.457 102.576 38.149 102.6 ;
     RECT  37.537 134.496 38.149 136.776 ;
     RECT  37.427 59.328 38.185 59.496 ;
     RECT  37.969 153.744 38.185 155.016 ;
     RECT  38.149 49.584 38.195 54.744 ;
     RECT  38.149 133.584 38.197 136.776 ;
     RECT  37.933 138.432 38.197 138.456 ;
     RECT  37.609 176.496 38.197 176.712 ;
     RECT  38.009 6.288 38.225 6.312 ;
     RECT  38.005 164.592 38.225 165.336 ;
     RECT  37.793 143.04 38.243 145.656 ;
     RECT  38.197 176.496 38.252 177.288 ;
     RECT  37.861 178.368 38.252 179.544 ;
     RECT  38.077 114.288 38.261 114.312 ;
     RECT  37.753 64.944 38.293 64.968 ;
     RECT  37.681 60.768 38.297 61.752 ;
     RECT  38.081 140.208 38.333 141.816 ;
     RECT  38.243 145.296 38.333 145.656 ;
     RECT  38.252 176.496 38.339 179.544 ;
     RECT  37.825 71.616 38.341 75.432 ;
     RECT  36.929 76.56 38.341 76.584 ;
     RECT  37.433 88.32 38.365 88.344 ;
     RECT  37.804 89.52 38.365 90.6 ;
     RECT  37.964 150.432 38.365 151.032 ;
     RECT  38.185 153.648 38.365 155.016 ;
     RECT  37.969 80.352 38.435 83.88 ;
     RECT  38.195 50.544 38.437 54.744 ;
     RECT  37.069 63.024 38.437 63.048 ;
     RECT  38.341 76.56 38.437 77.16 ;
     RECT  36.373 78.576 38.437 78.6 ;
     RECT  37.897 96.864 38.437 96.888 ;
     RECT  37.573 109.44 38.437 111.576 ;
     RECT  38.365 153.552 38.437 155.016 ;
     RECT  37.669 156.48 38.437 158.568 ;
     RECT  38.437 50.544 38.441 54.84 ;
     RECT  38.197 133.584 38.441 138.456 ;
     RECT  37.505 0.528 38.483 5.256 ;
     RECT  38.293 64.944 38.483 65.256 ;
     RECT  37.001 119.952 38.485 120.216 ;
     RECT  38.389 121.344 38.485 121.368 ;
     RECT  38.437 76.56 38.509 78.6 ;
     RECT  38.225 164.592 38.509 164.616 ;
     RECT  38.437 62.64 38.524 63.048 ;
     RECT  37.433 86.208 38.533 86.232 ;
     RECT  37.861 125.616 38.533 125.688 ;
     RECT  38.509 164.496 38.549 164.616 ;
     RECT  38.185 59.328 38.581 59.736 ;
     RECT  38.297 60.768 38.581 61.032 ;
     RECT  38.041 36.768 38.617 37.608 ;
     RECT  38.125 38.784 38.617 43.176 ;
     RECT  38.473 46.128 38.617 46.152 ;
     RECT  38.329 47.184 38.617 47.208 ;
     RECT  38.041 98.016 38.617 98.664 ;
     RECT  38.437 109.44 38.617 112.296 ;
     RECT  38.581 59.328 38.621 61.032 ;
     RECT  38.617 36.768 38.627 43.176 ;
     RECT  38.333 141.168 38.629 141.816 ;
     RECT  38.243 143.04 38.629 143.88 ;
     RECT  38.617 98.016 38.657 99.192 ;
     RECT  38.333 145.344 38.657 145.656 ;
     RECT  38.485 119.952 38.677 121.368 ;
     RECT  38.339 176.496 38.693 177.288 ;
     RECT  38.617 109.44 38.7 112.872 ;
     RECT  38.435 80.352 38.716 83.736 ;
     RECT  38.437 152.784 38.723 158.568 ;
     RECT  37.213 56.88 38.725 56.904 ;
     RECT  38.509 76.56 38.725 78.648 ;
     RECT  38.533 85.584 38.725 86.232 ;
     RECT  37.433 87.216 38.725 87.24 ;
     RECT  38.149 102.144 38.761 102.6 ;
     RECT  38.725 56.544 38.765 56.904 ;
     RECT  38.629 141.168 38.765 143.88 ;
     RECT  38.524 62.64 38.771 63 ;
     RECT  38.7 109.44 38.771 112.92 ;
     RECT  38.765 141.168 38.771 142.536 ;
     RECT  38.725 76.56 38.797 79.08 ;
     RECT  38.716 80.352 38.797 83.64 ;
     RECT  38.437 96.816 38.797 96.888 ;
     RECT  38.657 98.016 38.797 98.136 ;
     RECT  38.657 145.632 38.797 145.656 ;
     RECT  36.997 167.52 38.797 167.544 ;
     RECT  38.009 7.44 38.801 7.464 ;
     RECT  38.041 92.736 38.801 95.736 ;
     RECT  38.771 109.44 38.801 111.576 ;
     RECT  38.483 65.232 38.821 65.256 ;
     RECT  37.649 66.24 38.821 66.648 ;
     RECT  38.797 138.48 38.821 138.504 ;
     RECT  38.761 104.304 38.845 104.328 ;
     RECT  38.821 65.232 38.867 66.648 ;
     RECT  38.657 99.168 38.869 99.192 ;
     RECT  38.365 150.432 38.869 151.608 ;
     RECT  38.483 0.576 38.873 5.256 ;
     RECT  38.761 102.144 38.873 102.648 ;
     RECT  38.693 176.496 38.873 177.192 ;
     RECT  38.365 88.32 38.876 90.6 ;
     RECT  38.869 150.432 38.905 152.376 ;
     RECT  38.821 138.48 38.909 138.648 ;
     RECT  37.669 117.36 38.917 117.816 ;
     RECT  38.677 119.04 38.917 121.368 ;
     RECT  38.441 133.584 38.917 137.256 ;
     RECT  37.757 147.888 38.917 148.344 ;
     RECT  38.077 169.776 38.941 175.32 ;
     RECT  38.801 95.712 38.953 95.736 ;
     RECT  38.876 88.32 38.963 91.032 ;
     RECT  38.797 145.632 38.981 145.944 ;
     RECT  38.869 99.168 39.011 99.288 ;
     RECT  38.581 124.56 39.013 124.584 ;
     RECT  38.533 125.616 39.013 126.456 ;
     RECT  37.909 128.832 39.013 130.248 ;
     RECT  38.627 36.768 39.049 42.888 ;
     RECT  38.341 70.704 39.049 75.432 ;
     RECT  38.797 76.56 39.049 83.64 ;
     RECT  38.549 164.496 39.049 164.52 ;
     RECT  38.771 141.168 39.059 142.344 ;
     RECT  38.101 161.904 39.085 161.928 ;
     RECT  39.049 36.624 39.089 42.888 ;
     RECT  39.059 141.168 39.089 142.248 ;
     RECT  39.049 163.584 39.133 164.52 ;
     RECT  38.917 133.488 39.155 137.256 ;
     RECT  39.089 36.624 39.157 37.224 ;
     RECT  39.013 124.56 39.157 126.456 ;
     RECT  38.773 105.456 39.161 105.48 ;
     RECT  38.917 117.36 39.197 121.368 ;
     RECT  38.909 138.528 39.203 138.648 ;
     RECT  38.801 92.736 39.229 94.68 ;
     RECT  38.941 169.68 39.253 175.32 ;
     RECT  38.797 96.816 39.265 98.136 ;
     RECT  38.963 88.32 39.301 90.84 ;
     RECT  38.725 85.584 39.329 87.24 ;
     RECT  39.301 88.224 39.329 90.84 ;
     RECT  39.155 133.488 39.337 136.008 ;
     RECT  39.049 70.704 39.349 83.64 ;
     RECT  38.765 143.664 39.349 143.88 ;
     RECT  39.253 169.344 39.373 175.32 ;
     RECT  38.797 167.52 39.409 167.784 ;
     RECT  39.157 6.864 39.445 6.888 ;
     RECT  38.051 44.448 39.445 44.904 ;
     RECT  38.867 65.52 39.445 66.648 ;
     RECT  37.955 67.776 39.445 69.288 ;
     RECT  39.329 85.584 39.445 90.84 ;
     RECT  38.873 102.144 39.445 102.168 ;
     RECT  38.821 115.104 39.445 115.128 ;
     RECT  39.089 141.168 39.445 141.912 ;
     RECT  38.873 0.576 39.517 1.272 ;
     RECT  35.104 31.392 39.541 31.416 ;
     RECT  39.445 108.288 39.541 108.312 ;
     RECT  38.981 145.92 39.548 145.944 ;
     RECT  38.917 147.888 39.553 148.44 ;
     RECT  39.517 100.896 39.589 100.92 ;
     RECT  39.445 102 39.589 102.168 ;
     RECT  38.617 46.128 39.596 47.208 ;
     RECT  39.013 128.832 39.625 130.584 ;
     RECT  38.339 178.992 39.637 179.544 ;
     RECT  39.373 169.344 39.661 175.608 ;
     RECT  38.905 150.384 39.685 152.376 ;
     RECT  38.873 177.168 39.685 177.192 ;
     RECT  39.637 58.656 39.692 58.68 ;
     RECT  39.685 177.168 39.692 177.288 ;
     RECT  39.637 178.992 39.692 179.448 ;
     RECT  38.441 50.736 39.697 54.84 ;
     RECT  38.765 56.544 39.697 56.76 ;
     RECT  39.229 91.968 39.829 94.68 ;
     RECT  39.157 124.272 39.829 126.456 ;
     RECT  39.409 167.52 39.829 168.072 ;
     RECT  39.517 0.528 39.877 1.272 ;
     RECT  39.265 96 39.877 98.136 ;
     RECT  39.589 100.896 39.877 102.168 ;
     RECT  39.445 103.728 39.877 103.752 ;
     RECT  39.829 124.08 39.877 126.456 ;
     RECT  39.085 161.76 39.877 161.928 ;
     RECT  39.692 177.168 39.877 179.448 ;
     RECT  39.301 181.296 39.877 181.32 ;
     RECT  38.873 2.4 39.884 5.256 ;
     RECT  39.445 6.24 39.884 6.888 ;
     RECT  39.877 123.504 39.925 126.456 ;
     RECT  39.625 127.872 39.925 130.584 ;
     RECT  39.877 180.72 39.964 181.32 ;
     RECT  39.877 160.752 39.973 160.776 ;
     RECT  39.133 164.064 39.985 164.52 ;
     RECT  39.877 0.096 39.989 1.272 ;
     RECT  39.989 0.576 40.021 1.272 ;
     RECT  39.884 2.4 40.021 6.888 ;
     RECT  38.771 62.784 40.021 63 ;
     RECT  39.829 64.176 40.021 64.2 ;
     RECT  39.661 169.2 40.021 175.608 ;
     RECT  39.964 180.72 40.067 181.272 ;
     RECT  39.829 91.968 40.129 94.968 ;
     RECT  39.877 96 40.129 98.616 ;
     RECT  40.021 0.576 40.208 6.888 ;
     RECT  39.985 21.12 40.208 21.144 ;
     RECT  39.541 31.392 40.208 31.8 ;
     RECT  40.069 34.368 40.208 35.256 ;
     RECT  39.157 36.528 40.208 37.224 ;
     RECT  39.089 38.256 40.208 42.888 ;
     RECT  39.445 44.16 40.208 44.904 ;
     RECT  39.596 46.128 40.208 47.88 ;
     RECT  39.697 50.736 40.208 55.512 ;
     RECT  39.697 56.496 40.208 56.76 ;
     RECT  39.692 58.368 40.208 58.68 ;
     RECT  38.621 59.712 40.208 60.552 ;
     RECT  40.021 62.784 40.208 64.2 ;
     RECT  39.445 65.52 40.208 69.288 ;
     RECT  39.349 70.416 40.208 83.64 ;
     RECT  39.445 85.2 40.208 90.84 ;
     RECT  40.129 91.968 40.208 98.616 ;
     RECT  39.877 100.896 40.208 103.752 ;
     RECT  39.913 104.88 40.208 104.904 ;
     RECT  39.877 105.936 40.208 105.96 ;
     RECT  39.541 108.192 40.208 108.312 ;
     RECT  38.801 109.44 40.208 111.432 ;
     RECT  38.771 112.896 40.208 112.92 ;
     RECT  39.445 114.528 40.208 115.128 ;
     RECT  39.197 117.36 40.208 119.112 ;
     RECT  39.197 120.816 40.208 121.368 ;
     RECT  39.925 123.504 40.208 130.584 ;
     RECT  37.793 132.24 40.208 132.264 ;
     RECT  39.337 133.392 40.208 136.008 ;
     RECT  39.155 137.232 40.208 137.256 ;
     RECT  39.337 139.152 40.208 139.176 ;
     RECT  39.445 140.208 40.208 141.912 ;
     RECT  39.349 143.664 40.208 144.552 ;
     RECT  39.548 145.92 40.208 146.664 ;
     RECT  39.553 147.744 40.208 148.44 ;
     RECT  39.685 149.856 40.208 152.376 ;
     RECT  38.723 153.456 40.208 158.568 ;
     RECT  39.973 160.704 40.208 160.776 ;
     RECT  39.877 161.76 40.208 162.504 ;
     RECT  39.985 164.064 40.208 165.384 ;
     RECT  39.877 166.416 40.208 166.44 ;
     RECT  39.829 167.52 40.208 168.12 ;
     RECT  40.021 169.2 40.208 175.848 ;
     RECT  39.877 177.024 40.208 179.448 ;
     RECT  40.208 0.576 40.504 179.448 ;
     RECT  40.504 81.072 40.529 81.624 ;
     RECT  40.504 140.016 40.565 141.912 ;
     RECT  40.504 36.624 40.601 36.648 ;
     RECT  40.529 81.6 40.637 81.624 ;
     RECT  40.504 63.264 40.643 64.2 ;
     RECT  40.504 108.864 40.643 112.872 ;
     RECT  40.504 166.464 40.673 179.448 ;
     RECT  40.504 102.624 40.691 103.992 ;
     RECT  40.504 114 40.691 114.12 ;
     RECT  40.504 50.736 40.709 54.168 ;
     RECT  40.504 116.736 40.709 119.112 ;
     RECT  40.067 181.248 40.709 181.272 ;
     RECT  40.504 98.496 40.739 98.616 ;
     RECT  40.643 111.024 40.739 112.872 ;
     RECT  40.504 133.392 40.739 133.416 ;
     RECT  40.504 149.904 40.745 150.456 ;
     RECT  40.504 58.704 40.753 59.304 ;
     RECT  40.709 50.832 40.787 54.168 ;
     RECT  40.504 105.456 40.787 105.96 ;
     RECT  40.643 108.864 40.787 110.04 ;
     RECT  40.504 70.56 40.817 70.728 ;
     RECT  40.504 121.152 40.817 121.992 ;
     RECT  40.504 123.504 40.817 125.688 ;
     RECT  40.504 78.096 40.825 78.648 ;
     RECT  40.504 127.056 40.828 131.64 ;
     RECT  40.739 98.592 40.883 98.616 ;
     RECT  40.504 66.24 40.889 66.744 ;
     RECT  40.504 84.384 40.889 90.024 ;
     RECT  40.673 168.192 40.889 179.448 ;
     RECT  40.889 66.672 40.925 66.744 ;
     RECT  40.504 68.208 40.925 69.576 ;
     RECT  40.889 85.2 40.925 90.024 ;
     RECT  40.504 55.296 40.931 55.848 ;
     RECT  40.817 121.392 40.933 121.992 ;
     RECT  40.889 177.792 40.933 179.448 ;
     RECT  40.933 177.84 40.957 179.448 ;
     RECT  40.931 55.488 40.961 55.848 ;
     RECT  40.753 58.704 40.961 58.728 ;
     RECT  40.709 118.512 40.979 119.112 ;
     RECT  40.565 140.016 40.979 141.384 ;
     RECT  40.745 149.904 40.997 149.928 ;
     RECT  40.957 177.84 41.027 180.12 ;
     RECT  40.925 66.72 41.033 66.744 ;
     RECT  40.825 78.624 41.033 78.648 ;
     RECT  40.925 85.344 41.033 90.024 ;
     RECT  40.787 110.016 41.033 110.04 ;
     RECT  40.817 123.504 41.033 124.824 ;
     RECT  40.504 148.416 41.033 148.44 ;
     RECT  41.027 177.84 41.033 177.864 ;
     RECT  40.504 0.576 41.069 7.464 ;
     RECT  40.961 55.488 41.069 55.56 ;
     RECT  40.504 164.208 41.069 165.432 ;
     RECT  40.979 141.312 41.075 141.384 ;
     RECT  41.069 55.488 41.123 55.512 ;
     RECT  41.069 0.576 41.173 6.888 ;
     RECT  41.075 141.312 41.219 141.336 ;
     RECT  40.691 114 41.315 114.024 ;
     RECT  40.979 119.088 41.315 119.112 ;
     RECT  40.787 105.456 41.363 105.48 ;
     RECT  40.739 111.408 41.363 112.872 ;
     RECT  40.691 102.624 41.411 102.648 ;
     RECT  41.069 165.36 41.429 165.432 ;
     RECT  40.504 72 41.459 75.912 ;
     RECT  41.363 111.408 41.459 111.72 ;
     RECT  41.033 123.504 41.459 124.248 ;
     RECT  41.173 0.096 41.465 6.888 ;
     RECT  41.459 72 41.507 75.816 ;
     RECT  40.504 134.496 41.509 136.008 ;
     RECT  40.504 160.704 41.509 161.352 ;
     RECT  40.504 162.384 41.509 162.408 ;
     RECT  40.504 21.12 41.533 21.144 ;
     RECT  40.673 166.464 41.533 167.208 ;
     RECT  41.027 179.52 41.533 180.12 ;
     RECT  41.509 160.704 41.557 162.408 ;
     RECT  40.504 39.984 41.569 47.88 ;
     RECT  40.828 127.056 41.603 131.448 ;
     RECT  41.603 127.056 41.605 130.872 ;
     RECT  41.465 0.096 41.609 6.264 ;
     RECT  40.504 61.584 41.651 61.608 ;
     RECT  40.504 100.896 41.651 100.92 ;
     RECT  41.533 179.52 41.651 180.168 ;
     RECT  41.569 39.984 41.677 48.12 ;
     RECT  41.609 0.576 41.681 6.264 ;
     RECT  40.504 137.232 41.795 137.256 ;
     RECT  41.507 72 41.843 72.84 ;
     RECT  40.504 38.688 41.845 39 ;
     RECT  41.677 39.984 41.845 48.408 ;
     RECT  41.069 164.208 41.857 164.376 ;
     RECT  40.643 63.264 41.861 63.288 ;
     RECT  40.787 108.864 41.891 108.888 ;
     RECT  41.459 111.696 41.891 111.72 ;
     RECT  41.845 38.688 41.893 48.408 ;
     RECT  41.509 134.496 41.929 136.056 ;
     RECT  40.925 68.208 41.939 69.288 ;
     RECT  40.504 96.864 41.939 96.888 ;
     RECT  41.939 68.736 41.987 69.288 ;
     RECT  40.933 121.392 41.987 121.416 ;
     RECT  41.533 166.368 41.989 167.208 ;
     RECT  40.889 168.192 41.989 176.76 ;
     RECT  41.929 134.4 42.001 136.056 ;
     RECT  41.507 74.4 42.035 74.952 ;
     RECT  41.989 166.368 42.037 176.76 ;
     RECT  42.001 134.304 42.073 136.056 ;
     RECT  41.843 72 42.083 72.36 ;
     RECT  40.709 116.736 42.083 117.432 ;
     RECT  42.037 166.368 42.101 177.096 ;
     RECT  41.749 181.296 42.109 181.32 ;
     RECT  41.651 179.52 42.133 179.544 ;
     RECT  42.073 134.304 42.145 136.728 ;
     RECT  42.145 134.208 42.181 136.728 ;
     RECT  42.101 166.368 42.217 177.24 ;
     RECT  41.429 165.36 42.221 165.384 ;
     RECT  42.109 180.72 42.227 181.32 ;
     RECT  40.504 153.456 42.229 158.616 ;
     RECT  41.557 160.704 42.229 162.504 ;
     RECT  41.857 163.536 42.229 164.376 ;
     RECT  42.229 153.456 42.316 158.856 ;
     RECT  42.316 153.456 42.401 158.616 ;
     RECT  41.605 127.008 42.421 130.872 ;
     RECT  42.397 35.904 42.481 35.928 ;
     RECT  42.217 166.368 42.505 178.008 ;
     RECT  42.133 178.992 42.505 179.544 ;
     RECT  41.893 38.688 42.517 48.6 ;
     RECT  42.229 160.704 42.565 164.376 ;
     RECT  42.541 27.36 42.572 27.384 ;
     RECT  41.681 0.576 42.613 1.272 ;
     RECT  42.421 126.72 42.649 130.872 ;
     RECT  42.572 26.88 42.659 27.384 ;
     RECT  42.565 160.176 42.685 164.376 ;
     RECT  41.533 21.12 42.709 21.192 ;
     RECT  42.181 133.92 42.721 136.728 ;
     RECT  42.227 181.296 42.725 181.32 ;
     RECT  42.709 20.304 42.755 21.192 ;
     RECT  40.504 34.368 42.757 34.392 ;
     RECT  40.504 92.544 42.757 95.256 ;
     RECT  42.757 34.272 42.793 34.392 ;
     RECT  41.681 2.256 42.797 6.264 ;
     RECT  42.517 38.16 42.829 48.6 ;
     RECT  42.505 166.368 42.853 179.544 ;
     RECT  42.793 34.272 42.865 34.44 ;
     RECT  42.685 160.176 42.941 165.336 ;
     RECT  42.649 126.72 42.997 131.112 ;
     RECT  41.749 31.2 43.045 31.224 ;
     RECT  42.685 36.192 43.117 36.408 ;
     RECT  42.829 37.68 43.2 48.6 ;
     RECT  40.787 51.168 43.2 54.072 ;
     RECT  41.033 85.344 43.2 89.976 ;
     RECT  42.757 92.544 43.2 95.448 ;
     RECT  42.997 126.48 43.2 131.112 ;
     RECT  42.721 133.824 43.2 136.728 ;
     RECT  42.941 160.656 43.229 165.336 ;
     RECT  43.229 160.656 43.235 161.304 ;
     RECT  43.117 36.192 43.237 36.552 ;
     RECT  43.2 37.68 43.237 54.072 ;
     RECT  43.237 36.192 43.272 54.072 ;
     RECT  41.987 68.736 43.272 68.76 ;
     RECT  42.083 72 43.272 72.024 ;
     RECT  42.035 74.928 43.272 74.952 ;
     RECT  43.2 85.344 43.272 95.448 ;
     RECT  40.691 103.968 43.272 103.992 ;
     RECT  41.363 112.848 43.272 112.872 ;
     RECT  40.504 115.68 43.272 115.704 ;
     RECT  42.083 116.736 43.272 116.76 ;
     RECT  41.459 123.504 43.272 123.528 ;
     RECT  43.2 126.48 43.272 136.728 ;
     RECT  42.401 153.456 43.272 158.568 ;
     RECT  43.235 161.28 43.283 161.304 ;
     RECT  43.272 36.192 43.337 158.568 ;
     RECT  42.613 0.096 43.481 1.272 ;
     RECT  42.865 34.272 43.573 34.536 ;
     RECT  43.337 36.192 43.573 37.464 ;
     RECT  43.477 7.44 43.621 7.464 ;
     RECT  42.659 27.36 43.657 27.384 ;
     RECT  43.573 34.08 43.66 37.464 ;
     RECT  43.481 0.096 43.661 1.224 ;
     RECT  43.657 27.36 43.697 27.912 ;
     RECT  42.797 2.256 43.733 5.736 ;
     RECT  42.853 166.32 43.765 179.544 ;
     RECT  43.229 162.384 43.845 165.336 ;
     RECT  43.765 166.32 43.845 180.12 ;
     RECT  43.045 31.2 43.945 31.32 ;
     RECT  43.845 162.384 43.949 180.12 ;
     RECT  43.945 30.864 43.985 31.32 ;
     RECT  43.66 36.192 44.021 37.464 ;
     RECT  43.949 162.384 44.021 179.544 ;
     RECT  43.621 6.864 44.093 7.464 ;
     RECT  43.585 33.024 44.125 33.048 ;
     RECT  44.021 36.192 44.129 36.84 ;
     RECT  42.709 29.616 44.149 29.64 ;
     RECT  44.125 32.544 44.161 33.048 ;
     RECT  42.755 20.304 44.195 21.144 ;
     RECT  44.149 29.232 44.195 29.64 ;
     RECT  43.733 2.352 44.197 5.736 ;
     RECT  44.021 162.384 44.237 178.44 ;
     RECT  43.66 34.08 44.273 34.776 ;
     RECT  44.189 181.296 44.273 181.32 ;
     RECT  44.273 34.272 44.309 34.776 ;
     RECT  44.237 163.008 44.339 178.44 ;
     RECT  44.333 161.904 44.417 161.928 ;
     RECT  44.093 6.864 44.489 7.128 ;
     RECT  44.161 32.544 44.489 33.096 ;
     RECT  44.129 36.816 44.489 36.84 ;
     RECT  44.339 163.584 44.525 178.44 ;
     RECT  44.021 179.52 44.917 179.544 ;
     RECT  43.337 38.448 44.965 158.568 ;
     RECT  44.965 38.448 44.989 159.384 ;
     RECT  44.485 181.248 45.011 181.272 ;
     RECT  44.917 179.52 45.101 180.12 ;
     RECT  44.525 165.264 45.349 178.44 ;
     RECT  45.101 179.52 45.349 179.544 ;
     RECT  44.195 29.232 45.493 29.256 ;
     RECT  43.985 30.864 45.493 30.888 ;
     RECT  44.197 2.352 45.608 5.784 ;
     RECT  44.489 7.104 45.608 7.128 ;
     RECT  44.195 20.304 45.608 20.328 ;
     RECT  43.697 27.888 45.608 27.912 ;
     RECT  45.493 29.04 45.608 30.888 ;
     RECT  44.489 32.544 45.608 32.568 ;
     RECT  44.309 34.752 45.608 34.776 ;
     RECT  44.989 37.584 45.608 159.384 ;
     RECT  44.525 163.584 45.608 164.136 ;
     RECT  45.349 165.264 45.608 179.544 ;
     RECT  45.608 2.148 45.904 179.544 ;
     RECT  45.904 169.824 45.965 176.712 ;
     RECT  45.904 27.36 46.019 32.664 ;
     RECT  45.904 34.08 46.019 34.2 ;
     RECT  46.019 31.44 46.06 32.664 ;
     RECT  45.965 172.704 46.067 176.712 ;
     RECT  46.06 31.44 46.073 31.704 ;
     RECT  46.067 173.856 46.163 176.712 ;
     RECT  43.661 0.096 46.177 1.176 ;
     RECT  45.904 2.148 46.177 6.888 ;
     RECT  45.904 165.84 46.189 166.44 ;
     RECT  45.904 179.52 46.217 179.544 ;
     RECT  45.904 177.84 46.253 178.44 ;
     RECT  46.067 172.704 46.307 172.872 ;
     RECT  45.904 168.096 46.325 168.552 ;
     RECT  45.965 169.824 46.333 171.624 ;
     RECT  46.333 170.448 46.355 171.624 ;
     RECT  46.163 176.688 46.405 176.712 ;
     RECT  46.019 27.36 46.451 30.456 ;
     RECT  46.355 171.6 46.451 171.624 ;
     RECT  46.307 172.752 46.461 172.872 ;
     RECT  46.163 173.856 46.469 175.08 ;
     RECT  46.461 172.752 46.505 172.776 ;
     RECT  46.253 177.984 46.577 178.44 ;
     RECT  45.904 25.584 46.649 26.136 ;
     RECT  45.904 19.92 46.691 21.72 ;
     RECT  45.904 23.904 46.691 24.552 ;
     RECT  45.904 38.448 46.757 159.384 ;
     RECT  45.904 22.752 46.787 22.776 ;
     RECT  45.904 35.424 46.787 35.544 ;
     RECT  46.177 0.096 46.793 6.888 ;
     RECT  46.451 27.84 46.793 30.456 ;
     RECT  46.189 165.84 46.933 166.392 ;
     RECT  46.933 165.312 46.973 166.392 ;
     RECT  46.577 177.984 46.973 178.008 ;
     RECT  46.469 173.856 47.017 173.976 ;
     RECT  46.073 31.44 47.257 31.464 ;
     RECT  46.793 29.232 47.317 30.456 ;
     RECT  47.257 31.44 47.317 31.752 ;
     RECT  45.904 37.008 47.317 37.416 ;
     RECT  46.793 0.096 47.333 6.12 ;
     RECT  46.019 34.176 47.365 34.2 ;
     RECT  46.787 35.424 47.405 35.448 ;
     RECT  47.365 33.6 47.473 34.2 ;
     RECT  47.317 36.48 47.509 37.416 ;
     RECT  46.691 21.696 47.513 21.72 ;
     RECT  46.691 23.904 47.621 23.928 ;
     RECT  46.649 25.584 47.749 25.944 ;
     RECT  47.333 2.496 47.801 6.12 ;
     RECT  47.509 36.48 47.833 37.464 ;
     RECT  47.749 25.584 47.836 26.856 ;
     RECT  47.473 33.216 47.941 34.2 ;
     RECT  47.317 29.232 47.977 31.752 ;
     RECT  47.941 33.216 47.977 34.344 ;
     RECT  46.691 19.92 48.013 20.328 ;
     RECT  47.836 25.584 48.044 25.944 ;
     RECT  47.977 29.232 48.121 34.344 ;
     RECT  47.833 36.24 48.121 37.464 ;
     RECT  46.757 38.544 48.121 159.384 ;
     RECT  48.044 25.2 48.131 25.944 ;
     RECT  47.801 2.496 48.233 5.976 ;
     RECT  47.333 0.096 48.373 1.224 ;
     RECT  48.121 29.232 48.409 34.44 ;
     RECT  48.049 17.088 48.421 17.112 ;
     RECT  46.793 27.84 48.449 27.864 ;
     RECT  48.421 16.416 48.467 17.112 ;
     RECT  48.121 36.24 48.476 159.384 ;
     RECT  48.476 35.856 48.563 159.384 ;
     RECT  48.131 25.92 48.593 25.944 ;
     RECT  48.409 28.944 48.665 34.44 ;
     RECT  48.665 28.944 48.773 33.672 ;
     RECT  48.233 2.784 48.805 5.976 ;
     RECT  48.085 21.648 48.841 21.672 ;
     RECT  48.841 21.648 48.949 22.2 ;
     RECT  48.949 21.648 49.061 22.344 ;
     RECT  48.013 19.344 49.161 20.328 ;
     RECT  48.773 28.944 49.187 31.224 ;
     RECT  48.773 32.304 49.187 33.672 ;
     RECT  49.061 22.176 49.277 22.344 ;
     RECT  48.805 2.784 49.345 6.312 ;
     RECT  49.309 26.112 49.381 26.136 ;
     RECT  49.381 18.192 49.465 18.216 ;
     RECT  49.381 26.112 49.523 26.232 ;
     RECT  49.477 27.696 49.564 27.72 ;
     RECT  49.345 2.64 49.565 6.312 ;
     RECT  49.141 34.896 49.597 34.92 ;
     RECT  48.563 36.24 49.597 159.384 ;
     RECT  48.661 23.328 49.601 23.352 ;
     RECT  49.161 19.344 49.741 19.368 ;
     RECT  49.565 2.64 49.745 6.264 ;
     RECT  48.373 0.096 49.813 1.464 ;
     RECT  48.467 16.416 49.885 16.44 ;
     RECT  49.523 26.112 49.993 26.136 ;
     RECT  49.921 20.688 50.101 20.712 ;
     RECT  49.741 19.104 50.281 19.368 ;
     RECT  49.187 28.944 50.317 31.176 ;
     RECT  49.187 32.688 50.317 33.672 ;
     RECT  49.885 16.272 50.389 16.44 ;
     RECT  50.317 28.944 50.461 33.672 ;
     RECT  50.101 20.688 50.533 21.528 ;
     RECT  50.389 15.984 50.569 16.44 ;
     RECT  50.461 28.416 50.713 33.672 ;
     RECT  49.597 34.896 50.713 159.384 ;
     RECT  49.813 0.096 50.719 1.8 ;
     RECT  50.137 24.144 50.741 24.168 ;
     RECT  50.741 24.144 50.773 24.552 ;
     RECT  49.993 25.728 50.773 26.136 ;
     RECT  50.533 20.688 50.78 22.488 ;
     RECT  50.569 15.984 50.785 17.112 ;
     RECT  50.719 0.144 50.821 1.8 ;
     RECT  49.745 2.784 50.821 6.264 ;
     RECT  50.713 28.416 50.821 159.384 ;
     RECT  49.093 7.344 50.828 7.368 ;
     RECT  50.785 15.984 50.869 17.4 ;
     RECT  50.821 0.144 51.008 6.264 ;
     RECT  50.828 7.344 51.008 7.416 ;
     RECT  50.869 15.84 51.008 17.4 ;
     RECT  50.281 19.104 51.008 19.512 ;
     RECT  50.78 20.688 51.008 23.016 ;
     RECT  50.773 24.144 51.008 26.136 ;
     RECT  50.821 27.504 51.008 159.384 ;
     RECT  46.973 165.312 51.008 165.336 ;
     RECT  46.973 166.368 51.008 166.392 ;
     RECT  46.325 168.528 51.008 168.552 ;
     RECT  46.355 170.448 51.008 170.52 ;
     RECT  47.017 173.952 51.008 173.976 ;
     RECT  46.469 175.056 51.008 175.08 ;
     RECT  51.008 0.144 51.112 179.292 ;
     RECT  51.112 0.144 51.304 179.022 ;
     RECT  51.304 17.376 51.329 17.976 ;
     RECT  51.304 0.144 51.365 5.736 ;
     RECT  51.304 33.072 51.365 36.312 ;
     RECT  51.365 4.704 51.473 5.736 ;
     RECT  51.304 24.144 51.473 26.28 ;
     RECT  51.304 20.976 51.509 22.824 ;
     RECT  51.365 0.144 51.685 3.72 ;
     RECT  51.509 22.464 51.725 22.824 ;
     RECT  51.304 27.696 51.869 31.224 ;
     RECT  51.365 33.552 51.869 36.312 ;
     RECT  51.869 35.232 51.977 36.312 ;
     RECT  51.685 0.096 52.085 3.72 ;
     RECT  51.304 7.344 52.364 7.368 ;
     RECT  51.329 17.952 52.405 17.976 ;
     RECT  52.364 7.344 52.441 7.56 ;
     RECT  52.441 6.864 52.451 7.56 ;
     RECT  51.304 14.736 52.451 14.76 ;
     RECT  52.364 16.368 52.451 16.392 ;
     RECT  52.405 17.376 52.451 17.976 ;
     RECT  51.473 4.752 52.481 5.736 ;
     RECT  52.481 4.752 52.547 5.256 ;
     RECT  52.451 6.864 52.547 6.888 ;
     RECT  51.473 24.48 52.549 26.28 ;
     RECT  52.547 5.232 52.588 5.256 ;
     RECT  51.304 19.968 52.645 19.992 ;
     RECT  51.725 22.8 52.657 22.824 ;
     RECT  52.645 19.152 52.691 19.992 ;
     RECT  52.691 19.152 52.693 19.176 ;
     RECT  52.693 18.768 52.733 19.176 ;
     RECT  51.869 27.936 52.805 31.224 ;
     RECT  52.549 24.432 52.837 26.28 ;
     RECT  52.657 22.8 52.945 22.872 ;
     RECT  52.837 23.856 52.945 26.28 ;
     RECT  51.869 33.552 53.017 34.248 ;
     RECT  52.451 17.376 53.021 17.4 ;
     RECT  52.405 32.208 53.036 32.232 ;
     RECT  52.945 22.8 53.053 26.28 ;
     RECT  53.053 22.8 53.057 26.76 ;
     RECT  51.977 36.288 53.077 36.312 ;
     RECT  52.805 27.936 53.125 30.456 ;
     RECT  53.125 27.744 53.219 30.456 ;
     RECT  53.036 31.824 53.219 32.232 ;
     RECT  52.085 0.096 53.237 3.432 ;
     RECT  51.304 37.536 53.269 38.76 ;
     RECT  51.304 39.792 53.269 159.384 ;
     RECT  53.057 22.848 53.413 26.76 ;
     RECT  53.219 27.744 53.413 29.016 ;
     RECT  53.077 36.288 53.413 36.504 ;
     RECT  53.269 37.536 53.413 159.384 ;
     RECT  53.237 2.304 53.417 3.432 ;
     RECT  52.733 18.768 53.417 19.032 ;
     RECT  51.509 20.976 53.485 21 ;
     RECT  53.219 32.208 53.485 32.232 ;
     RECT  53.017 33.312 53.485 34.248 ;
     RECT  53.413 22.848 53.669 29.016 ;
     RECT  53.417 19.008 53.705 19.032 ;
     RECT  53.417 2.304 53.813 2.472 ;
     RECT  53.485 20.976 53.917 21.816 ;
     RECT  53.485 32.208 53.921 34.248 ;
     RECT  53.917 20.88 53.989 21.816 ;
     RECT  53.237 0.096 54.065 1.176 ;
     RECT  54.065 0.576 54.101 1.176 ;
     RECT  53.989 20.208 54.131 21.816 ;
     RECT  54.131 20.88 54.133 21.816 ;
     RECT  53.669 22.848 54.133 23.88 ;
     RECT  53.413 36.288 54.172 159.384 ;
     RECT  54.172 38.112 54.173 159.384 ;
     RECT  54.173 38.304 54.209 159.384 ;
     RECT  53.219 30.24 54.241 30.456 ;
     RECT  53.669 24.96 54.245 29.016 ;
     RECT  54.101 0.576 54.317 0.6 ;
     RECT  54.133 20.88 54.389 23.88 ;
     RECT  54.245 26.112 54.389 29.016 ;
     RECT  53.921 33.408 54.425 34.248 ;
     RECT  53.813 2.352 54.461 2.472 ;
     RECT  54.389 23.28 54.515 23.88 ;
     RECT  54.389 26.208 54.515 29.016 ;
     RECT  54.245 24.96 54.556 25.08 ;
     RECT  54.389 20.88 54.569 21.816 ;
     RECT  53.921 32.208 54.572 32.28 ;
     RECT  54.209 38.448 54.605 159.384 ;
     RECT  54.556 24.96 54.641 24.984 ;
     RECT  54.515 26.736 54.641 29.016 ;
     RECT  54.572 31.584 54.659 32.28 ;
     RECT  54.241 30.048 54.72 30.456 ;
     RECT  54.641 27.888 54.749 29.016 ;
     RECT  54.172 36.288 54.805 37.032 ;
     RECT  54.425 33.6 54.857 34.248 ;
     RECT  54.805 35.712 54.892 37.032 ;
     RECT  54.857 34.224 54.925 34.248 ;
     RECT  54.745 30.72 54.929 30.84 ;
     RECT  54.461 2.352 54.965 2.376 ;
     RECT  54.605 38.448 55.001 38.568 ;
     RECT  54.659 32.208 55.037 32.28 ;
     RECT  54.641 26.736 55.043 26.76 ;
     RECT  54.749 27.888 55.043 27.912 ;
     RECT  54.749 28.992 55.073 29.016 ;
     RECT  54.929 30.816 55.073 30.84 ;
     RECT  54.515 23.856 55.289 23.88 ;
     RECT  55.037 32.256 55.325 32.28 ;
     RECT  54.925 34.224 55.433 34.488 ;
     RECT  55.433 34.464 56.408 34.488 ;
     RECT  54.892 36.624 56.408 37.032 ;
     RECT  55.001 38.544 56.408 38.568 ;
     RECT  54.605 39.792 56.408 159.384 ;
     RECT  51.304 165.312 56.408 165.336 ;
     RECT  51.304 166.368 56.408 166.392 ;
     RECT  51.304 168.528 56.408 168.552 ;
     RECT  51.304 170.448 56.408 170.52 ;
     RECT  51.304 173.952 56.408 173.976 ;
     RECT  51.304 175.056 56.408 175.08 ;
     RECT  56.408 2.148 56.512 179.292 ;
     RECT  56.512 2.418 56.704 179.022 ;
     RECT  56.704 36.528 57.017 36.648 ;
     RECT  57.017 36.528 61.808 36.552 ;
     RECT  56.704 38.544 61.808 38.568 ;
     RECT  56.704 39.792 61.808 159.384 ;
     RECT  56.704 165.312 61.808 165.336 ;
     RECT  56.704 166.368 61.808 166.392 ;
     RECT  56.704 168.528 61.808 168.552 ;
     RECT  56.704 170.448 61.808 170.52 ;
     RECT  56.704 173.952 61.808 173.976 ;
     RECT  56.704 175.056 61.808 175.08 ;
     RECT  61.808 2.148 61.912 179.292 ;
     RECT  61.912 2.418 62.104 179.022 ;
     RECT  62.104 174.192 62.381 175.08 ;
     RECT  62.104 165.168 62.417 165.336 ;
     RECT  62.104 170.256 62.633 170.472 ;
     RECT  62.104 36.528 67.208 36.552 ;
     RECT  62.104 38.544 67.208 38.568 ;
     RECT  62.104 39.792 67.208 159.384 ;
     RECT  62.417 165.168 67.208 165.192 ;
     RECT  62.104 166.368 67.208 166.392 ;
     RECT  62.104 168.528 67.208 168.552 ;
     RECT  62.633 170.256 67.208 170.328 ;
     RECT  62.381 174.192 67.208 174.792 ;
     RECT  67.208 2.148 67.312 179.292 ;
     RECT  67.312 2.418 67.504 179.022 ;
     RECT  67.504 38.544 70.693 38.568 ;
     RECT  70.693 38.544 70.733 38.712 ;
     RECT  67.504 168.528 71.555 168.552 ;
     RECT  67.504 166.368 71.603 166.392 ;
     RECT  67.504 36.528 72.608 36.552 ;
     RECT  70.733 38.688 72.608 38.712 ;
     RECT  67.504 39.792 72.608 159.384 ;
     RECT  67.504 165.168 72.608 165.192 ;
     RECT  67.504 170.256 72.608 170.328 ;
     RECT  67.504 174.192 72.608 174.792 ;
     RECT  72.608 2.148 72.712 179.292 ;
     RECT  72.712 2.418 72.904 179.022 ;
     RECT  72.904 38.688 73.235 38.712 ;
     RECT  72.904 39.792 76.848 159.384 ;
     RECT  72.904 170.256 76.997 170.328 ;
     RECT  76.848 146.448 77.075 146.472 ;
     RECT  76.848 39.792 77.712 139.464 ;
     RECT  76.997 170.256 77.713 170.28 ;
     RECT  72.904 174.192 77.713 174.792 ;
     RECT  77.712 126.72 77.795 139.464 ;
     RECT  77.712 39.792 77.897 54.072 ;
     RECT  77.712 60.24 77.897 60.696 ;
     RECT  77.897 60.24 77.969 60.6 ;
     RECT  72.904 36.528 78.008 36.552 ;
     RECT  77.897 39.792 78.008 53.976 ;
     RECT  76.848 152.16 78.008 159.384 ;
     RECT  72.904 165.168 78.008 165.192 ;
     RECT  77.713 169.872 78.008 170.28 ;
     RECT  77.713 173.952 78.008 174.792 ;
     RECT  77.969 60.432 78.041 60.6 ;
     RECT  78.008 2.148 78.112 53.976 ;
     RECT  78.008 152.16 78.112 179.292 ;
     RECT  78.112 2.418 78.304 53.976 ;
     RECT  78.112 152.16 78.304 179.022 ;
     RECT  76.848 150 78.649 150.024 ;
     RECT  78.304 39.792 78.659 53.976 ;
     RECT  78.304 170.256 78.689 170.28 ;
     RECT  78.304 173.952 78.689 174.792 ;
     RECT  77.712 79.44 78.949 79.464 ;
     RECT  77.795 127.008 78.995 139.464 ;
     RECT  78.689 173.952 78.995 174.456 ;
     RECT  78.949 79.44 78.997 79.992 ;
     RECT  78.997 79.44 79.045 80.52 ;
     RECT  77.712 81.648 79.045 81.912 ;
     RECT  77.893 140.448 79.141 140.472 ;
     RECT  76.848 142.176 79.141 142.2 ;
     RECT  78.613 148.032 79.153 148.056 ;
     RECT  78.304 152.16 79.153 160.056 ;
     RECT  78.304 161.136 79.235 161.16 ;
     RECT  79.153 148.032 79.237 148.2 ;
     RECT  79.153 151.2 79.297 160.056 ;
     RECT  78.304 164.352 79.337 164.952 ;
     RECT  79.225 146.352 79.369 146.376 ;
     RECT  78.995 127.392 79.373 139.464 ;
     RECT  79.373 130.752 79.405 139.464 ;
     RECT  79.141 140.448 79.405 142.2 ;
     RECT  79.369 146.352 79.405 146.568 ;
     RECT  78.649 150 79.441 150.12 ;
     RECT  79.297 151.2 79.441 160.104 ;
     RECT  79.369 161.088 79.441 161.112 ;
     RECT  79.381 163.92 79.468 163.944 ;
     RECT  79.373 127.392 79.517 129.72 ;
     RECT  79.517 127.392 79.523 129.528 ;
     RECT  78.304 165.984 79.525 166.008 ;
     RECT  78.995 174.432 79.525 174.456 ;
     RECT  79.405 130.752 79.553 142.2 ;
     RECT  79.523 127.776 79.589 129.528 ;
     RECT  79.553 131.424 79.589 133.176 ;
     RECT  79.589 129.024 79.625 129.528 ;
     RECT  79.237 148.032 79.693 148.824 ;
     RECT  79.441 150 79.693 161.112 ;
     RECT  79.625 129.504 79.697 129.528 ;
     RECT  79.441 169.872 79.715 169.896 ;
     RECT  79.589 127.776 79.733 127.992 ;
     RECT  79.621 143.616 79.765 143.64 ;
     RECT  79.628 145.152 79.765 145.176 ;
     RECT  79.405 146.352 79.765 147 ;
     RECT  79.693 148.032 79.765 161.112 ;
     RECT  77.712 85.344 79.801 95.448 ;
     RECT  78.659 45.504 79.805 53.976 ;
     RECT  79.801 85.248 79.805 95.448 ;
     RECT  79.733 127.776 79.805 127.896 ;
     RECT  79.765 143.616 79.811 161.112 ;
     RECT  79.805 51.936 79.841 53.976 ;
     RECT  79.811 147.6 79.859 161.112 ;
     RECT  79.525 165.072 79.916 166.008 ;
     RECT  79.405 167.616 79.916 167.64 ;
     RECT  79.553 135.696 79.981 142.2 ;
     RECT  79.045 79.44 79.985 81.912 ;
     RECT  79.916 165.072 80.003 167.64 ;
     RECT  79.805 85.248 80.021 89.016 ;
     RECT  79.805 127.776 80.021 127.8 ;
     RECT  79.859 150 80.021 161.112 ;
     RECT  79.805 45.504 80.057 50.52 ;
     RECT  79.841 52.224 80.057 53.976 ;
     RECT  78.304 162.48 80.089 162.504 ;
     RECT  79.909 70.704 80.093 70.728 ;
     RECT  80.005 71.808 80.093 71.832 ;
     RECT  80.057 52.224 80.129 53.88 ;
     RECT  78.901 116.208 80.156 116.232 ;
     RECT  80.156 108.144 80.161 108.168 ;
     RECT  79.573 118.128 80.169 118.152 ;
     RECT  79.717 120.048 80.169 120.072 ;
     RECT  80.021 85.248 80.201 86.328 ;
     RECT  80.021 87.36 80.201 89.016 ;
     RECT  79.805 90.144 80.201 90.168 ;
     RECT  79.811 144.336 80.201 145.608 ;
     RECT  80.129 53.856 80.237 53.88 ;
     RECT  80.021 160.704 80.243 161.112 ;
     RECT  80.161 110.544 80.245 110.568 ;
     RECT  80.161 114.816 80.245 114.84 ;
     RECT  79.805 93.84 80.269 95.448 ;
     RECT  80.057 45.504 80.273 48.312 ;
     RECT  80.057 49.44 80.273 50.52 ;
     RECT  80.06 75.84 80.281 75.864 ;
     RECT  80.245 114.816 80.291 115.128 ;
     RECT  79.141 72.912 80.309 72.936 ;
     RECT  80.269 93.84 80.341 95.784 ;
     RECT  80.245 110.448 80.341 110.568 ;
     RECT  80.003 165.072 80.341 165.288 ;
     RECT  80.273 46.944 80.345 48.312 ;
     RECT  80.245 113.712 80.345 113.736 ;
     RECT  80.129 52.224 80.381 52.632 ;
     RECT  80.201 88.032 80.381 89.016 ;
     RECT  80.341 110.448 80.387 110.904 ;
     RECT  79.985 79.44 80.417 81.864 ;
     RECT  80.021 150 80.435 159.624 ;
     RECT  80.345 47.04 80.453 48.312 ;
     RECT  80.381 52.608 80.453 52.632 ;
     RECT  80.381 88.032 80.453 88.152 ;
     RECT  80.197 105.984 80.521 106.632 ;
     RECT  80.003 166.656 80.525 167.64 ;
     RECT  80.273 45.504 80.561 45.528 ;
     RECT  79.553 134.352 80.581 134.376 ;
     RECT  79.981 135.696 80.581 142.968 ;
     RECT  80.089 162.288 80.588 162.504 ;
     RECT  80.273 50.496 80.597 50.52 ;
     RECT  80.291 115.104 80.629 115.128 ;
     RECT  80.156 116.208 80.629 117.048 ;
     RECT  80.169 118.128 80.629 120.072 ;
     RECT  80.581 134.352 80.629 142.968 ;
     RECT  80.273 49.44 80.669 49.464 ;
     RECT  80.201 85.344 80.675 86.328 ;
     RECT  80.588 162.288 80.675 162.6 ;
     RECT  80.197 103.344 80.677 103.368 ;
     RECT  80.377 98.064 80.701 98.088 ;
     RECT  80.677 99.264 80.701 99.288 ;
     RECT  80.521 105.984 80.732 106.68 ;
     RECT  80.161 108.144 80.732 108.888 ;
     RECT  80.732 105.984 80.737 108.888 ;
     RECT  80.387 110.88 80.745 110.904 ;
     RECT  80.303 112.272 80.745 112.296 ;
     RECT  80.701 98.064 80.764 99.288 ;
     RECT  78.659 39.792 80.773 44.328 ;
     RECT  80.737 105.984 80.777 109.464 ;
     RECT  80.677 103.344 80.809 104.28 ;
     RECT  80.341 164.784 80.809 165.288 ;
     RECT  80.675 85.344 80.813 86.232 ;
     RECT  80.341 93.84 80.845 96.216 ;
     RECT  79.859 147.6 80.881 148.584 ;
     RECT  80.675 162.288 80.881 162.504 ;
     RECT  80.773 39.792 80.885 44.472 ;
     RECT  80.813 85.632 80.915 86.232 ;
     RECT  80.845 93.84 80.917 96.888 ;
     RECT  80.764 98.064 80.917 99.048 ;
     RECT  79.589 131.568 80.917 131.592 ;
     RECT  79.589 132.672 80.917 132.696 ;
     RECT  80.629 133.776 80.917 142.968 ;
     RECT  80.876 168.192 80.917 168.216 ;
     RECT  80.885 39.792 80.929 43.896 ;
     RECT  80.201 144.864 80.957 145.608 ;
     RECT  80.917 131.04 80.989 131.592 ;
     RECT  80.243 160.896 80.989 161.112 ;
     RECT  80.745 110.88 80.993 112.296 ;
     RECT  80.629 115.104 80.993 120.072 ;
     RECT  80.917 168.192 81.004 168.744 ;
     RECT  80.809 113.76 81.02 113.784 ;
     RECT  80.881 147.168 81.025 148.584 ;
     RECT  80.435 150 81.025 150.504 ;
     RECT  81.02 113.76 81.107 114.072 ;
     RECT  81.109 123.312 81.133 123.336 ;
     RECT  80.917 93.84 81.164 99.048 ;
     RECT  80.915 85.632 81.173 85.896 ;
     RECT  81.089 125.424 81.173 125.448 ;
     RECT  80.989 130.512 81.173 131.592 ;
     RECT  80.917 132.672 81.173 142.968 ;
     RECT  81.133 123.12 81.196 123.336 ;
     RECT  80.989 160.896 81.205 161.16 ;
     RECT  81.164 93.504 81.209 99.048 ;
     RECT  81.173 85.872 81.245 85.896 ;
     RECT  81.209 93.504 81.251 93.528 ;
     RECT  78.997 121.392 81.263 121.416 ;
     RECT  81.197 92.304 81.281 92.328 ;
     RECT  81.173 132.672 81.281 133.416 ;
     RECT  80.809 164.736 81.301 165.288 ;
     RECT  80.525 166.656 81.325 167.064 ;
     RECT  81.281 133.152 81.347 133.416 ;
     RECT  80.809 103.344 81.353 104.904 ;
     RECT  81.301 164.448 81.388 165.288 ;
     RECT  80.777 109.44 81.389 109.464 ;
     RECT  81.353 104.832 81.397 104.904 ;
     RECT  81.157 77.52 81.445 77.544 ;
     RECT  81.205 160.896 81.457 161.256 ;
     RECT  80.881 162.24 81.457 162.504 ;
     RECT  81.445 77.52 81.491 77.928 ;
     RECT  81.385 92.928 81.491 92.952 ;
     RECT  81.097 128.256 81.529 128.28 ;
     RECT  81.397 104.88 81.565 104.904 ;
     RECT  80.957 144.864 81.565 144.888 ;
     RECT  81.196 123.12 81.641 123.144 ;
     RECT  81.457 160.704 81.683 162.504 ;
     RECT  81.025 147.168 81.709 150.504 ;
     RECT  81.209 94.8 81.749 99.048 ;
     RECT  81.457 169.824 81.779 169.848 ;
     RECT  81.749 95.952 81.781 99.048 ;
     RECT  80.521 101.952 81.781 101.976 ;
     RECT  81.353 103.344 81.781 103.752 ;
     RECT  80.993 118.128 81.788 120.072 ;
     RECT  81.263 121.392 81.788 121.944 ;
     RECT  81.388 164.736 81.817 165.288 ;
     RECT  81.733 170.832 81.82 171.48 ;
     RECT  80.377 100.896 81.821 100.92 ;
     RECT  80.993 111.6 81.829 112.296 ;
     RECT  81.107 113.76 81.829 113.976 ;
     RECT  81.565 124.272 81.829 124.296 ;
     RECT  81.173 134.544 81.853 142.968 ;
     RECT  80.777 105.984 81.875 108.456 ;
     RECT  81.301 129.264 81.884 129.288 ;
     RECT  81.173 130.512 81.884 131.064 ;
     RECT  81.347 133.152 81.971 133.272 ;
     RECT  81.529 127.728 81.98 128.28 ;
     RECT  81.98 100.224 82.067 100.872 ;
     RECT  81.98 127.344 82.067 128.28 ;
     RECT  81.853 134.544 82.067 143.208 ;
     RECT  81.565 104.88 82.069 105 ;
     RECT  81.875 105.984 82.069 108.312 ;
     RECT  81.829 111.6 82.069 113.976 ;
     RECT  80.993 115.104 82.069 117.048 ;
     RECT  81.817 164.736 82.109 165.576 ;
     RECT  81.829 110.544 82.152 110.568 ;
     RECT  82.069 111.6 82.152 117.048 ;
     RECT  82.152 110.544 82.213 117.048 ;
     RECT  81.788 118.128 82.213 121.944 ;
     RECT  81.565 144.24 82.249 144.888 ;
     RECT  81.709 146.448 82.249 150.504 ;
     RECT  80.435 151.92 82.249 159.624 ;
     RECT  81.683 160.896 82.253 162.504 ;
     RECT  80.417 79.44 82.261 81.768 ;
     RECT  81.205 125.616 82.285 125.976 ;
     RECT  82.067 127.584 82.285 128.28 ;
     RECT  81.884 129.264 82.285 131.064 ;
     RECT  81.781 95.952 82.325 99.192 ;
     RECT  81.491 77.904 82.357 77.928 ;
     RECT  82.213 110.544 82.361 121.944 ;
     RECT  81.781 101.952 82.397 103.752 ;
     RECT  82.285 125.424 82.453 125.976 ;
     RECT  82.067 135.216 82.46 143.208 ;
     RECT  82.249 144.24 82.46 145.416 ;
     RECT  82.285 127.584 82.465 131.064 ;
     RECT  82.357 77.904 82.501 78.12 ;
     RECT  82.325 96.096 82.501 99.192 ;
     RECT  82.361 110.544 82.501 118.536 ;
     RECT  82.46 135.216 82.537 145.416 ;
     RECT  82.465 92.928 82.556 92.952 ;
     RECT  82.501 91.152 82.573 91.176 ;
     RECT  82.361 119.52 82.573 121.944 ;
     RECT  82.556 92.928 82.597 93.336 ;
     RECT  81.749 94.8 82.597 94.968 ;
     RECT  82.573 91.152 82.645 91.656 ;
     RECT  82.573 119.52 82.645 121.992 ;
     RECT  81.325 166.656 82.753 166.68 ;
     RECT  81.745 167.76 82.753 167.784 ;
     RECT  82.465 127.584 82.789 131.688 ;
     RECT  82.069 104.88 82.844 108.312 ;
     RECT  82.501 109.68 82.844 118.536 ;
     RECT  82.253 162.48 82.861 162.504 ;
     RECT  82.501 77.904 82.933 78.456 ;
     RECT  82.261 79.44 82.933 82.248 ;
     RECT  82.861 162.48 82.933 162.984 ;
     RECT  82.067 100.272 82.981 100.872 ;
     RECT  82.397 101.952 82.981 103.704 ;
     RECT  82.537 135.216 83.005 145.464 ;
     RECT  82.249 146.448 83.005 159.624 ;
     RECT  83.005 135.216 83.041 159.624 ;
     RECT  83.041 135.168 83.077 159.624 ;
     RECT  83.077 134.784 83.113 159.624 ;
     RECT  82.253 160.896 83.113 161.352 ;
     RECT  81.829 124.272 83.149 124.344 ;
     RECT  82.453 125.424 83.149 126.552 ;
     RECT  82.177 168.912 83.173 169.272 ;
     RECT  82.501 96.096 83.221 99.288 ;
     RECT  82.981 100.272 83.221 103.704 ;
     RECT  83.221 30.24 83.269 30.264 ;
     RECT  82.645 90.96 83.269 91.656 ;
     RECT  83.149 124.272 83.269 126.552 ;
     RECT  82.789 127.584 83.269 132.216 ;
     RECT  81.971 133.248 83.269 133.272 ;
     RECT  82.753 166.656 83.293 167.784 ;
     RECT  83.173 168.816 83.293 169.368 ;
     RECT  83.269 90.96 83.329 91.896 ;
     RECT  82.597 92.928 83.329 94.968 ;
     RECT  83.269 29.616 83.408 30.264 ;
     RECT  78.304 36.528 83.408 36.552 ;
     RECT  80.929 39.792 83.408 43.032 ;
     RECT  78.041 60.432 83.408 60.456 ;
     RECT  82.933 77.904 83.408 82.248 ;
     RECT  82.861 88.368 83.408 88.392 ;
     RECT  82.933 89.52 83.408 89.544 ;
     RECT  83.329 90.96 83.408 94.968 ;
     RECT  83.221 96.096 83.408 103.704 ;
     RECT  82.844 104.88 83.408 118.536 ;
     RECT  82.645 119.52 83.408 122.52 ;
     RECT  83.269 124.272 83.408 132.216 ;
     RECT  83.269 133.248 83.408 133.752 ;
     RECT  83.113 134.784 83.408 161.352 ;
     RECT  82.933 162.48 83.408 163.56 ;
     RECT  82.109 165.024 83.408 165.576 ;
     RECT  83.293 166.656 83.408 169.368 ;
     RECT  81.82 170.832 83.408 170.856 ;
     RECT  83.408 2.148 83.512 179.292 ;
     RECT  83.512 2.418 83.704 179.022 ;
     RECT  83.704 105.12 83.765 125.928 ;
     RECT  83.704 101.952 83.801 103.608 ;
     RECT  83.765 105.408 83.909 125.928 ;
     RECT  83.704 144.624 83.932 162.984 ;
     RECT  83.704 164.256 83.981 168.936 ;
     RECT  83.704 130.512 84.053 133.8 ;
     RECT  83.704 134.976 84.161 143.544 ;
     RECT  84.053 131.088 84.275 133.8 ;
     RECT  83.704 95.76 84.305 99.768 ;
     RECT  83.981 165.312 84.305 168.936 ;
     RECT  83.704 28.464 84.371 29.64 ;
     RECT  84.371 29.616 84.449 29.64 ;
     RECT  83.909 105.408 84.457 114.072 ;
     RECT  83.932 145.104 84.521 162.984 ;
     RECT  84.521 146.448 84.556 162.984 ;
     RECT  84.305 95.76 84.563 99.72 ;
     RECT  84.556 146.448 84.593 159.384 ;
     RECT  84.457 105.408 84.652 108.696 ;
     RECT  84.563 96.768 84.659 99.72 ;
     RECT  84.659 96.768 84.665 97.512 ;
     RECT  83.704 77.904 84.697 82.968 ;
     RECT  83.704 84.336 84.697 84.36 ;
     RECT  84.161 135.408 84.733 143.544 ;
     RECT  84.305 165.456 84.733 168.936 ;
     RECT  83.704 169.92 84.733 169.944 ;
     RECT  84.652 105.408 84.737 105.528 ;
     RECT  83.704 86.16 84.757 86.76 ;
     RECT  84.733 165.456 84.757 169.944 ;
     RECT  84.563 95.76 84.803 95.784 ;
     RECT  83.704 87.744 84.805 88.92 ;
     RECT  83.909 115.44 84.805 125.928 ;
     RECT  84.757 165.456 84.837 170.856 ;
     RECT  84.457 110.304 84.851 114.072 ;
     RECT  83.801 103.584 84.853 103.608 ;
     RECT  83.704 100.848 84.877 100.872 ;
     RECT  83.801 101.952 84.877 102.216 ;
     RECT  83.981 164.256 84.881 164.28 ;
     RECT  84.805 115.44 84.889 126.6 ;
     RECT  84.805 87.744 84.899 89.736 ;
     RECT  84.805 172.656 84.901 172.68 ;
     RECT  84.697 77.904 84.913 84.36 ;
     RECT  84.901 172.656 84.947 173.496 ;
     RECT  84.889 115.44 84.949 126.456 ;
     RECT  84.949 115.104 84.989 126.456 ;
     RECT  84.877 100.848 85.013 102.216 ;
     RECT  84.853 103.2 85.013 103.608 ;
     RECT  84.733 135.408 85.025 144.12 ;
     RECT  85.013 100.848 85.036 103.608 ;
     RECT  84.737 105.408 85.093 105.432 ;
     RECT  84.851 112.848 85.129 114.072 ;
     RECT  84.989 115.104 85.129 117 ;
     RECT  83.704 127.584 85.129 129.24 ;
     RECT  84.556 160.56 85.129 162.984 ;
     RECT  84.837 170.832 85.129 170.856 ;
     RECT  84.837 165.456 85.133 169.368 ;
     RECT  84.371 28.464 85.205 28.488 ;
     RECT  85.036 102.576 85.237 103.608 ;
     RECT  85.093 104.832 85.237 105.432 ;
     RECT  84.851 110.304 85.277 111.624 ;
     RECT  85.129 112.848 85.283 117 ;
     RECT  85.237 102.576 85.321 105.432 ;
     RECT  84.659 98.496 85.34 99.72 ;
     RECT  85.036 100.848 85.34 101.448 ;
     RECT  85.025 144.096 85.345 144.12 ;
     RECT  84.521 145.104 85.345 145.464 ;
     RECT  84.989 118.128 85.349 126.456 ;
     RECT  85.277 110.304 85.421 110.616 ;
     RECT  85.34 98.496 85.427 101.448 ;
     RECT  84.275 131.232 85.453 133.8 ;
     RECT  84.652 106.512 85.477 108.696 ;
     RECT  85.421 110.544 85.523 110.616 ;
     RECT  85.453 131.232 85.525 134.136 ;
     RECT  85.349 118.128 85.529 122.328 ;
     RECT  85.129 127.584 85.553 130.008 ;
     RECT  85.525 131.088 85.553 134.136 ;
     RECT  85.025 135.408 85.561 143.112 ;
     RECT  84.913 77.904 85.601 84.408 ;
     RECT  84.899 87.744 85.637 88.92 ;
     RECT  85.561 135.168 85.637 143.112 ;
     RECT  84.593 146.448 85.637 159.192 ;
     RECT  85.601 83.712 85.717 84.408 ;
     RECT  84.757 85.824 85.717 86.76 ;
     RECT  83.704 91.2 85.733 94.632 ;
     RECT  85.427 100.848 85.745 101.448 ;
     RECT  85.637 146.448 85.745 158.904 ;
     RECT  85.133 166.128 85.745 169.368 ;
     RECT  84.665 96.768 85.765 96.84 ;
     RECT  85.765 96.768 85.777 97.368 ;
     RECT  85.427 98.496 85.777 99.72 ;
     RECT  85.553 127.584 85.849 134.136 ;
     RECT  85.637 135.168 85.849 143.064 ;
     RECT  85.129 160.56 85.849 164.184 ;
     RECT  84.947 173.472 85.849 173.496 ;
     RECT  85.717 83.712 85.853 86.76 ;
     RECT  85.849 127.584 85.859 143.064 ;
     RECT  85.277 111.6 85.909 111.624 ;
     RECT  85.283 112.848 85.909 116.52 ;
     RECT  85.349 123.936 85.961 126.456 ;
     RECT  85.853 85.824 85.993 86.76 ;
     RECT  85.637 87.744 85.993 88.248 ;
     RECT  85.745 149.328 86.003 158.904 ;
     RECT  85.321 103.44 86.029 105.432 ;
     RECT  85.477 106.512 86.029 109.416 ;
     RECT  85.129 170.832 86.033 171 ;
     RECT  85.849 160.56 86.051 164.856 ;
     RECT  85.345 144.096 86.053 145.464 ;
     RECT  85.745 146.448 86.053 148.296 ;
     RECT  85.859 127.68 86.069 143.064 ;
     RECT  85.993 85.824 86.105 88.248 ;
     RECT  86.069 127.68 86.141 129.384 ;
     RECT  86.003 149.328 86.141 150.408 ;
     RECT  85.745 166.128 86.141 168.312 ;
     RECT  85.777 96.768 86.149 99.72 ;
     RECT  86.149 96.336 86.177 99.72 ;
     RECT  85.745 101.424 86.197 101.448 ;
     RECT  85.853 83.712 86.213 84.408 ;
     RECT  86.197 101.424 86.249 102.408 ;
     RECT  86.051 160.56 86.249 162.648 ;
     RECT  85.909 111.6 86.285 116.52 ;
     RECT  86.053 144.096 86.285 148.296 ;
     RECT  86.141 166.128 86.285 167.016 ;
     RECT  86.105 87.792 86.339 88.248 ;
     RECT  86.285 166.128 86.339 166.632 ;
     RECT  86.285 112.704 86.353 116.52 ;
     RECT  86.029 103.44 86.389 109.416 ;
     RECT  85.523 110.544 86.389 110.568 ;
     RECT  86.069 131.088 86.393 143.064 ;
     RECT  85.529 121.104 86.425 122.328 ;
     RECT  86.141 168.096 86.529 168.312 ;
     RECT  86.177 96.336 86.531 99.672 ;
     RECT  86.285 144.096 86.537 148.056 ;
     RECT  85.733 91.2 86.545 95.16 ;
     RECT  86.531 96.336 86.569 96.888 ;
     RECT  86.353 112.704 86.579 117.096 ;
     RECT  86.389 103.44 86.581 110.568 ;
     RECT  86.285 111.6 86.581 111.624 ;
     RECT  86.569 96.288 86.629 96.888 ;
     RECT  86.579 112.752 86.641 117.096 ;
     RECT  85.529 118.128 86.641 120.072 ;
     RECT  85.849 173.472 86.645 173.544 ;
     RECT  86.425 121.104 86.669 122.904 ;
     RECT  85.961 123.936 86.669 126.264 ;
     RECT  86.393 131.088 86.675 134.136 ;
     RECT  86.545 91.2 86.677 94.584 ;
     RECT  86.339 87.888 86.717 88.248 ;
     RECT  86.249 161.664 86.717 162.648 ;
     RECT  86.581 103.44 86.723 111.624 ;
     RECT  86.641 112.752 86.725 120.072 ;
     RECT  86.393 135.168 86.753 143.064 ;
     RECT  86.749 160.272 86.78 160.296 ;
     RECT  86.531 97.872 86.789 99.672 ;
     RECT  86.723 103.44 86.789 111.192 ;
     RECT  86.675 131.328 86.789 131.784 ;
     RECT  86.033 170.976 86.821 171 ;
     RECT  86.675 132.816 86.825 134.136 ;
     RECT  86.789 103.44 86.86 110.856 ;
     RECT  85.601 77.904 86.861 82.152 ;
     RECT  86.717 88.224 86.861 88.248 ;
     RECT  86.677 90.24 86.861 94.584 ;
     RECT  86.141 149.424 86.861 150.408 ;
     RECT  86.529 168.24 86.867 168.312 ;
     RECT  86.213 84.384 86.893 84.408 ;
     RECT  86.105 85.824 86.893 86.76 ;
     RECT  85.745 169.344 86.897 169.368 ;
     RECT  86.867 168.288 86.929 168.312 ;
     RECT  86.669 121.104 86.933 126.264 ;
     RECT  86.861 149.424 86.933 150.36 ;
     RECT  83.704 39.792 86.965 43.032 ;
     RECT  86.86 103.44 86.969 110.616 ;
     RECT  86.78 159.936 86.969 160.296 ;
     RECT  86.249 102.384 87.001 102.408 ;
     RECT  86.969 103.44 87.001 110.568 ;
     RECT  86.924 101.04 87.011 101.064 ;
     RECT  86.965 39.792 87.049 43.32 ;
     RECT  86.861 90.576 87.107 94.584 ;
     RECT  86.537 144.096 87.109 144.408 ;
     RECT  86.645 173.52 87.109 173.544 ;
     RECT  86.893 84.384 87.113 86.76 ;
     RECT  86.933 149.904 87.113 150.36 ;
     RECT  87.107 93.024 87.221 94.584 ;
     RECT  87.109 143.52 87.221 144.408 ;
     RECT  86.051 164.16 87.221 164.856 ;
     RECT  87.109 173.52 87.221 173.64 ;
     RECT  87.221 93.36 87.257 94.584 ;
     RECT  86.789 99.648 87.257 99.672 ;
     RECT  87.049 39.792 87.293 43.032 ;
     RECT  87.107 90.576 87.293 91.944 ;
     RECT  86.537 146.16 87.293 148.056 ;
     RECT  86.789 131.328 87.299 131.64 ;
     RECT  86.629 96.192 87.301 96.888 ;
     RECT  86.725 115.872 87.301 120.072 ;
     RECT  86.933 121.104 87.301 124.2 ;
     RECT  86.821 170.976 87.325 171.48 ;
     RECT  87.257 94.272 87.329 94.584 ;
     RECT  86.933 125.184 87.347 126.264 ;
     RECT  86.141 127.68 87.347 128.856 ;
     RECT  87.329 94.464 87.373 94.584 ;
     RECT  87.301 115.872 87.388 124.2 ;
     RECT  87.308 100.848 87.395 100.872 ;
     RECT  87.347 127.68 87.395 127.848 ;
     RECT  86.825 133.248 87.404 134.136 ;
     RECT  86.753 135.168 87.404 142.2 ;
     RECT  87.388 115.872 87.436 120.12 ;
     RECT  87.347 125.376 87.452 126.264 ;
     RECT  87.301 95.76 87.473 96.888 ;
     RECT  87.373 94.464 87.491 94.488 ;
     RECT  87.404 133.248 87.491 142.2 ;
     RECT  87.452 125.376 87.539 127.224 ;
     RECT  86.717 161.664 87.539 161.736 ;
     RECT  87.493 129.072 87.58 129.096 ;
     RECT  87.5 145.152 87.587 145.176 ;
     RECT  87.299 131.328 87.617 131.544 ;
     RECT  87.001 102.384 87.653 110.568 ;
     RECT  87.293 91.92 87.689 91.944 ;
     RECT  87.653 105.984 87.689 110.568 ;
     RECT  87.539 125.376 87.689 126.264 ;
     RECT  86.725 112.752 87.721 114.696 ;
     RECT  87.388 121.104 87.833 123.624 ;
     RECT  87.613 88.368 87.865 88.392 ;
     RECT  86.003 151.632 87.877 158.904 ;
     RECT  86.969 159.936 87.877 160.104 ;
     RECT  87.293 90.576 87.904 90.6 ;
     RECT  87.491 133.248 88.076 133.272 ;
     RECT  87.113 149.904 88.076 150.264 ;
     RECT  86.789 97.872 88.081 98.664 ;
     RECT  88.076 149.904 88.117 150.456 ;
     RECT  87.325 148.32 88.165 148.872 ;
     RECT  88.117 149.904 88.165 150.552 ;
     RECT  88.165 148.32 88.189 150.552 ;
     RECT  87.877 151.632 88.189 160.104 ;
     RECT  87.721 112.176 88.225 114.696 ;
     RECT  87.436 115.872 88.225 120.072 ;
     RECT  87.689 108.864 88.261 110.568 ;
     RECT  88.225 112.176 88.261 120.072 ;
     RECT  87.113 84.384 88.268 84.888 ;
     RECT  86.339 166.128 88.297 166.44 ;
     RECT  88.268 84.384 88.309 85.608 ;
     RECT  87.293 146.16 88.325 147.048 ;
     RECT  88.189 148.32 88.325 160.104 ;
     RECT  87.833 121.104 88.357 122.712 ;
     RECT  87.221 143.52 88.357 144.168 ;
     RECT  88.325 146.16 88.357 160.104 ;
     RECT  88.297 165.84 88.369 166.44 ;
     RECT  86.929 168.288 88.369 169.128 ;
     RECT  87.653 102.384 88.405 104.904 ;
     RECT  88.261 163.152 88.405 163.176 ;
     RECT  88.357 145.872 88.453 160.104 ;
     RECT  88.369 165.84 88.453 166.488 ;
     RECT  88.369 168.288 88.453 169.416 ;
     RECT  88.081 97.872 88.46 99.48 ;
     RECT  87.491 135.408 88.46 142.2 ;
     RECT  88.357 143.52 88.46 144.792 ;
     RECT  88.309 84.336 88.508 85.608 ;
     RECT  88.405 163.152 88.508 163.272 ;
     RECT  87.221 164.352 88.508 164.856 ;
     RECT  87.904 90.528 88.549 90.6 ;
     RECT  87.473 95.76 88.549 96.84 ;
     RECT  88.549 94.56 88.597 96.84 ;
     RECT  88.46 97.872 88.597 99.72 ;
     RECT  88.585 124.368 88.645 124.392 ;
     RECT  87.689 125.376 88.645 126.168 ;
     RECT  88.549 90.528 88.685 90.648 ;
     RECT  88.597 94.56 88.765 99.72 ;
     RECT  83.704 32.736 88.808 32.76 ;
     RECT  83.704 36.528 88.808 36.552 ;
     RECT  87.293 39.792 88.808 42.552 ;
     RECT  83.704 60.432 88.808 60.456 ;
     RECT  86.861 77.904 88.808 81.672 ;
     RECT  88.441 82.656 88.808 82.68 ;
     RECT  88.508 83.76 88.808 85.608 ;
     RECT  87.113 86.592 88.808 86.76 ;
     RECT  87.865 88.368 88.808 88.92 ;
     RECT  88.685 90.528 88.808 91.176 ;
     RECT  88.765 93.744 88.808 99.72 ;
     RECT  88.405 101.424 88.808 104.904 ;
     RECT  87.689 105.984 88.808 106.776 ;
     RECT  87.689 107.808 88.808 107.832 ;
     RECT  88.261 108.864 88.808 120.072 ;
     RECT  88.357 121.056 88.808 122.712 ;
     RECT  88.645 124.368 88.808 126.168 ;
     RECT  87.617 131.328 88.808 131.352 ;
     RECT  88.076 133.056 88.808 133.272 ;
     RECT  87.491 134.256 88.808 134.376 ;
     RECT  88.46 135.408 88.808 144.792 ;
     RECT  88.453 145.872 88.808 160.584 ;
     RECT  87.539 161.712 88.808 161.736 ;
     RECT  88.508 163.152 88.808 164.856 ;
     RECT  88.453 165.84 88.808 166.536 ;
     RECT  88.453 168.096 88.808 169.416 ;
     RECT  87.325 170.976 88.808 171.576 ;
     RECT  88.808 2.148 88.912 179.292 ;
     RECT  88.912 2.418 89.104 179.022 ;
     RECT  89.104 99.456 89.165 99.48 ;
     RECT  89.104 125.424 89.165 125.448 ;
     RECT  89.104 143.52 89.201 143.832 ;
     RECT  89.104 92.688 89.219 92.712 ;
     RECT  89.104 121.056 89.219 122.76 ;
     RECT  89.104 124.368 89.219 124.392 ;
     RECT  89.219 122.688 89.237 122.712 ;
     RECT  89.104 110.016 89.273 111.432 ;
     RECT  89.104 90.528 89.309 91.464 ;
     RECT  89.104 93.744 89.309 98.472 ;
     RECT  89.104 105.408 89.381 106.008 ;
     RECT  89.201 143.52 89.381 143.544 ;
     RECT  89.309 91.44 89.417 91.464 ;
     RECT  89.104 112.704 89.417 120.072 ;
     RECT  89.219 121.056 89.417 121.416 ;
     RECT  89.309 95.904 89.525 98.472 ;
     RECT  89.525 95.904 89.548 98.376 ;
     RECT  89.309 93.744 89.633 94.872 ;
     RECT  89.633 93.744 89.741 94.68 ;
     RECT  89.417 112.704 89.747 118.68 ;
     RECT  89.417 119.712 89.813 120.072 ;
     RECT  89.548 95.904 89.849 96.84 ;
     RECT  89.104 107.664 89.885 108.696 ;
     RECT  89.104 102.624 89.921 104.376 ;
     RECT  89.747 112.704 89.921 114.6 ;
     RECT  89.747 115.68 89.957 118.68 ;
     RECT  89.273 110.016 89.965 111.144 ;
     RECT  89.548 98.016 89.993 98.376 ;
     RECT  89.957 115.68 90.065 118.632 ;
     RECT  89.849 96.288 90.083 96.84 ;
     RECT  89.381 105.408 90.083 105.432 ;
     RECT  90.083 96.288 90.137 96.312 ;
     RECT  89.993 98.064 90.137 98.376 ;
     RECT  90.137 98.064 90.173 98.136 ;
     RECT  90.065 115.68 90.173 116.232 ;
     RECT  89.885 107.664 90.209 107.832 ;
     RECT  89.921 103.296 90.275 104.376 ;
     RECT  89.965 110.016 90.277 110.568 ;
     RECT  90.275 103.296 90.281 104.088 ;
     RECT  90.065 117.408 90.281 118.632 ;
     RECT  90.229 100.656 90.316 100.68 ;
     RECT  89.921 113.04 90.325 114.6 ;
     RECT  90.284 102.24 90.371 102.264 ;
     RECT  90.209 107.808 90.497 107.832 ;
     RECT  90.325 113.04 90.497 114.024 ;
     RECT  90.524 105.936 90.611 105.96 ;
     RECT  90.173 98.064 90.713 98.088 ;
     RECT  90.497 114 90.821 114.024 ;
     RECT  90.281 103.728 90.929 104.088 ;
     RECT  90.277 108.864 91.001 110.568 ;
     RECT  91.001 108.864 91.052 110.328 ;
     RECT  91.052 108.72 91.139 110.328 ;
     RECT  90.929 103.728 91.289 103.752 ;
     RECT  91.139 109.44 91.289 110.328 ;
     RECT  91.289 109.44 91.865 109.464 ;
     RECT  89.104 153.792 93.197 158.424 ;
     RECT  89.104 32.736 94.208 32.76 ;
     RECT  89.104 36.528 94.208 36.552 ;
     RECT  89.104 39.792 94.208 42.552 ;
     RECT  89.104 60.432 94.208 60.456 ;
     RECT  89.104 77.808 94.208 81.672 ;
     RECT  89.741 93.744 94.208 93.768 ;
     RECT  90.173 116.208 94.208 116.232 ;
     RECT  90.281 118.128 94.208 118.632 ;
     RECT  89.813 120.048 94.208 120.072 ;
     RECT  89.417 121.104 94.208 121.416 ;
     RECT  89.104 134.496 94.208 142.2 ;
     RECT  93.197 153.792 94.208 154.008 ;
     RECT  93.197 155.136 94.208 158.424 ;
     RECT  94.208 2.148 94.312 179.292 ;
     RECT  94.312 2.418 94.504 179.022 ;
     RECT  94.504 155.136 94.565 158.424 ;
     RECT  94.504 121.104 94.673 121.416 ;
     RECT  94.504 32.736 94.709 33.096 ;
     RECT  94.504 93.744 94.883 93.768 ;
     RECT  94.504 116.208 95.429 116.856 ;
     RECT  94.504 77.28 95.459 81.672 ;
     RECT  94.504 118.032 95.468 118.728 ;
     RECT  95.468 117.504 95.564 118.728 ;
     RECT  94.504 120.048 95.564 120.12 ;
     RECT  94.504 38.688 95.641 38.712 ;
     RECT  94.504 36.432 95.681 36.552 ;
     RECT  95.641 38.544 95.747 38.712 ;
     RECT  95.564 117.504 95.747 120.12 ;
     RECT  95.681 36.528 95.785 36.552 ;
     RECT  94.504 60.432 95.789 60.984 ;
     RECT  95.789 60.96 95.825 60.984 ;
     RECT  95.459 77.808 95.897 81.672 ;
     RECT  94.504 153.792 96.041 154.008 ;
     RECT  95.747 117.696 96.181 120.12 ;
     RECT  94.673 121.104 96.181 121.32 ;
     RECT  96.181 117.696 96.275 121.32 ;
     RECT  95.713 35.328 96.365 35.352 ;
     RECT  94.504 134.496 96.437 142.2 ;
     RECT  96.275 117.696 96.508 120.072 ;
     RECT  96.508 118.032 96.611 120.072 ;
     RECT  94.504 39.792 96.689 42.552 ;
     RECT  95.785 36.528 96.829 37.272 ;
     RECT  96.611 119.616 96.833 120.072 ;
     RECT  96.565 123.696 97.009 123.72 ;
     RECT  96.275 121.104 97.013 121.32 ;
     RECT  97.013 121.152 97.045 121.32 ;
     RECT  97.009 123.696 97.049 124.536 ;
     RECT  97.045 121.152 97.129 121.416 ;
     RECT  95.897 80.496 97.157 81.672 ;
     RECT  96.829 36.528 97.265 37.704 ;
     RECT  95.429 116.208 97.477 116.376 ;
     RECT  95.897 77.808 97.549 79.464 ;
     RECT  96.041 153.84 97.589 154.008 ;
     RECT  96.689 39.792 97.841 42.024 ;
     RECT  97.549 77.52 97.873 79.464 ;
     RECT  97.157 80.496 97.873 80.952 ;
     RECT  96.437 141.264 97.981 142.2 ;
     RECT  97.477 116.208 98.089 116.808 ;
     RECT  96.611 118.032 98.089 118.152 ;
     RECT  97.873 77.52 98.099 80.952 ;
     RECT  98.089 116.208 98.149 118.152 ;
     RECT  97.129 121.152 98.197 121.32 ;
     RECT  97.049 124.512 98.197 124.536 ;
     RECT  98.099 77.52 98.237 79.224 ;
     RECT  96.437 134.496 98.273 140.184 ;
     RECT  98.149 116.208 98.305 118.296 ;
     RECT  98.197 124.224 98.339 124.536 ;
     RECT  98.237 77.52 98.345 78.648 ;
     RECT  97.589 153.984 98.345 154.008 ;
     RECT  98.305 115.632 98.377 118.296 ;
     RECT  98.339 124.224 98.38 124.248 ;
     RECT  97.841 39.792 98.453 41.784 ;
     RECT  96.833 119.952 98.453 120.072 ;
     RECT  97.265 37.248 98.485 37.704 ;
     RECT  98.273 134.496 98.489 139.8 ;
     RECT  98.197 121.056 98.521 121.32 ;
     RECT  94.565 155.568 98.561 158.424 ;
     RECT  98.561 155.568 98.579 157.944 ;
     RECT  98.489 134.496 98.593 134.52 ;
     RECT  98.453 39.792 98.597 41.208 ;
     RECT  98.485 36.432 98.773 37.704 ;
     RECT  98.099 80.784 99.061 80.952 ;
     RECT  98.377 115.632 99.205 118.68 ;
     RECT  98.579 155.568 99.269 157.752 ;
     RECT  98.773 36.432 99.313 37.896 ;
     RECT  99.205 115.632 99.445 119.16 ;
     RECT  98.521 120.24 99.445 121.32 ;
     RECT  99.485 34.8 99.493 34.824 ;
     RECT  99.445 115.344 99.493 121.32 ;
     RECT  94.709 32.736 99.608 32.76 ;
     RECT  99.493 33.936 99.608 34.824 ;
     RECT  99.313 36.432 99.608 38.712 ;
     RECT  98.597 39.792 99.608 40.152 ;
     RECT  98.597 41.184 99.608 41.208 ;
     RECT  98.341 76.368 99.608 76.392 ;
     RECT  98.345 77.808 99.608 78.648 ;
     RECT  99.061 80.352 99.608 80.952 ;
     RECT  99.493 115.104 99.608 121.608 ;
     RECT  98.593 134.4 99.608 134.52 ;
     RECT  98.489 136.416 99.608 139.8 ;
     RECT  97.981 141.168 99.608 142.2 ;
     RECT  99.269 155.04 99.608 157.752 ;
     RECT  99.608 2.148 99.712 179.292 ;
     RECT  99.712 2.418 99.904 179.022 ;
     RECT  99.904 76.944 100.045 79.368 ;
     RECT  99.904 155.616 100.433 157.224 ;
     RECT  99.904 114.48 100.505 122.568 ;
     RECT  99.904 36.432 100.835 40.152 ;
     RECT  100.835 36.432 100.909 38.808 ;
     RECT  100.433 155.616 100.909 155.88 ;
     RECT  99.904 75.792 100.933 75.816 ;
     RECT  100.045 76.944 100.933 76.968 ;
     RECT  100.909 155.856 100.937 155.88 ;
     RECT  100.433 157.2 100.937 157.224 ;
     RECT  99.904 34.368 100.969 35.064 ;
     RECT  100.835 39.888 101.045 40.152 ;
     RECT  100.045 78.048 101.077 79.368 ;
     RECT  101.029 80.4 101.077 80.424 ;
     RECT  100.969 34.368 101.149 35.16 ;
     RECT  100.933 75.792 101.149 76.968 ;
     RECT  101.077 78.048 101.149 80.52 ;
     RECT  100.505 114.48 101.149 114.552 ;
     RECT  101.149 75.792 101.18 80.52 ;
     RECT  100.505 115.68 101.219 122.568 ;
     RECT  101.149 40.464 101.233 40.488 ;
     RECT  99.904 136.368 101.257 136.392 ;
     RECT  100.897 137.52 101.257 137.544 ;
     RECT  101.18 75.552 101.267 80.52 ;
     RECT  101.149 114.432 101.267 114.552 ;
     RECT  101.293 134.64 101.329 134.664 ;
     RECT  101.219 115.92 101.333 122.568 ;
     RECT  101.267 114.432 101.363 114.456 ;
     RECT  101.333 121.44 101.363 122.232 ;
     RECT  101.267 76.224 101.411 80.52 ;
     RECT  101.363 121.44 101.411 121.992 ;
     RECT  101.257 136.368 101.437 137.544 ;
     RECT  101.077 138.528 101.437 138.552 ;
     RECT  99.904 139.968 101.437 139.992 ;
     RECT  101.411 76.368 101.459 80.52 ;
     RECT  101.411 121.44 101.459 121.464 ;
     RECT  101.437 136.368 101.581 140.856 ;
     RECT  101.149 34.128 101.977 35.16 ;
     RECT  100.909 36.432 101.977 38.472 ;
     RECT  101.459 76.752 101.977 80.52 ;
     RECT  101.329 134.64 101.977 135.096 ;
     RECT  101.977 134.496 102.517 135.24 ;
     RECT  101.581 136.368 102.517 141.432 ;
     RECT  101.977 34.128 102.553 38.472 ;
     RECT  101.977 76.752 102.553 80.952 ;
     RECT  102.517 134.496 102.553 141.432 ;
     RECT  102.553 34.128 103.644 38.616 ;
     RECT  102.553 76.752 103.644 81.24 ;
     RECT  101.333 115.92 103.644 120.408 ;
     RECT  102.553 134.352 103.644 141.864 ;
    LAYER M5 ;
     RECT  29.52 0.016 52.44 0.563 ;
     RECT  26.064 0.016 28.248 0.611 ;
     RECT  29.664 0.563 52.44 0.611 ;
     RECT  29.808 0.611 52.44 1.235 ;
     RECT  32.4 1.235 46.68 1.715 ;
     RECT  32.4 1.715 38.184 1.763 ;
     RECT  47.664 1.235 52.152 1.763 ;
     RECT  26.208 0.611 28.248 1.811 ;
     RECT  32.4 1.763 35.448 1.811 ;
     RECT  29.808 1.235 31.272 2.137 ;
     RECT  2.4 2.137 2.52 2.151 ;
     RECT  7.8 2.137 7.92 2.151 ;
     RECT  13.2 2.137 13.32 2.151 ;
     RECT  18.6 2.137 18.72 2.151 ;
     RECT  24 2.137 24.12 2.151 ;
     RECT  56.4 2.137 56.52 2.151 ;
     RECT  61.8 2.137 61.92 2.151 ;
     RECT  67.2 2.137 67.32 2.151 ;
     RECT  72.6 2.137 72.72 2.151 ;
     RECT  78 2.137 78.12 2.151 ;
     RECT  83.4 2.137 83.52 2.151 ;
     RECT  88.8 2.137 88.92 2.151 ;
     RECT  94.2 2.137 94.32 2.151 ;
     RECT  99.6 2.137 99.72 2.151 ;
     RECT  26.208 1.811 27.816 2.291 ;
     RECT  29.4 2.137 31.272 2.339 ;
     RECT  32.4 1.811 33.432 2.339 ;
     RECT  50.112 1.763 52.152 2.821 ;
     RECT  36.432 1.763 38.04 2.867 ;
     RECT  29.4 2.339 29.976 2.915 ;
     RECT  42.192 1.715 46.68 2.915 ;
     RECT  47.664 1.763 49.128 2.915 ;
     RECT  37.152 2.867 38.04 2.963 ;
     RECT  26.928 2.291 27.816 3.011 ;
     RECT  31.248 2.339 31.272 3.011 ;
     RECT  39.168 1.715 41.064 3.011 ;
     RECT  48.816 2.915 49.128 3.011 ;
     RECT  50.112 2.821 52.44 3.443 ;
     RECT  25.68 2.821 25.704 3.971 ;
     RECT  50.112 3.443 51.864 4.741 ;
     RECT  29.4 2.915 29.712 5.029 ;
     RECT  26.928 3.011 27.672 5.171 ;
     RECT  50.112 4.741 52.536 5.171 ;
     RECT  32.688 2.339 33.432 5.173 ;
     RECT  34.416 1.811 35.448 5.173 ;
     RECT  48.816 3.011 48.84 5.173 ;
     RECT  25.728 4.501 25.752 5.605 ;
     RECT  32.688 5.173 35.448 5.747 ;
     RECT  43.344 2.915 46.68 5.747 ;
     RECT  51 5.171 52.536 5.747 ;
     RECT  43.488 5.747 46.68 5.795 ;
     RECT  32.832 5.747 35.448 5.987 ;
     RECT  26.928 5.171 27.24 6.323 ;
     RECT  37.44 2.963 38.04 6.323 ;
     RECT  48.816 5.173 49.128 6.323 ;
     RECT  27.216 6.323 27.24 6.371 ;
     RECT  39.168 3.011 40.776 6.419 ;
     RECT  29.4 5.029 29.832 6.659 ;
     RECT  32.832 5.987 33.432 6.899 ;
     RECT  34.416 5.987 35.448 6.899 ;
     RECT  37.44 6.323 37.752 6.899 ;
     RECT  39.168 6.419 39.192 6.899 ;
     RECT  40.2 6.419 40.776 6.899 ;
     RECT  43.488 5.795 43.656 6.899 ;
     RECT  44.64 5.795 46.68 6.899 ;
     RECT  52.512 5.747 52.536 6.899 ;
     RECT  44.64 6.899 45.912 7.139 ;
     RECT  51 5.747 51.312 7.381 ;
     RECT  34.416 6.899 35.112 7.475 ;
     RECT  37.728 6.899 37.752 7.475 ;
     RECT  40.2 6.899 40.632 7.475 ;
     RECT  43.488 6.899 43.512 7.475 ;
     RECT  33.36 11.029 33.384 14.867 ;
     RECT  50.88 7.381 51.312 16.019 ;
     RECT  49.104 6.323 49.128 16.405 ;
     RECT  17.136 5.173 17.16 17.123 ;
     RECT  48.432 16.405 49.128 17.123 ;
     RECT  25.728 5.605 25.8 17.219 ;
     RECT  32.16 12.853 32.184 17.605 ;
     RECT  7.8 2.151 8.112 17.653 ;
     RECT  52.416 7.525 52.44 17.987 ;
     RECT  49.104 17.123 49.128 18.181 ;
     RECT  33.408 15.061 33.432 18.275 ;
     RECT  32.064 17.605 32.184 18.707 ;
     RECT  52.704 18.757 52.728 18.899 ;
     RECT  49.104 18.181 49.416 19.379 ;
     RECT  45.6 7.139 45.912 19.909 ;
     RECT  52.656 19.141 52.68 20.003 ;
     RECT  49.104 19.379 49.128 20.339 ;
     RECT  42.72 20.293 42.744 21.157 ;
     RECT  42.432 21.157 42.744 21.203 ;
     RECT  45.6 19.909 46.68 21.685 ;
     RECT  54.096 20.197 54.12 21.827 ;
     RECT  45.6 21.685 46.776 22.787 ;
     RECT  51 16.019 51.312 22.789 ;
     RECT  50.832 22.789 51.312 23.027 ;
     RECT  53.184 23.317 53.208 24.469 ;
     RECT  51 23.027 51.312 24.517 ;
     RECT  45.6 22.787 46.68 24.563 ;
     RECT  29.4 6.659 29.712 24.997 ;
     RECT  32.064 18.707 32.136 25.043 ;
     RECT  52.944 24.469 53.208 25.139 ;
     RECT  50.784 24.517 51.312 25.427 ;
     RECT  48.096 25.189 48.12 25.909 ;
     RECT  47.76 25.909 48.12 25.955 ;
     RECT  45.6 24.563 46.344 26.101 ;
     RECT  54.48 23.269 54.504 26.243 ;
     RECT  29.088 24.997 29.712 26.627 ;
     RECT  53.184 25.139 53.208 26.725 ;
     RECT  42.432 21.203 42.456 26.869 ;
     RECT  51 25.427 51.312 27.493 ;
     RECT  49.488 26.197 49.512 27.731 ;
     RECT  53.184 26.725 53.496 27.733 ;
     RECT  53.136 27.733 53.496 27.779 ;
     RECT  45.6 26.101 46.44 27.877 ;
     RECT  83.4 2.151 83.712 28.453 ;
     RECT  50.88 27.493 51.312 28.595 ;
     RECT  45.6 27.877 46.68 28.643 ;
     RECT  45.6 28.643 45.912 29.029 ;
     RECT  83.4 28.453 84.36 29.123 ;
     RECT  42.432 26.869 42.648 29.605 ;
     RECT  44.16 21.109 44.184 29.605 ;
     RECT  83.4 29.123 83.976 29.605 ;
     RECT  43.92 29.605 44.184 29.651 ;
     RECT  49.536 28.981 49.56 30.035 ;
     RECT  25.776 17.219 25.8 30.037 ;
     RECT  55.008 26.725 55.032 30.037 ;
     RECT  45.504 29.029 45.912 30.083 ;
     RECT  2.4 2.151 2.712 30.181 ;
     RECT  51 28.595 51.312 30.229 ;
     RECT  53.136 27.779 53.208 30.275 ;
     RECT  83.28 29.605 83.976 30.275 ;
     RECT  50.832 30.229 51.312 30.755 ;
     RECT  5.904 29.029 5.928 30.757 ;
     RECT  54.624 30.037 55.032 30.851 ;
     RECT  45.6 30.083 45.912 30.853 ;
     RECT  2.4 30.181 2.808 30.949 ;
     RECT  42.432 29.605 42.744 31.189 ;
     RECT  47.76 25.955 47.784 31.189 ;
     RECT  47.328 31.189 47.784 31.235 ;
     RECT  4.464 28.981 4.488 31.379 ;
     RECT  5.616 30.757 5.928 31.379 ;
     RECT  40.2 7.475 40.512 31.381 ;
     RECT  53.184 30.275 53.208 31.813 ;
     RECT  53.088 31.813 53.208 31.859 ;
     RECT  7.8 17.653 8.232 32.195 ;
     RECT  54.624 30.851 54.648 32.243 ;
     RECT  2.4 30.949 3.432 32.579 ;
     RECT  99.6 2.151 99.912 32.725 ;
     RECT  83.4 30.275 83.976 32.771 ;
     RECT  43.92 29.651 43.944 33.013 ;
     RECT  94.2 2.151 94.512 33.061 ;
     RECT  0.144 31.957 0.168 33.683 ;
     RECT  25.488 30.037 25.8 33.877 ;
     RECT  41.76 31.189 42.744 34.069 ;
     RECT  43.872 33.013 43.944 34.069 ;
     RECT  45.6 30.853 46.008 34.115 ;
     RECT  51 30.755 51.312 34.117 ;
     RECT  53.088 31.859 53.112 34.165 ;
     RECT  50.88 34.117 51.312 34.691 ;
     RECT  99.504 32.725 99.912 34.835 ;
     RECT  49.152 31.093 49.176 34.931 ;
     RECT  45.6 34.115 45.912 35.509 ;
     RECT  47.328 31.235 47.352 35.509 ;
     RECT  25.488 33.877 25.944 35.941 ;
     RECT  52.704 34.165 53.112 36.469 ;
     RECT  25.488 35.941 26.232 36.515 ;
     RECT  29.28 26.627 29.712 36.515 ;
     RECT  39.552 31.381 40.512 36.517 ;
     RECT  94.2 33.061 94.632 36.563 ;
     RECT  99.6 34.835 99.912 36.661 ;
     RECT  54.816 33.589 54.84 36.851 ;
     RECT  45.6 35.509 47.352 36.949 ;
     RECT  45.6 36.949 47.4 37.043 ;
     RECT  48.528 35.845 48.552 37.043 ;
     RECT  28.128 36.469 28.152 37.379 ;
     RECT  39.168 36.517 40.512 37.381 ;
     RECT  24 2.151 24.312 37.429 ;
     RECT  25.488 36.515 25.512 37.429 ;
     RECT  99.6 36.661 100.872 37.525 ;
     RECT  34.8 7.475 35.112 37.573 ;
     RECT  52.704 36.469 53.448 37.573 ;
     RECT  52.704 37.573 54.12 37.619 ;
     RECT  24 37.429 25.512 37.667 ;
     RECT  34.8 37.573 35.352 37.861 ;
     RECT  36.528 34.789 36.552 37.861 ;
     RECT  52.704 37.619 52.728 37.861 ;
     RECT  52.464 37.861 52.728 37.907 ;
     RECT  2.4 32.579 3.384 38.147 ;
     RECT  7.8 32.195 8.112 38.149 ;
     RECT  5.904 31.379 5.928 38.195 ;
     RECT  34.8 37.861 36.552 38.675 ;
     RECT  38.736 37.381 40.512 38.677 ;
     RECT  41.76 34.069 43.944 38.677 ;
     RECT  72.6 2.151 72.912 38.677 ;
     RECT  52.464 37.907 52.488 38.771 ;
     RECT  34.8 38.675 35.736 38.819 ;
     RECT  47.376 37.043 47.4 39.011 ;
     RECT  38.736 38.677 43.944 39.059 ;
     RECT  33.456 38.197 33.48 39.109 ;
     RECT  33.072 39.109 33.48 39.155 ;
     RECT  49.008 38.149 49.032 39.205 ;
     RECT  49.008 39.205 49.752 39.251 ;
     RECT  6.96 38.149 8.112 39.395 ;
     RECT  34.8 38.819 35.688 39.587 ;
     RECT  54.096 37.619 54.12 39.587 ;
     RECT  38.736 39.059 42.744 39.877 ;
     RECT  49.728 39.251 49.752 39.877 ;
     RECT  24 37.667 25.368 39.923 ;
     RECT  99.6 37.525 101.208 39.923 ;
     RECT  78 2.151 78.312 40.021 ;
     RECT  49.728 39.877 49.896 40.067 ;
     RECT  53.376 39.877 53.592 40.067 ;
     RECT  53.472 40.067 53.592 40.163 ;
     RECT  53.568 40.163 53.592 40.355 ;
     RECT  78 40.021 78.648 40.357 ;
     RECT  77.568 40.357 78.648 40.405 ;
     RECT  43.92 39.059 43.944 40.499 ;
     RECT  101.184 39.923 101.208 40.499 ;
     RECT  72.6 38.677 73.224 40.739 ;
     RECT  38.064 39.877 42.744 40.789 ;
     RECT  36.48 39.877 36.504 40.885 ;
     RECT  83.4 32.771 83.712 40.885 ;
     RECT  38.064 40.789 43.224 40.979 ;
     RECT  83.232 40.885 83.712 40.981 ;
     RECT  88.8 2.151 89.112 40.981 ;
     RECT  34.8 39.587 35.208 41.075 ;
     RECT  82.992 40.981 83.712 41.269 ;
     RECT  77.568 40.405 79.176 41.557 ;
     RECT  82.368 41.269 83.712 41.557 ;
     RECT  88.656 40.981 89.112 41.557 ;
     RECT  88.608 41.557 89.112 41.797 ;
     RECT  88.128 41.797 89.112 42.085 ;
     RECT  94.2 36.563 94.512 42.085 ;
     RECT  95.712 38.533 95.736 42.085 ;
     RECT  6.432 41.221 6.456 42.227 ;
     RECT  77.568 41.557 79.992 42.325 ;
     RECT  36.48 40.885 36.936 42.661 ;
     RECT  34.8 41.075 35.112 42.709 ;
     RECT  36.144 42.661 36.936 42.709 ;
     RECT  38.064 40.979 43.128 42.899 ;
     RECT  33.072 39.155 33.096 42.995 ;
     RECT  77.52 42.325 79.992 43.043 ;
     RECT  32.064 25.043 32.088 43.285 ;
     RECT  38.064 42.899 43.08 43.381 ;
     RECT  77.856 43.043 79.992 43.717 ;
     RECT  77.856 43.717 80.04 43.765 ;
     RECT  77.856 43.765 80.136 43.813 ;
     RECT  81.168 40.405 81.192 43.813 ;
     RECT  38.016 43.381 43.08 43.957 ;
     RECT  31.872 43.285 32.088 44.483 ;
     RECT  34.8 42.709 36.936 44.485 ;
     RECT  38.016 43.957 43.128 45.011 ;
     RECT  30.768 45.541 30.792 46.069 ;
     RECT  32.064 44.483 32.088 46.069 ;
     RECT  29.4 36.515 29.712 46.165 ;
     RECT  30.768 46.069 32.088 46.165 ;
     RECT  29.4 46.165 32.088 46.211 ;
     RECT  20.88 39.877 20.904 47.125 ;
     RECT  20.88 47.125 21.864 47.171 ;
     RECT  29.4 46.211 29.832 47.845 ;
     RECT  33.84 44.485 36.936 48.997 ;
     RECT  21.84 47.171 21.864 49.475 ;
     RECT  31.584 46.211 32.088 49.573 ;
     RECT  38.544 45.011 43.128 49.573 ;
     RECT  19.92 47.845 19.944 49.859 ;
     RECT  29.4 47.845 30.552 50.435 ;
     RECT  38.16 49.573 43.128 50.579 ;
     RECT  31.584 49.573 32.52 50.725 ;
     RECT  38.544 50.579 43.128 52.021 ;
     RECT  25.344 39.923 25.368 52.211 ;
     RECT  33.744 48.997 36.936 52.309 ;
     RECT  38.496 52.021 43.128 52.309 ;
     RECT  24 39.923 24.312 52.405 ;
     RECT  33.744 52.309 43.128 52.547 ;
     RECT  31.584 50.725 32.616 52.691 ;
     RECT  29.4 50.435 29.712 53.125 ;
     RECT  18.6 2.151 18.912 53.509 ;
     RECT  20.544 52.213 20.568 53.603 ;
     RECT  22.224 52.741 22.248 53.651 ;
     RECT  33.744 52.547 43.08 53.941 ;
     RECT  33.744 53.941 43.128 54.085 ;
     RECT  29.4 53.125 30.264 54.133 ;
     RECT  24 52.405 24.408 54.565 ;
     RECT  31.584 52.691 32.52 54.661 ;
     RECT  31.536 54.661 32.52 54.709 ;
     RECT  33.504 54.085 43.128 54.709 ;
     RECT  5.616 53.845 5.64 54.997 ;
     RECT  28.848 54.133 30.264 55.331 ;
     RECT  28.848 55.331 29.712 55.427 ;
     RECT  4.512 54.517 4.536 55.715 ;
     RECT  31.536 54.709 43.128 55.955 ;
     RECT  29.4 55.427 29.712 56.341 ;
     RECT  22.512 54.949 22.536 56.819 ;
     RECT  5.616 54.997 6.408 56.965 ;
     RECT  5.616 56.965 6.6 57.541 ;
     RECT  7.8 39.395 8.112 57.541 ;
     RECT  31.536 55.955 32.52 57.685 ;
     RECT  33.504 55.955 43.128 57.685 ;
     RECT  21.84 58.021 21.864 58.645 ;
     RECT  29.4 56.341 30.264 58.645 ;
     RECT  28.944 58.645 30.264 58.691 ;
     RECT  20.976 58.645 21.864 59.267 ;
     RECT  31.536 57.685 43.128 59.557 ;
     RECT  28.944 58.691 29.712 59.699 ;
     RECT  20.976 59.267 21 60.851 ;
     RECT  94.2 42.085 95.736 60.995 ;
     RECT  31.152 59.557 43.128 60.997 ;
     RECT  29.04 59.699 29.712 61.429 ;
     RECT  30.72 60.997 43.128 61.429 ;
     RECT  29.04 61.429 43.128 61.859 ;
     RECT  21.072 61.573 21.096 62.147 ;
     RECT  24 54.565 24.792 62.147 ;
     RECT  29.4 61.859 43.128 62.195 ;
     RECT  24 62.147 24.648 62.341 ;
     RECT  20.928 62.437 20.952 62.579 ;
     RECT  25.92 58.645 25.944 62.725 ;
     RECT  25.68 62.725 25.944 62.771 ;
     RECT  29.4 62.195 32.088 63.205 ;
     RECT  23.088 62.341 24.648 64.019 ;
     RECT  26.928 62.533 26.952 64.067 ;
     RECT  25.68 62.771 25.704 64.117 ;
     RECT  5.616 57.541 8.112 64.355 ;
     RECT  18.6 53.509 19.368 64.355 ;
     RECT  28.752 63.205 32.088 64.549 ;
     RECT  27.936 64.549 32.088 64.595 ;
     RECT  29.4 64.595 32.088 64.981 ;
     RECT  33.072 62.195 43.128 64.981 ;
     RECT  24 64.019 24.648 65.027 ;
     RECT  29.4 64.981 43.128 65.267 ;
     RECT  27.936 64.595 27.96 65.699 ;
     RECT  25.68 64.117 26.04 66.227 ;
     RECT  29.4 65.267 32.088 66.515 ;
     RECT  30.72 66.515 32.088 66.755 ;
     RECT  28.32 66.661 28.344 67.283 ;
     RECT  24 65.027 24.312 67.333 ;
     RECT  2.4 38.147 2.712 68.149 ;
     RECT  2.256 68.149 2.712 68.291 ;
     RECT  2.4 68.291 2.712 68.341 ;
     RECT  7.488 64.355 8.112 68.629 ;
     RECT  29.4 66.515 29.712 68.821 ;
     RECT  5.616 64.355 6.36 68.917 ;
     RECT  7.392 68.629 8.112 68.917 ;
     RECT  23.376 67.333 24.312 69.011 ;
     RECT  20.064 66.709 20.088 69.443 ;
     RECT  26.016 66.227 26.04 69.493 ;
     RECT  2.4 68.341 3.384 69.733 ;
     RECT  4.704 68.917 8.112 69.733 ;
     RECT  33.072 65.267 43.128 69.971 ;
     RECT  26.016 69.493 26.136 70.021 ;
     RECT  25.776 70.021 26.136 70.067 ;
     RECT  28.464 68.821 29.712 70.645 ;
     RECT  28.464 70.645 29.928 70.739 ;
     RECT  31.008 66.755 32.088 70.981 ;
     RECT  33.072 69.971 36.408 70.981 ;
     RECT  31.008 70.981 36.408 71.315 ;
     RECT  34.464 71.315 36.408 71.411 ;
     RECT  28.128 71.173 28.152 71.843 ;
     RECT  34.704 71.411 36.408 71.891 ;
     RECT  2.4 69.733 8.112 72.419 ;
     RECT  34.8 71.891 36.408 72.469 ;
     RECT  37.488 69.971 43.128 72.469 ;
     RECT  29.4 70.739 29.928 72.563 ;
     RECT  34.8 72.469 43.128 72.611 ;
     RECT  7.248 72.419 8.112 72.851 ;
     RECT  2.4 72.419 6.12 72.995 ;
     RECT  27.36 72.229 27.384 73.571 ;
     RECT  34.8 72.611 36.408 74.053 ;
     RECT  4.416 72.995 6.12 74.147 ;
     RECT  31.008 71.315 33.288 74.147 ;
     RECT  37.488 72.611 43.128 74.197 ;
     RECT  7.296 72.851 8.112 74.629 ;
     RECT  34.512 74.053 36.408 74.675 ;
     RECT  29.4 72.563 29.712 74.725 ;
     RECT  31.008 74.147 32.088 74.725 ;
     RECT  2.4 72.995 2.808 75.155 ;
     RECT  0.144 74.917 0.168 75.203 ;
     RECT  4.416 74.147 6.024 75.299 ;
     RECT  25.776 70.067 26.04 75.349 ;
     RECT  29.4 74.725 32.088 75.397 ;
     RECT  28.944 75.397 32.088 75.443 ;
     RECT  99.6 39.923 99.912 75.781 ;
     RECT  101.232 75.541 101.256 75.781 ;
     RECT  4.416 75.299 4.44 75.875 ;
     RECT  7.152 74.629 8.112 75.971 ;
     RECT  28.944 75.443 31.032 75.973 ;
     RECT  28.224 75.973 31.032 76.163 ;
     RECT  99.6 75.781 101.256 76.213 ;
     RECT  99.6 76.213 101.4 76.357 ;
     RECT  5.616 75.299 6.024 76.403 ;
     RECT  98.352 40.981 98.376 76.403 ;
     RECT  6 76.403 6.024 76.451 ;
     RECT  28.224 76.163 28.248 76.931 ;
     RECT  99.6 76.357 101.448 76.979 ;
     RECT  33.072 74.147 33.288 77.125 ;
     RECT  34.8 74.675 36.408 77.125 ;
     RECT  94.2 60.995 95.448 77.315 ;
     RECT  32.064 75.443 32.088 77.413 ;
     RECT  33.072 77.125 36.408 77.413 ;
     RECT  29.4 76.163 31.032 77.507 ;
     RECT  77.856 43.813 81.192 77.509 ;
     RECT  82.272 41.557 83.712 77.509 ;
     RECT  88.128 42.085 89.976 77.843 ;
     RECT  31.008 77.507 31.032 77.941 ;
     RECT  32.064 77.413 36.408 77.941 ;
     RECT  99.6 76.979 100.008 78.037 ;
     RECT  101.376 76.979 101.448 78.037 ;
     RECT  31.008 77.941 36.408 78.179 ;
     RECT  90.624 78.181 90.648 78.467 ;
     RECT  33.072 78.179 36.408 78.611 ;
     RECT  31.008 78.179 32.088 78.661 ;
     RECT  25.488 75.349 26.04 78.707 ;
     RECT  99.6 78.037 101.448 78.707 ;
     RECT  33.072 78.611 35.736 79.235 ;
     RECT  94.2 77.315 95.16 79.235 ;
     RECT  99.6 78.707 101.064 79.331 ;
     RECT  24 69.011 24.312 79.525 ;
     RECT  25.488 78.707 25.992 79.571 ;
     RECT  25.968 79.571 25.992 79.717 ;
     RECT  33.072 79.235 33.288 79.859 ;
     RECT  23.328 79.525 24.312 80.101 ;
     RECT  29.4 77.507 29.88 80.101 ;
     RECT  28.992 80.101 29.88 80.291 ;
     RECT  30.912 78.661 32.088 80.435 ;
     RECT  86.976 43.285 87 80.435 ;
     RECT  101.04 79.331 101.064 80.435 ;
     RECT  98.064 77.509 98.088 80.819 ;
     RECT  77.856 77.509 83.712 80.963 ;
     RECT  77.856 80.963 79.08 81.107 ;
     RECT  25.968 79.717 26.184 81.347 ;
     RECT  23.328 80.101 24.84 81.349 ;
     RECT  33.264 79.859 33.288 81.349 ;
     RECT  28.992 80.291 29.712 81.445 ;
     RECT  88.128 77.843 89.112 81.539 ;
     RECT  28.992 81.445 29.976 81.589 ;
     RECT  23.04 81.349 24.84 82.021 ;
     RECT  25.968 81.347 25.992 82.021 ;
     RECT  34.8 79.235 35.736 82.069 ;
     RECT  28.992 81.589 30.12 82.211 ;
     RECT  80.784 80.963 83.712 82.259 ;
     RECT  31.344 80.435 32.088 82.453 ;
     RECT  33.168 81.349 33.288 82.453 ;
     RECT  23.04 82.021 25.992 82.597 ;
     RECT  88.656 81.539 89.112 82.691 ;
     RECT  22.176 82.597 25.992 83.267 ;
     RECT  31.344 82.453 33.288 83.267 ;
     RECT  34.8 82.069 35.88 83.269 ;
     RECT  85.728 41.701 85.752 83.749 ;
     RECT  88.8 82.691 89.112 83.749 ;
     RECT  22.176 83.267 22.2 83.843 ;
     RECT  34.8 83.269 36.12 83.845 ;
     RECT  37.392 74.197 43.128 83.845 ;
     RECT  31.344 83.267 32.712 84.083 ;
     RECT  84.816 83.749 85.752 84.181 ;
     RECT  29.4 82.211 30.12 84.325 ;
     RECT  82.512 82.259 83.712 84.325 ;
     RECT  84.816 84.181 86.184 84.325 ;
     RECT  88.56 83.749 89.112 84.325 ;
     RECT  27.696 83.845 27.72 84.419 ;
     RECT  31.392 84.083 32.712 84.565 ;
     RECT  82.512 84.325 86.184 85.139 ;
     RECT  29.4 84.325 30.36 85.427 ;
     RECT  31.392 84.565 33.624 85.523 ;
     RECT  88.32 84.325 89.112 85.619 ;
     RECT  24 83.267 25.992 85.909 ;
     RECT  80.784 82.259 81.48 86.053 ;
     RECT  82.512 85.139 84.84 86.195 ;
     RECT  80.64 86.053 81.48 86.197 ;
     RECT  24 85.909 26.424 86.293 ;
     RECT  23.904 86.293 26.424 86.483 ;
     RECT  86.16 85.139 86.184 86.581 ;
     RECT  77.856 81.107 78.936 86.629 ;
     RECT  88.56 85.619 89.112 86.725 ;
     RECT  77.904 86.629 78.936 86.819 ;
     RECT  28.272 84.805 28.296 87.109 ;
     RECT  29.4 85.427 29.976 87.109 ;
     RECT  24 86.483 26.424 87.157 ;
     RECT  31.392 85.523 32.712 87.251 ;
     RECT  34.8 83.845 43.128 87.301 ;
     RECT  28.272 87.109 29.976 87.445 ;
     RECT  32.688 87.251 32.712 87.733 ;
     RECT  24 87.157 27.144 87.781 ;
     RECT  28.272 87.445 30.12 87.781 ;
     RECT  22.848 86.581 22.872 87.827 ;
     RECT  24 87.781 30.12 87.827 ;
     RECT  84.768 86.195 84.84 87.827 ;
     RECT  86.16 86.581 86.328 87.827 ;
     RECT  27.696 87.827 30.12 88.211 ;
     RECT  84.768 87.827 84.792 88.213 ;
     RECT  87.792 86.725 89.112 88.403 ;
     RECT  27.696 88.211 28.296 88.691 ;
     RECT  18.6 64.355 18.912 88.885 ;
     RECT  31.392 87.251 31.416 88.885 ;
     RECT  32.688 87.733 32.952 88.885 ;
     RECT  82.512 86.195 83.712 88.885 ;
     RECT  84.72 88.213 84.792 88.885 ;
     RECT  34.176 87.301 43.128 88.979 ;
     RECT  31.392 88.885 32.952 89.555 ;
     RECT  82.512 88.885 84.792 89.701 ;
     RECT  21.408 87.685 21.432 90.083 ;
     RECT  31.584 89.555 32.952 90.083 ;
     RECT  18.6 88.885 19.848 90.419 ;
     RECT  28.128 88.691 28.296 90.515 ;
     RECT  88.56 88.403 89.112 90.659 ;
     RECT  18.6 90.419 18.912 91.141 ;
     RECT  88.704 90.659 89.112 91.429 ;
     RECT  32.688 90.083 32.952 91.717 ;
     RECT  22.608 91.093 22.632 91.763 ;
     RECT  18.48 91.141 18.912 91.907 ;
     RECT  24 87.827 26.424 91.909 ;
     RECT  86.16 87.827 86.184 92.869 ;
     RECT  28.272 90.515 28.296 92.917 ;
     RECT  23.088 91.909 26.424 92.963 ;
     RECT  80.592 86.197 81.48 92.963 ;
     RECT  82.512 89.701 84.888 92.963 ;
     RECT  18.6 91.907 18.912 93.253 ;
     RECT  19.92 91.765 19.944 93.253 ;
     RECT  18.6 93.253 19.944 93.299 ;
     RECT  86.16 92.869 87.096 93.443 ;
     RECT  31.584 90.083 31.608 93.493 ;
     RECT  32.64 91.717 32.952 93.493 ;
     RECT  80.592 92.963 81.24 93.539 ;
     RECT  94.2 79.235 94.872 93.779 ;
     RECT  34.8 88.979 43.128 94.115 ;
     RECT  86.16 93.443 86.184 94.165 ;
     RECT  23.136 92.963 26.424 94.405 ;
     RECT  87.456 94.453 87.48 94.549 ;
     RECT  31.584 93.493 32.952 94.595 ;
     RECT  88.704 91.429 89.208 94.595 ;
     RECT  88.704 94.595 89.112 94.645 ;
     RECT  82.608 92.963 84.888 94.837 ;
     RECT  32.544 94.595 32.952 95.123 ;
     RECT  34.8 94.115 37.608 95.125 ;
     RECT  82.128 94.837 84.888 95.125 ;
     RECT  86.112 94.165 86.184 95.125 ;
     RECT  87.312 94.549 87.48 95.125 ;
     RECT  34.656 95.125 37.608 95.171 ;
     RECT  29.4 88.211 30.12 95.173 ;
     RECT  78 86.819 78.936 95.219 ;
     RECT  38.64 94.115 43.128 95.363 ;
     RECT  80.592 93.539 80.76 95.653 ;
     RECT  82.128 95.125 87.48 95.653 ;
     RECT  18.6 93.299 19.416 95.701 ;
     RECT  27.888 92.917 28.296 95.749 ;
     RECT  29.4 95.173 30.888 95.749 ;
     RECT  27.888 95.749 30.888 95.795 ;
     RECT  80.592 95.653 87.48 96.181 ;
     RECT  80.352 96.181 87.48 96.371 ;
     RECT  34.656 95.171 37.128 96.419 ;
     RECT  18.6 95.701 19.656 96.805 ;
     RECT  88.608 94.645 89.112 96.805 ;
     RECT  22.848 94.405 26.424 96.853 ;
     RECT  88.608 96.805 90.072 96.947 ;
     RECT  28.272 95.795 30.888 96.995 ;
     RECT  80.352 96.371 87 96.995 ;
     RECT  22.848 96.853 26.52 97.379 ;
     RECT  82.128 96.995 87 97.379 ;
     RECT  80.352 96.995 80.952 98.005 ;
     RECT  82.128 97.379 84.888 98.005 ;
     RECT  85.968 97.379 87 98.053 ;
     RECT  88.704 96.947 90.072 98.053 ;
     RECT  18.48 96.805 19.656 98.099 ;
     RECT  85.968 98.053 90.072 98.147 ;
     RECT  80.352 98.005 84.888 98.581 ;
     RECT  85.968 98.147 89.496 98.581 ;
     RECT  80.352 98.581 89.496 98.675 ;
     RECT  23.76 97.379 26.52 98.773 ;
     RECT  80.352 98.675 80.952 98.963 ;
     RECT  23.76 98.773 26.664 99.061 ;
     RECT  18.48 98.099 18.912 99.157 ;
     RECT  28.272 96.995 29.976 99.203 ;
     RECT  23.76 99.061 27.096 99.685 ;
     RECT  34.8 96.419 37.128 99.685 ;
     RECT  82.032 98.675 87.576 99.685 ;
     RECT  88.56 98.675 89.496 99.685 ;
     RECT  17.664 99.157 18.912 100.211 ;
     RECT  82.032 99.685 89.496 100.259 ;
     RECT  82.176 100.259 89.496 100.645 ;
     RECT  31.344 99.685 31.368 100.739 ;
     RECT  23.376 99.685 27.096 100.741 ;
     RECT  23.376 100.741 27.288 100.885 ;
     RECT  28.272 99.203 28.296 100.885 ;
     RECT  20.88 99.157 20.904 100.931 ;
     RECT  23.376 100.885 28.296 100.933 ;
     RECT  34.464 99.685 37.128 101.605 ;
     RECT  80.352 98.963 80.712 101.941 ;
     RECT  23.04 100.933 28.296 102.229 ;
     RECT  29.4 99.203 29.976 102.229 ;
     RECT  82.176 100.645 90.264 102.229 ;
     RECT  23.04 102.229 29.976 102.613 ;
     RECT  22.512 102.613 29.976 102.659 ;
     RECT  34.032 101.605 37.128 103.235 ;
     RECT  18.48 100.211 18.912 103.283 ;
     RECT  80.352 101.941 81.192 103.621 ;
     RECT  82.176 102.229 90.36 103.621 ;
     RECT  28.272 102.659 29.712 103.715 ;
     RECT  28.416 103.715 29.712 103.861 ;
     RECT  80.352 103.621 90.36 103.957 ;
     RECT  28.416 103.861 29.976 104.531 ;
     RECT  22.512 102.659 27.096 104.915 ;
     RECT  18.6 103.283 18.912 105.397 ;
     RECT  21.312 102.805 21.336 105.491 ;
     RECT  34.8 103.235 37.128 105.973 ;
     RECT  29.232 104.531 29.976 106.019 ;
     RECT  80.352 103.957 90.6 106.597 ;
     RECT  80.208 106.597 90.6 106.691 ;
     RECT  29.232 106.019 29.712 106.981 ;
     RECT  18.6 105.397 19.464 107.125 ;
     RECT  21.264 105.733 21.288 107.125 ;
     RECT  29.184 106.981 29.712 107.125 ;
     RECT  34.656 105.973 37.128 107.219 ;
     RECT  29.184 107.125 29.928 107.411 ;
     RECT  29.232 107.411 29.928 107.507 ;
     RECT  18.6 107.125 21.288 107.555 ;
     RECT  18.6 107.555 20.376 107.795 ;
     RECT  80.208 106.691 81.672 107.893 ;
     RECT  82.656 106.691 90.6 107.893 ;
     RECT  80.208 107.893 90.6 108.179 ;
     RECT  22.848 104.915 27.096 108.323 ;
     RECT  80.352 108.179 90.6 108.709 ;
     RECT  80.352 108.709 91.128 108.899 ;
     RECT  31.344 105.397 31.368 109.427 ;
     RECT  32.688 95.123 32.952 109.475 ;
     RECT  88.8 108.899 91.128 109.475 ;
     RECT  29.28 107.507 29.928 109.765 ;
     RECT  34.8 107.219 37.128 109.955 ;
     RECT  28.512 109.765 29.928 109.957 ;
     RECT  18.6 107.795 18.912 110.005 ;
     RECT  20.352 107.795 20.376 110.341 ;
     RECT  34.8 109.955 35.784 110.341 ;
     RECT  80.352 108.899 87.576 110.437 ;
     RECT  18.288 110.005 18.912 110.579 ;
     RECT  28.512 109.957 30.792 110.627 ;
     RECT  34.464 110.341 35.784 110.773 ;
     RECT  32.736 109.475 32.952 111.109 ;
     RECT  20.112 110.341 20.376 111.397 ;
     RECT  19.968 111.397 20.376 111.443 ;
     RECT  23.328 108.323 27.096 111.589 ;
     RECT  80.256 110.437 87.576 111.683 ;
     RECT  23.184 111.589 27.096 111.779 ;
     RECT  29.4 110.627 30.792 111.971 ;
     RECT  18.6 110.579 18.912 112.117 ;
     RECT  21.648 108.853 21.672 112.355 ;
     RECT  23.184 111.779 26.664 112.499 ;
     RECT  32.352 111.109 32.952 112.499 ;
     RECT  19.968 111.443 20.136 112.643 ;
     RECT  23.328 112.499 26.664 112.835 ;
     RECT  18.48 112.117 18.912 112.883 ;
     RECT  38.64 95.363 43.08 112.883 ;
     RECT  82.464 111.683 87.576 112.883 ;
     RECT  38.736 112.883 42.456 112.931 ;
     RECT  80.256 111.683 81.288 113.029 ;
     RECT  82.464 112.883 84.888 113.029 ;
     RECT  88.8 109.475 90.312 113.269 ;
     RECT  85.92 112.883 87.576 113.365 ;
     RECT  88.608 113.269 90.312 113.365 ;
     RECT  85.92 113.365 90.312 113.459 ;
     RECT  32.736 112.499 32.952 113.989 ;
     RECT  32.736 113.989 33.048 114.035 ;
     RECT  29.4 111.971 30.552 114.373 ;
     RECT  31.632 114.277 31.656 114.373 ;
     RECT  99.6 79.331 99.912 114.469 ;
     RECT  80.256 113.029 84.888 114.517 ;
     RECT  86.352 113.459 90.312 114.517 ;
     RECT  99.6 114.469 100.248 114.517 ;
     RECT  101.328 114.421 101.352 114.517 ;
     RECT  19.968 112.643 19.992 114.611 ;
     RECT  20.976 114.373 21 114.611 ;
     RECT  80.256 114.517 90.312 114.611 ;
     RECT  23.616 112.835 26.664 114.805 ;
     RECT  34.368 110.773 35.784 115.093 ;
     RECT  38.976 112.931 42.456 115.093 ;
     RECT  99.6 114.517 101.352 115.093 ;
     RECT  80.256 114.611 89.928 115.139 ;
     RECT  99.504 115.093 101.352 115.333 ;
     RECT  80.592 115.139 89.928 115.379 ;
     RECT  29.4 114.373 31.656 115.429 ;
     RECT  38.832 115.093 42.456 115.669 ;
     RECT  99.456 115.333 101.352 115.669 ;
     RECT  32.928 114.035 33.048 115.717 ;
     RECT  34.272 115.093 35.784 115.717 ;
     RECT  80.592 115.379 85.416 115.763 ;
     RECT  99.36 115.669 101.352 116.099 ;
     RECT  23.184 114.805 26.664 116.195 ;
     RECT  78 95.219 78.312 116.197 ;
     RECT  24 116.195 26.664 116.293 ;
     RECT  27.648 114.181 27.672 116.293 ;
     RECT  24 116.293 27.672 116.339 ;
     RECT  96.48 116.245 96.504 116.341 ;
     RECT  99.36 116.099 101.256 116.531 ;
     RECT  32.928 115.717 35.784 116.821 ;
     RECT  36.864 109.955 37.128 116.821 ;
     RECT  94.2 93.779 94.512 116.821 ;
     RECT  95.52 116.341 96.504 116.821 ;
     RECT  98.16 116.773 98.184 116.821 ;
     RECT  99.36 116.531 101.208 116.821 ;
     RECT  80.592 115.763 85.176 116.965 ;
     RECT  29.088 115.429 31.656 117.011 ;
     RECT  80.592 116.965 85.272 117.013 ;
     RECT  32.928 116.821 37.128 117.349 ;
     RECT  86.448 115.379 89.928 117.397 ;
     RECT  98.16 116.821 101.208 117.397 ;
     RECT  32.928 117.349 37.656 117.443 ;
     RECT  98.112 117.397 101.208 117.443 ;
     RECT  29.4 117.011 31.656 117.493 ;
     RECT  24 116.339 27.384 117.781 ;
     RECT  36.864 117.443 37.656 117.781 ;
     RECT  23.616 117.781 27.384 118.067 ;
     RECT  78 116.197 78.936 118.117 ;
     RECT  80.208 117.013 85.272 118.117 ;
     RECT  86.448 117.397 89.976 118.355 ;
     RECT  32.928 117.443 35.784 118.501 ;
     RECT  36.864 117.781 37.704 118.501 ;
     RECT  94.2 116.821 96.504 118.549 ;
     RECT  86.448 118.355 89.928 118.595 ;
     RECT  86.688 118.595 89.928 118.643 ;
     RECT  86.688 118.643 89.112 118.739 ;
     RECT  98.112 117.443 100.392 118.741 ;
     RECT  101.424 117.637 101.448 118.741 ;
     RECT  38.832 115.669 43.128 119.029 ;
     RECT  29.4 117.493 31.704 119.077 ;
     RECT  23.616 118.067 26.664 119.459 ;
     RECT  94.2 118.549 96.6 119.653 ;
     RECT  86.688 118.739 87.384 119.699 ;
     RECT  29.04 119.077 31.704 119.747 ;
     RECT  29.4 119.747 31.704 120.133 ;
     RECT  32.928 118.501 37.704 120.179 ;
     RECT  23.616 119.459 26.376 120.757 ;
     RECT  36.864 120.179 37.704 120.805 ;
     RECT  38.688 119.029 43.128 120.805 ;
     RECT  88.368 118.739 89.112 121.141 ;
     RECT  29.4 120.133 31.896 121.331 ;
     RECT  94.2 119.653 96.648 121.381 ;
     RECT  23.232 120.757 26.376 121.475 ;
     RECT  98.112 118.741 101.448 121.475 ;
     RECT  32.928 120.179 35.784 121.813 ;
     RECT  98.112 121.475 101.4 122.003 ;
     RECT  88.368 121.141 89.208 122.099 ;
     RECT  98.112 122.003 101.352 122.243 ;
     RECT  21.072 121.381 21.096 122.339 ;
     RECT  23.616 121.475 26.376 122.339 ;
     RECT  27.936 121.381 27.96 122.341 ;
     RECT  29.4 121.331 31.656 122.341 ;
     RECT  86.736 119.699 87.384 123.061 ;
     RECT  27.936 122.341 31.656 123.107 ;
     RECT  32.928 121.813 35.832 123.155 ;
     RECT  24 122.339 26.376 123.829 ;
     RECT  23.808 123.829 26.376 123.971 ;
     RECT  36.864 120.805 43.128 124.021 ;
     RECT  88.656 122.099 89.208 124.403 ;
     RECT  78 118.117 85.272 124.789 ;
     RECT  78 124.789 85.512 124.933 ;
     RECT  86.688 123.061 87.384 124.979 ;
     RECT  23.808 123.971 24.84 125.123 ;
     RECT  36.768 124.021 43.128 125.123 ;
     RECT  88.656 124.403 89.112 125.411 ;
     RECT  78 124.933 85.608 125.459 ;
     RECT  24 125.123 24.84 125.843 ;
     RECT  22.224 124.837 22.248 126.035 ;
     RECT  87.12 124.979 87.384 126.229 ;
     RECT  25.824 123.971 26.376 126.611 ;
     RECT  32.928 123.155 35.784 126.661 ;
     RECT  78 125.459 80.664 126.709 ;
     RECT  77.76 126.709 80.664 126.805 ;
     RECT  32.64 126.661 35.784 127.139 ;
     RECT  24 125.843 24.408 127.235 ;
     RECT  25.968 126.611 25.992 127.523 ;
     RECT  81.84 125.459 85.608 127.573 ;
     RECT  81.84 127.573 85.848 127.669 ;
     RECT  32.928 127.139 35.784 128.197 ;
     RECT  87.12 126.229 87.528 129.107 ;
     RECT  76.992 126.805 80.664 129.253 ;
     RECT  81.84 127.669 85.944 129.253 ;
     RECT  28.704 123.107 31.656 130.501 ;
     RECT  76.992 129.253 85.944 131.077 ;
     RECT  87.12 129.107 87.336 131.077 ;
     RECT  28.704 130.501 31.704 132.227 ;
     RECT  76.992 131.077 87.336 132.851 ;
     RECT  87.12 132.851 87.336 133.045 ;
     RECT  88.8 125.411 89.112 133.045 ;
     RECT  28.704 132.227 31.656 134.051 ;
     RECT  29.4 134.051 31.656 134.101 ;
     RECT  87.12 133.045 89.112 134.387 ;
     RECT  32.784 128.197 35.784 134.485 ;
     RECT  36.864 125.123 43.128 134.485 ;
     RECT  32.784 134.485 43.128 134.675 ;
     RECT  76.992 132.851 85.944 135.491 ;
     RECT  81.072 135.491 85.944 135.493 ;
     RECT  87.12 134.387 87.48 135.493 ;
     RECT  32.784 134.675 43.08 135.973 ;
     RECT  81.072 135.493 87.48 135.973 ;
     RECT  81.072 135.973 87.816 136.165 ;
     RECT  88.8 134.387 89.112 136.165 ;
     RECT  76.992 135.491 79.752 137.605 ;
     RECT  76.992 137.605 80.04 138.613 ;
     RECT  81.072 136.165 89.112 138.613 ;
     RECT  29.4 134.101 31.752 138.997 ;
     RECT  32.784 135.973 43.128 138.997 ;
     RECT  76.992 138.613 89.112 139.235 ;
     RECT  81.84 139.235 89.112 141.971 ;
     RECT  29.4 138.997 43.128 142.115 ;
     RECT  76.992 139.235 80.424 145.333 ;
     RECT  29.4 142.115 30.552 146.149 ;
     RECT  31.728 142.115 43.128 146.149 ;
     RECT  81.84 141.971 85.944 146.149 ;
     RECT  87.024 141.971 89.112 146.149 ;
     RECT  76.992 145.333 80.856 147.301 ;
     RECT  81.84 146.149 89.112 147.301 ;
     RECT  29.4 146.149 43.128 148.067 ;
     RECT  76.992 147.301 89.112 148.307 ;
     RECT  31.728 148.067 43.128 148.355 ;
     RECT  76.992 148.307 85.944 148.595 ;
     RECT  80.832 148.595 85.944 149.413 ;
     RECT  31.728 148.355 31.752 149.939 ;
     RECT  80.832 149.413 85.992 150.275 ;
     RECT  29.4 148.067 30.552 150.421 ;
     RECT  29.4 150.421 31.368 151.045 ;
     RECT  29.4 151.045 31.704 151.091 ;
     RECT  76.992 148.595 79.848 151.429 ;
     RECT  80.88 150.275 85.992 151.429 ;
     RECT  31.68 151.091 31.704 151.907 ;
     RECT  76.992 151.429 85.992 152.581 ;
     RECT  87.024 148.307 89.112 152.581 ;
     RECT  32.832 148.355 43.128 152.627 ;
     RECT  76.992 152.581 89.112 153.539 ;
     RECT  32.928 152.627 43.128 153.637 ;
     RECT  76.992 153.539 85.944 153.685 ;
     RECT  76.896 153.685 85.944 153.829 ;
     RECT  76.656 153.829 85.944 153.923 ;
     RECT  32.928 153.637 44.232 154.165 ;
     RECT  45.6 37.043 45.912 154.165 ;
     RECT  81.744 153.923 85.944 154.259 ;
     RECT  51 34.691 51.312 154.261 ;
     RECT  50.88 154.261 51.312 154.309 ;
     RECT  32.928 154.165 45.912 154.355 ;
     RECT  33.504 154.355 45.912 154.499 ;
     RECT  85.728 154.259 85.944 154.595 ;
     RECT  85.92 154.595 85.944 154.981 ;
     RECT  87.024 153.539 89.112 154.981 ;
     RECT  31.728 153.301 31.752 155.075 ;
     RECT  81.744 154.259 84.744 155.459 ;
     RECT  50.88 154.309 51.576 155.651 ;
     RECT  98.112 122.243 100.872 155.651 ;
     RECT  71.568 155.797 71.592 156.037 ;
     RECT  53.664 155.941 53.688 156.085 ;
     RECT  53.568 156.085 53.688 156.131 ;
     RECT  61.8 2.151 62.112 156.133 ;
     RECT  85.92 154.981 89.112 156.179 ;
     RECT  81.744 155.459 84.6 156.227 ;
     RECT  74.688 156.181 74.712 156.371 ;
     RECT  81.744 156.227 84.264 156.515 ;
     RECT  53.568 156.131 53.592 156.613 ;
     RECT  86.304 156.179 89.112 156.803 ;
     RECT  98.112 155.651 98.616 156.803 ;
     RECT  99.6 155.651 100.392 156.803 ;
     RECT  50.88 155.651 51.312 157.283 ;
     RECT  76.656 153.923 80.664 157.283 ;
     RECT  94.2 121.381 97.08 157.379 ;
     RECT  98.112 156.803 98.568 157.379 ;
     RECT  87.024 156.803 89.112 157.427 ;
     RECT  53.52 156.613 53.592 157.523 ;
     RECT  76.944 157.283 80.664 157.525 ;
     RECT  81.744 156.515 82.392 157.525 ;
     RECT  76.944 157.525 82.392 157.811 ;
     RECT  53.568 157.523 53.592 157.859 ;
     RECT  76.944 157.811 82.344 157.859 ;
     RECT  59.616 156.037 59.64 157.907 ;
     RECT  61.536 156.133 62.112 157.907 ;
     RECT  34.368 154.499 45.912 157.955 ;
     RECT  96.288 157.379 96.504 157.955 ;
     RECT  98.544 157.379 98.568 157.955 ;
     RECT  76.944 157.859 80.664 158.579 ;
     RECT  34.368 157.955 35.112 158.629 ;
     RECT  81.744 157.859 82.344 158.821 ;
     RECT  83.4 156.515 84.264 158.821 ;
     RECT  81.744 158.821 84.264 159.155 ;
     RECT  82.32 159.155 84.264 159.635 ;
     RECT  34.224 158.629 35.112 159.637 ;
     RECT  36.432 157.955 45.912 159.637 ;
     RECT  83.232 159.635 84.264 159.637 ;
     RECT  87.504 157.427 89.112 159.925 ;
     RECT  83.232 159.637 84.504 159.971 ;
     RECT  34.224 159.637 45.912 160.211 ;
     RECT  83.4 159.971 84.504 161.123 ;
     RECT  34.32 160.211 45.912 161.363 ;
     RECT  41.52 161.363 45.912 161.555 ;
     RECT  86.832 159.925 89.112 161.699 ;
     RECT  34.32 161.363 40.512 161.939 ;
     RECT  77.232 158.579 80.664 162.469 ;
     RECT  81.648 160.693 81.672 162.469 ;
     RECT  41.568 161.555 45.912 162.515 ;
     RECT  77.232 162.469 81.672 162.515 ;
     RECT  83.4 161.123 84.408 162.515 ;
     RECT  83.4 162.515 84.36 162.611 ;
     RECT  85.584 160.693 85.608 162.613 ;
     RECT  86.832 161.699 86.856 162.613 ;
     RECT  85.584 162.613 86.856 162.659 ;
     RECT  39.072 161.939 40.512 163.619 ;
     RECT  86.016 162.659 86.856 164.195 ;
     RECT  39.888 163.619 40.512 164.629 ;
     RECT  77.232 162.515 81.336 164.771 ;
     RECT  77.232 164.771 81.288 165.203 ;
     RECT  34.368 161.939 38.04 165.347 ;
     RECT  34.368 165.347 37.128 165.635 ;
     RECT  41.952 162.515 45.912 165.829 ;
     RECT  46.944 165.301 46.968 165.829 ;
     RECT  83.4 162.611 84.264 165.829 ;
     RECT  32.688 158.389 32.712 165.923 ;
     RECT  83.4 165.829 85.08 165.923 ;
     RECT  85.056 165.923 85.08 166.117 ;
     RECT  86.832 164.195 86.856 166.165 ;
     RECT  71.52 156.037 71.592 166.429 ;
     RECT  39.888 164.629 40.92 166.451 ;
     RECT  83.4 165.923 83.712 166.645 ;
     RECT  77.76 165.203 81.288 166.691 ;
     RECT  85.056 166.117 85.32 166.691 ;
     RECT  81.264 166.691 81.288 167.075 ;
     RECT  85.056 166.691 85.08 167.075 ;
     RECT  83.28 166.645 83.712 167.509 ;
     RECT  39.984 166.451 40.92 167.557 ;
     RECT  77.76 166.691 79.992 167.651 ;
     RECT  39.888 167.557 40.92 168.085 ;
     RECT  86.304 166.165 86.856 168.323 ;
     RECT  71.52 166.429 71.544 168.563 ;
     RECT  32.832 166.741 32.856 168.661 ;
     RECT  80.928 168.181 80.952 168.755 ;
     RECT  39.84 168.085 40.92 169.333 ;
     RECT  83.184 167.509 83.712 169.379 ;
     RECT  86.448 168.323 86.856 169.379 ;
     RECT  32.544 168.661 32.856 169.907 ;
     RECT  77.76 167.651 79.704 169.907 ;
     RECT  39.264 169.333 40.92 170.053 ;
     RECT  39.264 170.053 40.968 170.293 ;
     RECT  41.952 165.829 46.968 170.293 ;
     RECT  34.368 165.635 36.168 170.675 ;
     RECT  84.768 169.909 84.792 170.867 ;
     RECT  34.56 170.675 36.168 170.965 ;
     RECT  88.032 161.699 89.112 171.011 ;
     RECT  81.744 169.813 81.768 171.491 ;
     RECT  86.832 169.379 86.856 171.491 ;
     RECT  38.064 170.437 38.088 171.539 ;
     RECT  32.832 169.907 32.856 171.541 ;
     RECT  32.784 171.541 32.856 171.877 ;
     RECT  34.56 170.965 37.032 172.693 ;
     RECT  39.264 170.293 46.968 172.739 ;
     RECT  32.784 171.877 33 172.789 ;
     RECT  39.648 172.739 46.968 172.883 ;
     RECT  34.512 172.693 37.032 173.219 ;
     RECT  84.912 172.645 84.936 173.507 ;
     RECT  32.208 172.789 33 173.699 ;
     RECT  34.56 173.219 37.032 173.797 ;
     RECT  39.696 172.883 46.968 173.891 ;
     RECT  78 169.907 79.512 173.987 ;
     RECT  32.208 173.699 32.232 174.181 ;
     RECT  34.56 173.797 37.848 174.421 ;
     RECT  79.488 173.987 79.512 174.467 ;
     RECT  34.56 174.421 38.232 174.563 ;
     RECT  29.4 151.091 30.552 174.661 ;
     RECT  31.824 174.181 32.232 174.661 ;
     RECT  29.4 174.661 32.232 174.707 ;
     RECT  34.56 174.563 36.888 175.043 ;
     RECT  29.4 174.707 31.368 175.619 ;
     RECT  32.688 174.949 32.712 175.861 ;
     RECT  39.696 173.891 46.392 176.195 ;
     RECT  32.688 175.861 33.672 176.485 ;
     RECT  34.8 175.043 36.888 176.485 ;
     RECT  38.208 174.563 38.232 176.485 ;
     RECT  38.208 176.485 38.664 176.677 ;
     RECT  42.048 176.195 46.392 176.723 ;
     RECT  29.4 175.619 30.312 176.771 ;
     RECT  38.016 176.677 38.664 177.299 ;
     RECT  39.696 176.195 41.016 177.299 ;
     RECT  32.688 176.485 36.888 177.347 ;
     RECT  32.688 177.347 36.84 177.829 ;
     RECT  29.4 176.771 29.712 178.357 ;
     RECT  38.016 177.299 38.328 178.357 ;
     RECT  42.048 176.723 46.344 178.451 ;
     RECT  29.4 178.357 30.552 178.933 ;
     RECT  31.968 177.829 36.84 178.981 ;
     RECT  37.872 178.357 38.328 178.981 ;
     RECT  39.744 177.299 41.016 178.981 ;
     RECT  31.968 178.981 41.016 179.077 ;
     RECT  2.4 75.155 2.712 179.289 ;
     RECT  7.8 75.971 8.112 179.289 ;
     RECT  13.2 2.151 13.512 179.289 ;
     RECT  18.6 112.883 18.912 179.289 ;
     RECT  24 127.235 24.312 179.289 ;
     RECT  29.4 178.933 30.696 179.289 ;
     RECT  42.048 178.451 45.912 179.289 ;
     RECT  51 157.283 51.312 179.289 ;
     RECT  56.4 2.151 56.712 179.289 ;
     RECT  61.8 157.907 62.112 179.289 ;
     RECT  67.2 2.151 67.512 179.289 ;
     RECT  72.6 40.739 72.912 179.289 ;
     RECT  78 173.987 78.312 179.289 ;
     RECT  83.4 169.379 83.712 179.289 ;
     RECT  88.8 171.011 89.112 179.289 ;
     RECT  94.2 157.379 94.512 179.289 ;
     RECT  99.6 156.803 99.912 179.289 ;
     RECT  2.4 179.289 2.52 179.303 ;
     RECT  7.8 179.289 7.92 179.303 ;
     RECT  13.2 179.289 13.32 179.303 ;
     RECT  18.6 179.289 18.72 179.303 ;
     RECT  24 179.289 24.12 179.303 ;
     RECT  29.4 179.289 29.52 179.303 ;
     RECT  42.048 179.289 45.72 179.303 ;
     RECT  51 179.289 51.12 179.303 ;
     RECT  56.4 179.289 56.52 179.303 ;
     RECT  61.8 179.289 61.92 179.303 ;
     RECT  67.2 179.289 67.32 179.303 ;
     RECT  72.6 179.289 72.72 179.303 ;
     RECT  78 179.289 78.12 179.303 ;
     RECT  83.4 179.289 83.52 179.303 ;
     RECT  88.8 179.289 88.92 179.303 ;
     RECT  94.2 179.289 94.32 179.303 ;
     RECT  99.6 179.289 99.72 179.303 ;
     RECT  30.528 179.289 30.696 179.509 ;
     RECT  31.68 179.077 41.016 179.509 ;
     RECT  42.048 179.303 45.24 179.509 ;
     RECT  30.528 179.509 45.24 181.392 ;
  END
END ot_coll_split_c
END LIBRARY
